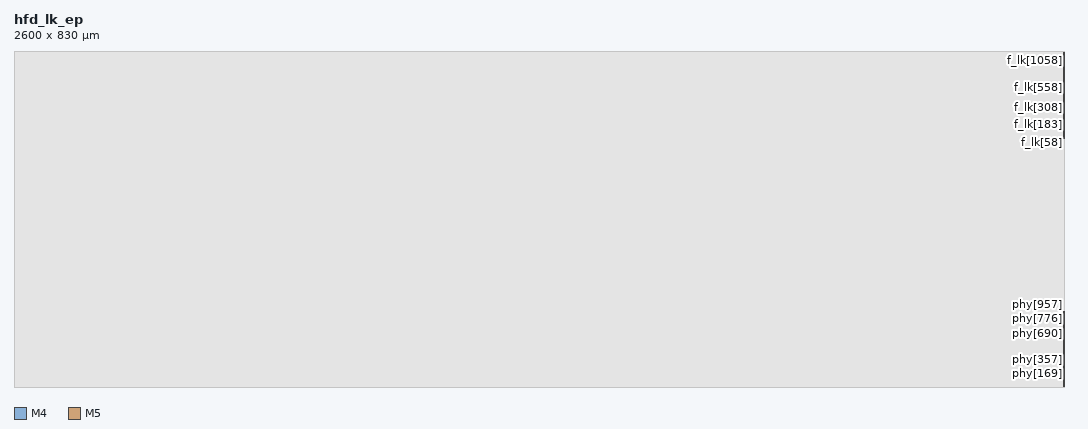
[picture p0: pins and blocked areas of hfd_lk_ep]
MACRO hfd_lk_ep
  CLASS BLOCK ;
  FOREIGN hfd_lk_ep 0 0 ;
  SIZE 2600.000 BY 830.000 ;
  SYMMETRY X Y ;
  PIN phy[0]
    DIRECTION INOUT ;
    USE SIGNAL ;
    PORT
      LAYER M4 ;
        RECT 2599.808 0.624 2600.000 0.648 ;
    END
  END phy[0]
  PIN phy[1]
    DIRECTION INOUT ;
    USE SIGNAL ;
    PORT
      LAYER M4 ;
        RECT 2599.808 0.816 2600.000 0.840 ;
    END
  END phy[1]
  PIN phy[2]
    DIRECTION INOUT ;
    USE SIGNAL ;
    PORT
      LAYER M4 ;
        RECT 2599.808 1.008 2600.000 1.032 ;
    END
  END phy[2]
  PIN phy[3]
    DIRECTION INOUT ;
    USE SIGNAL ;
    PORT
      LAYER M4 ;
        RECT 2599.808 1.200 2600.000 1.224 ;
    END
  END phy[3]
  PIN phy[4]
    DIRECTION INOUT ;
    USE SIGNAL ;
    PORT
      LAYER M4 ;
        RECT 2599.808 1.392 2600.000 1.416 ;
    END
  END phy[4]
  PIN phy[5]
    DIRECTION INOUT ;
    USE SIGNAL ;
    PORT
      LAYER M4 ;
        RECT 2599.808 1.584 2600.000 1.608 ;
    END
  END phy[5]
  PIN phy[6]
    DIRECTION INOUT ;
    USE SIGNAL ;
    PORT
      LAYER M4 ;
        RECT 2599.808 1.776 2600.000 1.800 ;
    END
  END phy[6]
  PIN phy[7]
    DIRECTION INOUT ;
    USE SIGNAL ;
    PORT
      LAYER M4 ;
        RECT 2599.808 1.968 2600.000 1.992 ;
    END
  END phy[7]
  PIN phy[8]
    DIRECTION INOUT ;
    USE SIGNAL ;
    PORT
      LAYER M4 ;
        RECT 2599.808 2.160 2600.000 2.184 ;
    END
  END phy[8]
  PIN phy[9]
    DIRECTION INOUT ;
    USE SIGNAL ;
    PORT
      LAYER M4 ;
        RECT 2599.808 2.352 2600.000 2.376 ;
    END
  END phy[9]
  PIN phy[10]
    DIRECTION INOUT ;
    USE SIGNAL ;
    PORT
      LAYER M4 ;
        RECT 2599.808 2.544 2600.000 2.568 ;
    END
  END phy[10]
  PIN phy[11]
    DIRECTION INOUT ;
    USE SIGNAL ;
    PORT
      LAYER M4 ;
        RECT 2599.808 2.736 2600.000 2.760 ;
    END
  END phy[11]
  PIN phy[12]
    DIRECTION INOUT ;
    USE SIGNAL ;
    PORT
      LAYER M4 ;
        RECT 2599.808 2.928 2600.000 2.952 ;
    END
  END phy[12]
  PIN phy[13]
    DIRECTION INOUT ;
    USE SIGNAL ;
    PORT
      LAYER M4 ;
        RECT 2599.808 3.120 2600.000 3.144 ;
    END
  END phy[13]
  PIN phy[14]
    DIRECTION INOUT ;
    USE SIGNAL ;
    PORT
      LAYER M4 ;
        RECT 2599.808 3.312 2600.000 3.336 ;
    END
  END phy[14]
  PIN phy[15]
    DIRECTION INOUT ;
    USE SIGNAL ;
    PORT
      LAYER M4 ;
        RECT 2599.808 3.504 2600.000 3.528 ;
    END
  END phy[15]
  PIN phy[16]
    DIRECTION INOUT ;
    USE SIGNAL ;
    PORT
      LAYER M4 ;
        RECT 2599.808 3.696 2600.000 3.720 ;
    END
  END phy[16]
  PIN phy[17]
    DIRECTION INOUT ;
    USE SIGNAL ;
    PORT
      LAYER M4 ;
        RECT 2599.808 3.888 2600.000 3.912 ;
    END
  END phy[17]
  PIN phy[18]
    DIRECTION INOUT ;
    USE SIGNAL ;
    PORT
      LAYER M4 ;
        RECT 2599.808 4.080 2600.000 4.104 ;
    END
  END phy[18]
  PIN phy[19]
    DIRECTION INOUT ;
    USE SIGNAL ;
    PORT
      LAYER M4 ;
        RECT 2599.808 4.272 2600.000 4.296 ;
    END
  END phy[19]
  PIN phy[20]
    DIRECTION INOUT ;
    USE SIGNAL ;
    PORT
      LAYER M4 ;
        RECT 2599.808 4.464 2600.000 4.488 ;
    END
  END phy[20]
  PIN phy[21]
    DIRECTION INOUT ;
    USE SIGNAL ;
    PORT
      LAYER M4 ;
        RECT 2599.808 4.656 2600.000 4.680 ;
    END
  END phy[21]
  PIN phy[22]
    DIRECTION INOUT ;
    USE SIGNAL ;
    PORT
      LAYER M4 ;
        RECT 2599.808 4.848 2600.000 4.872 ;
    END
  END phy[22]
  PIN phy[23]
    DIRECTION INOUT ;
    USE SIGNAL ;
    PORT
      LAYER M4 ;
        RECT 2599.808 5.040 2600.000 5.064 ;
    END
  END phy[23]
  PIN phy[24]
    DIRECTION INOUT ;
    USE SIGNAL ;
    PORT
      LAYER M4 ;
        RECT 2599.808 5.232 2600.000 5.256 ;
    END
  END phy[24]
  PIN phy[25]
    DIRECTION INOUT ;
    USE SIGNAL ;
    PORT
      LAYER M4 ;
        RECT 2599.808 5.424 2600.000 5.448 ;
    END
  END phy[25]
  PIN phy[26]
    DIRECTION INOUT ;
    USE SIGNAL ;
    PORT
      LAYER M4 ;
        RECT 2599.808 5.616 2600.000 5.640 ;
    END
  END phy[26]
  PIN phy[27]
    DIRECTION INOUT ;
    USE SIGNAL ;
    PORT
      LAYER M4 ;
        RECT 2599.808 5.808 2600.000 5.832 ;
    END
  END phy[27]
  PIN phy[28]
    DIRECTION INOUT ;
    USE SIGNAL ;
    PORT
      LAYER M4 ;
        RECT 2599.808 6.000 2600.000 6.024 ;
    END
  END phy[28]
  PIN phy[29]
    DIRECTION INOUT ;
    USE SIGNAL ;
    PORT
      LAYER M4 ;
        RECT 2599.808 6.192 2600.000 6.216 ;
    END
  END phy[29]
  PIN phy[30]
    DIRECTION INOUT ;
    USE SIGNAL ;
    PORT
      LAYER M4 ;
        RECT 2599.808 6.384 2600.000 6.408 ;
    END
  END phy[30]
  PIN phy[31]
    DIRECTION INOUT ;
    USE SIGNAL ;
    PORT
      LAYER M4 ;
        RECT 2599.808 6.576 2600.000 6.600 ;
    END
  END phy[31]
  PIN phy[32]
    DIRECTION INOUT ;
    USE SIGNAL ;
    PORT
      LAYER M4 ;
        RECT 2599.808 6.768 2600.000 6.792 ;
    END
  END phy[32]
  PIN phy[33]
    DIRECTION INOUT ;
    USE SIGNAL ;
    PORT
      LAYER M4 ;
        RECT 2599.808 6.960 2600.000 6.984 ;
    END
  END phy[33]
  PIN phy[34]
    DIRECTION INOUT ;
    USE SIGNAL ;
    PORT
      LAYER M4 ;
        RECT 2599.808 7.152 2600.000 7.176 ;
    END
  END phy[34]
  PIN phy[35]
    DIRECTION INOUT ;
    USE SIGNAL ;
    PORT
      LAYER M4 ;
        RECT 2599.808 7.344 2600.000 7.368 ;
    END
  END phy[35]
  PIN phy[36]
    DIRECTION INOUT ;
    USE SIGNAL ;
    PORT
      LAYER M4 ;
        RECT 2599.808 7.536 2600.000 7.560 ;
    END
  END phy[36]
  PIN phy[37]
    DIRECTION INOUT ;
    USE SIGNAL ;
    PORT
      LAYER M4 ;
        RECT 2599.808 7.728 2600.000 7.752 ;
    END
  END phy[37]
  PIN phy[38]
    DIRECTION INOUT ;
    USE SIGNAL ;
    PORT
      LAYER M4 ;
        RECT 2599.808 7.920 2600.000 7.944 ;
    END
  END phy[38]
  PIN phy[39]
    DIRECTION INOUT ;
    USE SIGNAL ;
    PORT
      LAYER M4 ;
        RECT 2599.808 8.112 2600.000 8.136 ;
    END
  END phy[39]
  PIN phy[40]
    DIRECTION INOUT ;
    USE SIGNAL ;
    PORT
      LAYER M4 ;
        RECT 2599.808 8.304 2600.000 8.328 ;
    END
  END phy[40]
  PIN phy[41]
    DIRECTION INOUT ;
    USE SIGNAL ;
    PORT
      LAYER M4 ;
        RECT 2599.808 8.496 2600.000 8.520 ;
    END
  END phy[41]
  PIN phy[42]
    DIRECTION INOUT ;
    USE SIGNAL ;
    PORT
      LAYER M4 ;
        RECT 2599.808 8.688 2600.000 8.712 ;
    END
  END phy[42]
  PIN phy[43]
    DIRECTION INOUT ;
    USE SIGNAL ;
    PORT
      LAYER M4 ;
        RECT 2599.808 8.880 2600.000 8.904 ;
    END
  END phy[43]
  PIN phy[44]
    DIRECTION INOUT ;
    USE SIGNAL ;
    PORT
      LAYER M4 ;
        RECT 2599.808 9.072 2600.000 9.096 ;
    END
  END phy[44]
  PIN phy[45]
    DIRECTION INOUT ;
    USE SIGNAL ;
    PORT
      LAYER M4 ;
        RECT 2599.808 9.264 2600.000 9.288 ;
    END
  END phy[45]
  PIN phy[46]
    DIRECTION INOUT ;
    USE SIGNAL ;
    PORT
      LAYER M4 ;
        RECT 2599.808 9.456 2600.000 9.480 ;
    END
  END phy[46]
  PIN phy[47]
    DIRECTION INOUT ;
    USE SIGNAL ;
    PORT
      LAYER M4 ;
        RECT 2599.808 9.648 2600.000 9.672 ;
    END
  END phy[47]
  PIN phy[48]
    DIRECTION INOUT ;
    USE SIGNAL ;
    PORT
      LAYER M4 ;
        RECT 2599.808 9.840 2600.000 9.864 ;
    END
  END phy[48]
  PIN phy[49]
    DIRECTION INOUT ;
    USE SIGNAL ;
    PORT
      LAYER M4 ;
        RECT 2599.808 10.032 2600.000 10.056 ;
    END
  END phy[49]
  PIN phy[50]
    DIRECTION INOUT ;
    USE SIGNAL ;
    PORT
      LAYER M4 ;
        RECT 2599.808 10.224 2600.000 10.248 ;
    END
  END phy[50]
  PIN phy[51]
    DIRECTION INOUT ;
    USE SIGNAL ;
    PORT
      LAYER M4 ;
        RECT 2599.808 10.416 2600.000 10.440 ;
    END
  END phy[51]
  PIN phy[52]
    DIRECTION INOUT ;
    USE SIGNAL ;
    PORT
      LAYER M4 ;
        RECT 2599.808 10.608 2600.000 10.632 ;
    END
  END phy[52]
  PIN phy[53]
    DIRECTION INOUT ;
    USE SIGNAL ;
    PORT
      LAYER M4 ;
        RECT 2599.808 10.800 2600.000 10.824 ;
    END
  END phy[53]
  PIN phy[54]
    DIRECTION INOUT ;
    USE SIGNAL ;
    PORT
      LAYER M4 ;
        RECT 2599.808 10.992 2600.000 11.016 ;
    END
  END phy[54]
  PIN phy[55]
    DIRECTION INOUT ;
    USE SIGNAL ;
    PORT
      LAYER M4 ;
        RECT 2599.808 11.184 2600.000 11.208 ;
    END
  END phy[55]
  PIN phy[56]
    DIRECTION INOUT ;
    USE SIGNAL ;
    PORT
      LAYER M4 ;
        RECT 2599.808 11.376 2600.000 11.400 ;
    END
  END phy[56]
  PIN phy[57]
    DIRECTION INOUT ;
    USE SIGNAL ;
    PORT
      LAYER M4 ;
        RECT 2599.808 11.568 2600.000 11.592 ;
    END
  END phy[57]
  PIN phy[58]
    DIRECTION INOUT ;
    USE SIGNAL ;
    PORT
      LAYER M4 ;
        RECT 2599.808 11.760 2600.000 11.784 ;
    END
  END phy[58]
  PIN phy[59]
    DIRECTION INOUT ;
    USE SIGNAL ;
    PORT
      LAYER M4 ;
        RECT 2599.808 11.952 2600.000 11.976 ;
    END
  END phy[59]
  PIN phy[60]
    DIRECTION INOUT ;
    USE SIGNAL ;
    PORT
      LAYER M4 ;
        RECT 2599.808 12.144 2600.000 12.168 ;
    END
  END phy[60]
  PIN phy[61]
    DIRECTION INOUT ;
    USE SIGNAL ;
    PORT
      LAYER M4 ;
        RECT 2599.808 12.336 2600.000 12.360 ;
    END
  END phy[61]
  PIN phy[62]
    DIRECTION INOUT ;
    USE SIGNAL ;
    PORT
      LAYER M4 ;
        RECT 2599.808 12.528 2600.000 12.552 ;
    END
  END phy[62]
  PIN phy[63]
    DIRECTION INOUT ;
    USE SIGNAL ;
    PORT
      LAYER M4 ;
        RECT 2599.808 12.720 2600.000 12.744 ;
    END
  END phy[63]
  PIN phy[64]
    DIRECTION INOUT ;
    USE SIGNAL ;
    PORT
      LAYER M4 ;
        RECT 2599.808 12.912 2600.000 12.936 ;
    END
  END phy[64]
  PIN phy[65]
    DIRECTION INOUT ;
    USE SIGNAL ;
    PORT
      LAYER M4 ;
        RECT 2599.808 13.104 2600.000 13.128 ;
    END
  END phy[65]
  PIN phy[66]
    DIRECTION INOUT ;
    USE SIGNAL ;
    PORT
      LAYER M4 ;
        RECT 2599.808 13.296 2600.000 13.320 ;
    END
  END phy[66]
  PIN phy[67]
    DIRECTION INOUT ;
    USE SIGNAL ;
    PORT
      LAYER M4 ;
        RECT 2599.808 13.488 2600.000 13.512 ;
    END
  END phy[67]
  PIN phy[68]
    DIRECTION INOUT ;
    USE SIGNAL ;
    PORT
      LAYER M4 ;
        RECT 2599.808 13.680 2600.000 13.704 ;
    END
  END phy[68]
  PIN phy[69]
    DIRECTION INOUT ;
    USE SIGNAL ;
    PORT
      LAYER M4 ;
        RECT 2599.808 13.872 2600.000 13.896 ;
    END
  END phy[69]
  PIN phy[70]
    DIRECTION INOUT ;
    USE SIGNAL ;
    PORT
      LAYER M4 ;
        RECT 2599.808 14.064 2600.000 14.088 ;
    END
  END phy[70]
  PIN phy[71]
    DIRECTION INOUT ;
    USE SIGNAL ;
    PORT
      LAYER M4 ;
        RECT 2599.808 14.256 2600.000 14.280 ;
    END
  END phy[71]
  PIN phy[72]
    DIRECTION INOUT ;
    USE SIGNAL ;
    PORT
      LAYER M4 ;
        RECT 2599.808 14.448 2600.000 14.472 ;
    END
  END phy[72]
  PIN phy[73]
    DIRECTION INOUT ;
    USE SIGNAL ;
    PORT
      LAYER M4 ;
        RECT 2599.808 14.640 2600.000 14.664 ;
    END
  END phy[73]
  PIN phy[74]
    DIRECTION INOUT ;
    USE SIGNAL ;
    PORT
      LAYER M4 ;
        RECT 2599.808 14.832 2600.000 14.856 ;
    END
  END phy[74]
  PIN phy[75]
    DIRECTION INOUT ;
    USE SIGNAL ;
    PORT
      LAYER M4 ;
        RECT 2599.808 15.024 2600.000 15.048 ;
    END
  END phy[75]
  PIN phy[76]
    DIRECTION INOUT ;
    USE SIGNAL ;
    PORT
      LAYER M4 ;
        RECT 2599.808 15.216 2600.000 15.240 ;
    END
  END phy[76]
  PIN phy[77]
    DIRECTION INOUT ;
    USE SIGNAL ;
    PORT
      LAYER M4 ;
        RECT 2599.808 15.408 2600.000 15.432 ;
    END
  END phy[77]
  PIN phy[78]
    DIRECTION INOUT ;
    USE SIGNAL ;
    PORT
      LAYER M4 ;
        RECT 2599.808 15.600 2600.000 15.624 ;
    END
  END phy[78]
  PIN phy[79]
    DIRECTION INOUT ;
    USE SIGNAL ;
    PORT
      LAYER M4 ;
        RECT 2599.808 15.792 2600.000 15.816 ;
    END
  END phy[79]
  PIN phy[80]
    DIRECTION INOUT ;
    USE SIGNAL ;
    PORT
      LAYER M4 ;
        RECT 2599.808 15.984 2600.000 16.008 ;
    END
  END phy[80]
  PIN phy[81]
    DIRECTION INOUT ;
    USE SIGNAL ;
    PORT
      LAYER M4 ;
        RECT 2599.808 16.176 2600.000 16.200 ;
    END
  END phy[81]
  PIN phy[82]
    DIRECTION INOUT ;
    USE SIGNAL ;
    PORT
      LAYER M4 ;
        RECT 2599.808 16.368 2600.000 16.392 ;
    END
  END phy[82]
  PIN phy[83]
    DIRECTION INOUT ;
    USE SIGNAL ;
    PORT
      LAYER M4 ;
        RECT 2599.808 16.560 2600.000 16.584 ;
    END
  END phy[83]
  PIN phy[84]
    DIRECTION INOUT ;
    USE SIGNAL ;
    PORT
      LAYER M4 ;
        RECT 2599.808 16.752 2600.000 16.776 ;
    END
  END phy[84]
  PIN phy[85]
    DIRECTION INOUT ;
    USE SIGNAL ;
    PORT
      LAYER M4 ;
        RECT 2599.808 16.944 2600.000 16.968 ;
    END
  END phy[85]
  PIN phy[86]
    DIRECTION INOUT ;
    USE SIGNAL ;
    PORT
      LAYER M4 ;
        RECT 2599.808 17.136 2600.000 17.160 ;
    END
  END phy[86]
  PIN phy[87]
    DIRECTION INOUT ;
    USE SIGNAL ;
    PORT
      LAYER M4 ;
        RECT 2599.808 17.328 2600.000 17.352 ;
    END
  END phy[87]
  PIN phy[88]
    DIRECTION INOUT ;
    USE SIGNAL ;
    PORT
      LAYER M4 ;
        RECT 2599.808 17.520 2600.000 17.544 ;
    END
  END phy[88]
  PIN phy[89]
    DIRECTION INOUT ;
    USE SIGNAL ;
    PORT
      LAYER M4 ;
        RECT 2599.808 17.712 2600.000 17.736 ;
    END
  END phy[89]
  PIN phy[90]
    DIRECTION INOUT ;
    USE SIGNAL ;
    PORT
      LAYER M4 ;
        RECT 2599.808 17.904 2600.000 17.928 ;
    END
  END phy[90]
  PIN phy[91]
    DIRECTION INOUT ;
    USE SIGNAL ;
    PORT
      LAYER M4 ;
        RECT 2599.808 18.096 2600.000 18.120 ;
    END
  END phy[91]
  PIN phy[92]
    DIRECTION INOUT ;
    USE SIGNAL ;
    PORT
      LAYER M4 ;
        RECT 2599.808 18.288 2600.000 18.312 ;
    END
  END phy[92]
  PIN phy[93]
    DIRECTION INOUT ;
    USE SIGNAL ;
    PORT
      LAYER M4 ;
        RECT 2599.808 18.480 2600.000 18.504 ;
    END
  END phy[93]
  PIN phy[94]
    DIRECTION INOUT ;
    USE SIGNAL ;
    PORT
      LAYER M4 ;
        RECT 2599.808 18.672 2600.000 18.696 ;
    END
  END phy[94]
  PIN phy[95]
    DIRECTION INOUT ;
    USE SIGNAL ;
    PORT
      LAYER M4 ;
        RECT 2599.808 18.864 2600.000 18.888 ;
    END
  END phy[95]
  PIN phy[96]
    DIRECTION INOUT ;
    USE SIGNAL ;
    PORT
      LAYER M4 ;
        RECT 2599.808 19.056 2600.000 19.080 ;
    END
  END phy[96]
  PIN phy[97]
    DIRECTION INOUT ;
    USE SIGNAL ;
    PORT
      LAYER M4 ;
        RECT 2599.808 19.248 2600.000 19.272 ;
    END
  END phy[97]
  PIN phy[98]
    DIRECTION INOUT ;
    USE SIGNAL ;
    PORT
      LAYER M4 ;
        RECT 2599.808 19.440 2600.000 19.464 ;
    END
  END phy[98]
  PIN phy[99]
    DIRECTION INOUT ;
    USE SIGNAL ;
    PORT
      LAYER M4 ;
        RECT 2599.808 19.632 2600.000 19.656 ;
    END
  END phy[99]
  PIN phy[100]
    DIRECTION INOUT ;
    USE SIGNAL ;
    PORT
      LAYER M4 ;
        RECT 2599.808 19.824 2600.000 19.848 ;
    END
  END phy[100]
  PIN phy[101]
    DIRECTION INOUT ;
    USE SIGNAL ;
    PORT
      LAYER M4 ;
        RECT 2599.808 20.016 2600.000 20.040 ;
    END
  END phy[101]
  PIN phy[102]
    DIRECTION INOUT ;
    USE SIGNAL ;
    PORT
      LAYER M4 ;
        RECT 2599.808 20.208 2600.000 20.232 ;
    END
  END phy[102]
  PIN phy[103]
    DIRECTION INOUT ;
    USE SIGNAL ;
    PORT
      LAYER M4 ;
        RECT 2599.808 20.400 2600.000 20.424 ;
    END
  END phy[103]
  PIN phy[104]
    DIRECTION INOUT ;
    USE SIGNAL ;
    PORT
      LAYER M4 ;
        RECT 2599.808 20.592 2600.000 20.616 ;
    END
  END phy[104]
  PIN phy[105]
    DIRECTION INOUT ;
    USE SIGNAL ;
    PORT
      LAYER M4 ;
        RECT 2599.808 20.784 2600.000 20.808 ;
    END
  END phy[105]
  PIN phy[106]
    DIRECTION INOUT ;
    USE SIGNAL ;
    PORT
      LAYER M4 ;
        RECT 2599.808 20.976 2600.000 21.000 ;
    END
  END phy[106]
  PIN phy[107]
    DIRECTION INOUT ;
    USE SIGNAL ;
    PORT
      LAYER M4 ;
        RECT 2599.808 21.168 2600.000 21.192 ;
    END
  END phy[107]
  PIN phy[108]
    DIRECTION INOUT ;
    USE SIGNAL ;
    PORT
      LAYER M4 ;
        RECT 2599.808 21.360 2600.000 21.384 ;
    END
  END phy[108]
  PIN phy[109]
    DIRECTION INOUT ;
    USE SIGNAL ;
    PORT
      LAYER M4 ;
        RECT 2599.808 21.552 2600.000 21.576 ;
    END
  END phy[109]
  PIN phy[110]
    DIRECTION INOUT ;
    USE SIGNAL ;
    PORT
      LAYER M4 ;
        RECT 2599.808 21.744 2600.000 21.768 ;
    END
  END phy[110]
  PIN phy[111]
    DIRECTION INOUT ;
    USE SIGNAL ;
    PORT
      LAYER M4 ;
        RECT 2599.808 21.936 2600.000 21.960 ;
    END
  END phy[111]
  PIN phy[112]
    DIRECTION INOUT ;
    USE SIGNAL ;
    PORT
      LAYER M4 ;
        RECT 2599.808 22.128 2600.000 22.152 ;
    END
  END phy[112]
  PIN phy[113]
    DIRECTION INOUT ;
    USE SIGNAL ;
    PORT
      LAYER M4 ;
        RECT 2599.808 22.320 2600.000 22.344 ;
    END
  END phy[113]
  PIN phy[114]
    DIRECTION INOUT ;
    USE SIGNAL ;
    PORT
      LAYER M4 ;
        RECT 2599.808 22.512 2600.000 22.536 ;
    END
  END phy[114]
  PIN phy[115]
    DIRECTION INOUT ;
    USE SIGNAL ;
    PORT
      LAYER M4 ;
        RECT 2599.808 22.704 2600.000 22.728 ;
    END
  END phy[115]
  PIN phy[116]
    DIRECTION INOUT ;
    USE SIGNAL ;
    PORT
      LAYER M4 ;
        RECT 2599.808 22.896 2600.000 22.920 ;
    END
  END phy[116]
  PIN phy[117]
    DIRECTION INOUT ;
    USE SIGNAL ;
    PORT
      LAYER M4 ;
        RECT 2599.808 23.088 2600.000 23.112 ;
    END
  END phy[117]
  PIN phy[118]
    DIRECTION INOUT ;
    USE SIGNAL ;
    PORT
      LAYER M4 ;
        RECT 2599.808 23.280 2600.000 23.304 ;
    END
  END phy[118]
  PIN phy[119]
    DIRECTION INOUT ;
    USE SIGNAL ;
    PORT
      LAYER M4 ;
        RECT 2599.808 23.472 2600.000 23.496 ;
    END
  END phy[119]
  PIN phy[120]
    DIRECTION INOUT ;
    USE SIGNAL ;
    PORT
      LAYER M4 ;
        RECT 2599.808 23.664 2600.000 23.688 ;
    END
  END phy[120]
  PIN phy[121]
    DIRECTION INOUT ;
    USE SIGNAL ;
    PORT
      LAYER M4 ;
        RECT 2599.808 23.856 2600.000 23.880 ;
    END
  END phy[121]
  PIN phy[122]
    DIRECTION INOUT ;
    USE SIGNAL ;
    PORT
      LAYER M4 ;
        RECT 2599.808 24.048 2600.000 24.072 ;
    END
  END phy[122]
  PIN phy[123]
    DIRECTION INOUT ;
    USE SIGNAL ;
    PORT
      LAYER M4 ;
        RECT 2599.808 24.240 2600.000 24.264 ;
    END
  END phy[123]
  PIN phy[124]
    DIRECTION INOUT ;
    USE SIGNAL ;
    PORT
      LAYER M4 ;
        RECT 2599.808 24.432 2600.000 24.456 ;
    END
  END phy[124]
  PIN phy[125]
    DIRECTION INOUT ;
    USE SIGNAL ;
    PORT
      LAYER M4 ;
        RECT 2599.808 24.624 2600.000 24.648 ;
    END
  END phy[125]
  PIN phy[126]
    DIRECTION INOUT ;
    USE SIGNAL ;
    PORT
      LAYER M4 ;
        RECT 2599.808 24.816 2600.000 24.840 ;
    END
  END phy[126]
  PIN phy[127]
    DIRECTION INOUT ;
    USE SIGNAL ;
    PORT
      LAYER M4 ;
        RECT 2599.808 25.008 2600.000 25.032 ;
    END
  END phy[127]
  PIN phy[128]
    DIRECTION INOUT ;
    USE SIGNAL ;
    PORT
      LAYER M4 ;
        RECT 2599.808 25.200 2600.000 25.224 ;
    END
  END phy[128]
  PIN phy[129]
    DIRECTION INOUT ;
    USE SIGNAL ;
    PORT
      LAYER M4 ;
        RECT 2599.808 25.392 2600.000 25.416 ;
    END
  END phy[129]
  PIN phy[130]
    DIRECTION INOUT ;
    USE SIGNAL ;
    PORT
      LAYER M4 ;
        RECT 2599.808 25.584 2600.000 25.608 ;
    END
  END phy[130]
  PIN phy[131]
    DIRECTION INOUT ;
    USE SIGNAL ;
    PORT
      LAYER M4 ;
        RECT 2599.808 25.776 2600.000 25.800 ;
    END
  END phy[131]
  PIN phy[132]
    DIRECTION INOUT ;
    USE SIGNAL ;
    PORT
      LAYER M4 ;
        RECT 2599.808 25.968 2600.000 25.992 ;
    END
  END phy[132]
  PIN phy[133]
    DIRECTION INOUT ;
    USE SIGNAL ;
    PORT
      LAYER M4 ;
        RECT 2599.808 26.160 2600.000 26.184 ;
    END
  END phy[133]
  PIN phy[134]
    DIRECTION INOUT ;
    USE SIGNAL ;
    PORT
      LAYER M4 ;
        RECT 2599.808 26.352 2600.000 26.376 ;
    END
  END phy[134]
  PIN phy[135]
    DIRECTION INOUT ;
    USE SIGNAL ;
    PORT
      LAYER M4 ;
        RECT 2599.808 26.544 2600.000 26.568 ;
    END
  END phy[135]
  PIN phy[136]
    DIRECTION INOUT ;
    USE SIGNAL ;
    PORT
      LAYER M4 ;
        RECT 2599.808 26.736 2600.000 26.760 ;
    END
  END phy[136]
  PIN phy[137]
    DIRECTION INOUT ;
    USE SIGNAL ;
    PORT
      LAYER M4 ;
        RECT 2599.808 26.928 2600.000 26.952 ;
    END
  END phy[137]
  PIN phy[138]
    DIRECTION INOUT ;
    USE SIGNAL ;
    PORT
      LAYER M4 ;
        RECT 2599.808 27.120 2600.000 27.144 ;
    END
  END phy[138]
  PIN phy[139]
    DIRECTION INOUT ;
    USE SIGNAL ;
    PORT
      LAYER M4 ;
        RECT 2599.808 27.312 2600.000 27.336 ;
    END
  END phy[139]
  PIN phy[140]
    DIRECTION INOUT ;
    USE SIGNAL ;
    PORT
      LAYER M4 ;
        RECT 2599.808 27.504 2600.000 27.528 ;
    END
  END phy[140]
  PIN phy[141]
    DIRECTION INOUT ;
    USE SIGNAL ;
    PORT
      LAYER M4 ;
        RECT 2599.808 27.696 2600.000 27.720 ;
    END
  END phy[141]
  PIN phy[142]
    DIRECTION INOUT ;
    USE SIGNAL ;
    PORT
      LAYER M4 ;
        RECT 2599.808 27.888 2600.000 27.912 ;
    END
  END phy[142]
  PIN phy[143]
    DIRECTION INOUT ;
    USE SIGNAL ;
    PORT
      LAYER M4 ;
        RECT 2599.808 28.080 2600.000 28.104 ;
    END
  END phy[143]
  PIN phy[144]
    DIRECTION INOUT ;
    USE SIGNAL ;
    PORT
      LAYER M4 ;
        RECT 2599.808 28.272 2600.000 28.296 ;
    END
  END phy[144]
  PIN phy[145]
    DIRECTION INOUT ;
    USE SIGNAL ;
    PORT
      LAYER M4 ;
        RECT 2599.808 28.464 2600.000 28.488 ;
    END
  END phy[145]
  PIN phy[146]
    DIRECTION INOUT ;
    USE SIGNAL ;
    PORT
      LAYER M4 ;
        RECT 2599.808 28.656 2600.000 28.680 ;
    END
  END phy[146]
  PIN phy[147]
    DIRECTION INOUT ;
    USE SIGNAL ;
    PORT
      LAYER M4 ;
        RECT 2599.808 28.848 2600.000 28.872 ;
    END
  END phy[147]
  PIN phy[148]
    DIRECTION INOUT ;
    USE SIGNAL ;
    PORT
      LAYER M4 ;
        RECT 2599.808 29.040 2600.000 29.064 ;
    END
  END phy[148]
  PIN phy[149]
    DIRECTION INOUT ;
    USE SIGNAL ;
    PORT
      LAYER M4 ;
        RECT 2599.808 29.232 2600.000 29.256 ;
    END
  END phy[149]
  PIN phy[150]
    DIRECTION INOUT ;
    USE SIGNAL ;
    PORT
      LAYER M4 ;
        RECT 2599.808 29.424 2600.000 29.448 ;
    END
  END phy[150]
  PIN phy[151]
    DIRECTION INOUT ;
    USE SIGNAL ;
    PORT
      LAYER M4 ;
        RECT 2599.808 29.616 2600.000 29.640 ;
    END
  END phy[151]
  PIN phy[152]
    DIRECTION INOUT ;
    USE SIGNAL ;
    PORT
      LAYER M4 ;
        RECT 2599.808 29.808 2600.000 29.832 ;
    END
  END phy[152]
  PIN phy[153]
    DIRECTION INOUT ;
    USE SIGNAL ;
    PORT
      LAYER M4 ;
        RECT 2599.808 30.000 2600.000 30.024 ;
    END
  END phy[153]
  PIN phy[154]
    DIRECTION INOUT ;
    USE SIGNAL ;
    PORT
      LAYER M4 ;
        RECT 2599.808 30.192 2600.000 30.216 ;
    END
  END phy[154]
  PIN phy[155]
    DIRECTION INOUT ;
    USE SIGNAL ;
    PORT
      LAYER M4 ;
        RECT 2599.808 30.384 2600.000 30.408 ;
    END
  END phy[155]
  PIN phy[156]
    DIRECTION INOUT ;
    USE SIGNAL ;
    PORT
      LAYER M4 ;
        RECT 2599.808 30.576 2600.000 30.600 ;
    END
  END phy[156]
  PIN phy[157]
    DIRECTION INOUT ;
    USE SIGNAL ;
    PORT
      LAYER M4 ;
        RECT 2599.808 30.768 2600.000 30.792 ;
    END
  END phy[157]
  PIN phy[158]
    DIRECTION INOUT ;
    USE SIGNAL ;
    PORT
      LAYER M4 ;
        RECT 2599.808 30.960 2600.000 30.984 ;
    END
  END phy[158]
  PIN phy[159]
    DIRECTION INOUT ;
    USE SIGNAL ;
    PORT
      LAYER M4 ;
        RECT 2599.808 31.152 2600.000 31.176 ;
    END
  END phy[159]
  PIN phy[160]
    DIRECTION INOUT ;
    USE SIGNAL ;
    PORT
      LAYER M4 ;
        RECT 2599.808 31.344 2600.000 31.368 ;
    END
  END phy[160]
  PIN phy[161]
    DIRECTION INOUT ;
    USE SIGNAL ;
    PORT
      LAYER M4 ;
        RECT 2599.808 31.536 2600.000 31.560 ;
    END
  END phy[161]
  PIN phy[162]
    DIRECTION INOUT ;
    USE SIGNAL ;
    PORT
      LAYER M4 ;
        RECT 2599.808 31.728 2600.000 31.752 ;
    END
  END phy[162]
  PIN phy[163]
    DIRECTION INOUT ;
    USE SIGNAL ;
    PORT
      LAYER M4 ;
        RECT 2599.808 31.920 2600.000 31.944 ;
    END
  END phy[163]
  PIN phy[164]
    DIRECTION INOUT ;
    USE SIGNAL ;
    PORT
      LAYER M4 ;
        RECT 2599.808 32.112 2600.000 32.136 ;
    END
  END phy[164]
  PIN phy[165]
    DIRECTION INOUT ;
    USE SIGNAL ;
    PORT
      LAYER M4 ;
        RECT 2599.808 32.304 2600.000 32.328 ;
    END
  END phy[165]
  PIN phy[166]
    DIRECTION INOUT ;
    USE SIGNAL ;
    PORT
      LAYER M4 ;
        RECT 2599.808 32.496 2600.000 32.520 ;
    END
  END phy[166]
  PIN phy[167]
    DIRECTION INOUT ;
    USE SIGNAL ;
    PORT
      LAYER M4 ;
        RECT 2599.808 32.688 2600.000 32.712 ;
    END
  END phy[167]
  PIN phy[168]
    DIRECTION INOUT ;
    USE SIGNAL ;
    PORT
      LAYER M4 ;
        RECT 2599.808 32.880 2600.000 32.904 ;
    END
  END phy[168]
  PIN phy[169]
    DIRECTION INOUT ;
    USE SIGNAL ;
    PORT
      LAYER M4 ;
        RECT 2599.808 33.072 2600.000 33.096 ;
    END
  END phy[169]
  PIN phy[170]
    DIRECTION INOUT ;
    USE SIGNAL ;
    PORT
      LAYER M4 ;
        RECT 2599.808 33.264 2600.000 33.288 ;
    END
  END phy[170]
  PIN phy[171]
    DIRECTION INOUT ;
    USE SIGNAL ;
    PORT
      LAYER M4 ;
        RECT 2599.808 33.456 2600.000 33.480 ;
    END
  END phy[171]
  PIN phy[172]
    DIRECTION INOUT ;
    USE SIGNAL ;
    PORT
      LAYER M4 ;
        RECT 2599.808 33.648 2600.000 33.672 ;
    END
  END phy[172]
  PIN phy[173]
    DIRECTION INOUT ;
    USE SIGNAL ;
    PORT
      LAYER M4 ;
        RECT 2599.808 33.840 2600.000 33.864 ;
    END
  END phy[173]
  PIN phy[174]
    DIRECTION INOUT ;
    USE SIGNAL ;
    PORT
      LAYER M4 ;
        RECT 2599.808 34.032 2600.000 34.056 ;
    END
  END phy[174]
  PIN phy[175]
    DIRECTION INOUT ;
    USE SIGNAL ;
    PORT
      LAYER M4 ;
        RECT 2599.808 34.224 2600.000 34.248 ;
    END
  END phy[175]
  PIN phy[176]
    DIRECTION INOUT ;
    USE SIGNAL ;
    PORT
      LAYER M4 ;
        RECT 2599.808 34.416 2600.000 34.440 ;
    END
  END phy[176]
  PIN phy[177]
    DIRECTION INOUT ;
    USE SIGNAL ;
    PORT
      LAYER M4 ;
        RECT 2599.808 34.608 2600.000 34.632 ;
    END
  END phy[177]
  PIN phy[178]
    DIRECTION INOUT ;
    USE SIGNAL ;
    PORT
      LAYER M4 ;
        RECT 2599.808 34.800 2600.000 34.824 ;
    END
  END phy[178]
  PIN phy[179]
    DIRECTION INOUT ;
    USE SIGNAL ;
    PORT
      LAYER M4 ;
        RECT 2599.808 34.992 2600.000 35.016 ;
    END
  END phy[179]
  PIN phy[180]
    DIRECTION INOUT ;
    USE SIGNAL ;
    PORT
      LAYER M4 ;
        RECT 2599.808 35.184 2600.000 35.208 ;
    END
  END phy[180]
  PIN phy[181]
    DIRECTION INOUT ;
    USE SIGNAL ;
    PORT
      LAYER M4 ;
        RECT 2599.808 35.376 2600.000 35.400 ;
    END
  END phy[181]
  PIN phy[182]
    DIRECTION INOUT ;
    USE SIGNAL ;
    PORT
      LAYER M4 ;
        RECT 2599.808 35.568 2600.000 35.592 ;
    END
  END phy[182]
  PIN phy[183]
    DIRECTION INOUT ;
    USE SIGNAL ;
    PORT
      LAYER M4 ;
        RECT 2599.808 35.760 2600.000 35.784 ;
    END
  END phy[183]
  PIN phy[184]
    DIRECTION INOUT ;
    USE SIGNAL ;
    PORT
      LAYER M4 ;
        RECT 2599.808 35.952 2600.000 35.976 ;
    END
  END phy[184]
  PIN phy[185]
    DIRECTION INOUT ;
    USE SIGNAL ;
    PORT
      LAYER M4 ;
        RECT 2599.808 36.144 2600.000 36.168 ;
    END
  END phy[185]
  PIN phy[186]
    DIRECTION INOUT ;
    USE SIGNAL ;
    PORT
      LAYER M4 ;
        RECT 2599.808 36.336 2600.000 36.360 ;
    END
  END phy[186]
  PIN phy[187]
    DIRECTION INOUT ;
    USE SIGNAL ;
    PORT
      LAYER M4 ;
        RECT 2599.808 36.528 2600.000 36.552 ;
    END
  END phy[187]
  PIN phy[188]
    DIRECTION INOUT ;
    USE SIGNAL ;
    PORT
      LAYER M4 ;
        RECT 2599.808 36.720 2600.000 36.744 ;
    END
  END phy[188]
  PIN phy[189]
    DIRECTION INOUT ;
    USE SIGNAL ;
    PORT
      LAYER M4 ;
        RECT 2599.808 36.912 2600.000 36.936 ;
    END
  END phy[189]
  PIN phy[190]
    DIRECTION INOUT ;
    USE SIGNAL ;
    PORT
      LAYER M4 ;
        RECT 2599.808 37.104 2600.000 37.128 ;
    END
  END phy[190]
  PIN phy[191]
    DIRECTION INOUT ;
    USE SIGNAL ;
    PORT
      LAYER M4 ;
        RECT 2599.808 37.296 2600.000 37.320 ;
    END
  END phy[191]
  PIN phy[192]
    DIRECTION INOUT ;
    USE SIGNAL ;
    PORT
      LAYER M4 ;
        RECT 2599.808 37.488 2600.000 37.512 ;
    END
  END phy[192]
  PIN phy[193]
    DIRECTION INOUT ;
    USE SIGNAL ;
    PORT
      LAYER M4 ;
        RECT 2599.808 37.680 2600.000 37.704 ;
    END
  END phy[193]
  PIN phy[194]
    DIRECTION INOUT ;
    USE SIGNAL ;
    PORT
      LAYER M4 ;
        RECT 2599.808 37.872 2600.000 37.896 ;
    END
  END phy[194]
  PIN phy[195]
    DIRECTION INOUT ;
    USE SIGNAL ;
    PORT
      LAYER M4 ;
        RECT 2599.808 38.064 2600.000 38.088 ;
    END
  END phy[195]
  PIN phy[196]
    DIRECTION INOUT ;
    USE SIGNAL ;
    PORT
      LAYER M4 ;
        RECT 2599.808 38.256 2600.000 38.280 ;
    END
  END phy[196]
  PIN phy[197]
    DIRECTION INOUT ;
    USE SIGNAL ;
    PORT
      LAYER M4 ;
        RECT 2599.808 38.448 2600.000 38.472 ;
    END
  END phy[197]
  PIN phy[198]
    DIRECTION INOUT ;
    USE SIGNAL ;
    PORT
      LAYER M4 ;
        RECT 2599.808 38.640 2600.000 38.664 ;
    END
  END phy[198]
  PIN phy[199]
    DIRECTION INOUT ;
    USE SIGNAL ;
    PORT
      LAYER M4 ;
        RECT 2599.808 38.832 2600.000 38.856 ;
    END
  END phy[199]
  PIN phy[200]
    DIRECTION INOUT ;
    USE SIGNAL ;
    PORT
      LAYER M4 ;
        RECT 2599.808 39.024 2600.000 39.048 ;
    END
  END phy[200]
  PIN phy[201]
    DIRECTION INOUT ;
    USE SIGNAL ;
    PORT
      LAYER M4 ;
        RECT 2599.808 39.216 2600.000 39.240 ;
    END
  END phy[201]
  PIN phy[202]
    DIRECTION INOUT ;
    USE SIGNAL ;
    PORT
      LAYER M4 ;
        RECT 2599.808 39.408 2600.000 39.432 ;
    END
  END phy[202]
  PIN phy[203]
    DIRECTION INOUT ;
    USE SIGNAL ;
    PORT
      LAYER M4 ;
        RECT 2599.808 39.600 2600.000 39.624 ;
    END
  END phy[203]
  PIN phy[204]
    DIRECTION INOUT ;
    USE SIGNAL ;
    PORT
      LAYER M4 ;
        RECT 2599.808 39.792 2600.000 39.816 ;
    END
  END phy[204]
  PIN phy[205]
    DIRECTION INOUT ;
    USE SIGNAL ;
    PORT
      LAYER M4 ;
        RECT 2599.808 39.984 2600.000 40.008 ;
    END
  END phy[205]
  PIN phy[206]
    DIRECTION INOUT ;
    USE SIGNAL ;
    PORT
      LAYER M4 ;
        RECT 2599.808 40.176 2600.000 40.200 ;
    END
  END phy[206]
  PIN phy[207]
    DIRECTION INOUT ;
    USE SIGNAL ;
    PORT
      LAYER M4 ;
        RECT 2599.808 40.368 2600.000 40.392 ;
    END
  END phy[207]
  PIN phy[208]
    DIRECTION INOUT ;
    USE SIGNAL ;
    PORT
      LAYER M4 ;
        RECT 2599.808 40.560 2600.000 40.584 ;
    END
  END phy[208]
  PIN phy[209]
    DIRECTION INOUT ;
    USE SIGNAL ;
    PORT
      LAYER M4 ;
        RECT 2599.808 40.752 2600.000 40.776 ;
    END
  END phy[209]
  PIN phy[210]
    DIRECTION INOUT ;
    USE SIGNAL ;
    PORT
      LAYER M4 ;
        RECT 2599.808 40.944 2600.000 40.968 ;
    END
  END phy[210]
  PIN phy[211]
    DIRECTION INOUT ;
    USE SIGNAL ;
    PORT
      LAYER M4 ;
        RECT 2599.808 41.136 2600.000 41.160 ;
    END
  END phy[211]
  PIN phy[212]
    DIRECTION INOUT ;
    USE SIGNAL ;
    PORT
      LAYER M4 ;
        RECT 2599.808 41.328 2600.000 41.352 ;
    END
  END phy[212]
  PIN phy[213]
    DIRECTION INOUT ;
    USE SIGNAL ;
    PORT
      LAYER M4 ;
        RECT 2599.808 41.520 2600.000 41.544 ;
    END
  END phy[213]
  PIN phy[214]
    DIRECTION INOUT ;
    USE SIGNAL ;
    PORT
      LAYER M4 ;
        RECT 2599.808 41.712 2600.000 41.736 ;
    END
  END phy[214]
  PIN phy[215]
    DIRECTION INOUT ;
    USE SIGNAL ;
    PORT
      LAYER M4 ;
        RECT 2599.808 41.904 2600.000 41.928 ;
    END
  END phy[215]
  PIN phy[216]
    DIRECTION INOUT ;
    USE SIGNAL ;
    PORT
      LAYER M4 ;
        RECT 2599.808 42.096 2600.000 42.120 ;
    END
  END phy[216]
  PIN phy[217]
    DIRECTION INOUT ;
    USE SIGNAL ;
    PORT
      LAYER M4 ;
        RECT 2599.808 42.288 2600.000 42.312 ;
    END
  END phy[217]
  PIN phy[218]
    DIRECTION INOUT ;
    USE SIGNAL ;
    PORT
      LAYER M4 ;
        RECT 2599.808 42.480 2600.000 42.504 ;
    END
  END phy[218]
  PIN phy[219]
    DIRECTION INOUT ;
    USE SIGNAL ;
    PORT
      LAYER M4 ;
        RECT 2599.808 42.672 2600.000 42.696 ;
    END
  END phy[219]
  PIN phy[220]
    DIRECTION INOUT ;
    USE SIGNAL ;
    PORT
      LAYER M4 ;
        RECT 2599.808 42.864 2600.000 42.888 ;
    END
  END phy[220]
  PIN phy[221]
    DIRECTION INOUT ;
    USE SIGNAL ;
    PORT
      LAYER M4 ;
        RECT 2599.808 43.056 2600.000 43.080 ;
    END
  END phy[221]
  PIN phy[222]
    DIRECTION INOUT ;
    USE SIGNAL ;
    PORT
      LAYER M4 ;
        RECT 2599.808 43.248 2600.000 43.272 ;
    END
  END phy[222]
  PIN phy[223]
    DIRECTION INOUT ;
    USE SIGNAL ;
    PORT
      LAYER M4 ;
        RECT 2599.808 43.440 2600.000 43.464 ;
    END
  END phy[223]
  PIN phy[224]
    DIRECTION INOUT ;
    USE SIGNAL ;
    PORT
      LAYER M4 ;
        RECT 2599.808 43.632 2600.000 43.656 ;
    END
  END phy[224]
  PIN phy[225]
    DIRECTION INOUT ;
    USE SIGNAL ;
    PORT
      LAYER M4 ;
        RECT 2599.808 43.824 2600.000 43.848 ;
    END
  END phy[225]
  PIN phy[226]
    DIRECTION INOUT ;
    USE SIGNAL ;
    PORT
      LAYER M4 ;
        RECT 2599.808 44.016 2600.000 44.040 ;
    END
  END phy[226]
  PIN phy[227]
    DIRECTION INOUT ;
    USE SIGNAL ;
    PORT
      LAYER M4 ;
        RECT 2599.808 44.208 2600.000 44.232 ;
    END
  END phy[227]
  PIN phy[228]
    DIRECTION INOUT ;
    USE SIGNAL ;
    PORT
      LAYER M4 ;
        RECT 2599.808 44.400 2600.000 44.424 ;
    END
  END phy[228]
  PIN phy[229]
    DIRECTION INOUT ;
    USE SIGNAL ;
    PORT
      LAYER M4 ;
        RECT 2599.808 44.592 2600.000 44.616 ;
    END
  END phy[229]
  PIN phy[230]
    DIRECTION INOUT ;
    USE SIGNAL ;
    PORT
      LAYER M4 ;
        RECT 2599.808 44.784 2600.000 44.808 ;
    END
  END phy[230]
  PIN phy[231]
    DIRECTION INOUT ;
    USE SIGNAL ;
    PORT
      LAYER M4 ;
        RECT 2599.808 44.976 2600.000 45.000 ;
    END
  END phy[231]
  PIN phy[232]
    DIRECTION INOUT ;
    USE SIGNAL ;
    PORT
      LAYER M4 ;
        RECT 2599.808 45.168 2600.000 45.192 ;
    END
  END phy[232]
  PIN phy[233]
    DIRECTION INOUT ;
    USE SIGNAL ;
    PORT
      LAYER M4 ;
        RECT 2599.808 45.360 2600.000 45.384 ;
    END
  END phy[233]
  PIN phy[234]
    DIRECTION INOUT ;
    USE SIGNAL ;
    PORT
      LAYER M4 ;
        RECT 2599.808 45.552 2600.000 45.576 ;
    END
  END phy[234]
  PIN phy[235]
    DIRECTION INOUT ;
    USE SIGNAL ;
    PORT
      LAYER M4 ;
        RECT 2599.808 45.744 2600.000 45.768 ;
    END
  END phy[235]
  PIN phy[236]
    DIRECTION INOUT ;
    USE SIGNAL ;
    PORT
      LAYER M4 ;
        RECT 2599.808 45.936 2600.000 45.960 ;
    END
  END phy[236]
  PIN phy[237]
    DIRECTION INOUT ;
    USE SIGNAL ;
    PORT
      LAYER M4 ;
        RECT 2599.808 46.128 2600.000 46.152 ;
    END
  END phy[237]
  PIN phy[238]
    DIRECTION INOUT ;
    USE SIGNAL ;
    PORT
      LAYER M4 ;
        RECT 2599.808 46.320 2600.000 46.344 ;
    END
  END phy[238]
  PIN phy[239]
    DIRECTION INOUT ;
    USE SIGNAL ;
    PORT
      LAYER M4 ;
        RECT 2599.808 46.512 2600.000 46.536 ;
    END
  END phy[239]
  PIN phy[240]
    DIRECTION INOUT ;
    USE SIGNAL ;
    PORT
      LAYER M4 ;
        RECT 2599.808 46.704 2600.000 46.728 ;
    END
  END phy[240]
  PIN phy[241]
    DIRECTION INOUT ;
    USE SIGNAL ;
    PORT
      LAYER M4 ;
        RECT 2599.808 46.896 2600.000 46.920 ;
    END
  END phy[241]
  PIN phy[242]
    DIRECTION INOUT ;
    USE SIGNAL ;
    PORT
      LAYER M4 ;
        RECT 2599.808 47.088 2600.000 47.112 ;
    END
  END phy[242]
  PIN phy[243]
    DIRECTION INOUT ;
    USE SIGNAL ;
    PORT
      LAYER M4 ;
        RECT 2599.808 47.280 2600.000 47.304 ;
    END
  END phy[243]
  PIN phy[244]
    DIRECTION INOUT ;
    USE SIGNAL ;
    PORT
      LAYER M4 ;
        RECT 2599.808 47.472 2600.000 47.496 ;
    END
  END phy[244]
  PIN phy[245]
    DIRECTION INOUT ;
    USE SIGNAL ;
    PORT
      LAYER M4 ;
        RECT 2599.808 47.664 2600.000 47.688 ;
    END
  END phy[245]
  PIN phy[246]
    DIRECTION INOUT ;
    USE SIGNAL ;
    PORT
      LAYER M4 ;
        RECT 2599.808 47.856 2600.000 47.880 ;
    END
  END phy[246]
  PIN phy[247]
    DIRECTION INOUT ;
    USE SIGNAL ;
    PORT
      LAYER M4 ;
        RECT 2599.808 48.048 2600.000 48.072 ;
    END
  END phy[247]
  PIN phy[248]
    DIRECTION INOUT ;
    USE SIGNAL ;
    PORT
      LAYER M4 ;
        RECT 2599.808 48.240 2600.000 48.264 ;
    END
  END phy[248]
  PIN phy[249]
    DIRECTION INOUT ;
    USE SIGNAL ;
    PORT
      LAYER M4 ;
        RECT 2599.808 48.432 2600.000 48.456 ;
    END
  END phy[249]
  PIN phy[250]
    DIRECTION INOUT ;
    USE SIGNAL ;
    PORT
      LAYER M4 ;
        RECT 2599.808 48.624 2600.000 48.648 ;
    END
  END phy[250]
  PIN phy[251]
    DIRECTION INOUT ;
    USE SIGNAL ;
    PORT
      LAYER M4 ;
        RECT 2599.808 48.816 2600.000 48.840 ;
    END
  END phy[251]
  PIN phy[252]
    DIRECTION INOUT ;
    USE SIGNAL ;
    PORT
      LAYER M4 ;
        RECT 2599.808 49.008 2600.000 49.032 ;
    END
  END phy[252]
  PIN phy[253]
    DIRECTION INOUT ;
    USE SIGNAL ;
    PORT
      LAYER M4 ;
        RECT 2599.808 49.200 2600.000 49.224 ;
    END
  END phy[253]
  PIN phy[254]
    DIRECTION INOUT ;
    USE SIGNAL ;
    PORT
      LAYER M4 ;
        RECT 2599.808 49.392 2600.000 49.416 ;
    END
  END phy[254]
  PIN phy[255]
    DIRECTION INOUT ;
    USE SIGNAL ;
    PORT
      LAYER M4 ;
        RECT 2599.808 49.584 2600.000 49.608 ;
    END
  END phy[255]
  PIN phy[256]
    DIRECTION INOUT ;
    USE SIGNAL ;
    PORT
      LAYER M4 ;
        RECT 2599.808 49.776 2600.000 49.800 ;
    END
  END phy[256]
  PIN phy[257]
    DIRECTION INOUT ;
    USE SIGNAL ;
    PORT
      LAYER M4 ;
        RECT 2599.808 49.968 2600.000 49.992 ;
    END
  END phy[257]
  PIN phy[258]
    DIRECTION INOUT ;
    USE SIGNAL ;
    PORT
      LAYER M4 ;
        RECT 2599.808 50.160 2600.000 50.184 ;
    END
  END phy[258]
  PIN phy[259]
    DIRECTION INOUT ;
    USE SIGNAL ;
    PORT
      LAYER M4 ;
        RECT 2599.808 50.352 2600.000 50.376 ;
    END
  END phy[259]
  PIN phy[260]
    DIRECTION INOUT ;
    USE SIGNAL ;
    PORT
      LAYER M4 ;
        RECT 2599.808 50.544 2600.000 50.568 ;
    END
  END phy[260]
  PIN phy[261]
    DIRECTION INOUT ;
    USE SIGNAL ;
    PORT
      LAYER M4 ;
        RECT 2599.808 50.736 2600.000 50.760 ;
    END
  END phy[261]
  PIN phy[262]
    DIRECTION INOUT ;
    USE SIGNAL ;
    PORT
      LAYER M4 ;
        RECT 2599.808 50.928 2600.000 50.952 ;
    END
  END phy[262]
  PIN phy[263]
    DIRECTION INOUT ;
    USE SIGNAL ;
    PORT
      LAYER M4 ;
        RECT 2599.808 51.120 2600.000 51.144 ;
    END
  END phy[263]
  PIN phy[264]
    DIRECTION INOUT ;
    USE SIGNAL ;
    PORT
      LAYER M4 ;
        RECT 2599.808 51.312 2600.000 51.336 ;
    END
  END phy[264]
  PIN phy[265]
    DIRECTION INOUT ;
    USE SIGNAL ;
    PORT
      LAYER M4 ;
        RECT 2599.808 51.504 2600.000 51.528 ;
    END
  END phy[265]
  PIN phy[266]
    DIRECTION INOUT ;
    USE SIGNAL ;
    PORT
      LAYER M4 ;
        RECT 2599.808 51.696 2600.000 51.720 ;
    END
  END phy[266]
  PIN phy[267]
    DIRECTION INOUT ;
    USE SIGNAL ;
    PORT
      LAYER M4 ;
        RECT 2599.808 51.888 2600.000 51.912 ;
    END
  END phy[267]
  PIN phy[268]
    DIRECTION INOUT ;
    USE SIGNAL ;
    PORT
      LAYER M4 ;
        RECT 2599.808 52.080 2600.000 52.104 ;
    END
  END phy[268]
  PIN phy[269]
    DIRECTION INOUT ;
    USE SIGNAL ;
    PORT
      LAYER M4 ;
        RECT 2599.808 52.272 2600.000 52.296 ;
    END
  END phy[269]
  PIN phy[270]
    DIRECTION INOUT ;
    USE SIGNAL ;
    PORT
      LAYER M4 ;
        RECT 2599.808 52.464 2600.000 52.488 ;
    END
  END phy[270]
  PIN phy[271]
    DIRECTION INOUT ;
    USE SIGNAL ;
    PORT
      LAYER M4 ;
        RECT 2599.808 52.656 2600.000 52.680 ;
    END
  END phy[271]
  PIN phy[272]
    DIRECTION INOUT ;
    USE SIGNAL ;
    PORT
      LAYER M4 ;
        RECT 2599.808 52.848 2600.000 52.872 ;
    END
  END phy[272]
  PIN phy[273]
    DIRECTION INOUT ;
    USE SIGNAL ;
    PORT
      LAYER M4 ;
        RECT 2599.808 53.040 2600.000 53.064 ;
    END
  END phy[273]
  PIN phy[274]
    DIRECTION INOUT ;
    USE SIGNAL ;
    PORT
      LAYER M4 ;
        RECT 2599.808 53.232 2600.000 53.256 ;
    END
  END phy[274]
  PIN phy[275]
    DIRECTION INOUT ;
    USE SIGNAL ;
    PORT
      LAYER M4 ;
        RECT 2599.808 53.424 2600.000 53.448 ;
    END
  END phy[275]
  PIN phy[276]
    DIRECTION INOUT ;
    USE SIGNAL ;
    PORT
      LAYER M4 ;
        RECT 2599.808 53.616 2600.000 53.640 ;
    END
  END phy[276]
  PIN phy[277]
    DIRECTION INOUT ;
    USE SIGNAL ;
    PORT
      LAYER M4 ;
        RECT 2599.808 53.808 2600.000 53.832 ;
    END
  END phy[277]
  PIN phy[278]
    DIRECTION INOUT ;
    USE SIGNAL ;
    PORT
      LAYER M4 ;
        RECT 2599.808 54.000 2600.000 54.024 ;
    END
  END phy[278]
  PIN phy[279]
    DIRECTION INOUT ;
    USE SIGNAL ;
    PORT
      LAYER M4 ;
        RECT 2599.808 54.192 2600.000 54.216 ;
    END
  END phy[279]
  PIN phy[280]
    DIRECTION INOUT ;
    USE SIGNAL ;
    PORT
      LAYER M4 ;
        RECT 2599.808 54.384 2600.000 54.408 ;
    END
  END phy[280]
  PIN phy[281]
    DIRECTION INOUT ;
    USE SIGNAL ;
    PORT
      LAYER M4 ;
        RECT 2599.808 54.576 2600.000 54.600 ;
    END
  END phy[281]
  PIN phy[282]
    DIRECTION INOUT ;
    USE SIGNAL ;
    PORT
      LAYER M4 ;
        RECT 2599.808 54.768 2600.000 54.792 ;
    END
  END phy[282]
  PIN phy[283]
    DIRECTION INOUT ;
    USE SIGNAL ;
    PORT
      LAYER M4 ;
        RECT 2599.808 54.960 2600.000 54.984 ;
    END
  END phy[283]
  PIN phy[284]
    DIRECTION INOUT ;
    USE SIGNAL ;
    PORT
      LAYER M4 ;
        RECT 2599.808 55.152 2600.000 55.176 ;
    END
  END phy[284]
  PIN phy[285]
    DIRECTION INOUT ;
    USE SIGNAL ;
    PORT
      LAYER M4 ;
        RECT 2599.808 55.344 2600.000 55.368 ;
    END
  END phy[285]
  PIN phy[286]
    DIRECTION INOUT ;
    USE SIGNAL ;
    PORT
      LAYER M4 ;
        RECT 2599.808 55.536 2600.000 55.560 ;
    END
  END phy[286]
  PIN phy[287]
    DIRECTION INOUT ;
    USE SIGNAL ;
    PORT
      LAYER M4 ;
        RECT 2599.808 55.728 2600.000 55.752 ;
    END
  END phy[287]
  PIN phy[288]
    DIRECTION INOUT ;
    USE SIGNAL ;
    PORT
      LAYER M4 ;
        RECT 2599.808 55.920 2600.000 55.944 ;
    END
  END phy[288]
  PIN phy[289]
    DIRECTION INOUT ;
    USE SIGNAL ;
    PORT
      LAYER M4 ;
        RECT 2599.808 56.112 2600.000 56.136 ;
    END
  END phy[289]
  PIN phy[290]
    DIRECTION INOUT ;
    USE SIGNAL ;
    PORT
      LAYER M4 ;
        RECT 2599.808 56.304 2600.000 56.328 ;
    END
  END phy[290]
  PIN phy[291]
    DIRECTION INOUT ;
    USE SIGNAL ;
    PORT
      LAYER M4 ;
        RECT 2599.808 56.496 2600.000 56.520 ;
    END
  END phy[291]
  PIN phy[292]
    DIRECTION INOUT ;
    USE SIGNAL ;
    PORT
      LAYER M4 ;
        RECT 2599.808 56.688 2600.000 56.712 ;
    END
  END phy[292]
  PIN phy[293]
    DIRECTION INOUT ;
    USE SIGNAL ;
    PORT
      LAYER M4 ;
        RECT 2599.808 56.880 2600.000 56.904 ;
    END
  END phy[293]
  PIN phy[294]
    DIRECTION INOUT ;
    USE SIGNAL ;
    PORT
      LAYER M4 ;
        RECT 2599.808 57.072 2600.000 57.096 ;
    END
  END phy[294]
  PIN phy[295]
    DIRECTION INOUT ;
    USE SIGNAL ;
    PORT
      LAYER M4 ;
        RECT 2599.808 57.264 2600.000 57.288 ;
    END
  END phy[295]
  PIN phy[296]
    DIRECTION INOUT ;
    USE SIGNAL ;
    PORT
      LAYER M4 ;
        RECT 2599.808 57.456 2600.000 57.480 ;
    END
  END phy[296]
  PIN phy[297]
    DIRECTION INOUT ;
    USE SIGNAL ;
    PORT
      LAYER M4 ;
        RECT 2599.808 57.648 2600.000 57.672 ;
    END
  END phy[297]
  PIN phy[298]
    DIRECTION INOUT ;
    USE SIGNAL ;
    PORT
      LAYER M4 ;
        RECT 2599.808 57.840 2600.000 57.864 ;
    END
  END phy[298]
  PIN phy[299]
    DIRECTION INOUT ;
    USE SIGNAL ;
    PORT
      LAYER M4 ;
        RECT 2599.808 58.032 2600.000 58.056 ;
    END
  END phy[299]
  PIN phy[300]
    DIRECTION INOUT ;
    USE SIGNAL ;
    PORT
      LAYER M4 ;
        RECT 2599.808 58.224 2600.000 58.248 ;
    END
  END phy[300]
  PIN phy[301]
    DIRECTION INOUT ;
    USE SIGNAL ;
    PORT
      LAYER M4 ;
        RECT 2599.808 58.416 2600.000 58.440 ;
    END
  END phy[301]
  PIN phy[302]
    DIRECTION INOUT ;
    USE SIGNAL ;
    PORT
      LAYER M4 ;
        RECT 2599.808 58.608 2600.000 58.632 ;
    END
  END phy[302]
  PIN phy[303]
    DIRECTION INOUT ;
    USE SIGNAL ;
    PORT
      LAYER M4 ;
        RECT 2599.808 58.800 2600.000 58.824 ;
    END
  END phy[303]
  PIN phy[304]
    DIRECTION INOUT ;
    USE SIGNAL ;
    PORT
      LAYER M4 ;
        RECT 2599.808 58.992 2600.000 59.016 ;
    END
  END phy[304]
  PIN phy[305]
    DIRECTION INOUT ;
    USE SIGNAL ;
    PORT
      LAYER M4 ;
        RECT 2599.808 59.184 2600.000 59.208 ;
    END
  END phy[305]
  PIN phy[306]
    DIRECTION INOUT ;
    USE SIGNAL ;
    PORT
      LAYER M4 ;
        RECT 2599.808 59.376 2600.000 59.400 ;
    END
  END phy[306]
  PIN phy[307]
    DIRECTION INOUT ;
    USE SIGNAL ;
    PORT
      LAYER M4 ;
        RECT 2599.808 59.568 2600.000 59.592 ;
    END
  END phy[307]
  PIN phy[308]
    DIRECTION INOUT ;
    USE SIGNAL ;
    PORT
      LAYER M4 ;
        RECT 2599.808 59.760 2600.000 59.784 ;
    END
  END phy[308]
  PIN phy[309]
    DIRECTION INOUT ;
    USE SIGNAL ;
    PORT
      LAYER M4 ;
        RECT 2599.808 59.952 2600.000 59.976 ;
    END
  END phy[309]
  PIN phy[310]
    DIRECTION INOUT ;
    USE SIGNAL ;
    PORT
      LAYER M4 ;
        RECT 2599.808 60.144 2600.000 60.168 ;
    END
  END phy[310]
  PIN phy[311]
    DIRECTION INOUT ;
    USE SIGNAL ;
    PORT
      LAYER M4 ;
        RECT 2599.808 60.336 2600.000 60.360 ;
    END
  END phy[311]
  PIN phy[312]
    DIRECTION INOUT ;
    USE SIGNAL ;
    PORT
      LAYER M4 ;
        RECT 2599.808 60.528 2600.000 60.552 ;
    END
  END phy[312]
  PIN phy[313]
    DIRECTION INOUT ;
    USE SIGNAL ;
    PORT
      LAYER M4 ;
        RECT 2599.808 60.720 2600.000 60.744 ;
    END
  END phy[313]
  PIN phy[314]
    DIRECTION INOUT ;
    USE SIGNAL ;
    PORT
      LAYER M4 ;
        RECT 2599.808 60.912 2600.000 60.936 ;
    END
  END phy[314]
  PIN phy[315]
    DIRECTION INOUT ;
    USE SIGNAL ;
    PORT
      LAYER M4 ;
        RECT 2599.808 61.104 2600.000 61.128 ;
    END
  END phy[315]
  PIN phy[316]
    DIRECTION INOUT ;
    USE SIGNAL ;
    PORT
      LAYER M4 ;
        RECT 2599.808 61.296 2600.000 61.320 ;
    END
  END phy[316]
  PIN phy[317]
    DIRECTION INOUT ;
    USE SIGNAL ;
    PORT
      LAYER M4 ;
        RECT 2599.808 61.488 2600.000 61.512 ;
    END
  END phy[317]
  PIN phy[318]
    DIRECTION INOUT ;
    USE SIGNAL ;
    PORT
      LAYER M4 ;
        RECT 2599.808 61.680 2600.000 61.704 ;
    END
  END phy[318]
  PIN phy[319]
    DIRECTION INOUT ;
    USE SIGNAL ;
    PORT
      LAYER M4 ;
        RECT 2599.808 61.872 2600.000 61.896 ;
    END
  END phy[319]
  PIN phy[320]
    DIRECTION INOUT ;
    USE SIGNAL ;
    PORT
      LAYER M4 ;
        RECT 2599.808 62.064 2600.000 62.088 ;
    END
  END phy[320]
  PIN phy[321]
    DIRECTION INOUT ;
    USE SIGNAL ;
    PORT
      LAYER M4 ;
        RECT 2599.808 62.256 2600.000 62.280 ;
    END
  END phy[321]
  PIN phy[322]
    DIRECTION INOUT ;
    USE SIGNAL ;
    PORT
      LAYER M4 ;
        RECT 2599.808 62.448 2600.000 62.472 ;
    END
  END phy[322]
  PIN phy[323]
    DIRECTION INOUT ;
    USE SIGNAL ;
    PORT
      LAYER M4 ;
        RECT 2599.808 62.640 2600.000 62.664 ;
    END
  END phy[323]
  PIN phy[324]
    DIRECTION INOUT ;
    USE SIGNAL ;
    PORT
      LAYER M4 ;
        RECT 2599.808 62.832 2600.000 62.856 ;
    END
  END phy[324]
  PIN phy[325]
    DIRECTION INOUT ;
    USE SIGNAL ;
    PORT
      LAYER M4 ;
        RECT 2599.808 63.024 2600.000 63.048 ;
    END
  END phy[325]
  PIN phy[326]
    DIRECTION INOUT ;
    USE SIGNAL ;
    PORT
      LAYER M4 ;
        RECT 2599.808 63.216 2600.000 63.240 ;
    END
  END phy[326]
  PIN phy[327]
    DIRECTION INOUT ;
    USE SIGNAL ;
    PORT
      LAYER M4 ;
        RECT 2599.808 63.408 2600.000 63.432 ;
    END
  END phy[327]
  PIN phy[328]
    DIRECTION INOUT ;
    USE SIGNAL ;
    PORT
      LAYER M4 ;
        RECT 2599.808 63.600 2600.000 63.624 ;
    END
  END phy[328]
  PIN phy[329]
    DIRECTION INOUT ;
    USE SIGNAL ;
    PORT
      LAYER M4 ;
        RECT 2599.808 63.792 2600.000 63.816 ;
    END
  END phy[329]
  PIN phy[330]
    DIRECTION INOUT ;
    USE SIGNAL ;
    PORT
      LAYER M4 ;
        RECT 2599.808 63.984 2600.000 64.008 ;
    END
  END phy[330]
  PIN phy[331]
    DIRECTION INOUT ;
    USE SIGNAL ;
    PORT
      LAYER M4 ;
        RECT 2599.808 64.176 2600.000 64.200 ;
    END
  END phy[331]
  PIN phy[332]
    DIRECTION INOUT ;
    USE SIGNAL ;
    PORT
      LAYER M4 ;
        RECT 2599.808 64.368 2600.000 64.392 ;
    END
  END phy[332]
  PIN phy[333]
    DIRECTION INOUT ;
    USE SIGNAL ;
    PORT
      LAYER M4 ;
        RECT 2599.808 64.560 2600.000 64.584 ;
    END
  END phy[333]
  PIN phy[334]
    DIRECTION INOUT ;
    USE SIGNAL ;
    PORT
      LAYER M4 ;
        RECT 2599.808 64.752 2600.000 64.776 ;
    END
  END phy[334]
  PIN phy[335]
    DIRECTION INOUT ;
    USE SIGNAL ;
    PORT
      LAYER M4 ;
        RECT 2599.808 64.944 2600.000 64.968 ;
    END
  END phy[335]
  PIN phy[336]
    DIRECTION INOUT ;
    USE SIGNAL ;
    PORT
      LAYER M4 ;
        RECT 2599.808 65.136 2600.000 65.160 ;
    END
  END phy[336]
  PIN phy[337]
    DIRECTION INOUT ;
    USE SIGNAL ;
    PORT
      LAYER M4 ;
        RECT 2599.808 65.328 2600.000 65.352 ;
    END
  END phy[337]
  PIN phy[338]
    DIRECTION INOUT ;
    USE SIGNAL ;
    PORT
      LAYER M4 ;
        RECT 2599.808 65.520 2600.000 65.544 ;
    END
  END phy[338]
  PIN phy[339]
    DIRECTION INOUT ;
    USE SIGNAL ;
    PORT
      LAYER M4 ;
        RECT 2599.808 65.712 2600.000 65.736 ;
    END
  END phy[339]
  PIN phy[340]
    DIRECTION INOUT ;
    USE SIGNAL ;
    PORT
      LAYER M4 ;
        RECT 2599.808 65.904 2600.000 65.928 ;
    END
  END phy[340]
  PIN phy[341]
    DIRECTION INOUT ;
    USE SIGNAL ;
    PORT
      LAYER M4 ;
        RECT 2599.808 66.096 2600.000 66.120 ;
    END
  END phy[341]
  PIN phy[342]
    DIRECTION INOUT ;
    USE SIGNAL ;
    PORT
      LAYER M4 ;
        RECT 2599.808 66.288 2600.000 66.312 ;
    END
  END phy[342]
  PIN phy[343]
    DIRECTION INOUT ;
    USE SIGNAL ;
    PORT
      LAYER M4 ;
        RECT 2599.808 66.480 2600.000 66.504 ;
    END
  END phy[343]
  PIN phy[344]
    DIRECTION INOUT ;
    USE SIGNAL ;
    PORT
      LAYER M4 ;
        RECT 2599.808 66.672 2600.000 66.696 ;
    END
  END phy[344]
  PIN phy[345]
    DIRECTION INOUT ;
    USE SIGNAL ;
    PORT
      LAYER M4 ;
        RECT 2599.808 66.864 2600.000 66.888 ;
    END
  END phy[345]
  PIN phy[346]
    DIRECTION INOUT ;
    USE SIGNAL ;
    PORT
      LAYER M4 ;
        RECT 2599.808 67.056 2600.000 67.080 ;
    END
  END phy[346]
  PIN phy[347]
    DIRECTION INOUT ;
    USE SIGNAL ;
    PORT
      LAYER M4 ;
        RECT 2599.808 67.248 2600.000 67.272 ;
    END
  END phy[347]
  PIN phy[348]
    DIRECTION INOUT ;
    USE SIGNAL ;
    PORT
      LAYER M4 ;
        RECT 2599.808 67.440 2600.000 67.464 ;
    END
  END phy[348]
  PIN phy[349]
    DIRECTION INOUT ;
    USE SIGNAL ;
    PORT
      LAYER M4 ;
        RECT 2599.808 67.632 2600.000 67.656 ;
    END
  END phy[349]
  PIN phy[350]
    DIRECTION INOUT ;
    USE SIGNAL ;
    PORT
      LAYER M4 ;
        RECT 2599.808 67.824 2600.000 67.848 ;
    END
  END phy[350]
  PIN phy[351]
    DIRECTION INOUT ;
    USE SIGNAL ;
    PORT
      LAYER M4 ;
        RECT 2599.808 68.016 2600.000 68.040 ;
    END
  END phy[351]
  PIN phy[352]
    DIRECTION INOUT ;
    USE SIGNAL ;
    PORT
      LAYER M4 ;
        RECT 2599.808 68.208 2600.000 68.232 ;
    END
  END phy[352]
  PIN phy[353]
    DIRECTION INOUT ;
    USE SIGNAL ;
    PORT
      LAYER M4 ;
        RECT 2599.808 68.400 2600.000 68.424 ;
    END
  END phy[353]
  PIN phy[354]
    DIRECTION INOUT ;
    USE SIGNAL ;
    PORT
      LAYER M4 ;
        RECT 2599.808 68.592 2600.000 68.616 ;
    END
  END phy[354]
  PIN phy[355]
    DIRECTION INOUT ;
    USE SIGNAL ;
    PORT
      LAYER M4 ;
        RECT 2599.808 68.784 2600.000 68.808 ;
    END
  END phy[355]
  PIN phy[356]
    DIRECTION INOUT ;
    USE SIGNAL ;
    PORT
      LAYER M4 ;
        RECT 2599.808 68.976 2600.000 69.000 ;
    END
  END phy[356]
  PIN phy[357]
    DIRECTION INOUT ;
    USE SIGNAL ;
    PORT
      LAYER M4 ;
        RECT 2599.808 69.168 2600.000 69.192 ;
    END
  END phy[357]
  PIN phy[358]
    DIRECTION INOUT ;
    USE SIGNAL ;
    PORT
      LAYER M4 ;
        RECT 2599.808 69.360 2600.000 69.384 ;
    END
  END phy[358]
  PIN phy[359]
    DIRECTION INOUT ;
    USE SIGNAL ;
    PORT
      LAYER M4 ;
        RECT 2599.808 69.552 2600.000 69.576 ;
    END
  END phy[359]
  PIN phy[360]
    DIRECTION INOUT ;
    USE SIGNAL ;
    PORT
      LAYER M4 ;
        RECT 2599.808 69.744 2600.000 69.768 ;
    END
  END phy[360]
  PIN phy[361]
    DIRECTION INOUT ;
    USE SIGNAL ;
    PORT
      LAYER M4 ;
        RECT 2599.808 69.936 2600.000 69.960 ;
    END
  END phy[361]
  PIN phy[362]
    DIRECTION INOUT ;
    USE SIGNAL ;
    PORT
      LAYER M4 ;
        RECT 2599.808 70.128 2600.000 70.152 ;
    END
  END phy[362]
  PIN phy[363]
    DIRECTION INOUT ;
    USE SIGNAL ;
    PORT
      LAYER M4 ;
        RECT 2599.808 70.320 2600.000 70.344 ;
    END
  END phy[363]
  PIN phy[364]
    DIRECTION INOUT ;
    USE SIGNAL ;
    PORT
      LAYER M4 ;
        RECT 2599.808 70.512 2600.000 70.536 ;
    END
  END phy[364]
  PIN phy[365]
    DIRECTION INOUT ;
    USE SIGNAL ;
    PORT
      LAYER M4 ;
        RECT 2599.808 70.704 2600.000 70.728 ;
    END
  END phy[365]
  PIN phy[366]
    DIRECTION INOUT ;
    USE SIGNAL ;
    PORT
      LAYER M4 ;
        RECT 2599.808 70.896 2600.000 70.920 ;
    END
  END phy[366]
  PIN phy[367]
    DIRECTION INOUT ;
    USE SIGNAL ;
    PORT
      LAYER M4 ;
        RECT 2599.808 71.088 2600.000 71.112 ;
    END
  END phy[367]
  PIN phy[368]
    DIRECTION INOUT ;
    USE SIGNAL ;
    PORT
      LAYER M4 ;
        RECT 2599.808 71.280 2600.000 71.304 ;
    END
  END phy[368]
  PIN phy[369]
    DIRECTION INOUT ;
    USE SIGNAL ;
    PORT
      LAYER M4 ;
        RECT 2599.808 71.472 2600.000 71.496 ;
    END
  END phy[369]
  PIN phy[370]
    DIRECTION INOUT ;
    USE SIGNAL ;
    PORT
      LAYER M4 ;
        RECT 2599.808 71.664 2600.000 71.688 ;
    END
  END phy[370]
  PIN phy[371]
    DIRECTION INOUT ;
    USE SIGNAL ;
    PORT
      LAYER M4 ;
        RECT 2599.808 71.856 2600.000 71.880 ;
    END
  END phy[371]
  PIN phy[372]
    DIRECTION INOUT ;
    USE SIGNAL ;
    PORT
      LAYER M4 ;
        RECT 2599.808 72.048 2600.000 72.072 ;
    END
  END phy[372]
  PIN phy[373]
    DIRECTION INOUT ;
    USE SIGNAL ;
    PORT
      LAYER M4 ;
        RECT 2599.808 72.240 2600.000 72.264 ;
    END
  END phy[373]
  PIN phy[374]
    DIRECTION INOUT ;
    USE SIGNAL ;
    PORT
      LAYER M4 ;
        RECT 2599.808 72.432 2600.000 72.456 ;
    END
  END phy[374]
  PIN phy[375]
    DIRECTION INOUT ;
    USE SIGNAL ;
    PORT
      LAYER M4 ;
        RECT 2599.808 72.624 2600.000 72.648 ;
    END
  END phy[375]
  PIN phy[376]
    DIRECTION INOUT ;
    USE SIGNAL ;
    PORT
      LAYER M4 ;
        RECT 2599.808 72.816 2600.000 72.840 ;
    END
  END phy[376]
  PIN phy[377]
    DIRECTION INOUT ;
    USE SIGNAL ;
    PORT
      LAYER M4 ;
        RECT 2599.808 73.008 2600.000 73.032 ;
    END
  END phy[377]
  PIN phy[378]
    DIRECTION INOUT ;
    USE SIGNAL ;
    PORT
      LAYER M4 ;
        RECT 2599.808 73.200 2600.000 73.224 ;
    END
  END phy[378]
  PIN phy[379]
    DIRECTION INOUT ;
    USE SIGNAL ;
    PORT
      LAYER M4 ;
        RECT 2599.808 73.392 2600.000 73.416 ;
    END
  END phy[379]
  PIN phy[380]
    DIRECTION INOUT ;
    USE SIGNAL ;
    PORT
      LAYER M4 ;
        RECT 2599.808 73.584 2600.000 73.608 ;
    END
  END phy[380]
  PIN phy[381]
    DIRECTION INOUT ;
    USE SIGNAL ;
    PORT
      LAYER M4 ;
        RECT 2599.808 73.776 2600.000 73.800 ;
    END
  END phy[381]
  PIN phy[382]
    DIRECTION INOUT ;
    USE SIGNAL ;
    PORT
      LAYER M4 ;
        RECT 2599.808 73.968 2600.000 73.992 ;
    END
  END phy[382]
  PIN phy[383]
    DIRECTION INOUT ;
    USE SIGNAL ;
    PORT
      LAYER M4 ;
        RECT 2599.808 74.160 2600.000 74.184 ;
    END
  END phy[383]
  PIN phy[384]
    DIRECTION INOUT ;
    USE SIGNAL ;
    PORT
      LAYER M4 ;
        RECT 2599.808 74.352 2600.000 74.376 ;
    END
  END phy[384]
  PIN phy[385]
    DIRECTION INOUT ;
    USE SIGNAL ;
    PORT
      LAYER M4 ;
        RECT 2599.808 74.544 2600.000 74.568 ;
    END
  END phy[385]
  PIN phy[386]
    DIRECTION INOUT ;
    USE SIGNAL ;
    PORT
      LAYER M4 ;
        RECT 2599.808 74.736 2600.000 74.760 ;
    END
  END phy[386]
  PIN phy[387]
    DIRECTION INOUT ;
    USE SIGNAL ;
    PORT
      LAYER M4 ;
        RECT 2599.808 74.928 2600.000 74.952 ;
    END
  END phy[387]
  PIN phy[388]
    DIRECTION INOUT ;
    USE SIGNAL ;
    PORT
      LAYER M4 ;
        RECT 2599.808 75.120 2600.000 75.144 ;
    END
  END phy[388]
  PIN phy[389]
    DIRECTION INOUT ;
    USE SIGNAL ;
    PORT
      LAYER M4 ;
        RECT 2599.808 75.312 2600.000 75.336 ;
    END
  END phy[389]
  PIN phy[390]
    DIRECTION INOUT ;
    USE SIGNAL ;
    PORT
      LAYER M4 ;
        RECT 2599.808 75.504 2600.000 75.528 ;
    END
  END phy[390]
  PIN phy[391]
    DIRECTION INOUT ;
    USE SIGNAL ;
    PORT
      LAYER M4 ;
        RECT 2599.808 75.696 2600.000 75.720 ;
    END
  END phy[391]
  PIN phy[392]
    DIRECTION INOUT ;
    USE SIGNAL ;
    PORT
      LAYER M4 ;
        RECT 2599.808 75.888 2600.000 75.912 ;
    END
  END phy[392]
  PIN phy[393]
    DIRECTION INOUT ;
    USE SIGNAL ;
    PORT
      LAYER M4 ;
        RECT 2599.808 76.080 2600.000 76.104 ;
    END
  END phy[393]
  PIN phy[394]
    DIRECTION INOUT ;
    USE SIGNAL ;
    PORT
      LAYER M4 ;
        RECT 2599.808 76.272 2600.000 76.296 ;
    END
  END phy[394]
  PIN phy[395]
    DIRECTION INOUT ;
    USE SIGNAL ;
    PORT
      LAYER M4 ;
        RECT 2599.808 76.464 2600.000 76.488 ;
    END
  END phy[395]
  PIN phy[396]
    DIRECTION INOUT ;
    USE SIGNAL ;
    PORT
      LAYER M4 ;
        RECT 2599.808 76.656 2600.000 76.680 ;
    END
  END phy[396]
  PIN phy[397]
    DIRECTION INOUT ;
    USE SIGNAL ;
    PORT
      LAYER M4 ;
        RECT 2599.808 76.848 2600.000 76.872 ;
    END
  END phy[397]
  PIN phy[398]
    DIRECTION INOUT ;
    USE SIGNAL ;
    PORT
      LAYER M4 ;
        RECT 2599.808 77.040 2600.000 77.064 ;
    END
  END phy[398]
  PIN phy[399]
    DIRECTION INOUT ;
    USE SIGNAL ;
    PORT
      LAYER M4 ;
        RECT 2599.808 77.232 2600.000 77.256 ;
    END
  END phy[399]
  PIN phy[400]
    DIRECTION INOUT ;
    USE SIGNAL ;
    PORT
      LAYER M4 ;
        RECT 2599.808 77.424 2600.000 77.448 ;
    END
  END phy[400]
  PIN phy[401]
    DIRECTION INOUT ;
    USE SIGNAL ;
    PORT
      LAYER M4 ;
        RECT 2599.808 77.616 2600.000 77.640 ;
    END
  END phy[401]
  PIN phy[402]
    DIRECTION INOUT ;
    USE SIGNAL ;
    PORT
      LAYER M4 ;
        RECT 2599.808 77.808 2600.000 77.832 ;
    END
  END phy[402]
  PIN phy[403]
    DIRECTION INOUT ;
    USE SIGNAL ;
    PORT
      LAYER M4 ;
        RECT 2599.808 78.000 2600.000 78.024 ;
    END
  END phy[403]
  PIN phy[404]
    DIRECTION INOUT ;
    USE SIGNAL ;
    PORT
      LAYER M4 ;
        RECT 2599.808 78.192 2600.000 78.216 ;
    END
  END phy[404]
  PIN phy[405]
    DIRECTION INOUT ;
    USE SIGNAL ;
    PORT
      LAYER M4 ;
        RECT 2599.808 78.384 2600.000 78.408 ;
    END
  END phy[405]
  PIN phy[406]
    DIRECTION INOUT ;
    USE SIGNAL ;
    PORT
      LAYER M4 ;
        RECT 2599.808 78.576 2600.000 78.600 ;
    END
  END phy[406]
  PIN phy[407]
    DIRECTION INOUT ;
    USE SIGNAL ;
    PORT
      LAYER M4 ;
        RECT 2599.808 78.768 2600.000 78.792 ;
    END
  END phy[407]
  PIN phy[408]
    DIRECTION INOUT ;
    USE SIGNAL ;
    PORT
      LAYER M4 ;
        RECT 2599.808 78.960 2600.000 78.984 ;
    END
  END phy[408]
  PIN phy[409]
    DIRECTION INOUT ;
    USE SIGNAL ;
    PORT
      LAYER M4 ;
        RECT 2599.808 79.152 2600.000 79.176 ;
    END
  END phy[409]
  PIN phy[410]
    DIRECTION INOUT ;
    USE SIGNAL ;
    PORT
      LAYER M4 ;
        RECT 2599.808 79.344 2600.000 79.368 ;
    END
  END phy[410]
  PIN phy[411]
    DIRECTION INOUT ;
    USE SIGNAL ;
    PORT
      LAYER M4 ;
        RECT 2599.808 79.536 2600.000 79.560 ;
    END
  END phy[411]
  PIN phy[412]
    DIRECTION INOUT ;
    USE SIGNAL ;
    PORT
      LAYER M4 ;
        RECT 2599.808 79.728 2600.000 79.752 ;
    END
  END phy[412]
  PIN phy[413]
    DIRECTION INOUT ;
    USE SIGNAL ;
    PORT
      LAYER M4 ;
        RECT 2599.808 79.920 2600.000 79.944 ;
    END
  END phy[413]
  PIN phy[414]
    DIRECTION INOUT ;
    USE SIGNAL ;
    PORT
      LAYER M4 ;
        RECT 2599.808 80.112 2600.000 80.136 ;
    END
  END phy[414]
  PIN phy[415]
    DIRECTION INOUT ;
    USE SIGNAL ;
    PORT
      LAYER M4 ;
        RECT 2599.808 80.304 2600.000 80.328 ;
    END
  END phy[415]
  PIN phy[416]
    DIRECTION INOUT ;
    USE SIGNAL ;
    PORT
      LAYER M4 ;
        RECT 2599.808 80.496 2600.000 80.520 ;
    END
  END phy[416]
  PIN phy[417]
    DIRECTION INOUT ;
    USE SIGNAL ;
    PORT
      LAYER M4 ;
        RECT 2599.808 80.688 2600.000 80.712 ;
    END
  END phy[417]
  PIN phy[418]
    DIRECTION INOUT ;
    USE SIGNAL ;
    PORT
      LAYER M4 ;
        RECT 2599.808 80.880 2600.000 80.904 ;
    END
  END phy[418]
  PIN phy[419]
    DIRECTION INOUT ;
    USE SIGNAL ;
    PORT
      LAYER M4 ;
        RECT 2599.808 81.072 2600.000 81.096 ;
    END
  END phy[419]
  PIN phy[420]
    DIRECTION INOUT ;
    USE SIGNAL ;
    PORT
      LAYER M4 ;
        RECT 2599.808 81.264 2600.000 81.288 ;
    END
  END phy[420]
  PIN phy[421]
    DIRECTION INOUT ;
    USE SIGNAL ;
    PORT
      LAYER M4 ;
        RECT 2599.808 81.456 2600.000 81.480 ;
    END
  END phy[421]
  PIN phy[422]
    DIRECTION INOUT ;
    USE SIGNAL ;
    PORT
      LAYER M4 ;
        RECT 2599.808 81.648 2600.000 81.672 ;
    END
  END phy[422]
  PIN phy[423]
    DIRECTION INOUT ;
    USE SIGNAL ;
    PORT
      LAYER M4 ;
        RECT 2599.808 81.840 2600.000 81.864 ;
    END
  END phy[423]
  PIN phy[424]
    DIRECTION INOUT ;
    USE SIGNAL ;
    PORT
      LAYER M4 ;
        RECT 2599.808 82.032 2600.000 82.056 ;
    END
  END phy[424]
  PIN phy[425]
    DIRECTION INOUT ;
    USE SIGNAL ;
    PORT
      LAYER M4 ;
        RECT 2599.808 82.224 2600.000 82.248 ;
    END
  END phy[425]
  PIN phy[426]
    DIRECTION INOUT ;
    USE SIGNAL ;
    PORT
      LAYER M4 ;
        RECT 2599.808 82.416 2600.000 82.440 ;
    END
  END phy[426]
  PIN phy[427]
    DIRECTION INOUT ;
    USE SIGNAL ;
    PORT
      LAYER M4 ;
        RECT 2599.808 82.608 2600.000 82.632 ;
    END
  END phy[427]
  PIN phy[428]
    DIRECTION INOUT ;
    USE SIGNAL ;
    PORT
      LAYER M4 ;
        RECT 2599.808 82.800 2600.000 82.824 ;
    END
  END phy[428]
  PIN phy[429]
    DIRECTION INOUT ;
    USE SIGNAL ;
    PORT
      LAYER M4 ;
        RECT 2599.808 82.992 2600.000 83.016 ;
    END
  END phy[429]
  PIN phy[430]
    DIRECTION INOUT ;
    USE SIGNAL ;
    PORT
      LAYER M4 ;
        RECT 2599.808 83.184 2600.000 83.208 ;
    END
  END phy[430]
  PIN phy[431]
    DIRECTION INOUT ;
    USE SIGNAL ;
    PORT
      LAYER M4 ;
        RECT 2599.808 83.376 2600.000 83.400 ;
    END
  END phy[431]
  PIN phy[432]
    DIRECTION INOUT ;
    USE SIGNAL ;
    PORT
      LAYER M4 ;
        RECT 2599.808 83.568 2600.000 83.592 ;
    END
  END phy[432]
  PIN phy[433]
    DIRECTION INOUT ;
    USE SIGNAL ;
    PORT
      LAYER M4 ;
        RECT 2599.808 83.760 2600.000 83.784 ;
    END
  END phy[433]
  PIN phy[434]
    DIRECTION INOUT ;
    USE SIGNAL ;
    PORT
      LAYER M4 ;
        RECT 2599.808 83.952 2600.000 83.976 ;
    END
  END phy[434]
  PIN phy[435]
    DIRECTION INOUT ;
    USE SIGNAL ;
    PORT
      LAYER M4 ;
        RECT 2599.808 84.144 2600.000 84.168 ;
    END
  END phy[435]
  PIN phy[436]
    DIRECTION INOUT ;
    USE SIGNAL ;
    PORT
      LAYER M4 ;
        RECT 2599.808 84.336 2600.000 84.360 ;
    END
  END phy[436]
  PIN phy[437]
    DIRECTION INOUT ;
    USE SIGNAL ;
    PORT
      LAYER M4 ;
        RECT 2599.808 84.528 2600.000 84.552 ;
    END
  END phy[437]
  PIN phy[438]
    DIRECTION INOUT ;
    USE SIGNAL ;
    PORT
      LAYER M4 ;
        RECT 2599.808 84.720 2600.000 84.744 ;
    END
  END phy[438]
  PIN phy[439]
    DIRECTION INOUT ;
    USE SIGNAL ;
    PORT
      LAYER M4 ;
        RECT 2599.808 84.912 2600.000 84.936 ;
    END
  END phy[439]
  PIN phy[440]
    DIRECTION INOUT ;
    USE SIGNAL ;
    PORT
      LAYER M4 ;
        RECT 2599.808 85.104 2600.000 85.128 ;
    END
  END phy[440]
  PIN phy[441]
    DIRECTION INOUT ;
    USE SIGNAL ;
    PORT
      LAYER M4 ;
        RECT 2599.808 85.296 2600.000 85.320 ;
    END
  END phy[441]
  PIN phy[442]
    DIRECTION INOUT ;
    USE SIGNAL ;
    PORT
      LAYER M4 ;
        RECT 2599.808 85.488 2600.000 85.512 ;
    END
  END phy[442]
  PIN phy[443]
    DIRECTION INOUT ;
    USE SIGNAL ;
    PORT
      LAYER M4 ;
        RECT 2599.808 85.680 2600.000 85.704 ;
    END
  END phy[443]
  PIN phy[444]
    DIRECTION INOUT ;
    USE SIGNAL ;
    PORT
      LAYER M4 ;
        RECT 2599.808 85.872 2600.000 85.896 ;
    END
  END phy[444]
  PIN phy[445]
    DIRECTION INOUT ;
    USE SIGNAL ;
    PORT
      LAYER M4 ;
        RECT 2599.808 86.064 2600.000 86.088 ;
    END
  END phy[445]
  PIN phy[446]
    DIRECTION INOUT ;
    USE SIGNAL ;
    PORT
      LAYER M4 ;
        RECT 2599.808 86.256 2600.000 86.280 ;
    END
  END phy[446]
  PIN phy[447]
    DIRECTION INOUT ;
    USE SIGNAL ;
    PORT
      LAYER M4 ;
        RECT 2599.808 86.448 2600.000 86.472 ;
    END
  END phy[447]
  PIN phy[448]
    DIRECTION INOUT ;
    USE SIGNAL ;
    PORT
      LAYER M4 ;
        RECT 2599.808 86.640 2600.000 86.664 ;
    END
  END phy[448]
  PIN phy[449]
    DIRECTION INOUT ;
    USE SIGNAL ;
    PORT
      LAYER M4 ;
        RECT 2599.808 86.832 2600.000 86.856 ;
    END
  END phy[449]
  PIN phy[450]
    DIRECTION INOUT ;
    USE SIGNAL ;
    PORT
      LAYER M4 ;
        RECT 2599.808 87.024 2600.000 87.048 ;
    END
  END phy[450]
  PIN phy[451]
    DIRECTION INOUT ;
    USE SIGNAL ;
    PORT
      LAYER M4 ;
        RECT 2599.808 87.216 2600.000 87.240 ;
    END
  END phy[451]
  PIN phy[452]
    DIRECTION INOUT ;
    USE SIGNAL ;
    PORT
      LAYER M4 ;
        RECT 2599.808 87.408 2600.000 87.432 ;
    END
  END phy[452]
  PIN phy[453]
    DIRECTION INOUT ;
    USE SIGNAL ;
    PORT
      LAYER M4 ;
        RECT 2599.808 87.600 2600.000 87.624 ;
    END
  END phy[453]
  PIN phy[454]
    DIRECTION INOUT ;
    USE SIGNAL ;
    PORT
      LAYER M4 ;
        RECT 2599.808 87.792 2600.000 87.816 ;
    END
  END phy[454]
  PIN phy[455]
    DIRECTION INOUT ;
    USE SIGNAL ;
    PORT
      LAYER M4 ;
        RECT 2599.808 87.984 2600.000 88.008 ;
    END
  END phy[455]
  PIN phy[456]
    DIRECTION INOUT ;
    USE SIGNAL ;
    PORT
      LAYER M4 ;
        RECT 2599.808 88.176 2600.000 88.200 ;
    END
  END phy[456]
  PIN phy[457]
    DIRECTION INOUT ;
    USE SIGNAL ;
    PORT
      LAYER M4 ;
        RECT 2599.808 88.368 2600.000 88.392 ;
    END
  END phy[457]
  PIN phy[458]
    DIRECTION INOUT ;
    USE SIGNAL ;
    PORT
      LAYER M4 ;
        RECT 2599.808 88.560 2600.000 88.584 ;
    END
  END phy[458]
  PIN phy[459]
    DIRECTION INOUT ;
    USE SIGNAL ;
    PORT
      LAYER M4 ;
        RECT 2599.808 88.752 2600.000 88.776 ;
    END
  END phy[459]
  PIN phy[460]
    DIRECTION INOUT ;
    USE SIGNAL ;
    PORT
      LAYER M4 ;
        RECT 2599.808 88.944 2600.000 88.968 ;
    END
  END phy[460]
  PIN phy[461]
    DIRECTION INOUT ;
    USE SIGNAL ;
    PORT
      LAYER M4 ;
        RECT 2599.808 89.136 2600.000 89.160 ;
    END
  END phy[461]
  PIN phy[462]
    DIRECTION INOUT ;
    USE SIGNAL ;
    PORT
      LAYER M4 ;
        RECT 2599.808 89.328 2600.000 89.352 ;
    END
  END phy[462]
  PIN phy[463]
    DIRECTION INOUT ;
    USE SIGNAL ;
    PORT
      LAYER M4 ;
        RECT 2599.808 89.520 2600.000 89.544 ;
    END
  END phy[463]
  PIN phy[464]
    DIRECTION INOUT ;
    USE SIGNAL ;
    PORT
      LAYER M4 ;
        RECT 2599.808 89.712 2600.000 89.736 ;
    END
  END phy[464]
  PIN phy[465]
    DIRECTION INOUT ;
    USE SIGNAL ;
    PORT
      LAYER M4 ;
        RECT 2599.808 89.904 2600.000 89.928 ;
    END
  END phy[465]
  PIN phy[466]
    DIRECTION INOUT ;
    USE SIGNAL ;
    PORT
      LAYER M4 ;
        RECT 2599.808 90.096 2600.000 90.120 ;
    END
  END phy[466]
  PIN phy[467]
    DIRECTION INOUT ;
    USE SIGNAL ;
    PORT
      LAYER M4 ;
        RECT 2599.808 90.288 2600.000 90.312 ;
    END
  END phy[467]
  PIN phy[468]
    DIRECTION INOUT ;
    USE SIGNAL ;
    PORT
      LAYER M4 ;
        RECT 2599.808 90.480 2600.000 90.504 ;
    END
  END phy[468]
  PIN phy[469]
    DIRECTION INOUT ;
    USE SIGNAL ;
    PORT
      LAYER M4 ;
        RECT 2599.808 90.672 2600.000 90.696 ;
    END
  END phy[469]
  PIN phy[470]
    DIRECTION INOUT ;
    USE SIGNAL ;
    PORT
      LAYER M4 ;
        RECT 2599.808 90.864 2600.000 90.888 ;
    END
  END phy[470]
  PIN phy[471]
    DIRECTION INOUT ;
    USE SIGNAL ;
    PORT
      LAYER M4 ;
        RECT 2599.808 91.056 2600.000 91.080 ;
    END
  END phy[471]
  PIN phy[472]
    DIRECTION INOUT ;
    USE SIGNAL ;
    PORT
      LAYER M4 ;
        RECT 2599.808 91.248 2600.000 91.272 ;
    END
  END phy[472]
  PIN phy[473]
    DIRECTION INOUT ;
    USE SIGNAL ;
    PORT
      LAYER M4 ;
        RECT 2599.808 91.440 2600.000 91.464 ;
    END
  END phy[473]
  PIN phy[474]
    DIRECTION INOUT ;
    USE SIGNAL ;
    PORT
      LAYER M4 ;
        RECT 2599.808 91.632 2600.000 91.656 ;
    END
  END phy[474]
  PIN phy[475]
    DIRECTION INOUT ;
    USE SIGNAL ;
    PORT
      LAYER M4 ;
        RECT 2599.808 91.824 2600.000 91.848 ;
    END
  END phy[475]
  PIN phy[476]
    DIRECTION INOUT ;
    USE SIGNAL ;
    PORT
      LAYER M4 ;
        RECT 2599.808 92.016 2600.000 92.040 ;
    END
  END phy[476]
  PIN phy[477]
    DIRECTION INOUT ;
    USE SIGNAL ;
    PORT
      LAYER M4 ;
        RECT 2599.808 92.208 2600.000 92.232 ;
    END
  END phy[477]
  PIN phy[478]
    DIRECTION INOUT ;
    USE SIGNAL ;
    PORT
      LAYER M4 ;
        RECT 2599.808 92.400 2600.000 92.424 ;
    END
  END phy[478]
  PIN phy[479]
    DIRECTION INOUT ;
    USE SIGNAL ;
    PORT
      LAYER M4 ;
        RECT 2599.808 92.592 2600.000 92.616 ;
    END
  END phy[479]
  PIN phy[480]
    DIRECTION INOUT ;
    USE SIGNAL ;
    PORT
      LAYER M4 ;
        RECT 2599.808 92.784 2600.000 92.808 ;
    END
  END phy[480]
  PIN phy[481]
    DIRECTION INOUT ;
    USE SIGNAL ;
    PORT
      LAYER M4 ;
        RECT 2599.808 92.976 2600.000 93.000 ;
    END
  END phy[481]
  PIN phy[482]
    DIRECTION INOUT ;
    USE SIGNAL ;
    PORT
      LAYER M4 ;
        RECT 2599.808 93.168 2600.000 93.192 ;
    END
  END phy[482]
  PIN phy[483]
    DIRECTION INOUT ;
    USE SIGNAL ;
    PORT
      LAYER M4 ;
        RECT 2599.808 93.360 2600.000 93.384 ;
    END
  END phy[483]
  PIN phy[484]
    DIRECTION INOUT ;
    USE SIGNAL ;
    PORT
      LAYER M4 ;
        RECT 2599.808 93.552 2600.000 93.576 ;
    END
  END phy[484]
  PIN phy[485]
    DIRECTION INOUT ;
    USE SIGNAL ;
    PORT
      LAYER M4 ;
        RECT 2599.808 93.744 2600.000 93.768 ;
    END
  END phy[485]
  PIN phy[486]
    DIRECTION INOUT ;
    USE SIGNAL ;
    PORT
      LAYER M4 ;
        RECT 2599.808 93.936 2600.000 93.960 ;
    END
  END phy[486]
  PIN phy[487]
    DIRECTION INOUT ;
    USE SIGNAL ;
    PORT
      LAYER M4 ;
        RECT 2599.808 94.128 2600.000 94.152 ;
    END
  END phy[487]
  PIN phy[488]
    DIRECTION INOUT ;
    USE SIGNAL ;
    PORT
      LAYER M4 ;
        RECT 2599.808 94.320 2600.000 94.344 ;
    END
  END phy[488]
  PIN phy[489]
    DIRECTION INOUT ;
    USE SIGNAL ;
    PORT
      LAYER M4 ;
        RECT 2599.808 94.512 2600.000 94.536 ;
    END
  END phy[489]
  PIN phy[490]
    DIRECTION INOUT ;
    USE SIGNAL ;
    PORT
      LAYER M4 ;
        RECT 2599.808 94.704 2600.000 94.728 ;
    END
  END phy[490]
  PIN phy[491]
    DIRECTION INOUT ;
    USE SIGNAL ;
    PORT
      LAYER M4 ;
        RECT 2599.808 94.896 2600.000 94.920 ;
    END
  END phy[491]
  PIN phy[492]
    DIRECTION INOUT ;
    USE SIGNAL ;
    PORT
      LAYER M4 ;
        RECT 2599.808 95.088 2600.000 95.112 ;
    END
  END phy[492]
  PIN phy[493]
    DIRECTION INOUT ;
    USE SIGNAL ;
    PORT
      LAYER M4 ;
        RECT 2599.808 95.280 2600.000 95.304 ;
    END
  END phy[493]
  PIN phy[494]
    DIRECTION INOUT ;
    USE SIGNAL ;
    PORT
      LAYER M4 ;
        RECT 2599.808 95.472 2600.000 95.496 ;
    END
  END phy[494]
  PIN phy[495]
    DIRECTION INOUT ;
    USE SIGNAL ;
    PORT
      LAYER M4 ;
        RECT 2599.808 95.664 2600.000 95.688 ;
    END
  END phy[495]
  PIN phy[496]
    DIRECTION INOUT ;
    USE SIGNAL ;
    PORT
      LAYER M4 ;
        RECT 2599.808 95.856 2600.000 95.880 ;
    END
  END phy[496]
  PIN phy[497]
    DIRECTION INOUT ;
    USE SIGNAL ;
    PORT
      LAYER M4 ;
        RECT 2599.808 96.048 2600.000 96.072 ;
    END
  END phy[497]
  PIN phy[498]
    DIRECTION INOUT ;
    USE SIGNAL ;
    PORT
      LAYER M4 ;
        RECT 2599.808 96.240 2600.000 96.264 ;
    END
  END phy[498]
  PIN phy[499]
    DIRECTION INOUT ;
    USE SIGNAL ;
    PORT
      LAYER M4 ;
        RECT 2599.808 96.432 2600.000 96.456 ;
    END
  END phy[499]
  PIN phy[500]
    DIRECTION INOUT ;
    USE SIGNAL ;
    PORT
      LAYER M4 ;
        RECT 2599.808 96.624 2600.000 96.648 ;
    END
  END phy[500]
  PIN phy[501]
    DIRECTION INOUT ;
    USE SIGNAL ;
    PORT
      LAYER M4 ;
        RECT 2599.808 96.816 2600.000 96.840 ;
    END
  END phy[501]
  PIN phy[502]
    DIRECTION INOUT ;
    USE SIGNAL ;
    PORT
      LAYER M4 ;
        RECT 2599.808 97.008 2600.000 97.032 ;
    END
  END phy[502]
  PIN phy[503]
    DIRECTION INOUT ;
    USE SIGNAL ;
    PORT
      LAYER M4 ;
        RECT 2599.808 97.200 2600.000 97.224 ;
    END
  END phy[503]
  PIN phy[504]
    DIRECTION INOUT ;
    USE SIGNAL ;
    PORT
      LAYER M4 ;
        RECT 2599.808 97.392 2600.000 97.416 ;
    END
  END phy[504]
  PIN phy[505]
    DIRECTION INOUT ;
    USE SIGNAL ;
    PORT
      LAYER M4 ;
        RECT 2599.808 97.584 2600.000 97.608 ;
    END
  END phy[505]
  PIN phy[506]
    DIRECTION INOUT ;
    USE SIGNAL ;
    PORT
      LAYER M4 ;
        RECT 2599.808 97.776 2600.000 97.800 ;
    END
  END phy[506]
  PIN phy[507]
    DIRECTION INOUT ;
    USE SIGNAL ;
    PORT
      LAYER M4 ;
        RECT 2599.808 97.968 2600.000 97.992 ;
    END
  END phy[507]
  PIN phy[508]
    DIRECTION INOUT ;
    USE SIGNAL ;
    PORT
      LAYER M4 ;
        RECT 2599.808 98.160 2600.000 98.184 ;
    END
  END phy[508]
  PIN phy[509]
    DIRECTION INOUT ;
    USE SIGNAL ;
    PORT
      LAYER M4 ;
        RECT 2599.808 98.352 2600.000 98.376 ;
    END
  END phy[509]
  PIN phy[510]
    DIRECTION INOUT ;
    USE SIGNAL ;
    PORT
      LAYER M4 ;
        RECT 2599.808 98.544 2600.000 98.568 ;
    END
  END phy[510]
  PIN phy[511]
    DIRECTION INOUT ;
    USE SIGNAL ;
    PORT
      LAYER M4 ;
        RECT 2599.808 98.736 2600.000 98.760 ;
    END
  END phy[511]
  PIN phy[512]
    DIRECTION INOUT ;
    USE SIGNAL ;
    PORT
      LAYER M4 ;
        RECT 2599.808 98.928 2600.000 98.952 ;
    END
  END phy[512]
  PIN phy[513]
    DIRECTION INOUT ;
    USE SIGNAL ;
    PORT
      LAYER M4 ;
        RECT 2599.808 99.120 2600.000 99.144 ;
    END
  END phy[513]
  PIN phy[514]
    DIRECTION INOUT ;
    USE SIGNAL ;
    PORT
      LAYER M4 ;
        RECT 2599.808 99.312 2600.000 99.336 ;
    END
  END phy[514]
  PIN phy[515]
    DIRECTION INOUT ;
    USE SIGNAL ;
    PORT
      LAYER M4 ;
        RECT 2599.808 99.504 2600.000 99.528 ;
    END
  END phy[515]
  PIN phy[516]
    DIRECTION INOUT ;
    USE SIGNAL ;
    PORT
      LAYER M4 ;
        RECT 2599.808 99.696 2600.000 99.720 ;
    END
  END phy[516]
  PIN phy[517]
    DIRECTION INOUT ;
    USE SIGNAL ;
    PORT
      LAYER M4 ;
        RECT 2599.808 99.888 2600.000 99.912 ;
    END
  END phy[517]
  PIN phy[518]
    DIRECTION INOUT ;
    USE SIGNAL ;
    PORT
      LAYER M4 ;
        RECT 2599.808 100.080 2600.000 100.104 ;
    END
  END phy[518]
  PIN phy[519]
    DIRECTION INOUT ;
    USE SIGNAL ;
    PORT
      LAYER M4 ;
        RECT 2599.808 100.272 2600.000 100.296 ;
    END
  END phy[519]
  PIN phy[520]
    DIRECTION INOUT ;
    USE SIGNAL ;
    PORT
      LAYER M4 ;
        RECT 2599.808 100.464 2600.000 100.488 ;
    END
  END phy[520]
  PIN phy[521]
    DIRECTION INOUT ;
    USE SIGNAL ;
    PORT
      LAYER M4 ;
        RECT 2599.808 100.656 2600.000 100.680 ;
    END
  END phy[521]
  PIN phy[522]
    DIRECTION INOUT ;
    USE SIGNAL ;
    PORT
      LAYER M4 ;
        RECT 2599.808 100.848 2600.000 100.872 ;
    END
  END phy[522]
  PIN phy[523]
    DIRECTION INOUT ;
    USE SIGNAL ;
    PORT
      LAYER M4 ;
        RECT 2599.808 101.040 2600.000 101.064 ;
    END
  END phy[523]
  PIN phy[524]
    DIRECTION INOUT ;
    USE SIGNAL ;
    PORT
      LAYER M4 ;
        RECT 2599.808 101.232 2600.000 101.256 ;
    END
  END phy[524]
  PIN phy[525]
    DIRECTION INOUT ;
    USE SIGNAL ;
    PORT
      LAYER M4 ;
        RECT 2599.808 101.424 2600.000 101.448 ;
    END
  END phy[525]
  PIN phy[526]
    DIRECTION INOUT ;
    USE SIGNAL ;
    PORT
      LAYER M4 ;
        RECT 2599.808 101.616 2600.000 101.640 ;
    END
  END phy[526]
  PIN phy[527]
    DIRECTION INOUT ;
    USE SIGNAL ;
    PORT
      LAYER M4 ;
        RECT 2599.808 101.808 2600.000 101.832 ;
    END
  END phy[527]
  PIN phy[528]
    DIRECTION INOUT ;
    USE SIGNAL ;
    PORT
      LAYER M4 ;
        RECT 2599.808 102.000 2600.000 102.024 ;
    END
  END phy[528]
  PIN phy[529]
    DIRECTION INOUT ;
    USE SIGNAL ;
    PORT
      LAYER M4 ;
        RECT 2599.808 102.192 2600.000 102.216 ;
    END
  END phy[529]
  PIN phy[530]
    DIRECTION INOUT ;
    USE SIGNAL ;
    PORT
      LAYER M4 ;
        RECT 2599.808 102.384 2600.000 102.408 ;
    END
  END phy[530]
  PIN phy[531]
    DIRECTION INOUT ;
    USE SIGNAL ;
    PORT
      LAYER M4 ;
        RECT 2599.808 102.576 2600.000 102.600 ;
    END
  END phy[531]
  PIN phy[532]
    DIRECTION INOUT ;
    USE SIGNAL ;
    PORT
      LAYER M4 ;
        RECT 2599.808 102.768 2600.000 102.792 ;
    END
  END phy[532]
  PIN phy[533]
    DIRECTION INOUT ;
    USE SIGNAL ;
    PORT
      LAYER M4 ;
        RECT 2599.808 102.960 2600.000 102.984 ;
    END
  END phy[533]
  PIN phy[534]
    DIRECTION INOUT ;
    USE SIGNAL ;
    PORT
      LAYER M4 ;
        RECT 2599.808 103.152 2600.000 103.176 ;
    END
  END phy[534]
  PIN phy[535]
    DIRECTION INOUT ;
    USE SIGNAL ;
    PORT
      LAYER M4 ;
        RECT 2599.808 103.344 2600.000 103.368 ;
    END
  END phy[535]
  PIN phy[536]
    DIRECTION INOUT ;
    USE SIGNAL ;
    PORT
      LAYER M4 ;
        RECT 2599.808 103.536 2600.000 103.560 ;
    END
  END phy[536]
  PIN phy[537]
    DIRECTION INOUT ;
    USE SIGNAL ;
    PORT
      LAYER M4 ;
        RECT 2599.808 103.728 2600.000 103.752 ;
    END
  END phy[537]
  PIN phy[538]
    DIRECTION INOUT ;
    USE SIGNAL ;
    PORT
      LAYER M4 ;
        RECT 2599.808 103.920 2600.000 103.944 ;
    END
  END phy[538]
  PIN phy[539]
    DIRECTION INOUT ;
    USE SIGNAL ;
    PORT
      LAYER M4 ;
        RECT 2599.808 104.112 2600.000 104.136 ;
    END
  END phy[539]
  PIN phy[540]
    DIRECTION INOUT ;
    USE SIGNAL ;
    PORT
      LAYER M4 ;
        RECT 2599.808 104.304 2600.000 104.328 ;
    END
  END phy[540]
  PIN phy[541]
    DIRECTION INOUT ;
    USE SIGNAL ;
    PORT
      LAYER M4 ;
        RECT 2599.808 104.496 2600.000 104.520 ;
    END
  END phy[541]
  PIN phy[542]
    DIRECTION INOUT ;
    USE SIGNAL ;
    PORT
      LAYER M4 ;
        RECT 2599.808 104.688 2600.000 104.712 ;
    END
  END phy[542]
  PIN phy[543]
    DIRECTION INOUT ;
    USE SIGNAL ;
    PORT
      LAYER M4 ;
        RECT 2599.808 104.880 2600.000 104.904 ;
    END
  END phy[543]
  PIN phy[544]
    DIRECTION INOUT ;
    USE SIGNAL ;
    PORT
      LAYER M4 ;
        RECT 2599.808 105.072 2600.000 105.096 ;
    END
  END phy[544]
  PIN phy[545]
    DIRECTION INOUT ;
    USE SIGNAL ;
    PORT
      LAYER M4 ;
        RECT 2599.808 105.264 2600.000 105.288 ;
    END
  END phy[545]
  PIN phy[546]
    DIRECTION INOUT ;
    USE SIGNAL ;
    PORT
      LAYER M4 ;
        RECT 2599.808 105.456 2600.000 105.480 ;
    END
  END phy[546]
  PIN phy[547]
    DIRECTION INOUT ;
    USE SIGNAL ;
    PORT
      LAYER M4 ;
        RECT 2599.808 105.648 2600.000 105.672 ;
    END
  END phy[547]
  PIN phy[548]
    DIRECTION INOUT ;
    USE SIGNAL ;
    PORT
      LAYER M4 ;
        RECT 2599.808 105.840 2600.000 105.864 ;
    END
  END phy[548]
  PIN phy[549]
    DIRECTION INOUT ;
    USE SIGNAL ;
    PORT
      LAYER M4 ;
        RECT 2599.808 106.032 2600.000 106.056 ;
    END
  END phy[549]
  PIN phy[550]
    DIRECTION INOUT ;
    USE SIGNAL ;
    PORT
      LAYER M4 ;
        RECT 2599.808 106.224 2600.000 106.248 ;
    END
  END phy[550]
  PIN phy[551]
    DIRECTION INOUT ;
    USE SIGNAL ;
    PORT
      LAYER M4 ;
        RECT 2599.808 106.416 2600.000 106.440 ;
    END
  END phy[551]
  PIN phy[552]
    DIRECTION INOUT ;
    USE SIGNAL ;
    PORT
      LAYER M4 ;
        RECT 2599.808 106.608 2600.000 106.632 ;
    END
  END phy[552]
  PIN phy[553]
    DIRECTION INOUT ;
    USE SIGNAL ;
    PORT
      LAYER M4 ;
        RECT 2599.808 106.800 2600.000 106.824 ;
    END
  END phy[553]
  PIN phy[554]
    DIRECTION INOUT ;
    USE SIGNAL ;
    PORT
      LAYER M4 ;
        RECT 2599.808 106.992 2600.000 107.016 ;
    END
  END phy[554]
  PIN phy[555]
    DIRECTION INOUT ;
    USE SIGNAL ;
    PORT
      LAYER M4 ;
        RECT 2599.808 107.184 2600.000 107.208 ;
    END
  END phy[555]
  PIN phy[556]
    DIRECTION INOUT ;
    USE SIGNAL ;
    PORT
      LAYER M4 ;
        RECT 2599.808 107.376 2600.000 107.400 ;
    END
  END phy[556]
  PIN phy[557]
    DIRECTION INOUT ;
    USE SIGNAL ;
    PORT
      LAYER M4 ;
        RECT 2599.808 107.568 2600.000 107.592 ;
    END
  END phy[557]
  PIN phy[558]
    DIRECTION INOUT ;
    USE SIGNAL ;
    PORT
      LAYER M4 ;
        RECT 2599.808 107.760 2600.000 107.784 ;
    END
  END phy[558]
  PIN phy[559]
    DIRECTION INOUT ;
    USE SIGNAL ;
    PORT
      LAYER M4 ;
        RECT 2599.808 107.952 2600.000 107.976 ;
    END
  END phy[559]
  PIN phy[560]
    DIRECTION INOUT ;
    USE SIGNAL ;
    PORT
      LAYER M4 ;
        RECT 2599.808 108.144 2600.000 108.168 ;
    END
  END phy[560]
  PIN phy[561]
    DIRECTION INOUT ;
    USE SIGNAL ;
    PORT
      LAYER M4 ;
        RECT 2599.808 108.336 2600.000 108.360 ;
    END
  END phy[561]
  PIN phy[562]
    DIRECTION INOUT ;
    USE SIGNAL ;
    PORT
      LAYER M4 ;
        RECT 2599.808 108.528 2600.000 108.552 ;
    END
  END phy[562]
  PIN phy[563]
    DIRECTION INOUT ;
    USE SIGNAL ;
    PORT
      LAYER M4 ;
        RECT 2599.808 108.720 2600.000 108.744 ;
    END
  END phy[563]
  PIN phy[564]
    DIRECTION INOUT ;
    USE SIGNAL ;
    PORT
      LAYER M4 ;
        RECT 2599.808 108.912 2600.000 108.936 ;
    END
  END phy[564]
  PIN phy[565]
    DIRECTION INOUT ;
    USE SIGNAL ;
    PORT
      LAYER M4 ;
        RECT 2599.808 109.104 2600.000 109.128 ;
    END
  END phy[565]
  PIN phy[566]
    DIRECTION INOUT ;
    USE SIGNAL ;
    PORT
      LAYER M4 ;
        RECT 2599.808 109.296 2600.000 109.320 ;
    END
  END phy[566]
  PIN phy[567]
    DIRECTION INOUT ;
    USE SIGNAL ;
    PORT
      LAYER M4 ;
        RECT 2599.808 109.488 2600.000 109.512 ;
    END
  END phy[567]
  PIN phy[568]
    DIRECTION INOUT ;
    USE SIGNAL ;
    PORT
      LAYER M4 ;
        RECT 2599.808 109.680 2600.000 109.704 ;
    END
  END phy[568]
  PIN phy[569]
    DIRECTION INOUT ;
    USE SIGNAL ;
    PORT
      LAYER M4 ;
        RECT 2599.808 109.872 2600.000 109.896 ;
    END
  END phy[569]
  PIN phy[570]
    DIRECTION INOUT ;
    USE SIGNAL ;
    PORT
      LAYER M4 ;
        RECT 2599.808 110.064 2600.000 110.088 ;
    END
  END phy[570]
  PIN phy[571]
    DIRECTION INOUT ;
    USE SIGNAL ;
    PORT
      LAYER M4 ;
        RECT 2599.808 110.256 2600.000 110.280 ;
    END
  END phy[571]
  PIN phy[572]
    DIRECTION INOUT ;
    USE SIGNAL ;
    PORT
      LAYER M4 ;
        RECT 2599.808 110.448 2600.000 110.472 ;
    END
  END phy[572]
  PIN phy[573]
    DIRECTION INOUT ;
    USE SIGNAL ;
    PORT
      LAYER M4 ;
        RECT 2599.808 110.640 2600.000 110.664 ;
    END
  END phy[573]
  PIN phy[574]
    DIRECTION INOUT ;
    USE SIGNAL ;
    PORT
      LAYER M4 ;
        RECT 2599.808 110.832 2600.000 110.856 ;
    END
  END phy[574]
  PIN phy[575]
    DIRECTION INOUT ;
    USE SIGNAL ;
    PORT
      LAYER M4 ;
        RECT 2599.808 111.024 2600.000 111.048 ;
    END
  END phy[575]
  PIN phy[576]
    DIRECTION INOUT ;
    USE SIGNAL ;
    PORT
      LAYER M4 ;
        RECT 2599.808 111.216 2600.000 111.240 ;
    END
  END phy[576]
  PIN phy[577]
    DIRECTION INOUT ;
    USE SIGNAL ;
    PORT
      LAYER M4 ;
        RECT 2599.808 111.408 2600.000 111.432 ;
    END
  END phy[577]
  PIN phy[578]
    DIRECTION INOUT ;
    USE SIGNAL ;
    PORT
      LAYER M4 ;
        RECT 2599.808 111.600 2600.000 111.624 ;
    END
  END phy[578]
  PIN phy[579]
    DIRECTION INOUT ;
    USE SIGNAL ;
    PORT
      LAYER M4 ;
        RECT 2599.808 111.792 2600.000 111.816 ;
    END
  END phy[579]
  PIN phy[580]
    DIRECTION INOUT ;
    USE SIGNAL ;
    PORT
      LAYER M4 ;
        RECT 2599.808 111.984 2600.000 112.008 ;
    END
  END phy[580]
  PIN phy[581]
    DIRECTION INOUT ;
    USE SIGNAL ;
    PORT
      LAYER M4 ;
        RECT 2599.808 112.176 2600.000 112.200 ;
    END
  END phy[581]
  PIN phy[582]
    DIRECTION INOUT ;
    USE SIGNAL ;
    PORT
      LAYER M4 ;
        RECT 2599.808 112.368 2600.000 112.392 ;
    END
  END phy[582]
  PIN phy[583]
    DIRECTION INOUT ;
    USE SIGNAL ;
    PORT
      LAYER M4 ;
        RECT 2599.808 112.560 2600.000 112.584 ;
    END
  END phy[583]
  PIN phy[584]
    DIRECTION INOUT ;
    USE SIGNAL ;
    PORT
      LAYER M4 ;
        RECT 2599.808 112.752 2600.000 112.776 ;
    END
  END phy[584]
  PIN phy[585]
    DIRECTION INOUT ;
    USE SIGNAL ;
    PORT
      LAYER M4 ;
        RECT 2599.808 112.944 2600.000 112.968 ;
    END
  END phy[585]
  PIN phy[586]
    DIRECTION INOUT ;
    USE SIGNAL ;
    PORT
      LAYER M4 ;
        RECT 2599.808 113.136 2600.000 113.160 ;
    END
  END phy[586]
  PIN phy[587]
    DIRECTION INOUT ;
    USE SIGNAL ;
    PORT
      LAYER M4 ;
        RECT 2599.808 113.328 2600.000 113.352 ;
    END
  END phy[587]
  PIN phy[588]
    DIRECTION INOUT ;
    USE SIGNAL ;
    PORT
      LAYER M4 ;
        RECT 2599.808 113.520 2600.000 113.544 ;
    END
  END phy[588]
  PIN phy[589]
    DIRECTION INOUT ;
    USE SIGNAL ;
    PORT
      LAYER M4 ;
        RECT 2599.808 113.712 2600.000 113.736 ;
    END
  END phy[589]
  PIN phy[590]
    DIRECTION INOUT ;
    USE SIGNAL ;
    PORT
      LAYER M4 ;
        RECT 2599.808 113.904 2600.000 113.928 ;
    END
  END phy[590]
  PIN phy[591]
    DIRECTION INOUT ;
    USE SIGNAL ;
    PORT
      LAYER M4 ;
        RECT 2599.808 114.096 2600.000 114.120 ;
    END
  END phy[591]
  PIN phy[592]
    DIRECTION INOUT ;
    USE SIGNAL ;
    PORT
      LAYER M4 ;
        RECT 2599.808 114.288 2600.000 114.312 ;
    END
  END phy[592]
  PIN phy[593]
    DIRECTION INOUT ;
    USE SIGNAL ;
    PORT
      LAYER M4 ;
        RECT 2599.808 114.480 2600.000 114.504 ;
    END
  END phy[593]
  PIN phy[594]
    DIRECTION INOUT ;
    USE SIGNAL ;
    PORT
      LAYER M4 ;
        RECT 2599.808 114.672 2600.000 114.696 ;
    END
  END phy[594]
  PIN phy[595]
    DIRECTION INOUT ;
    USE SIGNAL ;
    PORT
      LAYER M4 ;
        RECT 2599.808 114.864 2600.000 114.888 ;
    END
  END phy[595]
  PIN phy[596]
    DIRECTION INOUT ;
    USE SIGNAL ;
    PORT
      LAYER M4 ;
        RECT 2599.808 115.056 2600.000 115.080 ;
    END
  END phy[596]
  PIN phy[597]
    DIRECTION INOUT ;
    USE SIGNAL ;
    PORT
      LAYER M4 ;
        RECT 2599.808 115.248 2600.000 115.272 ;
    END
  END phy[597]
  PIN phy[598]
    DIRECTION INOUT ;
    USE SIGNAL ;
    PORT
      LAYER M4 ;
        RECT 2599.808 115.440 2600.000 115.464 ;
    END
  END phy[598]
  PIN phy[599]
    DIRECTION INOUT ;
    USE SIGNAL ;
    PORT
      LAYER M4 ;
        RECT 2599.808 115.632 2600.000 115.656 ;
    END
  END phy[599]
  PIN phy[600]
    DIRECTION INOUT ;
    USE SIGNAL ;
    PORT
      LAYER M4 ;
        RECT 2599.808 115.824 2600.000 115.848 ;
    END
  END phy[600]
  PIN phy[601]
    DIRECTION INOUT ;
    USE SIGNAL ;
    PORT
      LAYER M4 ;
        RECT 2599.808 116.016 2600.000 116.040 ;
    END
  END phy[601]
  PIN phy[602]
    DIRECTION INOUT ;
    USE SIGNAL ;
    PORT
      LAYER M4 ;
        RECT 2599.808 116.208 2600.000 116.232 ;
    END
  END phy[602]
  PIN phy[603]
    DIRECTION INOUT ;
    USE SIGNAL ;
    PORT
      LAYER M4 ;
        RECT 2599.808 116.400 2600.000 116.424 ;
    END
  END phy[603]
  PIN phy[604]
    DIRECTION INOUT ;
    USE SIGNAL ;
    PORT
      LAYER M4 ;
        RECT 2599.808 116.592 2600.000 116.616 ;
    END
  END phy[604]
  PIN phy[605]
    DIRECTION INOUT ;
    USE SIGNAL ;
    PORT
      LAYER M4 ;
        RECT 2599.808 116.784 2600.000 116.808 ;
    END
  END phy[605]
  PIN phy[606]
    DIRECTION INOUT ;
    USE SIGNAL ;
    PORT
      LAYER M4 ;
        RECT 2599.808 116.976 2600.000 117.000 ;
    END
  END phy[606]
  PIN phy[607]
    DIRECTION INOUT ;
    USE SIGNAL ;
    PORT
      LAYER M4 ;
        RECT 2599.808 117.168 2600.000 117.192 ;
    END
  END phy[607]
  PIN phy[608]
    DIRECTION INOUT ;
    USE SIGNAL ;
    PORT
      LAYER M4 ;
        RECT 2599.808 117.360 2600.000 117.384 ;
    END
  END phy[608]
  PIN phy[609]
    DIRECTION INOUT ;
    USE SIGNAL ;
    PORT
      LAYER M4 ;
        RECT 2599.808 117.552 2600.000 117.576 ;
    END
  END phy[609]
  PIN phy[610]
    DIRECTION INOUT ;
    USE SIGNAL ;
    PORT
      LAYER M4 ;
        RECT 2599.808 117.744 2600.000 117.768 ;
    END
  END phy[610]
  PIN phy[611]
    DIRECTION INOUT ;
    USE SIGNAL ;
    PORT
      LAYER M4 ;
        RECT 2599.808 117.936 2600.000 117.960 ;
    END
  END phy[611]
  PIN phy[612]
    DIRECTION INOUT ;
    USE SIGNAL ;
    PORT
      LAYER M4 ;
        RECT 2599.808 118.128 2600.000 118.152 ;
    END
  END phy[612]
  PIN phy[613]
    DIRECTION INOUT ;
    USE SIGNAL ;
    PORT
      LAYER M4 ;
        RECT 2599.808 118.320 2600.000 118.344 ;
    END
  END phy[613]
  PIN phy[614]
    DIRECTION INOUT ;
    USE SIGNAL ;
    PORT
      LAYER M4 ;
        RECT 2599.808 118.512 2600.000 118.536 ;
    END
  END phy[614]
  PIN phy[615]
    DIRECTION INOUT ;
    USE SIGNAL ;
    PORT
      LAYER M4 ;
        RECT 2599.808 118.704 2600.000 118.728 ;
    END
  END phy[615]
  PIN phy[616]
    DIRECTION INOUT ;
    USE SIGNAL ;
    PORT
      LAYER M4 ;
        RECT 2599.808 118.896 2600.000 118.920 ;
    END
  END phy[616]
  PIN phy[617]
    DIRECTION INOUT ;
    USE SIGNAL ;
    PORT
      LAYER M4 ;
        RECT 2599.808 119.088 2600.000 119.112 ;
    END
  END phy[617]
  PIN phy[618]
    DIRECTION INOUT ;
    USE SIGNAL ;
    PORT
      LAYER M4 ;
        RECT 2599.808 119.280 2600.000 119.304 ;
    END
  END phy[618]
  PIN phy[619]
    DIRECTION INOUT ;
    USE SIGNAL ;
    PORT
      LAYER M4 ;
        RECT 2599.808 119.472 2600.000 119.496 ;
    END
  END phy[619]
  PIN phy[620]
    DIRECTION INOUT ;
    USE SIGNAL ;
    PORT
      LAYER M4 ;
        RECT 2599.808 119.664 2600.000 119.688 ;
    END
  END phy[620]
  PIN phy[621]
    DIRECTION INOUT ;
    USE SIGNAL ;
    PORT
      LAYER M4 ;
        RECT 2599.808 119.856 2600.000 119.880 ;
    END
  END phy[621]
  PIN phy[622]
    DIRECTION INOUT ;
    USE SIGNAL ;
    PORT
      LAYER M4 ;
        RECT 2599.808 120.048 2600.000 120.072 ;
    END
  END phy[622]
  PIN phy[623]
    DIRECTION INOUT ;
    USE SIGNAL ;
    PORT
      LAYER M4 ;
        RECT 2599.808 120.240 2600.000 120.264 ;
    END
  END phy[623]
  PIN phy[624]
    DIRECTION INOUT ;
    USE SIGNAL ;
    PORT
      LAYER M4 ;
        RECT 2599.808 120.432 2600.000 120.456 ;
    END
  END phy[624]
  PIN phy[625]
    DIRECTION INOUT ;
    USE SIGNAL ;
    PORT
      LAYER M4 ;
        RECT 2599.808 120.624 2600.000 120.648 ;
    END
  END phy[625]
  PIN phy[626]
    DIRECTION INOUT ;
    USE SIGNAL ;
    PORT
      LAYER M4 ;
        RECT 2599.808 120.816 2600.000 120.840 ;
    END
  END phy[626]
  PIN phy[627]
    DIRECTION INOUT ;
    USE SIGNAL ;
    PORT
      LAYER M4 ;
        RECT 2599.808 121.008 2600.000 121.032 ;
    END
  END phy[627]
  PIN phy[628]
    DIRECTION INOUT ;
    USE SIGNAL ;
    PORT
      LAYER M4 ;
        RECT 2599.808 121.200 2600.000 121.224 ;
    END
  END phy[628]
  PIN phy[629]
    DIRECTION INOUT ;
    USE SIGNAL ;
    PORT
      LAYER M4 ;
        RECT 2599.808 121.392 2600.000 121.416 ;
    END
  END phy[629]
  PIN phy[630]
    DIRECTION INOUT ;
    USE SIGNAL ;
    PORT
      LAYER M4 ;
        RECT 2599.808 121.584 2600.000 121.608 ;
    END
  END phy[630]
  PIN phy[631]
    DIRECTION INOUT ;
    USE SIGNAL ;
    PORT
      LAYER M4 ;
        RECT 2599.808 121.776 2600.000 121.800 ;
    END
  END phy[631]
  PIN phy[632]
    DIRECTION INOUT ;
    USE SIGNAL ;
    PORT
      LAYER M4 ;
        RECT 2599.808 121.968 2600.000 121.992 ;
    END
  END phy[632]
  PIN phy[633]
    DIRECTION INOUT ;
    USE SIGNAL ;
    PORT
      LAYER M4 ;
        RECT 2599.808 122.160 2600.000 122.184 ;
    END
  END phy[633]
  PIN phy[634]
    DIRECTION INOUT ;
    USE SIGNAL ;
    PORT
      LAYER M4 ;
        RECT 2599.808 122.352 2600.000 122.376 ;
    END
  END phy[634]
  PIN phy[635]
    DIRECTION INOUT ;
    USE SIGNAL ;
    PORT
      LAYER M4 ;
        RECT 2599.808 122.544 2600.000 122.568 ;
    END
  END phy[635]
  PIN phy[636]
    DIRECTION INOUT ;
    USE SIGNAL ;
    PORT
      LAYER M4 ;
        RECT 2599.808 122.736 2600.000 122.760 ;
    END
  END phy[636]
  PIN phy[637]
    DIRECTION INOUT ;
    USE SIGNAL ;
    PORT
      LAYER M4 ;
        RECT 2599.808 122.928 2600.000 122.952 ;
    END
  END phy[637]
  PIN phy[638]
    DIRECTION INOUT ;
    USE SIGNAL ;
    PORT
      LAYER M4 ;
        RECT 2599.808 123.120 2600.000 123.144 ;
    END
  END phy[638]
  PIN phy[639]
    DIRECTION INOUT ;
    USE SIGNAL ;
    PORT
      LAYER M4 ;
        RECT 2599.808 123.312 2600.000 123.336 ;
    END
  END phy[639]
  PIN phy[640]
    DIRECTION INOUT ;
    USE SIGNAL ;
    PORT
      LAYER M4 ;
        RECT 2599.808 123.504 2600.000 123.528 ;
    END
  END phy[640]
  PIN phy[641]
    DIRECTION INOUT ;
    USE SIGNAL ;
    PORT
      LAYER M4 ;
        RECT 2599.808 123.696 2600.000 123.720 ;
    END
  END phy[641]
  PIN phy[642]
    DIRECTION INOUT ;
    USE SIGNAL ;
    PORT
      LAYER M4 ;
        RECT 2599.808 123.888 2600.000 123.912 ;
    END
  END phy[642]
  PIN phy[643]
    DIRECTION INOUT ;
    USE SIGNAL ;
    PORT
      LAYER M4 ;
        RECT 2599.808 124.080 2600.000 124.104 ;
    END
  END phy[643]
  PIN phy[644]
    DIRECTION INOUT ;
    USE SIGNAL ;
    PORT
      LAYER M4 ;
        RECT 2599.808 124.272 2600.000 124.296 ;
    END
  END phy[644]
  PIN phy[645]
    DIRECTION INOUT ;
    USE SIGNAL ;
    PORT
      LAYER M4 ;
        RECT 2599.808 124.464 2600.000 124.488 ;
    END
  END phy[645]
  PIN phy[646]
    DIRECTION INOUT ;
    USE SIGNAL ;
    PORT
      LAYER M4 ;
        RECT 2599.808 124.656 2600.000 124.680 ;
    END
  END phy[646]
  PIN phy[647]
    DIRECTION INOUT ;
    USE SIGNAL ;
    PORT
      LAYER M4 ;
        RECT 2599.808 124.848 2600.000 124.872 ;
    END
  END phy[647]
  PIN phy[648]
    DIRECTION INOUT ;
    USE SIGNAL ;
    PORT
      LAYER M4 ;
        RECT 2599.808 125.040 2600.000 125.064 ;
    END
  END phy[648]
  PIN phy[649]
    DIRECTION INOUT ;
    USE SIGNAL ;
    PORT
      LAYER M4 ;
        RECT 2599.808 125.232 2600.000 125.256 ;
    END
  END phy[649]
  PIN phy[650]
    DIRECTION INOUT ;
    USE SIGNAL ;
    PORT
      LAYER M4 ;
        RECT 2599.808 125.424 2600.000 125.448 ;
    END
  END phy[650]
  PIN phy[651]
    DIRECTION INOUT ;
    USE SIGNAL ;
    PORT
      LAYER M4 ;
        RECT 2599.808 125.616 2600.000 125.640 ;
    END
  END phy[651]
  PIN phy[652]
    DIRECTION INOUT ;
    USE SIGNAL ;
    PORT
      LAYER M4 ;
        RECT 2599.808 125.808 2600.000 125.832 ;
    END
  END phy[652]
  PIN phy[653]
    DIRECTION INOUT ;
    USE SIGNAL ;
    PORT
      LAYER M4 ;
        RECT 2599.808 126.000 2600.000 126.024 ;
    END
  END phy[653]
  PIN phy[654]
    DIRECTION INOUT ;
    USE SIGNAL ;
    PORT
      LAYER M4 ;
        RECT 2599.808 126.192 2600.000 126.216 ;
    END
  END phy[654]
  PIN phy[655]
    DIRECTION INOUT ;
    USE SIGNAL ;
    PORT
      LAYER M4 ;
        RECT 2599.808 126.384 2600.000 126.408 ;
    END
  END phy[655]
  PIN phy[656]
    DIRECTION INOUT ;
    USE SIGNAL ;
    PORT
      LAYER M4 ;
        RECT 2599.808 126.576 2600.000 126.600 ;
    END
  END phy[656]
  PIN phy[657]
    DIRECTION INOUT ;
    USE SIGNAL ;
    PORT
      LAYER M4 ;
        RECT 2599.808 126.768 2600.000 126.792 ;
    END
  END phy[657]
  PIN phy[658]
    DIRECTION INOUT ;
    USE SIGNAL ;
    PORT
      LAYER M4 ;
        RECT 2599.808 126.960 2600.000 126.984 ;
    END
  END phy[658]
  PIN phy[659]
    DIRECTION INOUT ;
    USE SIGNAL ;
    PORT
      LAYER M4 ;
        RECT 2599.808 127.152 2600.000 127.176 ;
    END
  END phy[659]
  PIN phy[660]
    DIRECTION INOUT ;
    USE SIGNAL ;
    PORT
      LAYER M4 ;
        RECT 2599.808 127.344 2600.000 127.368 ;
    END
  END phy[660]
  PIN phy[661]
    DIRECTION INOUT ;
    USE SIGNAL ;
    PORT
      LAYER M4 ;
        RECT 2599.808 127.536 2600.000 127.560 ;
    END
  END phy[661]
  PIN phy[662]
    DIRECTION INOUT ;
    USE SIGNAL ;
    PORT
      LAYER M4 ;
        RECT 2599.808 127.728 2600.000 127.752 ;
    END
  END phy[662]
  PIN phy[663]
    DIRECTION INOUT ;
    USE SIGNAL ;
    PORT
      LAYER M4 ;
        RECT 2599.808 127.920 2600.000 127.944 ;
    END
  END phy[663]
  PIN phy[664]
    DIRECTION INOUT ;
    USE SIGNAL ;
    PORT
      LAYER M4 ;
        RECT 2599.808 128.112 2600.000 128.136 ;
    END
  END phy[664]
  PIN phy[665]
    DIRECTION INOUT ;
    USE SIGNAL ;
    PORT
      LAYER M4 ;
        RECT 2599.808 128.304 2600.000 128.328 ;
    END
  END phy[665]
  PIN phy[666]
    DIRECTION INOUT ;
    USE SIGNAL ;
    PORT
      LAYER M4 ;
        RECT 2599.808 128.496 2600.000 128.520 ;
    END
  END phy[666]
  PIN phy[667]
    DIRECTION INOUT ;
    USE SIGNAL ;
    PORT
      LAYER M4 ;
        RECT 2599.808 128.688 2600.000 128.712 ;
    END
  END phy[667]
  PIN phy[668]
    DIRECTION INOUT ;
    USE SIGNAL ;
    PORT
      LAYER M4 ;
        RECT 2599.808 128.880 2600.000 128.904 ;
    END
  END phy[668]
  PIN phy[669]
    DIRECTION INOUT ;
    USE SIGNAL ;
    PORT
      LAYER M4 ;
        RECT 2599.808 129.072 2600.000 129.096 ;
    END
  END phy[669]
  PIN phy[670]
    DIRECTION INOUT ;
    USE SIGNAL ;
    PORT
      LAYER M4 ;
        RECT 2599.808 129.264 2600.000 129.288 ;
    END
  END phy[670]
  PIN phy[671]
    DIRECTION INOUT ;
    USE SIGNAL ;
    PORT
      LAYER M4 ;
        RECT 2599.808 129.456 2600.000 129.480 ;
    END
  END phy[671]
  PIN phy[672]
    DIRECTION INOUT ;
    USE SIGNAL ;
    PORT
      LAYER M4 ;
        RECT 2599.808 129.648 2600.000 129.672 ;
    END
  END phy[672]
  PIN phy[673]
    DIRECTION INOUT ;
    USE SIGNAL ;
    PORT
      LAYER M4 ;
        RECT 2599.808 129.840 2600.000 129.864 ;
    END
  END phy[673]
  PIN phy[674]
    DIRECTION INOUT ;
    USE SIGNAL ;
    PORT
      LAYER M4 ;
        RECT 2599.808 130.032 2600.000 130.056 ;
    END
  END phy[674]
  PIN phy[675]
    DIRECTION INOUT ;
    USE SIGNAL ;
    PORT
      LAYER M4 ;
        RECT 2599.808 130.224 2600.000 130.248 ;
    END
  END phy[675]
  PIN phy[676]
    DIRECTION INOUT ;
    USE SIGNAL ;
    PORT
      LAYER M4 ;
        RECT 2599.808 130.416 2600.000 130.440 ;
    END
  END phy[676]
  PIN phy[677]
    DIRECTION INOUT ;
    USE SIGNAL ;
    PORT
      LAYER M4 ;
        RECT 2599.808 130.608 2600.000 130.632 ;
    END
  END phy[677]
  PIN phy[678]
    DIRECTION INOUT ;
    USE SIGNAL ;
    PORT
      LAYER M4 ;
        RECT 2599.808 130.800 2600.000 130.824 ;
    END
  END phy[678]
  PIN phy[679]
    DIRECTION INOUT ;
    USE SIGNAL ;
    PORT
      LAYER M4 ;
        RECT 2599.808 130.992 2600.000 131.016 ;
    END
  END phy[679]
  PIN phy[680]
    DIRECTION INOUT ;
    USE SIGNAL ;
    PORT
      LAYER M4 ;
        RECT 2599.808 131.184 2600.000 131.208 ;
    END
  END phy[680]
  PIN phy[681]
    DIRECTION INOUT ;
    USE SIGNAL ;
    PORT
      LAYER M4 ;
        RECT 2599.808 131.376 2600.000 131.400 ;
    END
  END phy[681]
  PIN phy[682]
    DIRECTION INOUT ;
    USE SIGNAL ;
    PORT
      LAYER M4 ;
        RECT 2599.808 131.568 2600.000 131.592 ;
    END
  END phy[682]
  PIN phy[683]
    DIRECTION INOUT ;
    USE SIGNAL ;
    PORT
      LAYER M4 ;
        RECT 2599.808 131.760 2600.000 131.784 ;
    END
  END phy[683]
  PIN phy[684]
    DIRECTION INOUT ;
    USE SIGNAL ;
    PORT
      LAYER M4 ;
        RECT 2599.808 131.952 2600.000 131.976 ;
    END
  END phy[684]
  PIN phy[685]
    DIRECTION INOUT ;
    USE SIGNAL ;
    PORT
      LAYER M4 ;
        RECT 2599.808 132.144 2600.000 132.168 ;
    END
  END phy[685]
  PIN phy[686]
    DIRECTION INOUT ;
    USE SIGNAL ;
    PORT
      LAYER M4 ;
        RECT 2599.808 132.336 2600.000 132.360 ;
    END
  END phy[686]
  PIN phy[687]
    DIRECTION INOUT ;
    USE SIGNAL ;
    PORT
      LAYER M4 ;
        RECT 2599.808 132.528 2600.000 132.552 ;
    END
  END phy[687]
  PIN phy[688]
    DIRECTION INOUT ;
    USE SIGNAL ;
    PORT
      LAYER M4 ;
        RECT 2599.808 132.720 2600.000 132.744 ;
    END
  END phy[688]
  PIN phy[689]
    DIRECTION INOUT ;
    USE SIGNAL ;
    PORT
      LAYER M4 ;
        RECT 2599.808 132.912 2600.000 132.936 ;
    END
  END phy[689]
  PIN phy[690]
    DIRECTION INOUT ;
    USE SIGNAL ;
    PORT
      LAYER M4 ;
        RECT 2599.808 133.104 2600.000 133.128 ;
    END
  END phy[690]
  PIN phy[691]
    DIRECTION INOUT ;
    USE SIGNAL ;
    PORT
      LAYER M4 ;
        RECT 2599.808 133.296 2600.000 133.320 ;
    END
  END phy[691]
  PIN phy[692]
    DIRECTION INOUT ;
    USE SIGNAL ;
    PORT
      LAYER M4 ;
        RECT 2599.808 133.488 2600.000 133.512 ;
    END
  END phy[692]
  PIN phy[693]
    DIRECTION INOUT ;
    USE SIGNAL ;
    PORT
      LAYER M4 ;
        RECT 2599.808 133.680 2600.000 133.704 ;
    END
  END phy[693]
  PIN phy[694]
    DIRECTION INOUT ;
    USE SIGNAL ;
    PORT
      LAYER M4 ;
        RECT 2599.808 133.872 2600.000 133.896 ;
    END
  END phy[694]
  PIN phy[695]
    DIRECTION INOUT ;
    USE SIGNAL ;
    PORT
      LAYER M4 ;
        RECT 2599.808 134.064 2600.000 134.088 ;
    END
  END phy[695]
  PIN phy[696]
    DIRECTION INOUT ;
    USE SIGNAL ;
    PORT
      LAYER M4 ;
        RECT 2599.808 134.256 2600.000 134.280 ;
    END
  END phy[696]
  PIN phy[697]
    DIRECTION INOUT ;
    USE SIGNAL ;
    PORT
      LAYER M4 ;
        RECT 2599.808 134.448 2600.000 134.472 ;
    END
  END phy[697]
  PIN phy[698]
    DIRECTION INOUT ;
    USE SIGNAL ;
    PORT
      LAYER M4 ;
        RECT 2599.808 134.640 2600.000 134.664 ;
    END
  END phy[698]
  PIN phy[699]
    DIRECTION INOUT ;
    USE SIGNAL ;
    PORT
      LAYER M4 ;
        RECT 2599.808 134.832 2600.000 134.856 ;
    END
  END phy[699]
  PIN phy[700]
    DIRECTION INOUT ;
    USE SIGNAL ;
    PORT
      LAYER M4 ;
        RECT 2599.808 135.024 2600.000 135.048 ;
    END
  END phy[700]
  PIN phy[701]
    DIRECTION INOUT ;
    USE SIGNAL ;
    PORT
      LAYER M4 ;
        RECT 2599.808 135.216 2600.000 135.240 ;
    END
  END phy[701]
  PIN phy[702]
    DIRECTION INOUT ;
    USE SIGNAL ;
    PORT
      LAYER M4 ;
        RECT 2599.808 135.408 2600.000 135.432 ;
    END
  END phy[702]
  PIN phy[703]
    DIRECTION INOUT ;
    USE SIGNAL ;
    PORT
      LAYER M4 ;
        RECT 2599.808 135.600 2600.000 135.624 ;
    END
  END phy[703]
  PIN phy[704]
    DIRECTION INOUT ;
    USE SIGNAL ;
    PORT
      LAYER M4 ;
        RECT 2599.808 135.792 2600.000 135.816 ;
    END
  END phy[704]
  PIN phy[705]
    DIRECTION INOUT ;
    USE SIGNAL ;
    PORT
      LAYER M4 ;
        RECT 2599.808 135.984 2600.000 136.008 ;
    END
  END phy[705]
  PIN phy[706]
    DIRECTION INOUT ;
    USE SIGNAL ;
    PORT
      LAYER M4 ;
        RECT 2599.808 136.176 2600.000 136.200 ;
    END
  END phy[706]
  PIN phy[707]
    DIRECTION INOUT ;
    USE SIGNAL ;
    PORT
      LAYER M4 ;
        RECT 2599.808 136.368 2600.000 136.392 ;
    END
  END phy[707]
  PIN phy[708]
    DIRECTION INOUT ;
    USE SIGNAL ;
    PORT
      LAYER M4 ;
        RECT 2599.808 136.560 2600.000 136.584 ;
    END
  END phy[708]
  PIN phy[709]
    DIRECTION INOUT ;
    USE SIGNAL ;
    PORT
      LAYER M4 ;
        RECT 2599.808 136.752 2600.000 136.776 ;
    END
  END phy[709]
  PIN phy[710]
    DIRECTION INOUT ;
    USE SIGNAL ;
    PORT
      LAYER M4 ;
        RECT 2599.808 136.944 2600.000 136.968 ;
    END
  END phy[710]
  PIN phy[711]
    DIRECTION INOUT ;
    USE SIGNAL ;
    PORT
      LAYER M4 ;
        RECT 2599.808 137.136 2600.000 137.160 ;
    END
  END phy[711]
  PIN phy[712]
    DIRECTION INOUT ;
    USE SIGNAL ;
    PORT
      LAYER M4 ;
        RECT 2599.808 137.328 2600.000 137.352 ;
    END
  END phy[712]
  PIN phy[713]
    DIRECTION INOUT ;
    USE SIGNAL ;
    PORT
      LAYER M4 ;
        RECT 2599.808 137.520 2600.000 137.544 ;
    END
  END phy[713]
  PIN phy[714]
    DIRECTION INOUT ;
    USE SIGNAL ;
    PORT
      LAYER M4 ;
        RECT 2599.808 137.712 2600.000 137.736 ;
    END
  END phy[714]
  PIN phy[715]
    DIRECTION INOUT ;
    USE SIGNAL ;
    PORT
      LAYER M4 ;
        RECT 2599.808 137.904 2600.000 137.928 ;
    END
  END phy[715]
  PIN phy[716]
    DIRECTION INOUT ;
    USE SIGNAL ;
    PORT
      LAYER M4 ;
        RECT 2599.808 138.096 2600.000 138.120 ;
    END
  END phy[716]
  PIN phy[717]
    DIRECTION INOUT ;
    USE SIGNAL ;
    PORT
      LAYER M4 ;
        RECT 2599.808 138.288 2600.000 138.312 ;
    END
  END phy[717]
  PIN phy[718]
    DIRECTION INOUT ;
    USE SIGNAL ;
    PORT
      LAYER M4 ;
        RECT 2599.808 138.480 2600.000 138.504 ;
    END
  END phy[718]
  PIN phy[719]
    DIRECTION INOUT ;
    USE SIGNAL ;
    PORT
      LAYER M4 ;
        RECT 2599.808 138.672 2600.000 138.696 ;
    END
  END phy[719]
  PIN phy[720]
    DIRECTION INOUT ;
    USE SIGNAL ;
    PORT
      LAYER M4 ;
        RECT 2599.808 138.864 2600.000 138.888 ;
    END
  END phy[720]
  PIN phy[721]
    DIRECTION INOUT ;
    USE SIGNAL ;
    PORT
      LAYER M4 ;
        RECT 2599.808 139.056 2600.000 139.080 ;
    END
  END phy[721]
  PIN phy[722]
    DIRECTION INOUT ;
    USE SIGNAL ;
    PORT
      LAYER M4 ;
        RECT 2599.808 139.248 2600.000 139.272 ;
    END
  END phy[722]
  PIN phy[723]
    DIRECTION INOUT ;
    USE SIGNAL ;
    PORT
      LAYER M4 ;
        RECT 2599.808 139.440 2600.000 139.464 ;
    END
  END phy[723]
  PIN phy[724]
    DIRECTION INOUT ;
    USE SIGNAL ;
    PORT
      LAYER M4 ;
        RECT 2599.808 139.632 2600.000 139.656 ;
    END
  END phy[724]
  PIN phy[725]
    DIRECTION INOUT ;
    USE SIGNAL ;
    PORT
      LAYER M4 ;
        RECT 2599.808 139.824 2600.000 139.848 ;
    END
  END phy[725]
  PIN phy[726]
    DIRECTION INOUT ;
    USE SIGNAL ;
    PORT
      LAYER M4 ;
        RECT 2599.808 140.016 2600.000 140.040 ;
    END
  END phy[726]
  PIN phy[727]
    DIRECTION INOUT ;
    USE SIGNAL ;
    PORT
      LAYER M4 ;
        RECT 2599.808 140.208 2600.000 140.232 ;
    END
  END phy[727]
  PIN phy[728]
    DIRECTION INOUT ;
    USE SIGNAL ;
    PORT
      LAYER M4 ;
        RECT 2599.808 140.400 2600.000 140.424 ;
    END
  END phy[728]
  PIN phy[729]
    DIRECTION INOUT ;
    USE SIGNAL ;
    PORT
      LAYER M4 ;
        RECT 2599.808 140.592 2600.000 140.616 ;
    END
  END phy[729]
  PIN phy[730]
    DIRECTION INOUT ;
    USE SIGNAL ;
    PORT
      LAYER M4 ;
        RECT 2599.808 140.784 2600.000 140.808 ;
    END
  END phy[730]
  PIN phy[731]
    DIRECTION INOUT ;
    USE SIGNAL ;
    PORT
      LAYER M4 ;
        RECT 2599.808 140.976 2600.000 141.000 ;
    END
  END phy[731]
  PIN phy[732]
    DIRECTION INOUT ;
    USE SIGNAL ;
    PORT
      LAYER M4 ;
        RECT 2599.808 141.168 2600.000 141.192 ;
    END
  END phy[732]
  PIN phy[733]
    DIRECTION INOUT ;
    USE SIGNAL ;
    PORT
      LAYER M4 ;
        RECT 2599.808 141.360 2600.000 141.384 ;
    END
  END phy[733]
  PIN phy[734]
    DIRECTION INOUT ;
    USE SIGNAL ;
    PORT
      LAYER M4 ;
        RECT 2599.808 141.552 2600.000 141.576 ;
    END
  END phy[734]
  PIN phy[735]
    DIRECTION INOUT ;
    USE SIGNAL ;
    PORT
      LAYER M4 ;
        RECT 2599.808 141.744 2600.000 141.768 ;
    END
  END phy[735]
  PIN phy[736]
    DIRECTION INOUT ;
    USE SIGNAL ;
    PORT
      LAYER M4 ;
        RECT 2599.808 141.936 2600.000 141.960 ;
    END
  END phy[736]
  PIN phy[737]
    DIRECTION INOUT ;
    USE SIGNAL ;
    PORT
      LAYER M4 ;
        RECT 2599.808 142.128 2600.000 142.152 ;
    END
  END phy[737]
  PIN phy[738]
    DIRECTION INOUT ;
    USE SIGNAL ;
    PORT
      LAYER M4 ;
        RECT 2599.808 142.320 2600.000 142.344 ;
    END
  END phy[738]
  PIN phy[739]
    DIRECTION INOUT ;
    USE SIGNAL ;
    PORT
      LAYER M4 ;
        RECT 2599.808 142.512 2600.000 142.536 ;
    END
  END phy[739]
  PIN phy[740]
    DIRECTION INOUT ;
    USE SIGNAL ;
    PORT
      LAYER M4 ;
        RECT 2599.808 142.704 2600.000 142.728 ;
    END
  END phy[740]
  PIN phy[741]
    DIRECTION INOUT ;
    USE SIGNAL ;
    PORT
      LAYER M4 ;
        RECT 2599.808 142.896 2600.000 142.920 ;
    END
  END phy[741]
  PIN phy[742]
    DIRECTION INOUT ;
    USE SIGNAL ;
    PORT
      LAYER M4 ;
        RECT 2599.808 143.088 2600.000 143.112 ;
    END
  END phy[742]
  PIN phy[743]
    DIRECTION INOUT ;
    USE SIGNAL ;
    PORT
      LAYER M4 ;
        RECT 2599.808 143.280 2600.000 143.304 ;
    END
  END phy[743]
  PIN phy[744]
    DIRECTION INOUT ;
    USE SIGNAL ;
    PORT
      LAYER M4 ;
        RECT 2599.808 143.472 2600.000 143.496 ;
    END
  END phy[744]
  PIN phy[745]
    DIRECTION INOUT ;
    USE SIGNAL ;
    PORT
      LAYER M4 ;
        RECT 2599.808 143.664 2600.000 143.688 ;
    END
  END phy[745]
  PIN phy[746]
    DIRECTION INOUT ;
    USE SIGNAL ;
    PORT
      LAYER M4 ;
        RECT 2599.808 143.856 2600.000 143.880 ;
    END
  END phy[746]
  PIN phy[747]
    DIRECTION INOUT ;
    USE SIGNAL ;
    PORT
      LAYER M4 ;
        RECT 2599.808 144.048 2600.000 144.072 ;
    END
  END phy[747]
  PIN phy[748]
    DIRECTION INOUT ;
    USE SIGNAL ;
    PORT
      LAYER M4 ;
        RECT 2599.808 144.240 2600.000 144.264 ;
    END
  END phy[748]
  PIN phy[749]
    DIRECTION INOUT ;
    USE SIGNAL ;
    PORT
      LAYER M4 ;
        RECT 2599.808 144.432 2600.000 144.456 ;
    END
  END phy[749]
  PIN phy[750]
    DIRECTION INOUT ;
    USE SIGNAL ;
    PORT
      LAYER M4 ;
        RECT 2599.808 144.624 2600.000 144.648 ;
    END
  END phy[750]
  PIN phy[751]
    DIRECTION INOUT ;
    USE SIGNAL ;
    PORT
      LAYER M4 ;
        RECT 2599.808 144.816 2600.000 144.840 ;
    END
  END phy[751]
  PIN phy[752]
    DIRECTION INOUT ;
    USE SIGNAL ;
    PORT
      LAYER M4 ;
        RECT 2599.808 145.008 2600.000 145.032 ;
    END
  END phy[752]
  PIN phy[753]
    DIRECTION INOUT ;
    USE SIGNAL ;
    PORT
      LAYER M4 ;
        RECT 2599.808 145.200 2600.000 145.224 ;
    END
  END phy[753]
  PIN phy[754]
    DIRECTION INOUT ;
    USE SIGNAL ;
    PORT
      LAYER M4 ;
        RECT 2599.808 145.392 2600.000 145.416 ;
    END
  END phy[754]
  PIN phy[755]
    DIRECTION INOUT ;
    USE SIGNAL ;
    PORT
      LAYER M4 ;
        RECT 2599.808 145.584 2600.000 145.608 ;
    END
  END phy[755]
  PIN phy[756]
    DIRECTION INOUT ;
    USE SIGNAL ;
    PORT
      LAYER M4 ;
        RECT 2599.808 145.776 2600.000 145.800 ;
    END
  END phy[756]
  PIN phy[757]
    DIRECTION INOUT ;
    USE SIGNAL ;
    PORT
      LAYER M4 ;
        RECT 2599.808 145.968 2600.000 145.992 ;
    END
  END phy[757]
  PIN phy[758]
    DIRECTION INOUT ;
    USE SIGNAL ;
    PORT
      LAYER M4 ;
        RECT 2599.808 146.160 2600.000 146.184 ;
    END
  END phy[758]
  PIN phy[759]
    DIRECTION INOUT ;
    USE SIGNAL ;
    PORT
      LAYER M4 ;
        RECT 2599.808 146.352 2600.000 146.376 ;
    END
  END phy[759]
  PIN phy[760]
    DIRECTION INOUT ;
    USE SIGNAL ;
    PORT
      LAYER M4 ;
        RECT 2599.808 146.544 2600.000 146.568 ;
    END
  END phy[760]
  PIN phy[761]
    DIRECTION INOUT ;
    USE SIGNAL ;
    PORT
      LAYER M4 ;
        RECT 2599.808 146.736 2600.000 146.760 ;
    END
  END phy[761]
  PIN phy[762]
    DIRECTION INOUT ;
    USE SIGNAL ;
    PORT
      LAYER M4 ;
        RECT 2599.808 146.928 2600.000 146.952 ;
    END
  END phy[762]
  PIN phy[763]
    DIRECTION INOUT ;
    USE SIGNAL ;
    PORT
      LAYER M4 ;
        RECT 2599.808 147.120 2600.000 147.144 ;
    END
  END phy[763]
  PIN phy[764]
    DIRECTION INOUT ;
    USE SIGNAL ;
    PORT
      LAYER M4 ;
        RECT 2599.808 147.312 2600.000 147.336 ;
    END
  END phy[764]
  PIN phy[765]
    DIRECTION INOUT ;
    USE SIGNAL ;
    PORT
      LAYER M4 ;
        RECT 2599.808 147.504 2600.000 147.528 ;
    END
  END phy[765]
  PIN phy[766]
    DIRECTION INOUT ;
    USE SIGNAL ;
    PORT
      LAYER M4 ;
        RECT 2599.808 147.696 2600.000 147.720 ;
    END
  END phy[766]
  PIN phy[767]
    DIRECTION INOUT ;
    USE SIGNAL ;
    PORT
      LAYER M4 ;
        RECT 2599.808 147.888 2600.000 147.912 ;
    END
  END phy[767]
  PIN phy[768]
    DIRECTION INOUT ;
    USE SIGNAL ;
    PORT
      LAYER M4 ;
        RECT 2599.808 148.080 2600.000 148.104 ;
    END
  END phy[768]
  PIN phy[769]
    DIRECTION INOUT ;
    USE SIGNAL ;
    PORT
      LAYER M4 ;
        RECT 2599.808 148.272 2600.000 148.296 ;
    END
  END phy[769]
  PIN phy[770]
    DIRECTION INOUT ;
    USE SIGNAL ;
    PORT
      LAYER M4 ;
        RECT 2599.808 148.464 2600.000 148.488 ;
    END
  END phy[770]
  PIN phy[771]
    DIRECTION INOUT ;
    USE SIGNAL ;
    PORT
      LAYER M4 ;
        RECT 2599.808 148.656 2600.000 148.680 ;
    END
  END phy[771]
  PIN phy[772]
    DIRECTION INOUT ;
    USE SIGNAL ;
    PORT
      LAYER M4 ;
        RECT 2599.808 148.848 2600.000 148.872 ;
    END
  END phy[772]
  PIN phy[773]
    DIRECTION INOUT ;
    USE SIGNAL ;
    PORT
      LAYER M4 ;
        RECT 2599.808 149.040 2600.000 149.064 ;
    END
  END phy[773]
  PIN phy[774]
    DIRECTION INOUT ;
    USE SIGNAL ;
    PORT
      LAYER M4 ;
        RECT 2599.808 149.232 2600.000 149.256 ;
    END
  END phy[774]
  PIN phy[775]
    DIRECTION INOUT ;
    USE SIGNAL ;
    PORT
      LAYER M4 ;
        RECT 2599.808 149.424 2600.000 149.448 ;
    END
  END phy[775]
  PIN phy[776]
    DIRECTION INOUT ;
    USE SIGNAL ;
    PORT
      LAYER M4 ;
        RECT 2599.808 149.616 2600.000 149.640 ;
    END
  END phy[776]
  PIN phy[777]
    DIRECTION INOUT ;
    USE SIGNAL ;
    PORT
      LAYER M4 ;
        RECT 2599.808 149.808 2600.000 149.832 ;
    END
  END phy[777]
  PIN phy[778]
    DIRECTION INOUT ;
    USE SIGNAL ;
    PORT
      LAYER M4 ;
        RECT 2599.808 150.000 2600.000 150.024 ;
    END
  END phy[778]
  PIN phy[779]
    DIRECTION INOUT ;
    USE SIGNAL ;
    PORT
      LAYER M4 ;
        RECT 2599.808 150.192 2600.000 150.216 ;
    END
  END phy[779]
  PIN phy[780]
    DIRECTION INOUT ;
    USE SIGNAL ;
    PORT
      LAYER M4 ;
        RECT 2599.808 150.384 2600.000 150.408 ;
    END
  END phy[780]
  PIN phy[781]
    DIRECTION INOUT ;
    USE SIGNAL ;
    PORT
      LAYER M4 ;
        RECT 2599.808 150.576 2600.000 150.600 ;
    END
  END phy[781]
  PIN phy[782]
    DIRECTION INOUT ;
    USE SIGNAL ;
    PORT
      LAYER M4 ;
        RECT 2599.808 150.768 2600.000 150.792 ;
    END
  END phy[782]
  PIN phy[783]
    DIRECTION INOUT ;
    USE SIGNAL ;
    PORT
      LAYER M4 ;
        RECT 2599.808 150.960 2600.000 150.984 ;
    END
  END phy[783]
  PIN phy[784]
    DIRECTION INOUT ;
    USE SIGNAL ;
    PORT
      LAYER M4 ;
        RECT 2599.808 151.152 2600.000 151.176 ;
    END
  END phy[784]
  PIN phy[785]
    DIRECTION INOUT ;
    USE SIGNAL ;
    PORT
      LAYER M4 ;
        RECT 2599.808 151.344 2600.000 151.368 ;
    END
  END phy[785]
  PIN phy[786]
    DIRECTION INOUT ;
    USE SIGNAL ;
    PORT
      LAYER M4 ;
        RECT 2599.808 151.536 2600.000 151.560 ;
    END
  END phy[786]
  PIN phy[787]
    DIRECTION INOUT ;
    USE SIGNAL ;
    PORT
      LAYER M4 ;
        RECT 2599.808 151.728 2600.000 151.752 ;
    END
  END phy[787]
  PIN phy[788]
    DIRECTION INOUT ;
    USE SIGNAL ;
    PORT
      LAYER M4 ;
        RECT 2599.808 151.920 2600.000 151.944 ;
    END
  END phy[788]
  PIN phy[789]
    DIRECTION INOUT ;
    USE SIGNAL ;
    PORT
      LAYER M4 ;
        RECT 2599.808 152.112 2600.000 152.136 ;
    END
  END phy[789]
  PIN phy[790]
    DIRECTION INOUT ;
    USE SIGNAL ;
    PORT
      LAYER M4 ;
        RECT 2599.808 152.304 2600.000 152.328 ;
    END
  END phy[790]
  PIN phy[791]
    DIRECTION INOUT ;
    USE SIGNAL ;
    PORT
      LAYER M4 ;
        RECT 2599.808 152.496 2600.000 152.520 ;
    END
  END phy[791]
  PIN phy[792]
    DIRECTION INOUT ;
    USE SIGNAL ;
    PORT
      LAYER M4 ;
        RECT 2599.808 152.688 2600.000 152.712 ;
    END
  END phy[792]
  PIN phy[793]
    DIRECTION INOUT ;
    USE SIGNAL ;
    PORT
      LAYER M4 ;
        RECT 2599.808 152.880 2600.000 152.904 ;
    END
  END phy[793]
  PIN phy[794]
    DIRECTION INOUT ;
    USE SIGNAL ;
    PORT
      LAYER M4 ;
        RECT 2599.808 153.072 2600.000 153.096 ;
    END
  END phy[794]
  PIN phy[795]
    DIRECTION INOUT ;
    USE SIGNAL ;
    PORT
      LAYER M4 ;
        RECT 2599.808 153.264 2600.000 153.288 ;
    END
  END phy[795]
  PIN phy[796]
    DIRECTION INOUT ;
    USE SIGNAL ;
    PORT
      LAYER M4 ;
        RECT 2599.808 153.456 2600.000 153.480 ;
    END
  END phy[796]
  PIN phy[797]
    DIRECTION INOUT ;
    USE SIGNAL ;
    PORT
      LAYER M4 ;
        RECT 2599.808 153.648 2600.000 153.672 ;
    END
  END phy[797]
  PIN phy[798]
    DIRECTION INOUT ;
    USE SIGNAL ;
    PORT
      LAYER M4 ;
        RECT 2599.808 153.840 2600.000 153.864 ;
    END
  END phy[798]
  PIN phy[799]
    DIRECTION INOUT ;
    USE SIGNAL ;
    PORT
      LAYER M4 ;
        RECT 2599.808 154.032 2600.000 154.056 ;
    END
  END phy[799]
  PIN phy[800]
    DIRECTION INOUT ;
    USE SIGNAL ;
    PORT
      LAYER M4 ;
        RECT 2599.808 154.224 2600.000 154.248 ;
    END
  END phy[800]
  PIN phy[801]
    DIRECTION INOUT ;
    USE SIGNAL ;
    PORT
      LAYER M4 ;
        RECT 2599.808 154.416 2600.000 154.440 ;
    END
  END phy[801]
  PIN phy[802]
    DIRECTION INOUT ;
    USE SIGNAL ;
    PORT
      LAYER M4 ;
        RECT 2599.808 154.608 2600.000 154.632 ;
    END
  END phy[802]
  PIN phy[803]
    DIRECTION INOUT ;
    USE SIGNAL ;
    PORT
      LAYER M4 ;
        RECT 2599.808 154.800 2600.000 154.824 ;
    END
  END phy[803]
  PIN phy[804]
    DIRECTION INOUT ;
    USE SIGNAL ;
    PORT
      LAYER M4 ;
        RECT 2599.808 154.992 2600.000 155.016 ;
    END
  END phy[804]
  PIN phy[805]
    DIRECTION INOUT ;
    USE SIGNAL ;
    PORT
      LAYER M4 ;
        RECT 2599.808 155.184 2600.000 155.208 ;
    END
  END phy[805]
  PIN phy[806]
    DIRECTION INOUT ;
    USE SIGNAL ;
    PORT
      LAYER M4 ;
        RECT 2599.808 155.376 2600.000 155.400 ;
    END
  END phy[806]
  PIN phy[807]
    DIRECTION INOUT ;
    USE SIGNAL ;
    PORT
      LAYER M4 ;
        RECT 2599.808 155.568 2600.000 155.592 ;
    END
  END phy[807]
  PIN phy[808]
    DIRECTION INOUT ;
    USE SIGNAL ;
    PORT
      LAYER M4 ;
        RECT 2599.808 155.760 2600.000 155.784 ;
    END
  END phy[808]
  PIN phy[809]
    DIRECTION INOUT ;
    USE SIGNAL ;
    PORT
      LAYER M4 ;
        RECT 2599.808 155.952 2600.000 155.976 ;
    END
  END phy[809]
  PIN phy[810]
    DIRECTION INOUT ;
    USE SIGNAL ;
    PORT
      LAYER M4 ;
        RECT 2599.808 156.144 2600.000 156.168 ;
    END
  END phy[810]
  PIN phy[811]
    DIRECTION INOUT ;
    USE SIGNAL ;
    PORT
      LAYER M4 ;
        RECT 2599.808 156.336 2600.000 156.360 ;
    END
  END phy[811]
  PIN phy[812]
    DIRECTION INOUT ;
    USE SIGNAL ;
    PORT
      LAYER M4 ;
        RECT 2599.808 156.528 2600.000 156.552 ;
    END
  END phy[812]
  PIN phy[813]
    DIRECTION INOUT ;
    USE SIGNAL ;
    PORT
      LAYER M4 ;
        RECT 2599.808 156.720 2600.000 156.744 ;
    END
  END phy[813]
  PIN phy[814]
    DIRECTION INOUT ;
    USE SIGNAL ;
    PORT
      LAYER M4 ;
        RECT 2599.808 156.912 2600.000 156.936 ;
    END
  END phy[814]
  PIN phy[815]
    DIRECTION INOUT ;
    USE SIGNAL ;
    PORT
      LAYER M4 ;
        RECT 2599.808 157.104 2600.000 157.128 ;
    END
  END phy[815]
  PIN phy[816]
    DIRECTION INOUT ;
    USE SIGNAL ;
    PORT
      LAYER M4 ;
        RECT 2599.808 157.296 2600.000 157.320 ;
    END
  END phy[816]
  PIN phy[817]
    DIRECTION INOUT ;
    USE SIGNAL ;
    PORT
      LAYER M4 ;
        RECT 2599.808 157.488 2600.000 157.512 ;
    END
  END phy[817]
  PIN phy[818]
    DIRECTION INOUT ;
    USE SIGNAL ;
    PORT
      LAYER M4 ;
        RECT 2599.808 157.680 2600.000 157.704 ;
    END
  END phy[818]
  PIN phy[819]
    DIRECTION INOUT ;
    USE SIGNAL ;
    PORT
      LAYER M4 ;
        RECT 2599.808 157.872 2600.000 157.896 ;
    END
  END phy[819]
  PIN phy[820]
    DIRECTION INOUT ;
    USE SIGNAL ;
    PORT
      LAYER M4 ;
        RECT 2599.808 158.064 2600.000 158.088 ;
    END
  END phy[820]
  PIN phy[821]
    DIRECTION INOUT ;
    USE SIGNAL ;
    PORT
      LAYER M4 ;
        RECT 2599.808 158.256 2600.000 158.280 ;
    END
  END phy[821]
  PIN phy[822]
    DIRECTION INOUT ;
    USE SIGNAL ;
    PORT
      LAYER M4 ;
        RECT 2599.808 158.448 2600.000 158.472 ;
    END
  END phy[822]
  PIN phy[823]
    DIRECTION INOUT ;
    USE SIGNAL ;
    PORT
      LAYER M4 ;
        RECT 2599.808 158.640 2600.000 158.664 ;
    END
  END phy[823]
  PIN phy[824]
    DIRECTION INOUT ;
    USE SIGNAL ;
    PORT
      LAYER M4 ;
        RECT 2599.808 158.832 2600.000 158.856 ;
    END
  END phy[824]
  PIN phy[825]
    DIRECTION INOUT ;
    USE SIGNAL ;
    PORT
      LAYER M4 ;
        RECT 2599.808 159.024 2600.000 159.048 ;
    END
  END phy[825]
  PIN phy[826]
    DIRECTION INOUT ;
    USE SIGNAL ;
    PORT
      LAYER M4 ;
        RECT 2599.808 159.216 2600.000 159.240 ;
    END
  END phy[826]
  PIN phy[827]
    DIRECTION INOUT ;
    USE SIGNAL ;
    PORT
      LAYER M4 ;
        RECT 2599.808 159.408 2600.000 159.432 ;
    END
  END phy[827]
  PIN phy[828]
    DIRECTION INOUT ;
    USE SIGNAL ;
    PORT
      LAYER M4 ;
        RECT 2599.808 159.600 2600.000 159.624 ;
    END
  END phy[828]
  PIN phy[829]
    DIRECTION INOUT ;
    USE SIGNAL ;
    PORT
      LAYER M4 ;
        RECT 2599.808 159.792 2600.000 159.816 ;
    END
  END phy[829]
  PIN phy[830]
    DIRECTION INOUT ;
    USE SIGNAL ;
    PORT
      LAYER M4 ;
        RECT 2599.808 159.984 2600.000 160.008 ;
    END
  END phy[830]
  PIN phy[831]
    DIRECTION INOUT ;
    USE SIGNAL ;
    PORT
      LAYER M4 ;
        RECT 2599.808 160.176 2600.000 160.200 ;
    END
  END phy[831]
  PIN phy[832]
    DIRECTION INOUT ;
    USE SIGNAL ;
    PORT
      LAYER M4 ;
        RECT 2599.808 160.368 2600.000 160.392 ;
    END
  END phy[832]
  PIN phy[833]
    DIRECTION INOUT ;
    USE SIGNAL ;
    PORT
      LAYER M4 ;
        RECT 2599.808 160.560 2600.000 160.584 ;
    END
  END phy[833]
  PIN phy[834]
    DIRECTION INOUT ;
    USE SIGNAL ;
    PORT
      LAYER M4 ;
        RECT 2599.808 160.752 2600.000 160.776 ;
    END
  END phy[834]
  PIN phy[835]
    DIRECTION INOUT ;
    USE SIGNAL ;
    PORT
      LAYER M4 ;
        RECT 2599.808 160.944 2600.000 160.968 ;
    END
  END phy[835]
  PIN phy[836]
    DIRECTION INOUT ;
    USE SIGNAL ;
    PORT
      LAYER M4 ;
        RECT 2599.808 161.136 2600.000 161.160 ;
    END
  END phy[836]
  PIN phy[837]
    DIRECTION INOUT ;
    USE SIGNAL ;
    PORT
      LAYER M4 ;
        RECT 2599.808 161.328 2600.000 161.352 ;
    END
  END phy[837]
  PIN phy[838]
    DIRECTION INOUT ;
    USE SIGNAL ;
    PORT
      LAYER M4 ;
        RECT 2599.808 161.520 2600.000 161.544 ;
    END
  END phy[838]
  PIN phy[839]
    DIRECTION INOUT ;
    USE SIGNAL ;
    PORT
      LAYER M4 ;
        RECT 2599.808 161.712 2600.000 161.736 ;
    END
  END phy[839]
  PIN phy[840]
    DIRECTION INOUT ;
    USE SIGNAL ;
    PORT
      LAYER M4 ;
        RECT 2599.808 161.904 2600.000 161.928 ;
    END
  END phy[840]
  PIN phy[841]
    DIRECTION INOUT ;
    USE SIGNAL ;
    PORT
      LAYER M4 ;
        RECT 2599.808 162.096 2600.000 162.120 ;
    END
  END phy[841]
  PIN phy[842]
    DIRECTION INOUT ;
    USE SIGNAL ;
    PORT
      LAYER M4 ;
        RECT 2599.808 162.288 2600.000 162.312 ;
    END
  END phy[842]
  PIN phy[843]
    DIRECTION INOUT ;
    USE SIGNAL ;
    PORT
      LAYER M4 ;
        RECT 2599.808 162.480 2600.000 162.504 ;
    END
  END phy[843]
  PIN phy[844]
    DIRECTION INOUT ;
    USE SIGNAL ;
    PORT
      LAYER M4 ;
        RECT 2599.808 162.672 2600.000 162.696 ;
    END
  END phy[844]
  PIN phy[845]
    DIRECTION INOUT ;
    USE SIGNAL ;
    PORT
      LAYER M4 ;
        RECT 2599.808 162.864 2600.000 162.888 ;
    END
  END phy[845]
  PIN phy[846]
    DIRECTION INOUT ;
    USE SIGNAL ;
    PORT
      LAYER M4 ;
        RECT 2599.808 163.056 2600.000 163.080 ;
    END
  END phy[846]
  PIN phy[847]
    DIRECTION INOUT ;
    USE SIGNAL ;
    PORT
      LAYER M4 ;
        RECT 2599.808 163.248 2600.000 163.272 ;
    END
  END phy[847]
  PIN phy[848]
    DIRECTION INOUT ;
    USE SIGNAL ;
    PORT
      LAYER M4 ;
        RECT 2599.808 163.440 2600.000 163.464 ;
    END
  END phy[848]
  PIN phy[849]
    DIRECTION INOUT ;
    USE SIGNAL ;
    PORT
      LAYER M4 ;
        RECT 2599.808 163.632 2600.000 163.656 ;
    END
  END phy[849]
  PIN phy[850]
    DIRECTION INOUT ;
    USE SIGNAL ;
    PORT
      LAYER M4 ;
        RECT 2599.808 163.824 2600.000 163.848 ;
    END
  END phy[850]
  PIN phy[851]
    DIRECTION INOUT ;
    USE SIGNAL ;
    PORT
      LAYER M4 ;
        RECT 2599.808 164.016 2600.000 164.040 ;
    END
  END phy[851]
  PIN phy[852]
    DIRECTION INOUT ;
    USE SIGNAL ;
    PORT
      LAYER M4 ;
        RECT 2599.808 164.208 2600.000 164.232 ;
    END
  END phy[852]
  PIN phy[853]
    DIRECTION INOUT ;
    USE SIGNAL ;
    PORT
      LAYER M4 ;
        RECT 2599.808 164.400 2600.000 164.424 ;
    END
  END phy[853]
  PIN phy[854]
    DIRECTION INOUT ;
    USE SIGNAL ;
    PORT
      LAYER M4 ;
        RECT 2599.808 164.592 2600.000 164.616 ;
    END
  END phy[854]
  PIN phy[855]
    DIRECTION INOUT ;
    USE SIGNAL ;
    PORT
      LAYER M4 ;
        RECT 2599.808 164.784 2600.000 164.808 ;
    END
  END phy[855]
  PIN phy[856]
    DIRECTION INOUT ;
    USE SIGNAL ;
    PORT
      LAYER M4 ;
        RECT 2599.808 164.976 2600.000 165.000 ;
    END
  END phy[856]
  PIN phy[857]
    DIRECTION INOUT ;
    USE SIGNAL ;
    PORT
      LAYER M4 ;
        RECT 2599.808 165.168 2600.000 165.192 ;
    END
  END phy[857]
  PIN phy[858]
    DIRECTION INOUT ;
    USE SIGNAL ;
    PORT
      LAYER M4 ;
        RECT 2599.808 165.360 2600.000 165.384 ;
    END
  END phy[858]
  PIN phy[859]
    DIRECTION INOUT ;
    USE SIGNAL ;
    PORT
      LAYER M4 ;
        RECT 2599.808 165.552 2600.000 165.576 ;
    END
  END phy[859]
  PIN phy[860]
    DIRECTION INOUT ;
    USE SIGNAL ;
    PORT
      LAYER M4 ;
        RECT 2599.808 165.744 2600.000 165.768 ;
    END
  END phy[860]
  PIN phy[861]
    DIRECTION INOUT ;
    USE SIGNAL ;
    PORT
      LAYER M4 ;
        RECT 2599.808 165.936 2600.000 165.960 ;
    END
  END phy[861]
  PIN phy[862]
    DIRECTION INOUT ;
    USE SIGNAL ;
    PORT
      LAYER M4 ;
        RECT 2599.808 166.128 2600.000 166.152 ;
    END
  END phy[862]
  PIN phy[863]
    DIRECTION INOUT ;
    USE SIGNAL ;
    PORT
      LAYER M4 ;
        RECT 2599.808 166.320 2600.000 166.344 ;
    END
  END phy[863]
  PIN phy[864]
    DIRECTION INOUT ;
    USE SIGNAL ;
    PORT
      LAYER M4 ;
        RECT 2599.808 166.512 2600.000 166.536 ;
    END
  END phy[864]
  PIN phy[865]
    DIRECTION INOUT ;
    USE SIGNAL ;
    PORT
      LAYER M4 ;
        RECT 2599.808 166.704 2600.000 166.728 ;
    END
  END phy[865]
  PIN phy[866]
    DIRECTION INOUT ;
    USE SIGNAL ;
    PORT
      LAYER M4 ;
        RECT 2599.808 166.896 2600.000 166.920 ;
    END
  END phy[866]
  PIN phy[867]
    DIRECTION INOUT ;
    USE SIGNAL ;
    PORT
      LAYER M4 ;
        RECT 2599.808 167.088 2600.000 167.112 ;
    END
  END phy[867]
  PIN phy[868]
    DIRECTION INOUT ;
    USE SIGNAL ;
    PORT
      LAYER M4 ;
        RECT 2599.808 167.280 2600.000 167.304 ;
    END
  END phy[868]
  PIN phy[869]
    DIRECTION INOUT ;
    USE SIGNAL ;
    PORT
      LAYER M4 ;
        RECT 2599.808 167.472 2600.000 167.496 ;
    END
  END phy[869]
  PIN phy[870]
    DIRECTION INOUT ;
    USE SIGNAL ;
    PORT
      LAYER M4 ;
        RECT 2599.808 167.664 2600.000 167.688 ;
    END
  END phy[870]
  PIN phy[871]
    DIRECTION INOUT ;
    USE SIGNAL ;
    PORT
      LAYER M4 ;
        RECT 2599.808 167.856 2600.000 167.880 ;
    END
  END phy[871]
  PIN phy[872]
    DIRECTION INOUT ;
    USE SIGNAL ;
    PORT
      LAYER M4 ;
        RECT 2599.808 168.048 2600.000 168.072 ;
    END
  END phy[872]
  PIN phy[873]
    DIRECTION INOUT ;
    USE SIGNAL ;
    PORT
      LAYER M4 ;
        RECT 2599.808 168.240 2600.000 168.264 ;
    END
  END phy[873]
  PIN phy[874]
    DIRECTION INOUT ;
    USE SIGNAL ;
    PORT
      LAYER M4 ;
        RECT 2599.808 168.432 2600.000 168.456 ;
    END
  END phy[874]
  PIN phy[875]
    DIRECTION INOUT ;
    USE SIGNAL ;
    PORT
      LAYER M4 ;
        RECT 2599.808 168.624 2600.000 168.648 ;
    END
  END phy[875]
  PIN phy[876]
    DIRECTION INOUT ;
    USE SIGNAL ;
    PORT
      LAYER M4 ;
        RECT 2599.808 168.816 2600.000 168.840 ;
    END
  END phy[876]
  PIN phy[877]
    DIRECTION INOUT ;
    USE SIGNAL ;
    PORT
      LAYER M4 ;
        RECT 2599.808 169.008 2600.000 169.032 ;
    END
  END phy[877]
  PIN phy[878]
    DIRECTION INOUT ;
    USE SIGNAL ;
    PORT
      LAYER M4 ;
        RECT 2599.808 169.200 2600.000 169.224 ;
    END
  END phy[878]
  PIN phy[879]
    DIRECTION INOUT ;
    USE SIGNAL ;
    PORT
      LAYER M4 ;
        RECT 2599.808 169.392 2600.000 169.416 ;
    END
  END phy[879]
  PIN phy[880]
    DIRECTION INOUT ;
    USE SIGNAL ;
    PORT
      LAYER M4 ;
        RECT 2599.808 169.584 2600.000 169.608 ;
    END
  END phy[880]
  PIN phy[881]
    DIRECTION INOUT ;
    USE SIGNAL ;
    PORT
      LAYER M4 ;
        RECT 2599.808 169.776 2600.000 169.800 ;
    END
  END phy[881]
  PIN phy[882]
    DIRECTION INOUT ;
    USE SIGNAL ;
    PORT
      LAYER M4 ;
        RECT 2599.808 169.968 2600.000 169.992 ;
    END
  END phy[882]
  PIN phy[883]
    DIRECTION INOUT ;
    USE SIGNAL ;
    PORT
      LAYER M4 ;
        RECT 2599.808 170.160 2600.000 170.184 ;
    END
  END phy[883]
  PIN phy[884]
    DIRECTION INOUT ;
    USE SIGNAL ;
    PORT
      LAYER M4 ;
        RECT 2599.808 170.352 2600.000 170.376 ;
    END
  END phy[884]
  PIN phy[885]
    DIRECTION INOUT ;
    USE SIGNAL ;
    PORT
      LAYER M4 ;
        RECT 2599.808 170.544 2600.000 170.568 ;
    END
  END phy[885]
  PIN phy[886]
    DIRECTION INOUT ;
    USE SIGNAL ;
    PORT
      LAYER M4 ;
        RECT 2599.808 170.736 2600.000 170.760 ;
    END
  END phy[886]
  PIN phy[887]
    DIRECTION INOUT ;
    USE SIGNAL ;
    PORT
      LAYER M4 ;
        RECT 2599.808 170.928 2600.000 170.952 ;
    END
  END phy[887]
  PIN phy[888]
    DIRECTION INOUT ;
    USE SIGNAL ;
    PORT
      LAYER M4 ;
        RECT 2599.808 171.120 2600.000 171.144 ;
    END
  END phy[888]
  PIN phy[889]
    DIRECTION INOUT ;
    USE SIGNAL ;
    PORT
      LAYER M4 ;
        RECT 2599.808 171.312 2600.000 171.336 ;
    END
  END phy[889]
  PIN phy[890]
    DIRECTION INOUT ;
    USE SIGNAL ;
    PORT
      LAYER M4 ;
        RECT 2599.808 171.504 2600.000 171.528 ;
    END
  END phy[890]
  PIN phy[891]
    DIRECTION INOUT ;
    USE SIGNAL ;
    PORT
      LAYER M4 ;
        RECT 2599.808 171.696 2600.000 171.720 ;
    END
  END phy[891]
  PIN phy[892]
    DIRECTION INOUT ;
    USE SIGNAL ;
    PORT
      LAYER M4 ;
        RECT 2599.808 171.888 2600.000 171.912 ;
    END
  END phy[892]
  PIN phy[893]
    DIRECTION INOUT ;
    USE SIGNAL ;
    PORT
      LAYER M4 ;
        RECT 2599.808 172.080 2600.000 172.104 ;
    END
  END phy[893]
  PIN phy[894]
    DIRECTION INOUT ;
    USE SIGNAL ;
    PORT
      LAYER M4 ;
        RECT 2599.808 172.272 2600.000 172.296 ;
    END
  END phy[894]
  PIN phy[895]
    DIRECTION INOUT ;
    USE SIGNAL ;
    PORT
      LAYER M4 ;
        RECT 2599.808 172.464 2600.000 172.488 ;
    END
  END phy[895]
  PIN phy[896]
    DIRECTION INOUT ;
    USE SIGNAL ;
    PORT
      LAYER M4 ;
        RECT 2599.808 172.656 2600.000 172.680 ;
    END
  END phy[896]
  PIN phy[897]
    DIRECTION INOUT ;
    USE SIGNAL ;
    PORT
      LAYER M4 ;
        RECT 2599.808 172.848 2600.000 172.872 ;
    END
  END phy[897]
  PIN phy[898]
    DIRECTION INOUT ;
    USE SIGNAL ;
    PORT
      LAYER M4 ;
        RECT 2599.808 173.040 2600.000 173.064 ;
    END
  END phy[898]
  PIN phy[899]
    DIRECTION INOUT ;
    USE SIGNAL ;
    PORT
      LAYER M4 ;
        RECT 2599.808 173.232 2600.000 173.256 ;
    END
  END phy[899]
  PIN phy[900]
    DIRECTION INOUT ;
    USE SIGNAL ;
    PORT
      LAYER M4 ;
        RECT 2599.808 173.424 2600.000 173.448 ;
    END
  END phy[900]
  PIN phy[901]
    DIRECTION INOUT ;
    USE SIGNAL ;
    PORT
      LAYER M4 ;
        RECT 2599.808 173.616 2600.000 173.640 ;
    END
  END phy[901]
  PIN phy[902]
    DIRECTION INOUT ;
    USE SIGNAL ;
    PORT
      LAYER M4 ;
        RECT 2599.808 173.808 2600.000 173.832 ;
    END
  END phy[902]
  PIN phy[903]
    DIRECTION INOUT ;
    USE SIGNAL ;
    PORT
      LAYER M4 ;
        RECT 2599.808 174.000 2600.000 174.024 ;
    END
  END phy[903]
  PIN phy[904]
    DIRECTION INOUT ;
    USE SIGNAL ;
    PORT
      LAYER M4 ;
        RECT 2599.808 174.192 2600.000 174.216 ;
    END
  END phy[904]
  PIN phy[905]
    DIRECTION INOUT ;
    USE SIGNAL ;
    PORT
      LAYER M4 ;
        RECT 2599.808 174.384 2600.000 174.408 ;
    END
  END phy[905]
  PIN phy[906]
    DIRECTION INOUT ;
    USE SIGNAL ;
    PORT
      LAYER M4 ;
        RECT 2599.808 174.576 2600.000 174.600 ;
    END
  END phy[906]
  PIN phy[907]
    DIRECTION INOUT ;
    USE SIGNAL ;
    PORT
      LAYER M4 ;
        RECT 2599.808 174.768 2600.000 174.792 ;
    END
  END phy[907]
  PIN phy[908]
    DIRECTION INOUT ;
    USE SIGNAL ;
    PORT
      LAYER M4 ;
        RECT 2599.808 174.960 2600.000 174.984 ;
    END
  END phy[908]
  PIN phy[909]
    DIRECTION INOUT ;
    USE SIGNAL ;
    PORT
      LAYER M4 ;
        RECT 2599.808 175.152 2600.000 175.176 ;
    END
  END phy[909]
  PIN phy[910]
    DIRECTION INOUT ;
    USE SIGNAL ;
    PORT
      LAYER M4 ;
        RECT 2599.808 175.344 2600.000 175.368 ;
    END
  END phy[910]
  PIN phy[911]
    DIRECTION INOUT ;
    USE SIGNAL ;
    PORT
      LAYER M4 ;
        RECT 2599.808 175.536 2600.000 175.560 ;
    END
  END phy[911]
  PIN phy[912]
    DIRECTION INOUT ;
    USE SIGNAL ;
    PORT
      LAYER M4 ;
        RECT 2599.808 175.728 2600.000 175.752 ;
    END
  END phy[912]
  PIN phy[913]
    DIRECTION INOUT ;
    USE SIGNAL ;
    PORT
      LAYER M4 ;
        RECT 2599.808 175.920 2600.000 175.944 ;
    END
  END phy[913]
  PIN phy[914]
    DIRECTION INOUT ;
    USE SIGNAL ;
    PORT
      LAYER M4 ;
        RECT 2599.808 176.112 2600.000 176.136 ;
    END
  END phy[914]
  PIN phy[915]
    DIRECTION INOUT ;
    USE SIGNAL ;
    PORT
      LAYER M4 ;
        RECT 2599.808 176.304 2600.000 176.328 ;
    END
  END phy[915]
  PIN phy[916]
    DIRECTION INOUT ;
    USE SIGNAL ;
    PORT
      LAYER M4 ;
        RECT 2599.808 176.496 2600.000 176.520 ;
    END
  END phy[916]
  PIN phy[917]
    DIRECTION INOUT ;
    USE SIGNAL ;
    PORT
      LAYER M4 ;
        RECT 2599.808 176.688 2600.000 176.712 ;
    END
  END phy[917]
  PIN phy[918]
    DIRECTION INOUT ;
    USE SIGNAL ;
    PORT
      LAYER M4 ;
        RECT 2599.808 176.880 2600.000 176.904 ;
    END
  END phy[918]
  PIN phy[919]
    DIRECTION INOUT ;
    USE SIGNAL ;
    PORT
      LAYER M4 ;
        RECT 2599.808 177.072 2600.000 177.096 ;
    END
  END phy[919]
  PIN phy[920]
    DIRECTION INOUT ;
    USE SIGNAL ;
    PORT
      LAYER M4 ;
        RECT 2599.808 177.264 2600.000 177.288 ;
    END
  END phy[920]
  PIN phy[921]
    DIRECTION INOUT ;
    USE SIGNAL ;
    PORT
      LAYER M4 ;
        RECT 2599.808 177.456 2600.000 177.480 ;
    END
  END phy[921]
  PIN phy[922]
    DIRECTION INOUT ;
    USE SIGNAL ;
    PORT
      LAYER M4 ;
        RECT 2599.808 177.648 2600.000 177.672 ;
    END
  END phy[922]
  PIN phy[923]
    DIRECTION INOUT ;
    USE SIGNAL ;
    PORT
      LAYER M4 ;
        RECT 2599.808 177.840 2600.000 177.864 ;
    END
  END phy[923]
  PIN phy[924]
    DIRECTION INOUT ;
    USE SIGNAL ;
    PORT
      LAYER M4 ;
        RECT 2599.808 178.032 2600.000 178.056 ;
    END
  END phy[924]
  PIN phy[925]
    DIRECTION INOUT ;
    USE SIGNAL ;
    PORT
      LAYER M4 ;
        RECT 2599.808 178.224 2600.000 178.248 ;
    END
  END phy[925]
  PIN phy[926]
    DIRECTION INOUT ;
    USE SIGNAL ;
    PORT
      LAYER M4 ;
        RECT 2599.808 178.416 2600.000 178.440 ;
    END
  END phy[926]
  PIN phy[927]
    DIRECTION INOUT ;
    USE SIGNAL ;
    PORT
      LAYER M4 ;
        RECT 2599.808 178.608 2600.000 178.632 ;
    END
  END phy[927]
  PIN phy[928]
    DIRECTION INOUT ;
    USE SIGNAL ;
    PORT
      LAYER M4 ;
        RECT 2599.808 178.800 2600.000 178.824 ;
    END
  END phy[928]
  PIN phy[929]
    DIRECTION INOUT ;
    USE SIGNAL ;
    PORT
      LAYER M4 ;
        RECT 2599.808 178.992 2600.000 179.016 ;
    END
  END phy[929]
  PIN phy[930]
    DIRECTION INOUT ;
    USE SIGNAL ;
    PORT
      LAYER M4 ;
        RECT 2599.808 179.184 2600.000 179.208 ;
    END
  END phy[930]
  PIN phy[931]
    DIRECTION INOUT ;
    USE SIGNAL ;
    PORT
      LAYER M4 ;
        RECT 2599.808 179.376 2600.000 179.400 ;
    END
  END phy[931]
  PIN phy[932]
    DIRECTION INOUT ;
    USE SIGNAL ;
    PORT
      LAYER M4 ;
        RECT 2599.808 179.568 2600.000 179.592 ;
    END
  END phy[932]
  PIN phy[933]
    DIRECTION INOUT ;
    USE SIGNAL ;
    PORT
      LAYER M4 ;
        RECT 2599.808 179.760 2600.000 179.784 ;
    END
  END phy[933]
  PIN phy[934]
    DIRECTION INOUT ;
    USE SIGNAL ;
    PORT
      LAYER M4 ;
        RECT 2599.808 179.952 2600.000 179.976 ;
    END
  END phy[934]
  PIN phy[935]
    DIRECTION INOUT ;
    USE SIGNAL ;
    PORT
      LAYER M4 ;
        RECT 2599.808 180.144 2600.000 180.168 ;
    END
  END phy[935]
  PIN phy[936]
    DIRECTION INOUT ;
    USE SIGNAL ;
    PORT
      LAYER M4 ;
        RECT 2599.808 180.336 2600.000 180.360 ;
    END
  END phy[936]
  PIN phy[937]
    DIRECTION INOUT ;
    USE SIGNAL ;
    PORT
      LAYER M4 ;
        RECT 2599.808 180.528 2600.000 180.552 ;
    END
  END phy[937]
  PIN phy[938]
    DIRECTION INOUT ;
    USE SIGNAL ;
    PORT
      LAYER M4 ;
        RECT 2599.808 180.720 2600.000 180.744 ;
    END
  END phy[938]
  PIN phy[939]
    DIRECTION INOUT ;
    USE SIGNAL ;
    PORT
      LAYER M4 ;
        RECT 2599.808 180.912 2600.000 180.936 ;
    END
  END phy[939]
  PIN phy[940]
    DIRECTION INOUT ;
    USE SIGNAL ;
    PORT
      LAYER M4 ;
        RECT 2599.808 181.104 2600.000 181.128 ;
    END
  END phy[940]
  PIN phy[941]
    DIRECTION INOUT ;
    USE SIGNAL ;
    PORT
      LAYER M4 ;
        RECT 2599.808 181.296 2600.000 181.320 ;
    END
  END phy[941]
  PIN phy[942]
    DIRECTION INOUT ;
    USE SIGNAL ;
    PORT
      LAYER M4 ;
        RECT 2599.808 181.488 2600.000 181.512 ;
    END
  END phy[942]
  PIN phy[943]
    DIRECTION INOUT ;
    USE SIGNAL ;
    PORT
      LAYER M4 ;
        RECT 2599.808 181.680 2600.000 181.704 ;
    END
  END phy[943]
  PIN phy[944]
    DIRECTION INOUT ;
    USE SIGNAL ;
    PORT
      LAYER M4 ;
        RECT 2599.808 181.872 2600.000 181.896 ;
    END
  END phy[944]
  PIN phy[945]
    DIRECTION INOUT ;
    USE SIGNAL ;
    PORT
      LAYER M4 ;
        RECT 2599.808 182.064 2600.000 182.088 ;
    END
  END phy[945]
  PIN phy[946]
    DIRECTION INOUT ;
    USE SIGNAL ;
    PORT
      LAYER M4 ;
        RECT 2599.808 182.256 2600.000 182.280 ;
    END
  END phy[946]
  PIN phy[947]
    DIRECTION INOUT ;
    USE SIGNAL ;
    PORT
      LAYER M4 ;
        RECT 2599.808 182.448 2600.000 182.472 ;
    END
  END phy[947]
  PIN phy[948]
    DIRECTION INOUT ;
    USE SIGNAL ;
    PORT
      LAYER M4 ;
        RECT 2599.808 182.640 2600.000 182.664 ;
    END
  END phy[948]
  PIN phy[949]
    DIRECTION INOUT ;
    USE SIGNAL ;
    PORT
      LAYER M4 ;
        RECT 2599.808 182.832 2600.000 182.856 ;
    END
  END phy[949]
  PIN phy[950]
    DIRECTION INOUT ;
    USE SIGNAL ;
    PORT
      LAYER M4 ;
        RECT 2599.808 183.024 2600.000 183.048 ;
    END
  END phy[950]
  PIN phy[951]
    DIRECTION INOUT ;
    USE SIGNAL ;
    PORT
      LAYER M4 ;
        RECT 2599.808 183.216 2600.000 183.240 ;
    END
  END phy[951]
  PIN phy[952]
    DIRECTION INOUT ;
    USE SIGNAL ;
    PORT
      LAYER M4 ;
        RECT 2599.808 183.408 2600.000 183.432 ;
    END
  END phy[952]
  PIN phy[953]
    DIRECTION INOUT ;
    USE SIGNAL ;
    PORT
      LAYER M4 ;
        RECT 2599.808 183.600 2600.000 183.624 ;
    END
  END phy[953]
  PIN phy[954]
    DIRECTION INOUT ;
    USE SIGNAL ;
    PORT
      LAYER M4 ;
        RECT 2599.808 183.792 2600.000 183.816 ;
    END
  END phy[954]
  PIN phy[955]
    DIRECTION INOUT ;
    USE SIGNAL ;
    PORT
      LAYER M4 ;
        RECT 2599.808 183.984 2600.000 184.008 ;
    END
  END phy[955]
  PIN phy[956]
    DIRECTION INOUT ;
    USE SIGNAL ;
    PORT
      LAYER M4 ;
        RECT 2599.808 184.176 2600.000 184.200 ;
    END
  END phy[956]
  PIN phy[957]
    DIRECTION INOUT ;
    USE SIGNAL ;
    PORT
      LAYER M4 ;
        RECT 2599.808 184.368 2600.000 184.392 ;
    END
  END phy[957]
  PIN phy[958]
    DIRECTION INOUT ;
    USE SIGNAL ;
    PORT
      LAYER M4 ;
        RECT 2599.808 184.560 2600.000 184.584 ;
    END
  END phy[958]
  PIN phy[959]
    DIRECTION INOUT ;
    USE SIGNAL ;
    PORT
      LAYER M4 ;
        RECT 2599.808 184.752 2600.000 184.776 ;
    END
  END phy[959]
  PIN phy[960]
    DIRECTION INOUT ;
    USE SIGNAL ;
    PORT
      LAYER M4 ;
        RECT 2599.808 184.944 2600.000 184.968 ;
    END
  END phy[960]
  PIN phy[961]
    DIRECTION INOUT ;
    USE SIGNAL ;
    PORT
      LAYER M4 ;
        RECT 2599.808 185.136 2600.000 185.160 ;
    END
  END phy[961]
  PIN phy[962]
    DIRECTION INOUT ;
    USE SIGNAL ;
    PORT
      LAYER M4 ;
        RECT 2599.808 185.328 2600.000 185.352 ;
    END
  END phy[962]
  PIN phy[963]
    DIRECTION INOUT ;
    USE SIGNAL ;
    PORT
      LAYER M4 ;
        RECT 2599.808 185.520 2600.000 185.544 ;
    END
  END phy[963]
  PIN phy[964]
    DIRECTION INOUT ;
    USE SIGNAL ;
    PORT
      LAYER M4 ;
        RECT 2599.808 185.712 2600.000 185.736 ;
    END
  END phy[964]
  PIN phy[965]
    DIRECTION INOUT ;
    USE SIGNAL ;
    PORT
      LAYER M4 ;
        RECT 2599.808 185.904 2600.000 185.928 ;
    END
  END phy[965]
  PIN phy[966]
    DIRECTION INOUT ;
    USE SIGNAL ;
    PORT
      LAYER M4 ;
        RECT 2599.808 186.096 2600.000 186.120 ;
    END
  END phy[966]
  PIN phy[967]
    DIRECTION INOUT ;
    USE SIGNAL ;
    PORT
      LAYER M4 ;
        RECT 2599.808 186.288 2600.000 186.312 ;
    END
  END phy[967]
  PIN phy[968]
    DIRECTION INOUT ;
    USE SIGNAL ;
    PORT
      LAYER M4 ;
        RECT 2599.808 186.480 2600.000 186.504 ;
    END
  END phy[968]
  PIN phy[969]
    DIRECTION INOUT ;
    USE SIGNAL ;
    PORT
      LAYER M4 ;
        RECT 2599.808 186.672 2600.000 186.696 ;
    END
  END phy[969]
  PIN phy[970]
    DIRECTION INOUT ;
    USE SIGNAL ;
    PORT
      LAYER M4 ;
        RECT 2599.808 186.864 2600.000 186.888 ;
    END
  END phy[970]
  PIN phy[971]
    DIRECTION INOUT ;
    USE SIGNAL ;
    PORT
      LAYER M4 ;
        RECT 2599.808 187.056 2600.000 187.080 ;
    END
  END phy[971]
  PIN phy[972]
    DIRECTION INOUT ;
    USE SIGNAL ;
    PORT
      LAYER M4 ;
        RECT 2599.808 187.248 2600.000 187.272 ;
    END
  END phy[972]
  PIN phy[973]
    DIRECTION INOUT ;
    USE SIGNAL ;
    PORT
      LAYER M4 ;
        RECT 2599.808 187.440 2600.000 187.464 ;
    END
  END phy[973]
  PIN f_lk[0]
    DIRECTION INOUT ;
    USE SIGNAL ;
    PORT
      LAYER M4 ;
        RECT 2599.808 614.352 2600.000 614.376 ;
    END
  END f_lk[0]
  PIN f_lk[1]
    DIRECTION INOUT ;
    USE SIGNAL ;
    PORT
      LAYER M4 ;
        RECT 2599.808 614.544 2600.000 614.568 ;
    END
  END f_lk[1]
  PIN f_lk[2]
    DIRECTION INOUT ;
    USE SIGNAL ;
    PORT
      LAYER M4 ;
        RECT 2599.808 614.736 2600.000 614.760 ;
    END
  END f_lk[2]
  PIN f_lk[3]
    DIRECTION INOUT ;
    USE SIGNAL ;
    PORT
      LAYER M4 ;
        RECT 2599.808 614.928 2600.000 614.952 ;
    END
  END f_lk[3]
  PIN f_lk[4]
    DIRECTION INOUT ;
    USE SIGNAL ;
    PORT
      LAYER M4 ;
        RECT 2599.808 615.120 2600.000 615.144 ;
    END
  END f_lk[4]
  PIN f_lk[5]
    DIRECTION INOUT ;
    USE SIGNAL ;
    PORT
      LAYER M4 ;
        RECT 2599.808 615.312 2600.000 615.336 ;
    END
  END f_lk[5]
  PIN f_lk[6]
    DIRECTION INOUT ;
    USE SIGNAL ;
    PORT
      LAYER M4 ;
        RECT 2599.808 615.504 2600.000 615.528 ;
    END
  END f_lk[6]
  PIN f_lk[7]
    DIRECTION INOUT ;
    USE SIGNAL ;
    PORT
      LAYER M4 ;
        RECT 2599.808 615.696 2600.000 615.720 ;
    END
  END f_lk[7]
  PIN f_lk[8]
    DIRECTION INOUT ;
    USE SIGNAL ;
    PORT
      LAYER M4 ;
        RECT 2599.808 615.888 2600.000 615.912 ;
    END
  END f_lk[8]
  PIN f_lk[9]
    DIRECTION INOUT ;
    USE SIGNAL ;
    PORT
      LAYER M4 ;
        RECT 2599.808 616.080 2600.000 616.104 ;
    END
  END f_lk[9]
  PIN f_lk[10]
    DIRECTION INOUT ;
    USE SIGNAL ;
    PORT
      LAYER M4 ;
        RECT 2599.808 616.272 2600.000 616.296 ;
    END
  END f_lk[10]
  PIN f_lk[11]
    DIRECTION INOUT ;
    USE SIGNAL ;
    PORT
      LAYER M4 ;
        RECT 2599.808 616.464 2600.000 616.488 ;
    END
  END f_lk[11]
  PIN f_lk[12]
    DIRECTION INOUT ;
    USE SIGNAL ;
    PORT
      LAYER M4 ;
        RECT 2599.808 616.656 2600.000 616.680 ;
    END
  END f_lk[12]
  PIN f_lk[13]
    DIRECTION INOUT ;
    USE SIGNAL ;
    PORT
      LAYER M4 ;
        RECT 2599.808 616.848 2600.000 616.872 ;
    END
  END f_lk[13]
  PIN f_lk[14]
    DIRECTION INOUT ;
    USE SIGNAL ;
    PORT
      LAYER M4 ;
        RECT 2599.808 617.040 2600.000 617.064 ;
    END
  END f_lk[14]
  PIN f_lk[15]
    DIRECTION INOUT ;
    USE SIGNAL ;
    PORT
      LAYER M4 ;
        RECT 2599.808 617.232 2600.000 617.256 ;
    END
  END f_lk[15]
  PIN f_lk[16]
    DIRECTION INOUT ;
    USE SIGNAL ;
    PORT
      LAYER M4 ;
        RECT 2599.808 617.424 2600.000 617.448 ;
    END
  END f_lk[16]
  PIN f_lk[17]
    DIRECTION INOUT ;
    USE SIGNAL ;
    PORT
      LAYER M4 ;
        RECT 2599.808 617.616 2600.000 617.640 ;
    END
  END f_lk[17]
  PIN f_lk[18]
    DIRECTION INOUT ;
    USE SIGNAL ;
    PORT
      LAYER M4 ;
        RECT 2599.808 617.808 2600.000 617.832 ;
    END
  END f_lk[18]
  PIN f_lk[19]
    DIRECTION INOUT ;
    USE SIGNAL ;
    PORT
      LAYER M4 ;
        RECT 2599.808 618.000 2600.000 618.024 ;
    END
  END f_lk[19]
  PIN f_lk[20]
    DIRECTION INOUT ;
    USE SIGNAL ;
    PORT
      LAYER M4 ;
        RECT 2599.808 618.192 2600.000 618.216 ;
    END
  END f_lk[20]
  PIN f_lk[21]
    DIRECTION INOUT ;
    USE SIGNAL ;
    PORT
      LAYER M4 ;
        RECT 2599.808 618.384 2600.000 618.408 ;
    END
  END f_lk[21]
  PIN f_lk[22]
    DIRECTION INOUT ;
    USE SIGNAL ;
    PORT
      LAYER M4 ;
        RECT 2599.808 618.576 2600.000 618.600 ;
    END
  END f_lk[22]
  PIN f_lk[23]
    DIRECTION INOUT ;
    USE SIGNAL ;
    PORT
      LAYER M4 ;
        RECT 2599.808 618.768 2600.000 618.792 ;
    END
  END f_lk[23]
  PIN f_lk[24]
    DIRECTION INOUT ;
    USE SIGNAL ;
    PORT
      LAYER M4 ;
        RECT 2599.808 618.960 2600.000 618.984 ;
    END
  END f_lk[24]
  PIN f_lk[25]
    DIRECTION INOUT ;
    USE SIGNAL ;
    PORT
      LAYER M4 ;
        RECT 2599.808 619.152 2600.000 619.176 ;
    END
  END f_lk[25]
  PIN f_lk[26]
    DIRECTION INOUT ;
    USE SIGNAL ;
    PORT
      LAYER M4 ;
        RECT 2599.808 619.344 2600.000 619.368 ;
    END
  END f_lk[26]
  PIN f_lk[27]
    DIRECTION INOUT ;
    USE SIGNAL ;
    PORT
      LAYER M4 ;
        RECT 2599.808 619.536 2600.000 619.560 ;
    END
  END f_lk[27]
  PIN f_lk[28]
    DIRECTION INOUT ;
    USE SIGNAL ;
    PORT
      LAYER M4 ;
        RECT 2599.808 619.728 2600.000 619.752 ;
    END
  END f_lk[28]
  PIN f_lk[29]
    DIRECTION INOUT ;
    USE SIGNAL ;
    PORT
      LAYER M4 ;
        RECT 2599.808 619.920 2600.000 619.944 ;
    END
  END f_lk[29]
  PIN f_lk[30]
    DIRECTION INOUT ;
    USE SIGNAL ;
    PORT
      LAYER M4 ;
        RECT 2599.808 620.112 2600.000 620.136 ;
    END
  END f_lk[30]
  PIN f_lk[31]
    DIRECTION INOUT ;
    USE SIGNAL ;
    PORT
      LAYER M4 ;
        RECT 2599.808 620.304 2600.000 620.328 ;
    END
  END f_lk[31]
  PIN f_lk[32]
    DIRECTION INOUT ;
    USE SIGNAL ;
    PORT
      LAYER M4 ;
        RECT 2599.808 620.496 2600.000 620.520 ;
    END
  END f_lk[32]
  PIN f_lk[33]
    DIRECTION INOUT ;
    USE SIGNAL ;
    PORT
      LAYER M4 ;
        RECT 2599.808 620.688 2600.000 620.712 ;
    END
  END f_lk[33]
  PIN f_lk[34]
    DIRECTION INOUT ;
    USE SIGNAL ;
    PORT
      LAYER M4 ;
        RECT 2599.808 620.880 2600.000 620.904 ;
    END
  END f_lk[34]
  PIN f_lk[35]
    DIRECTION INOUT ;
    USE SIGNAL ;
    PORT
      LAYER M4 ;
        RECT 2599.808 621.072 2600.000 621.096 ;
    END
  END f_lk[35]
  PIN f_lk[36]
    DIRECTION INOUT ;
    USE SIGNAL ;
    PORT
      LAYER M4 ;
        RECT 2599.808 621.264 2600.000 621.288 ;
    END
  END f_lk[36]
  PIN f_lk[37]
    DIRECTION INOUT ;
    USE SIGNAL ;
    PORT
      LAYER M4 ;
        RECT 2599.808 621.456 2600.000 621.480 ;
    END
  END f_lk[37]
  PIN f_lk[38]
    DIRECTION INOUT ;
    USE SIGNAL ;
    PORT
      LAYER M4 ;
        RECT 2599.808 621.648 2600.000 621.672 ;
    END
  END f_lk[38]
  PIN f_lk[39]
    DIRECTION INOUT ;
    USE SIGNAL ;
    PORT
      LAYER M4 ;
        RECT 2599.808 621.840 2600.000 621.864 ;
    END
  END f_lk[39]
  PIN f_lk[40]
    DIRECTION INOUT ;
    USE SIGNAL ;
    PORT
      LAYER M4 ;
        RECT 2599.808 622.032 2600.000 622.056 ;
    END
  END f_lk[40]
  PIN f_lk[41]
    DIRECTION INOUT ;
    USE SIGNAL ;
    PORT
      LAYER M4 ;
        RECT 2599.808 622.224 2600.000 622.248 ;
    END
  END f_lk[41]
  PIN f_lk[42]
    DIRECTION INOUT ;
    USE SIGNAL ;
    PORT
      LAYER M4 ;
        RECT 2599.808 622.416 2600.000 622.440 ;
    END
  END f_lk[42]
  PIN f_lk[43]
    DIRECTION INOUT ;
    USE SIGNAL ;
    PORT
      LAYER M4 ;
        RECT 2599.808 622.608 2600.000 622.632 ;
    END
  END f_lk[43]
  PIN f_lk[44]
    DIRECTION INOUT ;
    USE SIGNAL ;
    PORT
      LAYER M4 ;
        RECT 2599.808 622.800 2600.000 622.824 ;
    END
  END f_lk[44]
  PIN f_lk[45]
    DIRECTION INOUT ;
    USE SIGNAL ;
    PORT
      LAYER M4 ;
        RECT 2599.808 622.992 2600.000 623.016 ;
    END
  END f_lk[45]
  PIN f_lk[46]
    DIRECTION INOUT ;
    USE SIGNAL ;
    PORT
      LAYER M4 ;
        RECT 2599.808 623.184 2600.000 623.208 ;
    END
  END f_lk[46]
  PIN f_lk[47]
    DIRECTION INOUT ;
    USE SIGNAL ;
    PORT
      LAYER M4 ;
        RECT 2599.808 623.376 2600.000 623.400 ;
    END
  END f_lk[47]
  PIN f_lk[48]
    DIRECTION INOUT ;
    USE SIGNAL ;
    PORT
      LAYER M4 ;
        RECT 2599.808 623.568 2600.000 623.592 ;
    END
  END f_lk[48]
  PIN f_lk[49]
    DIRECTION INOUT ;
    USE SIGNAL ;
    PORT
      LAYER M4 ;
        RECT 2599.808 623.760 2600.000 623.784 ;
    END
  END f_lk[49]
  PIN f_lk[50]
    DIRECTION INOUT ;
    USE SIGNAL ;
    PORT
      LAYER M4 ;
        RECT 2599.808 623.952 2600.000 623.976 ;
    END
  END f_lk[50]
  PIN f_lk[51]
    DIRECTION INOUT ;
    USE SIGNAL ;
    PORT
      LAYER M4 ;
        RECT 2599.808 624.144 2600.000 624.168 ;
    END
  END f_lk[51]
  PIN f_lk[52]
    DIRECTION INOUT ;
    USE SIGNAL ;
    PORT
      LAYER M4 ;
        RECT 2599.808 624.336 2600.000 624.360 ;
    END
  END f_lk[52]
  PIN f_lk[53]
    DIRECTION INOUT ;
    USE SIGNAL ;
    PORT
      LAYER M4 ;
        RECT 2599.808 624.528 2600.000 624.552 ;
    END
  END f_lk[53]
  PIN f_lk[54]
    DIRECTION INOUT ;
    USE SIGNAL ;
    PORT
      LAYER M4 ;
        RECT 2599.808 624.720 2600.000 624.744 ;
    END
  END f_lk[54]
  PIN f_lk[55]
    DIRECTION INOUT ;
    USE SIGNAL ;
    PORT
      LAYER M4 ;
        RECT 2599.808 624.912 2600.000 624.936 ;
    END
  END f_lk[55]
  PIN f_lk[56]
    DIRECTION INOUT ;
    USE SIGNAL ;
    PORT
      LAYER M4 ;
        RECT 2599.808 625.104 2600.000 625.128 ;
    END
  END f_lk[56]
  PIN f_lk[57]
    DIRECTION INOUT ;
    USE SIGNAL ;
    PORT
      LAYER M4 ;
        RECT 2599.808 625.296 2600.000 625.320 ;
    END
  END f_lk[57]
  PIN f_lk[58]
    DIRECTION INOUT ;
    USE SIGNAL ;
    PORT
      LAYER M4 ;
        RECT 2599.808 625.488 2600.000 625.512 ;
    END
  END f_lk[58]
  PIN f_lk[59]
    DIRECTION INOUT ;
    USE SIGNAL ;
    PORT
      LAYER M4 ;
        RECT 2599.808 625.680 2600.000 625.704 ;
    END
  END f_lk[59]
  PIN f_lk[60]
    DIRECTION INOUT ;
    USE SIGNAL ;
    PORT
      LAYER M4 ;
        RECT 2599.808 625.872 2600.000 625.896 ;
    END
  END f_lk[60]
  PIN f_lk[61]
    DIRECTION INOUT ;
    USE SIGNAL ;
    PORT
      LAYER M4 ;
        RECT 2599.808 626.064 2600.000 626.088 ;
    END
  END f_lk[61]
  PIN f_lk[62]
    DIRECTION INOUT ;
    USE SIGNAL ;
    PORT
      LAYER M4 ;
        RECT 2599.808 626.256 2600.000 626.280 ;
    END
  END f_lk[62]
  PIN f_lk[63]
    DIRECTION INOUT ;
    USE SIGNAL ;
    PORT
      LAYER M4 ;
        RECT 2599.808 626.448 2600.000 626.472 ;
    END
  END f_lk[63]
  PIN f_lk[64]
    DIRECTION INOUT ;
    USE SIGNAL ;
    PORT
      LAYER M4 ;
        RECT 2599.808 626.640 2600.000 626.664 ;
    END
  END f_lk[64]
  PIN f_lk[65]
    DIRECTION INOUT ;
    USE SIGNAL ;
    PORT
      LAYER M4 ;
        RECT 2599.808 626.832 2600.000 626.856 ;
    END
  END f_lk[65]
  PIN f_lk[66]
    DIRECTION INOUT ;
    USE SIGNAL ;
    PORT
      LAYER M4 ;
        RECT 2599.808 627.024 2600.000 627.048 ;
    END
  END f_lk[66]
  PIN f_lk[67]
    DIRECTION INOUT ;
    USE SIGNAL ;
    PORT
      LAYER M4 ;
        RECT 2599.808 627.216 2600.000 627.240 ;
    END
  END f_lk[67]
  PIN f_lk[68]
    DIRECTION INOUT ;
    USE SIGNAL ;
    PORT
      LAYER M4 ;
        RECT 2599.808 627.408 2600.000 627.432 ;
    END
  END f_lk[68]
  PIN f_lk[69]
    DIRECTION INOUT ;
    USE SIGNAL ;
    PORT
      LAYER M4 ;
        RECT 2599.808 627.600 2600.000 627.624 ;
    END
  END f_lk[69]
  PIN f_lk[70]
    DIRECTION INOUT ;
    USE SIGNAL ;
    PORT
      LAYER M4 ;
        RECT 2599.808 627.792 2600.000 627.816 ;
    END
  END f_lk[70]
  PIN f_lk[71]
    DIRECTION INOUT ;
    USE SIGNAL ;
    PORT
      LAYER M4 ;
        RECT 2599.808 627.984 2600.000 628.008 ;
    END
  END f_lk[71]
  PIN f_lk[72]
    DIRECTION INOUT ;
    USE SIGNAL ;
    PORT
      LAYER M4 ;
        RECT 2599.808 628.176 2600.000 628.200 ;
    END
  END f_lk[72]
  PIN f_lk[73]
    DIRECTION INOUT ;
    USE SIGNAL ;
    PORT
      LAYER M4 ;
        RECT 2599.808 628.368 2600.000 628.392 ;
    END
  END f_lk[73]
  PIN f_lk[74]
    DIRECTION INOUT ;
    USE SIGNAL ;
    PORT
      LAYER M4 ;
        RECT 2599.808 628.560 2600.000 628.584 ;
    END
  END f_lk[74]
  PIN f_lk[75]
    DIRECTION INOUT ;
    USE SIGNAL ;
    PORT
      LAYER M4 ;
        RECT 2599.808 628.752 2600.000 628.776 ;
    END
  END f_lk[75]
  PIN f_lk[76]
    DIRECTION INOUT ;
    USE SIGNAL ;
    PORT
      LAYER M4 ;
        RECT 2599.808 628.944 2600.000 628.968 ;
    END
  END f_lk[76]
  PIN f_lk[77]
    DIRECTION INOUT ;
    USE SIGNAL ;
    PORT
      LAYER M4 ;
        RECT 2599.808 629.136 2600.000 629.160 ;
    END
  END f_lk[77]
  PIN f_lk[78]
    DIRECTION INOUT ;
    USE SIGNAL ;
    PORT
      LAYER M4 ;
        RECT 2599.808 629.328 2600.000 629.352 ;
    END
  END f_lk[78]
  PIN f_lk[79]
    DIRECTION INOUT ;
    USE SIGNAL ;
    PORT
      LAYER M4 ;
        RECT 2599.808 629.520 2600.000 629.544 ;
    END
  END f_lk[79]
  PIN f_lk[80]
    DIRECTION INOUT ;
    USE SIGNAL ;
    PORT
      LAYER M4 ;
        RECT 2599.808 629.712 2600.000 629.736 ;
    END
  END f_lk[80]
  PIN f_lk[81]
    DIRECTION INOUT ;
    USE SIGNAL ;
    PORT
      LAYER M4 ;
        RECT 2599.808 629.904 2600.000 629.928 ;
    END
  END f_lk[81]
  PIN f_lk[82]
    DIRECTION INOUT ;
    USE SIGNAL ;
    PORT
      LAYER M4 ;
        RECT 2599.808 630.096 2600.000 630.120 ;
    END
  END f_lk[82]
  PIN f_lk[83]
    DIRECTION INOUT ;
    USE SIGNAL ;
    PORT
      LAYER M4 ;
        RECT 2599.808 630.288 2600.000 630.312 ;
    END
  END f_lk[83]
  PIN f_lk[84]
    DIRECTION INOUT ;
    USE SIGNAL ;
    PORT
      LAYER M4 ;
        RECT 2599.808 630.480 2600.000 630.504 ;
    END
  END f_lk[84]
  PIN f_lk[85]
    DIRECTION INOUT ;
    USE SIGNAL ;
    PORT
      LAYER M4 ;
        RECT 2599.808 630.672 2600.000 630.696 ;
    END
  END f_lk[85]
  PIN f_lk[86]
    DIRECTION INOUT ;
    USE SIGNAL ;
    PORT
      LAYER M4 ;
        RECT 2599.808 630.864 2600.000 630.888 ;
    END
  END f_lk[86]
  PIN f_lk[87]
    DIRECTION INOUT ;
    USE SIGNAL ;
    PORT
      LAYER M4 ;
        RECT 2599.808 631.056 2600.000 631.080 ;
    END
  END f_lk[87]
  PIN f_lk[88]
    DIRECTION INOUT ;
    USE SIGNAL ;
    PORT
      LAYER M4 ;
        RECT 2599.808 631.248 2600.000 631.272 ;
    END
  END f_lk[88]
  PIN f_lk[89]
    DIRECTION INOUT ;
    USE SIGNAL ;
    PORT
      LAYER M4 ;
        RECT 2599.808 631.440 2600.000 631.464 ;
    END
  END f_lk[89]
  PIN f_lk[90]
    DIRECTION INOUT ;
    USE SIGNAL ;
    PORT
      LAYER M4 ;
        RECT 2599.808 631.632 2600.000 631.656 ;
    END
  END f_lk[90]
  PIN f_lk[91]
    DIRECTION INOUT ;
    USE SIGNAL ;
    PORT
      LAYER M4 ;
        RECT 2599.808 631.824 2600.000 631.848 ;
    END
  END f_lk[91]
  PIN f_lk[92]
    DIRECTION INOUT ;
    USE SIGNAL ;
    PORT
      LAYER M4 ;
        RECT 2599.808 632.016 2600.000 632.040 ;
    END
  END f_lk[92]
  PIN f_lk[93]
    DIRECTION INOUT ;
    USE SIGNAL ;
    PORT
      LAYER M4 ;
        RECT 2599.808 632.208 2600.000 632.232 ;
    END
  END f_lk[93]
  PIN f_lk[94]
    DIRECTION INOUT ;
    USE SIGNAL ;
    PORT
      LAYER M4 ;
        RECT 2599.808 632.400 2600.000 632.424 ;
    END
  END f_lk[94]
  PIN f_lk[95]
    DIRECTION INOUT ;
    USE SIGNAL ;
    PORT
      LAYER M4 ;
        RECT 2599.808 632.592 2600.000 632.616 ;
    END
  END f_lk[95]
  PIN f_lk[96]
    DIRECTION INOUT ;
    USE SIGNAL ;
    PORT
      LAYER M4 ;
        RECT 2599.808 632.784 2600.000 632.808 ;
    END
  END f_lk[96]
  PIN f_lk[97]
    DIRECTION INOUT ;
    USE SIGNAL ;
    PORT
      LAYER M4 ;
        RECT 2599.808 632.976 2600.000 633.000 ;
    END
  END f_lk[97]
  PIN f_lk[98]
    DIRECTION INOUT ;
    USE SIGNAL ;
    PORT
      LAYER M4 ;
        RECT 2599.808 633.168 2600.000 633.192 ;
    END
  END f_lk[98]
  PIN f_lk[99]
    DIRECTION INOUT ;
    USE SIGNAL ;
    PORT
      LAYER M4 ;
        RECT 2599.808 633.360 2600.000 633.384 ;
    END
  END f_lk[99]
  PIN f_lk[100]
    DIRECTION INOUT ;
    USE SIGNAL ;
    PORT
      LAYER M4 ;
        RECT 2599.808 633.552 2600.000 633.576 ;
    END
  END f_lk[100]
  PIN f_lk[101]
    DIRECTION INOUT ;
    USE SIGNAL ;
    PORT
      LAYER M4 ;
        RECT 2599.808 633.744 2600.000 633.768 ;
    END
  END f_lk[101]
  PIN f_lk[102]
    DIRECTION INOUT ;
    USE SIGNAL ;
    PORT
      LAYER M4 ;
        RECT 2599.808 633.936 2600.000 633.960 ;
    END
  END f_lk[102]
  PIN f_lk[103]
    DIRECTION INOUT ;
    USE SIGNAL ;
    PORT
      LAYER M4 ;
        RECT 2599.808 634.128 2600.000 634.152 ;
    END
  END f_lk[103]
  PIN f_lk[104]
    DIRECTION INOUT ;
    USE SIGNAL ;
    PORT
      LAYER M4 ;
        RECT 2599.808 634.320 2600.000 634.344 ;
    END
  END f_lk[104]
  PIN f_lk[105]
    DIRECTION INOUT ;
    USE SIGNAL ;
    PORT
      LAYER M4 ;
        RECT 2599.808 634.512 2600.000 634.536 ;
    END
  END f_lk[105]
  PIN f_lk[106]
    DIRECTION INOUT ;
    USE SIGNAL ;
    PORT
      LAYER M4 ;
        RECT 2599.808 634.704 2600.000 634.728 ;
    END
  END f_lk[106]
  PIN f_lk[107]
    DIRECTION INOUT ;
    USE SIGNAL ;
    PORT
      LAYER M4 ;
        RECT 2599.808 634.896 2600.000 634.920 ;
    END
  END f_lk[107]
  PIN f_lk[108]
    DIRECTION INOUT ;
    USE SIGNAL ;
    PORT
      LAYER M4 ;
        RECT 2599.808 635.088 2600.000 635.112 ;
    END
  END f_lk[108]
  PIN f_lk[109]
    DIRECTION INOUT ;
    USE SIGNAL ;
    PORT
      LAYER M4 ;
        RECT 2599.808 635.280 2600.000 635.304 ;
    END
  END f_lk[109]
  PIN f_lk[110]
    DIRECTION INOUT ;
    USE SIGNAL ;
    PORT
      LAYER M4 ;
        RECT 2599.808 635.472 2600.000 635.496 ;
    END
  END f_lk[110]
  PIN f_lk[111]
    DIRECTION INOUT ;
    USE SIGNAL ;
    PORT
      LAYER M4 ;
        RECT 2599.808 635.664 2600.000 635.688 ;
    END
  END f_lk[111]
  PIN f_lk[112]
    DIRECTION INOUT ;
    USE SIGNAL ;
    PORT
      LAYER M4 ;
        RECT 2599.808 635.856 2600.000 635.880 ;
    END
  END f_lk[112]
  PIN f_lk[113]
    DIRECTION INOUT ;
    USE SIGNAL ;
    PORT
      LAYER M4 ;
        RECT 2599.808 636.048 2600.000 636.072 ;
    END
  END f_lk[113]
  PIN f_lk[114]
    DIRECTION INOUT ;
    USE SIGNAL ;
    PORT
      LAYER M4 ;
        RECT 2599.808 636.240 2600.000 636.264 ;
    END
  END f_lk[114]
  PIN f_lk[115]
    DIRECTION INOUT ;
    USE SIGNAL ;
    PORT
      LAYER M4 ;
        RECT 2599.808 636.432 2600.000 636.456 ;
    END
  END f_lk[115]
  PIN f_lk[116]
    DIRECTION INOUT ;
    USE SIGNAL ;
    PORT
      LAYER M4 ;
        RECT 2599.808 636.624 2600.000 636.648 ;
    END
  END f_lk[116]
  PIN f_lk[117]
    DIRECTION INOUT ;
    USE SIGNAL ;
    PORT
      LAYER M4 ;
        RECT 2599.808 636.816 2600.000 636.840 ;
    END
  END f_lk[117]
  PIN f_lk[118]
    DIRECTION INOUT ;
    USE SIGNAL ;
    PORT
      LAYER M4 ;
        RECT 2599.808 637.008 2600.000 637.032 ;
    END
  END f_lk[118]
  PIN f_lk[119]
    DIRECTION INOUT ;
    USE SIGNAL ;
    PORT
      LAYER M4 ;
        RECT 2599.808 637.200 2600.000 637.224 ;
    END
  END f_lk[119]
  PIN f_lk[120]
    DIRECTION INOUT ;
    USE SIGNAL ;
    PORT
      LAYER M4 ;
        RECT 2599.808 637.392 2600.000 637.416 ;
    END
  END f_lk[120]
  PIN f_lk[121]
    DIRECTION INOUT ;
    USE SIGNAL ;
    PORT
      LAYER M4 ;
        RECT 2599.808 637.584 2600.000 637.608 ;
    END
  END f_lk[121]
  PIN f_lk[122]
    DIRECTION INOUT ;
    USE SIGNAL ;
    PORT
      LAYER M4 ;
        RECT 2599.808 637.776 2600.000 637.800 ;
    END
  END f_lk[122]
  PIN f_lk[123]
    DIRECTION INOUT ;
    USE SIGNAL ;
    PORT
      LAYER M4 ;
        RECT 2599.808 637.968 2600.000 637.992 ;
    END
  END f_lk[123]
  PIN f_lk[124]
    DIRECTION INOUT ;
    USE SIGNAL ;
    PORT
      LAYER M4 ;
        RECT 2599.808 638.160 2600.000 638.184 ;
    END
  END f_lk[124]
  PIN f_lk[125]
    DIRECTION INOUT ;
    USE SIGNAL ;
    PORT
      LAYER M4 ;
        RECT 2599.808 638.352 2600.000 638.376 ;
    END
  END f_lk[125]
  PIN f_lk[126]
    DIRECTION INOUT ;
    USE SIGNAL ;
    PORT
      LAYER M4 ;
        RECT 2599.808 638.544 2600.000 638.568 ;
    END
  END f_lk[126]
  PIN f_lk[127]
    DIRECTION INOUT ;
    USE SIGNAL ;
    PORT
      LAYER M4 ;
        RECT 2599.808 638.736 2600.000 638.760 ;
    END
  END f_lk[127]
  PIN f_lk[128]
    DIRECTION INOUT ;
    USE SIGNAL ;
    PORT
      LAYER M4 ;
        RECT 2599.808 638.928 2600.000 638.952 ;
    END
  END f_lk[128]
  PIN f_lk[129]
    DIRECTION INOUT ;
    USE SIGNAL ;
    PORT
      LAYER M4 ;
        RECT 2599.808 639.120 2600.000 639.144 ;
    END
  END f_lk[129]
  PIN f_lk[130]
    DIRECTION INOUT ;
    USE SIGNAL ;
    PORT
      LAYER M4 ;
        RECT 2599.808 639.312 2600.000 639.336 ;
    END
  END f_lk[130]
  PIN f_lk[131]
    DIRECTION INOUT ;
    USE SIGNAL ;
    PORT
      LAYER M4 ;
        RECT 2599.808 639.504 2600.000 639.528 ;
    END
  END f_lk[131]
  PIN f_lk[132]
    DIRECTION INOUT ;
    USE SIGNAL ;
    PORT
      LAYER M4 ;
        RECT 2599.808 639.696 2600.000 639.720 ;
    END
  END f_lk[132]
  PIN f_lk[133]
    DIRECTION INOUT ;
    USE SIGNAL ;
    PORT
      LAYER M4 ;
        RECT 2599.808 639.888 2600.000 639.912 ;
    END
  END f_lk[133]
  PIN f_lk[134]
    DIRECTION INOUT ;
    USE SIGNAL ;
    PORT
      LAYER M4 ;
        RECT 2599.808 640.080 2600.000 640.104 ;
    END
  END f_lk[134]
  PIN f_lk[135]
    DIRECTION INOUT ;
    USE SIGNAL ;
    PORT
      LAYER M4 ;
        RECT 2599.808 640.272 2600.000 640.296 ;
    END
  END f_lk[135]
  PIN f_lk[136]
    DIRECTION INOUT ;
    USE SIGNAL ;
    PORT
      LAYER M4 ;
        RECT 2599.808 640.464 2600.000 640.488 ;
    END
  END f_lk[136]
  PIN f_lk[137]
    DIRECTION INOUT ;
    USE SIGNAL ;
    PORT
      LAYER M4 ;
        RECT 2599.808 640.656 2600.000 640.680 ;
    END
  END f_lk[137]
  PIN f_lk[138]
    DIRECTION INOUT ;
    USE SIGNAL ;
    PORT
      LAYER M4 ;
        RECT 2599.808 640.848 2600.000 640.872 ;
    END
  END f_lk[138]
  PIN f_lk[139]
    DIRECTION INOUT ;
    USE SIGNAL ;
    PORT
      LAYER M4 ;
        RECT 2599.808 641.040 2600.000 641.064 ;
    END
  END f_lk[139]
  PIN f_lk[140]
    DIRECTION INOUT ;
    USE SIGNAL ;
    PORT
      LAYER M4 ;
        RECT 2599.808 641.232 2600.000 641.256 ;
    END
  END f_lk[140]
  PIN f_lk[141]
    DIRECTION INOUT ;
    USE SIGNAL ;
    PORT
      LAYER M4 ;
        RECT 2599.808 641.424 2600.000 641.448 ;
    END
  END f_lk[141]
  PIN f_lk[142]
    DIRECTION INOUT ;
    USE SIGNAL ;
    PORT
      LAYER M4 ;
        RECT 2599.808 641.616 2600.000 641.640 ;
    END
  END f_lk[142]
  PIN f_lk[143]
    DIRECTION INOUT ;
    USE SIGNAL ;
    PORT
      LAYER M4 ;
        RECT 2599.808 641.808 2600.000 641.832 ;
    END
  END f_lk[143]
  PIN f_lk[144]
    DIRECTION INOUT ;
    USE SIGNAL ;
    PORT
      LAYER M4 ;
        RECT 2599.808 642.000 2600.000 642.024 ;
    END
  END f_lk[144]
  PIN f_lk[145]
    DIRECTION INOUT ;
    USE SIGNAL ;
    PORT
      LAYER M4 ;
        RECT 2599.808 642.192 2600.000 642.216 ;
    END
  END f_lk[145]
  PIN f_lk[146]
    DIRECTION INOUT ;
    USE SIGNAL ;
    PORT
      LAYER M4 ;
        RECT 2599.808 642.384 2600.000 642.408 ;
    END
  END f_lk[146]
  PIN f_lk[147]
    DIRECTION INOUT ;
    USE SIGNAL ;
    PORT
      LAYER M4 ;
        RECT 2599.808 642.576 2600.000 642.600 ;
    END
  END f_lk[147]
  PIN f_lk[148]
    DIRECTION INOUT ;
    USE SIGNAL ;
    PORT
      LAYER M4 ;
        RECT 2599.808 642.768 2600.000 642.792 ;
    END
  END f_lk[148]
  PIN f_lk[149]
    DIRECTION INOUT ;
    USE SIGNAL ;
    PORT
      LAYER M4 ;
        RECT 2599.808 642.960 2600.000 642.984 ;
    END
  END f_lk[149]
  PIN f_lk[150]
    DIRECTION INOUT ;
    USE SIGNAL ;
    PORT
      LAYER M4 ;
        RECT 2599.808 643.152 2600.000 643.176 ;
    END
  END f_lk[150]
  PIN f_lk[151]
    DIRECTION INOUT ;
    USE SIGNAL ;
    PORT
      LAYER M4 ;
        RECT 2599.808 643.344 2600.000 643.368 ;
    END
  END f_lk[151]
  PIN f_lk[152]
    DIRECTION INOUT ;
    USE SIGNAL ;
    PORT
      LAYER M4 ;
        RECT 2599.808 643.536 2600.000 643.560 ;
    END
  END f_lk[152]
  PIN f_lk[153]
    DIRECTION INOUT ;
    USE SIGNAL ;
    PORT
      LAYER M4 ;
        RECT 2599.808 643.728 2600.000 643.752 ;
    END
  END f_lk[153]
  PIN f_lk[154]
    DIRECTION INOUT ;
    USE SIGNAL ;
    PORT
      LAYER M4 ;
        RECT 2599.808 643.920 2600.000 643.944 ;
    END
  END f_lk[154]
  PIN f_lk[155]
    DIRECTION INOUT ;
    USE SIGNAL ;
    PORT
      LAYER M4 ;
        RECT 2599.808 644.112 2600.000 644.136 ;
    END
  END f_lk[155]
  PIN f_lk[156]
    DIRECTION INOUT ;
    USE SIGNAL ;
    PORT
      LAYER M4 ;
        RECT 2599.808 644.304 2600.000 644.328 ;
    END
  END f_lk[156]
  PIN f_lk[157]
    DIRECTION INOUT ;
    USE SIGNAL ;
    PORT
      LAYER M4 ;
        RECT 2599.808 644.496 2600.000 644.520 ;
    END
  END f_lk[157]
  PIN f_lk[158]
    DIRECTION INOUT ;
    USE SIGNAL ;
    PORT
      LAYER M4 ;
        RECT 2599.808 644.688 2600.000 644.712 ;
    END
  END f_lk[158]
  PIN f_lk[159]
    DIRECTION INOUT ;
    USE SIGNAL ;
    PORT
      LAYER M4 ;
        RECT 2599.808 644.880 2600.000 644.904 ;
    END
  END f_lk[159]
  PIN f_lk[160]
    DIRECTION INOUT ;
    USE SIGNAL ;
    PORT
      LAYER M4 ;
        RECT 2599.808 645.072 2600.000 645.096 ;
    END
  END f_lk[160]
  PIN f_lk[161]
    DIRECTION INOUT ;
    USE SIGNAL ;
    PORT
      LAYER M4 ;
        RECT 2599.808 645.264 2600.000 645.288 ;
    END
  END f_lk[161]
  PIN f_lk[162]
    DIRECTION INOUT ;
    USE SIGNAL ;
    PORT
      LAYER M4 ;
        RECT 2599.808 645.456 2600.000 645.480 ;
    END
  END f_lk[162]
  PIN f_lk[163]
    DIRECTION INOUT ;
    USE SIGNAL ;
    PORT
      LAYER M4 ;
        RECT 2599.808 645.648 2600.000 645.672 ;
    END
  END f_lk[163]
  PIN f_lk[164]
    DIRECTION INOUT ;
    USE SIGNAL ;
    PORT
      LAYER M4 ;
        RECT 2599.808 645.840 2600.000 645.864 ;
    END
  END f_lk[164]
  PIN f_lk[165]
    DIRECTION INOUT ;
    USE SIGNAL ;
    PORT
      LAYER M4 ;
        RECT 2599.808 646.032 2600.000 646.056 ;
    END
  END f_lk[165]
  PIN f_lk[166]
    DIRECTION INOUT ;
    USE SIGNAL ;
    PORT
      LAYER M4 ;
        RECT 2599.808 646.224 2600.000 646.248 ;
    END
  END f_lk[166]
  PIN f_lk[167]
    DIRECTION INOUT ;
    USE SIGNAL ;
    PORT
      LAYER M4 ;
        RECT 2599.808 646.416 2600.000 646.440 ;
    END
  END f_lk[167]
  PIN f_lk[168]
    DIRECTION INOUT ;
    USE SIGNAL ;
    PORT
      LAYER M4 ;
        RECT 2599.808 646.608 2600.000 646.632 ;
    END
  END f_lk[168]
  PIN f_lk[169]
    DIRECTION INOUT ;
    USE SIGNAL ;
    PORT
      LAYER M4 ;
        RECT 2599.808 646.800 2600.000 646.824 ;
    END
  END f_lk[169]
  PIN f_lk[170]
    DIRECTION INOUT ;
    USE SIGNAL ;
    PORT
      LAYER M4 ;
        RECT 2599.808 646.992 2600.000 647.016 ;
    END
  END f_lk[170]
  PIN f_lk[171]
    DIRECTION INOUT ;
    USE SIGNAL ;
    PORT
      LAYER M4 ;
        RECT 2599.808 647.184 2600.000 647.208 ;
    END
  END f_lk[171]
  PIN f_lk[172]
    DIRECTION INOUT ;
    USE SIGNAL ;
    PORT
      LAYER M4 ;
        RECT 2599.808 647.376 2600.000 647.400 ;
    END
  END f_lk[172]
  PIN f_lk[173]
    DIRECTION INOUT ;
    USE SIGNAL ;
    PORT
      LAYER M4 ;
        RECT 2599.808 647.568 2600.000 647.592 ;
    END
  END f_lk[173]
  PIN f_lk[174]
    DIRECTION INOUT ;
    USE SIGNAL ;
    PORT
      LAYER M4 ;
        RECT 2599.808 647.760 2600.000 647.784 ;
    END
  END f_lk[174]
  PIN f_lk[175]
    DIRECTION INOUT ;
    USE SIGNAL ;
    PORT
      LAYER M4 ;
        RECT 2599.808 647.952 2600.000 647.976 ;
    END
  END f_lk[175]
  PIN f_lk[176]
    DIRECTION INOUT ;
    USE SIGNAL ;
    PORT
      LAYER M4 ;
        RECT 2599.808 648.144 2600.000 648.168 ;
    END
  END f_lk[176]
  PIN f_lk[177]
    DIRECTION INOUT ;
    USE SIGNAL ;
    PORT
      LAYER M4 ;
        RECT 2599.808 648.336 2600.000 648.360 ;
    END
  END f_lk[177]
  PIN f_lk[178]
    DIRECTION INOUT ;
    USE SIGNAL ;
    PORT
      LAYER M4 ;
        RECT 2599.808 648.528 2600.000 648.552 ;
    END
  END f_lk[178]
  PIN f_lk[179]
    DIRECTION INOUT ;
    USE SIGNAL ;
    PORT
      LAYER M4 ;
        RECT 2599.808 648.720 2600.000 648.744 ;
    END
  END f_lk[179]
  PIN f_lk[180]
    DIRECTION INOUT ;
    USE SIGNAL ;
    PORT
      LAYER M4 ;
        RECT 2599.808 648.912 2600.000 648.936 ;
    END
  END f_lk[180]
  PIN f_lk[181]
    DIRECTION INOUT ;
    USE SIGNAL ;
    PORT
      LAYER M4 ;
        RECT 2599.808 649.104 2600.000 649.128 ;
    END
  END f_lk[181]
  PIN f_lk[182]
    DIRECTION INOUT ;
    USE SIGNAL ;
    PORT
      LAYER M4 ;
        RECT 2599.808 649.296 2600.000 649.320 ;
    END
  END f_lk[182]
  PIN f_lk[183]
    DIRECTION INOUT ;
    USE SIGNAL ;
    PORT
      LAYER M4 ;
        RECT 2599.808 649.488 2600.000 649.512 ;
    END
  END f_lk[183]
  PIN f_lk[184]
    DIRECTION INOUT ;
    USE SIGNAL ;
    PORT
      LAYER M4 ;
        RECT 2599.808 649.680 2600.000 649.704 ;
    END
  END f_lk[184]
  PIN f_lk[185]
    DIRECTION INOUT ;
    USE SIGNAL ;
    PORT
      LAYER M4 ;
        RECT 2599.808 649.872 2600.000 649.896 ;
    END
  END f_lk[185]
  PIN f_lk[186]
    DIRECTION INOUT ;
    USE SIGNAL ;
    PORT
      LAYER M4 ;
        RECT 2599.808 650.064 2600.000 650.088 ;
    END
  END f_lk[186]
  PIN f_lk[187]
    DIRECTION INOUT ;
    USE SIGNAL ;
    PORT
      LAYER M4 ;
        RECT 2599.808 650.256 2600.000 650.280 ;
    END
  END f_lk[187]
  PIN f_lk[188]
    DIRECTION INOUT ;
    USE SIGNAL ;
    PORT
      LAYER M4 ;
        RECT 2599.808 650.448 2600.000 650.472 ;
    END
  END f_lk[188]
  PIN f_lk[189]
    DIRECTION INOUT ;
    USE SIGNAL ;
    PORT
      LAYER M4 ;
        RECT 2599.808 650.640 2600.000 650.664 ;
    END
  END f_lk[189]
  PIN f_lk[190]
    DIRECTION INOUT ;
    USE SIGNAL ;
    PORT
      LAYER M4 ;
        RECT 2599.808 650.832 2600.000 650.856 ;
    END
  END f_lk[190]
  PIN f_lk[191]
    DIRECTION INOUT ;
    USE SIGNAL ;
    PORT
      LAYER M4 ;
        RECT 2599.808 651.024 2600.000 651.048 ;
    END
  END f_lk[191]
  PIN f_lk[192]
    DIRECTION INOUT ;
    USE SIGNAL ;
    PORT
      LAYER M4 ;
        RECT 2599.808 651.216 2600.000 651.240 ;
    END
  END f_lk[192]
  PIN f_lk[193]
    DIRECTION INOUT ;
    USE SIGNAL ;
    PORT
      LAYER M4 ;
        RECT 2599.808 651.408 2600.000 651.432 ;
    END
  END f_lk[193]
  PIN f_lk[194]
    DIRECTION INOUT ;
    USE SIGNAL ;
    PORT
      LAYER M4 ;
        RECT 2599.808 651.600 2600.000 651.624 ;
    END
  END f_lk[194]
  PIN f_lk[195]
    DIRECTION INOUT ;
    USE SIGNAL ;
    PORT
      LAYER M4 ;
        RECT 2599.808 651.792 2600.000 651.816 ;
    END
  END f_lk[195]
  PIN f_lk[196]
    DIRECTION INOUT ;
    USE SIGNAL ;
    PORT
      LAYER M4 ;
        RECT 2599.808 651.984 2600.000 652.008 ;
    END
  END f_lk[196]
  PIN f_lk[197]
    DIRECTION INOUT ;
    USE SIGNAL ;
    PORT
      LAYER M4 ;
        RECT 2599.808 652.176 2600.000 652.200 ;
    END
  END f_lk[197]
  PIN f_lk[198]
    DIRECTION INOUT ;
    USE SIGNAL ;
    PORT
      LAYER M4 ;
        RECT 2599.808 652.368 2600.000 652.392 ;
    END
  END f_lk[198]
  PIN f_lk[199]
    DIRECTION INOUT ;
    USE SIGNAL ;
    PORT
      LAYER M4 ;
        RECT 2599.808 652.560 2600.000 652.584 ;
    END
  END f_lk[199]
  PIN f_lk[200]
    DIRECTION INOUT ;
    USE SIGNAL ;
    PORT
      LAYER M4 ;
        RECT 2599.808 652.752 2600.000 652.776 ;
    END
  END f_lk[200]
  PIN f_lk[201]
    DIRECTION INOUT ;
    USE SIGNAL ;
    PORT
      LAYER M4 ;
        RECT 2599.808 652.944 2600.000 652.968 ;
    END
  END f_lk[201]
  PIN f_lk[202]
    DIRECTION INOUT ;
    USE SIGNAL ;
    PORT
      LAYER M4 ;
        RECT 2599.808 653.136 2600.000 653.160 ;
    END
  END f_lk[202]
  PIN f_lk[203]
    DIRECTION INOUT ;
    USE SIGNAL ;
    PORT
      LAYER M4 ;
        RECT 2599.808 653.328 2600.000 653.352 ;
    END
  END f_lk[203]
  PIN f_lk[204]
    DIRECTION INOUT ;
    USE SIGNAL ;
    PORT
      LAYER M4 ;
        RECT 2599.808 653.520 2600.000 653.544 ;
    END
  END f_lk[204]
  PIN f_lk[205]
    DIRECTION INOUT ;
    USE SIGNAL ;
    PORT
      LAYER M4 ;
        RECT 2599.808 653.712 2600.000 653.736 ;
    END
  END f_lk[205]
  PIN f_lk[206]
    DIRECTION INOUT ;
    USE SIGNAL ;
    PORT
      LAYER M4 ;
        RECT 2599.808 653.904 2600.000 653.928 ;
    END
  END f_lk[206]
  PIN f_lk[207]
    DIRECTION INOUT ;
    USE SIGNAL ;
    PORT
      LAYER M4 ;
        RECT 2599.808 654.096 2600.000 654.120 ;
    END
  END f_lk[207]
  PIN f_lk[208]
    DIRECTION INOUT ;
    USE SIGNAL ;
    PORT
      LAYER M4 ;
        RECT 2599.808 654.288 2600.000 654.312 ;
    END
  END f_lk[208]
  PIN f_lk[209]
    DIRECTION INOUT ;
    USE SIGNAL ;
    PORT
      LAYER M4 ;
        RECT 2599.808 654.480 2600.000 654.504 ;
    END
  END f_lk[209]
  PIN f_lk[210]
    DIRECTION INOUT ;
    USE SIGNAL ;
    PORT
      LAYER M4 ;
        RECT 2599.808 654.672 2600.000 654.696 ;
    END
  END f_lk[210]
  PIN f_lk[211]
    DIRECTION INOUT ;
    USE SIGNAL ;
    PORT
      LAYER M4 ;
        RECT 2599.808 654.864 2600.000 654.888 ;
    END
  END f_lk[211]
  PIN f_lk[212]
    DIRECTION INOUT ;
    USE SIGNAL ;
    PORT
      LAYER M4 ;
        RECT 2599.808 655.056 2600.000 655.080 ;
    END
  END f_lk[212]
  PIN f_lk[213]
    DIRECTION INOUT ;
    USE SIGNAL ;
    PORT
      LAYER M4 ;
        RECT 2599.808 655.248 2600.000 655.272 ;
    END
  END f_lk[213]
  PIN f_lk[214]
    DIRECTION INOUT ;
    USE SIGNAL ;
    PORT
      LAYER M4 ;
        RECT 2599.808 655.440 2600.000 655.464 ;
    END
  END f_lk[214]
  PIN f_lk[215]
    DIRECTION INOUT ;
    USE SIGNAL ;
    PORT
      LAYER M4 ;
        RECT 2599.808 655.632 2600.000 655.656 ;
    END
  END f_lk[215]
  PIN f_lk[216]
    DIRECTION INOUT ;
    USE SIGNAL ;
    PORT
      LAYER M4 ;
        RECT 2599.808 655.824 2600.000 655.848 ;
    END
  END f_lk[216]
  PIN f_lk[217]
    DIRECTION INOUT ;
    USE SIGNAL ;
    PORT
      LAYER M4 ;
        RECT 2599.808 656.016 2600.000 656.040 ;
    END
  END f_lk[217]
  PIN f_lk[218]
    DIRECTION INOUT ;
    USE SIGNAL ;
    PORT
      LAYER M4 ;
        RECT 2599.808 656.208 2600.000 656.232 ;
    END
  END f_lk[218]
  PIN f_lk[219]
    DIRECTION INOUT ;
    USE SIGNAL ;
    PORT
      LAYER M4 ;
        RECT 2599.808 656.400 2600.000 656.424 ;
    END
  END f_lk[219]
  PIN f_lk[220]
    DIRECTION INOUT ;
    USE SIGNAL ;
    PORT
      LAYER M4 ;
        RECT 2599.808 656.592 2600.000 656.616 ;
    END
  END f_lk[220]
  PIN f_lk[221]
    DIRECTION INOUT ;
    USE SIGNAL ;
    PORT
      LAYER M4 ;
        RECT 2599.808 656.784 2600.000 656.808 ;
    END
  END f_lk[221]
  PIN f_lk[222]
    DIRECTION INOUT ;
    USE SIGNAL ;
    PORT
      LAYER M4 ;
        RECT 2599.808 656.976 2600.000 657.000 ;
    END
  END f_lk[222]
  PIN f_lk[223]
    DIRECTION INOUT ;
    USE SIGNAL ;
    PORT
      LAYER M4 ;
        RECT 2599.808 657.168 2600.000 657.192 ;
    END
  END f_lk[223]
  PIN f_lk[224]
    DIRECTION INOUT ;
    USE SIGNAL ;
    PORT
      LAYER M4 ;
        RECT 2599.808 657.360 2600.000 657.384 ;
    END
  END f_lk[224]
  PIN f_lk[225]
    DIRECTION INOUT ;
    USE SIGNAL ;
    PORT
      LAYER M4 ;
        RECT 2599.808 657.552 2600.000 657.576 ;
    END
  END f_lk[225]
  PIN f_lk[226]
    DIRECTION INOUT ;
    USE SIGNAL ;
    PORT
      LAYER M4 ;
        RECT 2599.808 657.744 2600.000 657.768 ;
    END
  END f_lk[226]
  PIN f_lk[227]
    DIRECTION INOUT ;
    USE SIGNAL ;
    PORT
      LAYER M4 ;
        RECT 2599.808 657.936 2600.000 657.960 ;
    END
  END f_lk[227]
  PIN f_lk[228]
    DIRECTION INOUT ;
    USE SIGNAL ;
    PORT
      LAYER M4 ;
        RECT 2599.808 658.128 2600.000 658.152 ;
    END
  END f_lk[228]
  PIN f_lk[229]
    DIRECTION INOUT ;
    USE SIGNAL ;
    PORT
      LAYER M4 ;
        RECT 2599.808 658.320 2600.000 658.344 ;
    END
  END f_lk[229]
  PIN f_lk[230]
    DIRECTION INOUT ;
    USE SIGNAL ;
    PORT
      LAYER M4 ;
        RECT 2599.808 658.512 2600.000 658.536 ;
    END
  END f_lk[230]
  PIN f_lk[231]
    DIRECTION INOUT ;
    USE SIGNAL ;
    PORT
      LAYER M4 ;
        RECT 2599.808 658.704 2600.000 658.728 ;
    END
  END f_lk[231]
  PIN f_lk[232]
    DIRECTION INOUT ;
    USE SIGNAL ;
    PORT
      LAYER M4 ;
        RECT 2599.808 658.896 2600.000 658.920 ;
    END
  END f_lk[232]
  PIN f_lk[233]
    DIRECTION INOUT ;
    USE SIGNAL ;
    PORT
      LAYER M4 ;
        RECT 2599.808 659.088 2600.000 659.112 ;
    END
  END f_lk[233]
  PIN f_lk[234]
    DIRECTION INOUT ;
    USE SIGNAL ;
    PORT
      LAYER M4 ;
        RECT 2599.808 659.280 2600.000 659.304 ;
    END
  END f_lk[234]
  PIN f_lk[235]
    DIRECTION INOUT ;
    USE SIGNAL ;
    PORT
      LAYER M4 ;
        RECT 2599.808 659.472 2600.000 659.496 ;
    END
  END f_lk[235]
  PIN f_lk[236]
    DIRECTION INOUT ;
    USE SIGNAL ;
    PORT
      LAYER M4 ;
        RECT 2599.808 659.664 2600.000 659.688 ;
    END
  END f_lk[236]
  PIN f_lk[237]
    DIRECTION INOUT ;
    USE SIGNAL ;
    PORT
      LAYER M4 ;
        RECT 2599.808 659.856 2600.000 659.880 ;
    END
  END f_lk[237]
  PIN f_lk[238]
    DIRECTION INOUT ;
    USE SIGNAL ;
    PORT
      LAYER M4 ;
        RECT 2599.808 660.048 2600.000 660.072 ;
    END
  END f_lk[238]
  PIN f_lk[239]
    DIRECTION INOUT ;
    USE SIGNAL ;
    PORT
      LAYER M4 ;
        RECT 2599.808 660.240 2600.000 660.264 ;
    END
  END f_lk[239]
  PIN f_lk[240]
    DIRECTION INOUT ;
    USE SIGNAL ;
    PORT
      LAYER M4 ;
        RECT 2599.808 660.432 2600.000 660.456 ;
    END
  END f_lk[240]
  PIN f_lk[241]
    DIRECTION INOUT ;
    USE SIGNAL ;
    PORT
      LAYER M4 ;
        RECT 2599.808 660.624 2600.000 660.648 ;
    END
  END f_lk[241]
  PIN f_lk[242]
    DIRECTION INOUT ;
    USE SIGNAL ;
    PORT
      LAYER M4 ;
        RECT 2599.808 660.816 2600.000 660.840 ;
    END
  END f_lk[242]
  PIN f_lk[243]
    DIRECTION INOUT ;
    USE SIGNAL ;
    PORT
      LAYER M4 ;
        RECT 2599.808 661.008 2600.000 661.032 ;
    END
  END f_lk[243]
  PIN f_lk[244]
    DIRECTION INOUT ;
    USE SIGNAL ;
    PORT
      LAYER M4 ;
        RECT 2599.808 661.200 2600.000 661.224 ;
    END
  END f_lk[244]
  PIN f_lk[245]
    DIRECTION INOUT ;
    USE SIGNAL ;
    PORT
      LAYER M4 ;
        RECT 2599.808 661.392 2600.000 661.416 ;
    END
  END f_lk[245]
  PIN f_lk[246]
    DIRECTION INOUT ;
    USE SIGNAL ;
    PORT
      LAYER M4 ;
        RECT 2599.808 661.584 2600.000 661.608 ;
    END
  END f_lk[246]
  PIN f_lk[247]
    DIRECTION INOUT ;
    USE SIGNAL ;
    PORT
      LAYER M4 ;
        RECT 2599.808 661.776 2600.000 661.800 ;
    END
  END f_lk[247]
  PIN f_lk[248]
    DIRECTION INOUT ;
    USE SIGNAL ;
    PORT
      LAYER M4 ;
        RECT 2599.808 661.968 2600.000 661.992 ;
    END
  END f_lk[248]
  PIN f_lk[249]
    DIRECTION INOUT ;
    USE SIGNAL ;
    PORT
      LAYER M4 ;
        RECT 2599.808 662.160 2600.000 662.184 ;
    END
  END f_lk[249]
  PIN f_lk[250]
    DIRECTION INOUT ;
    USE SIGNAL ;
    PORT
      LAYER M4 ;
        RECT 2599.808 662.352 2600.000 662.376 ;
    END
  END f_lk[250]
  PIN f_lk[251]
    DIRECTION INOUT ;
    USE SIGNAL ;
    PORT
      LAYER M4 ;
        RECT 2599.808 662.544 2600.000 662.568 ;
    END
  END f_lk[251]
  PIN f_lk[252]
    DIRECTION INOUT ;
    USE SIGNAL ;
    PORT
      LAYER M4 ;
        RECT 2599.808 662.736 2600.000 662.760 ;
    END
  END f_lk[252]
  PIN f_lk[253]
    DIRECTION INOUT ;
    USE SIGNAL ;
    PORT
      LAYER M4 ;
        RECT 2599.808 662.928 2600.000 662.952 ;
    END
  END f_lk[253]
  PIN f_lk[254]
    DIRECTION INOUT ;
    USE SIGNAL ;
    PORT
      LAYER M4 ;
        RECT 2599.808 663.120 2600.000 663.144 ;
    END
  END f_lk[254]
  PIN f_lk[255]
    DIRECTION INOUT ;
    USE SIGNAL ;
    PORT
      LAYER M4 ;
        RECT 2599.808 663.312 2600.000 663.336 ;
    END
  END f_lk[255]
  PIN f_lk[256]
    DIRECTION INOUT ;
    USE SIGNAL ;
    PORT
      LAYER M4 ;
        RECT 2599.808 663.504 2600.000 663.528 ;
    END
  END f_lk[256]
  PIN f_lk[257]
    DIRECTION INOUT ;
    USE SIGNAL ;
    PORT
      LAYER M4 ;
        RECT 2599.808 663.696 2600.000 663.720 ;
    END
  END f_lk[257]
  PIN f_lk[258]
    DIRECTION INOUT ;
    USE SIGNAL ;
    PORT
      LAYER M4 ;
        RECT 2599.808 663.888 2600.000 663.912 ;
    END
  END f_lk[258]
  PIN f_lk[259]
    DIRECTION INOUT ;
    USE SIGNAL ;
    PORT
      LAYER M4 ;
        RECT 2599.808 664.080 2600.000 664.104 ;
    END
  END f_lk[259]
  PIN f_lk[260]
    DIRECTION INOUT ;
    USE SIGNAL ;
    PORT
      LAYER M4 ;
        RECT 2599.808 664.272 2600.000 664.296 ;
    END
  END f_lk[260]
  PIN f_lk[261]
    DIRECTION INOUT ;
    USE SIGNAL ;
    PORT
      LAYER M4 ;
        RECT 2599.808 664.464 2600.000 664.488 ;
    END
  END f_lk[261]
  PIN f_lk[262]
    DIRECTION INOUT ;
    USE SIGNAL ;
    PORT
      LAYER M4 ;
        RECT 2599.808 664.656 2600.000 664.680 ;
    END
  END f_lk[262]
  PIN f_lk[263]
    DIRECTION INOUT ;
    USE SIGNAL ;
    PORT
      LAYER M4 ;
        RECT 2599.808 664.848 2600.000 664.872 ;
    END
  END f_lk[263]
  PIN f_lk[264]
    DIRECTION INOUT ;
    USE SIGNAL ;
    PORT
      LAYER M4 ;
        RECT 2599.808 665.040 2600.000 665.064 ;
    END
  END f_lk[264]
  PIN f_lk[265]
    DIRECTION INOUT ;
    USE SIGNAL ;
    PORT
      LAYER M4 ;
        RECT 2599.808 665.232 2600.000 665.256 ;
    END
  END f_lk[265]
  PIN f_lk[266]
    DIRECTION INOUT ;
    USE SIGNAL ;
    PORT
      LAYER M4 ;
        RECT 2599.808 665.424 2600.000 665.448 ;
    END
  END f_lk[266]
  PIN f_lk[267]
    DIRECTION INOUT ;
    USE SIGNAL ;
    PORT
      LAYER M4 ;
        RECT 2599.808 665.616 2600.000 665.640 ;
    END
  END f_lk[267]
  PIN f_lk[268]
    DIRECTION INOUT ;
    USE SIGNAL ;
    PORT
      LAYER M4 ;
        RECT 2599.808 665.808 2600.000 665.832 ;
    END
  END f_lk[268]
  PIN f_lk[269]
    DIRECTION INOUT ;
    USE SIGNAL ;
    PORT
      LAYER M4 ;
        RECT 2599.808 666.000 2600.000 666.024 ;
    END
  END f_lk[269]
  PIN f_lk[270]
    DIRECTION INOUT ;
    USE SIGNAL ;
    PORT
      LAYER M4 ;
        RECT 2599.808 666.192 2600.000 666.216 ;
    END
  END f_lk[270]
  PIN f_lk[271]
    DIRECTION INOUT ;
    USE SIGNAL ;
    PORT
      LAYER M4 ;
        RECT 2599.808 666.384 2600.000 666.408 ;
    END
  END f_lk[271]
  PIN f_lk[272]
    DIRECTION INOUT ;
    USE SIGNAL ;
    PORT
      LAYER M4 ;
        RECT 2599.808 666.576 2600.000 666.600 ;
    END
  END f_lk[272]
  PIN f_lk[273]
    DIRECTION INOUT ;
    USE SIGNAL ;
    PORT
      LAYER M4 ;
        RECT 2599.808 666.768 2600.000 666.792 ;
    END
  END f_lk[273]
  PIN f_lk[274]
    DIRECTION INOUT ;
    USE SIGNAL ;
    PORT
      LAYER M4 ;
        RECT 2599.808 666.960 2600.000 666.984 ;
    END
  END f_lk[274]
  PIN f_lk[275]
    DIRECTION INOUT ;
    USE SIGNAL ;
    PORT
      LAYER M4 ;
        RECT 2599.808 667.152 2600.000 667.176 ;
    END
  END f_lk[275]
  PIN f_lk[276]
    DIRECTION INOUT ;
    USE SIGNAL ;
    PORT
      LAYER M4 ;
        RECT 2599.808 667.344 2600.000 667.368 ;
    END
  END f_lk[276]
  PIN f_lk[277]
    DIRECTION INOUT ;
    USE SIGNAL ;
    PORT
      LAYER M4 ;
        RECT 2599.808 667.536 2600.000 667.560 ;
    END
  END f_lk[277]
  PIN f_lk[278]
    DIRECTION INOUT ;
    USE SIGNAL ;
    PORT
      LAYER M4 ;
        RECT 2599.808 667.728 2600.000 667.752 ;
    END
  END f_lk[278]
  PIN f_lk[279]
    DIRECTION INOUT ;
    USE SIGNAL ;
    PORT
      LAYER M4 ;
        RECT 2599.808 667.920 2600.000 667.944 ;
    END
  END f_lk[279]
  PIN f_lk[280]
    DIRECTION INOUT ;
    USE SIGNAL ;
    PORT
      LAYER M4 ;
        RECT 2599.808 668.112 2600.000 668.136 ;
    END
  END f_lk[280]
  PIN f_lk[281]
    DIRECTION INOUT ;
    USE SIGNAL ;
    PORT
      LAYER M4 ;
        RECT 2599.808 668.304 2600.000 668.328 ;
    END
  END f_lk[281]
  PIN f_lk[282]
    DIRECTION INOUT ;
    USE SIGNAL ;
    PORT
      LAYER M4 ;
        RECT 2599.808 668.496 2600.000 668.520 ;
    END
  END f_lk[282]
  PIN f_lk[283]
    DIRECTION INOUT ;
    USE SIGNAL ;
    PORT
      LAYER M4 ;
        RECT 2599.808 668.688 2600.000 668.712 ;
    END
  END f_lk[283]
  PIN f_lk[284]
    DIRECTION INOUT ;
    USE SIGNAL ;
    PORT
      LAYER M4 ;
        RECT 2599.808 668.880 2600.000 668.904 ;
    END
  END f_lk[284]
  PIN f_lk[285]
    DIRECTION INOUT ;
    USE SIGNAL ;
    PORT
      LAYER M4 ;
        RECT 2599.808 669.072 2600.000 669.096 ;
    END
  END f_lk[285]
  PIN f_lk[286]
    DIRECTION INOUT ;
    USE SIGNAL ;
    PORT
      LAYER M4 ;
        RECT 2599.808 669.264 2600.000 669.288 ;
    END
  END f_lk[286]
  PIN f_lk[287]
    DIRECTION INOUT ;
    USE SIGNAL ;
    PORT
      LAYER M4 ;
        RECT 2599.808 669.456 2600.000 669.480 ;
    END
  END f_lk[287]
  PIN f_lk[288]
    DIRECTION INOUT ;
    USE SIGNAL ;
    PORT
      LAYER M4 ;
        RECT 2599.808 669.648 2600.000 669.672 ;
    END
  END f_lk[288]
  PIN f_lk[289]
    DIRECTION INOUT ;
    USE SIGNAL ;
    PORT
      LAYER M4 ;
        RECT 2599.808 669.840 2600.000 669.864 ;
    END
  END f_lk[289]
  PIN f_lk[290]
    DIRECTION INOUT ;
    USE SIGNAL ;
    PORT
      LAYER M4 ;
        RECT 2599.808 670.032 2600.000 670.056 ;
    END
  END f_lk[290]
  PIN f_lk[291]
    DIRECTION INOUT ;
    USE SIGNAL ;
    PORT
      LAYER M4 ;
        RECT 2599.808 670.224 2600.000 670.248 ;
    END
  END f_lk[291]
  PIN f_lk[292]
    DIRECTION INOUT ;
    USE SIGNAL ;
    PORT
      LAYER M4 ;
        RECT 2599.808 670.416 2600.000 670.440 ;
    END
  END f_lk[292]
  PIN f_lk[293]
    DIRECTION INOUT ;
    USE SIGNAL ;
    PORT
      LAYER M4 ;
        RECT 2599.808 670.608 2600.000 670.632 ;
    END
  END f_lk[293]
  PIN f_lk[294]
    DIRECTION INOUT ;
    USE SIGNAL ;
    PORT
      LAYER M4 ;
        RECT 2599.808 670.800 2600.000 670.824 ;
    END
  END f_lk[294]
  PIN f_lk[295]
    DIRECTION INOUT ;
    USE SIGNAL ;
    PORT
      LAYER M4 ;
        RECT 2599.808 670.992 2600.000 671.016 ;
    END
  END f_lk[295]
  PIN f_lk[296]
    DIRECTION INOUT ;
    USE SIGNAL ;
    PORT
      LAYER M4 ;
        RECT 2599.808 671.184 2600.000 671.208 ;
    END
  END f_lk[296]
  PIN f_lk[297]
    DIRECTION INOUT ;
    USE SIGNAL ;
    PORT
      LAYER M4 ;
        RECT 2599.808 671.376 2600.000 671.400 ;
    END
  END f_lk[297]
  PIN f_lk[298]
    DIRECTION INOUT ;
    USE SIGNAL ;
    PORT
      LAYER M4 ;
        RECT 2599.808 671.568 2600.000 671.592 ;
    END
  END f_lk[298]
  PIN f_lk[299]
    DIRECTION INOUT ;
    USE SIGNAL ;
    PORT
      LAYER M4 ;
        RECT 2599.808 671.760 2600.000 671.784 ;
    END
  END f_lk[299]
  PIN f_lk[300]
    DIRECTION INOUT ;
    USE SIGNAL ;
    PORT
      LAYER M4 ;
        RECT 2599.808 671.952 2600.000 671.976 ;
    END
  END f_lk[300]
  PIN f_lk[301]
    DIRECTION INOUT ;
    USE SIGNAL ;
    PORT
      LAYER M4 ;
        RECT 2599.808 672.144 2600.000 672.168 ;
    END
  END f_lk[301]
  PIN f_lk[302]
    DIRECTION INOUT ;
    USE SIGNAL ;
    PORT
      LAYER M4 ;
        RECT 2599.808 672.336 2600.000 672.360 ;
    END
  END f_lk[302]
  PIN f_lk[303]
    DIRECTION INOUT ;
    USE SIGNAL ;
    PORT
      LAYER M4 ;
        RECT 2599.808 672.528 2600.000 672.552 ;
    END
  END f_lk[303]
  PIN f_lk[304]
    DIRECTION INOUT ;
    USE SIGNAL ;
    PORT
      LAYER M4 ;
        RECT 2599.808 672.720 2600.000 672.744 ;
    END
  END f_lk[304]
  PIN f_lk[305]
    DIRECTION INOUT ;
    USE SIGNAL ;
    PORT
      LAYER M4 ;
        RECT 2599.808 672.912 2600.000 672.936 ;
    END
  END f_lk[305]
  PIN f_lk[306]
    DIRECTION INOUT ;
    USE SIGNAL ;
    PORT
      LAYER M4 ;
        RECT 2599.808 673.104 2600.000 673.128 ;
    END
  END f_lk[306]
  PIN f_lk[307]
    DIRECTION INOUT ;
    USE SIGNAL ;
    PORT
      LAYER M4 ;
        RECT 2599.808 673.296 2600.000 673.320 ;
    END
  END f_lk[307]
  PIN f_lk[308]
    DIRECTION INOUT ;
    USE SIGNAL ;
    PORT
      LAYER M4 ;
        RECT 2599.808 673.488 2600.000 673.512 ;
    END
  END f_lk[308]
  PIN f_lk[309]
    DIRECTION INOUT ;
    USE SIGNAL ;
    PORT
      LAYER M4 ;
        RECT 2599.808 673.680 2600.000 673.704 ;
    END
  END f_lk[309]
  PIN f_lk[310]
    DIRECTION INOUT ;
    USE SIGNAL ;
    PORT
      LAYER M4 ;
        RECT 2599.808 673.872 2600.000 673.896 ;
    END
  END f_lk[310]
  PIN f_lk[311]
    DIRECTION INOUT ;
    USE SIGNAL ;
    PORT
      LAYER M4 ;
        RECT 2599.808 674.064 2600.000 674.088 ;
    END
  END f_lk[311]
  PIN f_lk[312]
    DIRECTION INOUT ;
    USE SIGNAL ;
    PORT
      LAYER M4 ;
        RECT 2599.808 674.256 2600.000 674.280 ;
    END
  END f_lk[312]
  PIN f_lk[313]
    DIRECTION INOUT ;
    USE SIGNAL ;
    PORT
      LAYER M4 ;
        RECT 2599.808 674.448 2600.000 674.472 ;
    END
  END f_lk[313]
  PIN f_lk[314]
    DIRECTION INOUT ;
    USE SIGNAL ;
    PORT
      LAYER M4 ;
        RECT 2599.808 674.640 2600.000 674.664 ;
    END
  END f_lk[314]
  PIN f_lk[315]
    DIRECTION INOUT ;
    USE SIGNAL ;
    PORT
      LAYER M4 ;
        RECT 2599.808 674.832 2600.000 674.856 ;
    END
  END f_lk[315]
  PIN f_lk[316]
    DIRECTION INOUT ;
    USE SIGNAL ;
    PORT
      LAYER M4 ;
        RECT 2599.808 675.024 2600.000 675.048 ;
    END
  END f_lk[316]
  PIN f_lk[317]
    DIRECTION INOUT ;
    USE SIGNAL ;
    PORT
      LAYER M4 ;
        RECT 2599.808 675.216 2600.000 675.240 ;
    END
  END f_lk[317]
  PIN f_lk[318]
    DIRECTION INOUT ;
    USE SIGNAL ;
    PORT
      LAYER M4 ;
        RECT 2599.808 675.408 2600.000 675.432 ;
    END
  END f_lk[318]
  PIN f_lk[319]
    DIRECTION INOUT ;
    USE SIGNAL ;
    PORT
      LAYER M4 ;
        RECT 2599.808 675.600 2600.000 675.624 ;
    END
  END f_lk[319]
  PIN f_lk[320]
    DIRECTION INOUT ;
    USE SIGNAL ;
    PORT
      LAYER M4 ;
        RECT 2599.808 675.792 2600.000 675.816 ;
    END
  END f_lk[320]
  PIN f_lk[321]
    DIRECTION INOUT ;
    USE SIGNAL ;
    PORT
      LAYER M4 ;
        RECT 2599.808 675.984 2600.000 676.008 ;
    END
  END f_lk[321]
  PIN f_lk[322]
    DIRECTION INOUT ;
    USE SIGNAL ;
    PORT
      LAYER M4 ;
        RECT 2599.808 676.176 2600.000 676.200 ;
    END
  END f_lk[322]
  PIN f_lk[323]
    DIRECTION INOUT ;
    USE SIGNAL ;
    PORT
      LAYER M4 ;
        RECT 2599.808 676.368 2600.000 676.392 ;
    END
  END f_lk[323]
  PIN f_lk[324]
    DIRECTION INOUT ;
    USE SIGNAL ;
    PORT
      LAYER M4 ;
        RECT 2599.808 676.560 2600.000 676.584 ;
    END
  END f_lk[324]
  PIN f_lk[325]
    DIRECTION INOUT ;
    USE SIGNAL ;
    PORT
      LAYER M4 ;
        RECT 2599.808 676.752 2600.000 676.776 ;
    END
  END f_lk[325]
  PIN f_lk[326]
    DIRECTION INOUT ;
    USE SIGNAL ;
    PORT
      LAYER M4 ;
        RECT 2599.808 676.944 2600.000 676.968 ;
    END
  END f_lk[326]
  PIN f_lk[327]
    DIRECTION INOUT ;
    USE SIGNAL ;
    PORT
      LAYER M4 ;
        RECT 2599.808 677.136 2600.000 677.160 ;
    END
  END f_lk[327]
  PIN f_lk[328]
    DIRECTION INOUT ;
    USE SIGNAL ;
    PORT
      LAYER M4 ;
        RECT 2599.808 677.328 2600.000 677.352 ;
    END
  END f_lk[328]
  PIN f_lk[329]
    DIRECTION INOUT ;
    USE SIGNAL ;
    PORT
      LAYER M4 ;
        RECT 2599.808 677.520 2600.000 677.544 ;
    END
  END f_lk[329]
  PIN f_lk[330]
    DIRECTION INOUT ;
    USE SIGNAL ;
    PORT
      LAYER M4 ;
        RECT 2599.808 677.712 2600.000 677.736 ;
    END
  END f_lk[330]
  PIN f_lk[331]
    DIRECTION INOUT ;
    USE SIGNAL ;
    PORT
      LAYER M4 ;
        RECT 2599.808 677.904 2600.000 677.928 ;
    END
  END f_lk[331]
  PIN f_lk[332]
    DIRECTION INOUT ;
    USE SIGNAL ;
    PORT
      LAYER M4 ;
        RECT 2599.808 678.096 2600.000 678.120 ;
    END
  END f_lk[332]
  PIN f_lk[333]
    DIRECTION INOUT ;
    USE SIGNAL ;
    PORT
      LAYER M4 ;
        RECT 2599.808 678.288 2600.000 678.312 ;
    END
  END f_lk[333]
  PIN f_lk[334]
    DIRECTION INOUT ;
    USE SIGNAL ;
    PORT
      LAYER M4 ;
        RECT 2599.808 678.480 2600.000 678.504 ;
    END
  END f_lk[334]
  PIN f_lk[335]
    DIRECTION INOUT ;
    USE SIGNAL ;
    PORT
      LAYER M4 ;
        RECT 2599.808 678.672 2600.000 678.696 ;
    END
  END f_lk[335]
  PIN f_lk[336]
    DIRECTION INOUT ;
    USE SIGNAL ;
    PORT
      LAYER M4 ;
        RECT 2599.808 678.864 2600.000 678.888 ;
    END
  END f_lk[336]
  PIN f_lk[337]
    DIRECTION INOUT ;
    USE SIGNAL ;
    PORT
      LAYER M4 ;
        RECT 2599.808 679.056 2600.000 679.080 ;
    END
  END f_lk[337]
  PIN f_lk[338]
    DIRECTION INOUT ;
    USE SIGNAL ;
    PORT
      LAYER M4 ;
        RECT 2599.808 679.248 2600.000 679.272 ;
    END
  END f_lk[338]
  PIN f_lk[339]
    DIRECTION INOUT ;
    USE SIGNAL ;
    PORT
      LAYER M4 ;
        RECT 2599.808 679.440 2600.000 679.464 ;
    END
  END f_lk[339]
  PIN f_lk[340]
    DIRECTION INOUT ;
    USE SIGNAL ;
    PORT
      LAYER M4 ;
        RECT 2599.808 679.632 2600.000 679.656 ;
    END
  END f_lk[340]
  PIN f_lk[341]
    DIRECTION INOUT ;
    USE SIGNAL ;
    PORT
      LAYER M4 ;
        RECT 2599.808 679.824 2600.000 679.848 ;
    END
  END f_lk[341]
  PIN f_lk[342]
    DIRECTION INOUT ;
    USE SIGNAL ;
    PORT
      LAYER M4 ;
        RECT 2599.808 680.016 2600.000 680.040 ;
    END
  END f_lk[342]
  PIN f_lk[343]
    DIRECTION INOUT ;
    USE SIGNAL ;
    PORT
      LAYER M4 ;
        RECT 2599.808 680.208 2600.000 680.232 ;
    END
  END f_lk[343]
  PIN f_lk[344]
    DIRECTION INOUT ;
    USE SIGNAL ;
    PORT
      LAYER M4 ;
        RECT 2599.808 680.400 2600.000 680.424 ;
    END
  END f_lk[344]
  PIN f_lk[345]
    DIRECTION INOUT ;
    USE SIGNAL ;
    PORT
      LAYER M4 ;
        RECT 2599.808 680.592 2600.000 680.616 ;
    END
  END f_lk[345]
  PIN f_lk[346]
    DIRECTION INOUT ;
    USE SIGNAL ;
    PORT
      LAYER M4 ;
        RECT 2599.808 680.784 2600.000 680.808 ;
    END
  END f_lk[346]
  PIN f_lk[347]
    DIRECTION INOUT ;
    USE SIGNAL ;
    PORT
      LAYER M4 ;
        RECT 2599.808 680.976 2600.000 681.000 ;
    END
  END f_lk[347]
  PIN f_lk[348]
    DIRECTION INOUT ;
    USE SIGNAL ;
    PORT
      LAYER M4 ;
        RECT 2599.808 681.168 2600.000 681.192 ;
    END
  END f_lk[348]
  PIN f_lk[349]
    DIRECTION INOUT ;
    USE SIGNAL ;
    PORT
      LAYER M4 ;
        RECT 2599.808 681.360 2600.000 681.384 ;
    END
  END f_lk[349]
  PIN f_lk[350]
    DIRECTION INOUT ;
    USE SIGNAL ;
    PORT
      LAYER M4 ;
        RECT 2599.808 681.552 2600.000 681.576 ;
    END
  END f_lk[350]
  PIN f_lk[351]
    DIRECTION INOUT ;
    USE SIGNAL ;
    PORT
      LAYER M4 ;
        RECT 2599.808 681.744 2600.000 681.768 ;
    END
  END f_lk[351]
  PIN f_lk[352]
    DIRECTION INOUT ;
    USE SIGNAL ;
    PORT
      LAYER M4 ;
        RECT 2599.808 681.936 2600.000 681.960 ;
    END
  END f_lk[352]
  PIN f_lk[353]
    DIRECTION INOUT ;
    USE SIGNAL ;
    PORT
      LAYER M4 ;
        RECT 2599.808 682.128 2600.000 682.152 ;
    END
  END f_lk[353]
  PIN f_lk[354]
    DIRECTION INOUT ;
    USE SIGNAL ;
    PORT
      LAYER M4 ;
        RECT 2599.808 682.320 2600.000 682.344 ;
    END
  END f_lk[354]
  PIN f_lk[355]
    DIRECTION INOUT ;
    USE SIGNAL ;
    PORT
      LAYER M4 ;
        RECT 2599.808 682.512 2600.000 682.536 ;
    END
  END f_lk[355]
  PIN f_lk[356]
    DIRECTION INOUT ;
    USE SIGNAL ;
    PORT
      LAYER M4 ;
        RECT 2599.808 682.704 2600.000 682.728 ;
    END
  END f_lk[356]
  PIN f_lk[357]
    DIRECTION INOUT ;
    USE SIGNAL ;
    PORT
      LAYER M4 ;
        RECT 2599.808 682.896 2600.000 682.920 ;
    END
  END f_lk[357]
  PIN f_lk[358]
    DIRECTION INOUT ;
    USE SIGNAL ;
    PORT
      LAYER M4 ;
        RECT 2599.808 683.088 2600.000 683.112 ;
    END
  END f_lk[358]
  PIN f_lk[359]
    DIRECTION INOUT ;
    USE SIGNAL ;
    PORT
      LAYER M4 ;
        RECT 2599.808 683.280 2600.000 683.304 ;
    END
  END f_lk[359]
  PIN f_lk[360]
    DIRECTION INOUT ;
    USE SIGNAL ;
    PORT
      LAYER M4 ;
        RECT 2599.808 683.472 2600.000 683.496 ;
    END
  END f_lk[360]
  PIN f_lk[361]
    DIRECTION INOUT ;
    USE SIGNAL ;
    PORT
      LAYER M4 ;
        RECT 2599.808 683.664 2600.000 683.688 ;
    END
  END f_lk[361]
  PIN f_lk[362]
    DIRECTION INOUT ;
    USE SIGNAL ;
    PORT
      LAYER M4 ;
        RECT 2599.808 683.856 2600.000 683.880 ;
    END
  END f_lk[362]
  PIN f_lk[363]
    DIRECTION INOUT ;
    USE SIGNAL ;
    PORT
      LAYER M4 ;
        RECT 2599.808 684.048 2600.000 684.072 ;
    END
  END f_lk[363]
  PIN f_lk[364]
    DIRECTION INOUT ;
    USE SIGNAL ;
    PORT
      LAYER M4 ;
        RECT 2599.808 684.240 2600.000 684.264 ;
    END
  END f_lk[364]
  PIN f_lk[365]
    DIRECTION INOUT ;
    USE SIGNAL ;
    PORT
      LAYER M4 ;
        RECT 2599.808 684.432 2600.000 684.456 ;
    END
  END f_lk[365]
  PIN f_lk[366]
    DIRECTION INOUT ;
    USE SIGNAL ;
    PORT
      LAYER M4 ;
        RECT 2599.808 684.624 2600.000 684.648 ;
    END
  END f_lk[366]
  PIN f_lk[367]
    DIRECTION INOUT ;
    USE SIGNAL ;
    PORT
      LAYER M4 ;
        RECT 2599.808 684.816 2600.000 684.840 ;
    END
  END f_lk[367]
  PIN f_lk[368]
    DIRECTION INOUT ;
    USE SIGNAL ;
    PORT
      LAYER M4 ;
        RECT 2599.808 685.008 2600.000 685.032 ;
    END
  END f_lk[368]
  PIN f_lk[369]
    DIRECTION INOUT ;
    USE SIGNAL ;
    PORT
      LAYER M4 ;
        RECT 2599.808 685.200 2600.000 685.224 ;
    END
  END f_lk[369]
  PIN f_lk[370]
    DIRECTION INOUT ;
    USE SIGNAL ;
    PORT
      LAYER M4 ;
        RECT 2599.808 685.392 2600.000 685.416 ;
    END
  END f_lk[370]
  PIN f_lk[371]
    DIRECTION INOUT ;
    USE SIGNAL ;
    PORT
      LAYER M4 ;
        RECT 2599.808 685.584 2600.000 685.608 ;
    END
  END f_lk[371]
  PIN f_lk[372]
    DIRECTION INOUT ;
    USE SIGNAL ;
    PORT
      LAYER M4 ;
        RECT 2599.808 685.776 2600.000 685.800 ;
    END
  END f_lk[372]
  PIN f_lk[373]
    DIRECTION INOUT ;
    USE SIGNAL ;
    PORT
      LAYER M4 ;
        RECT 2599.808 685.968 2600.000 685.992 ;
    END
  END f_lk[373]
  PIN f_lk[374]
    DIRECTION INOUT ;
    USE SIGNAL ;
    PORT
      LAYER M4 ;
        RECT 2599.808 686.160 2600.000 686.184 ;
    END
  END f_lk[374]
  PIN f_lk[375]
    DIRECTION INOUT ;
    USE SIGNAL ;
    PORT
      LAYER M4 ;
        RECT 2599.808 686.352 2600.000 686.376 ;
    END
  END f_lk[375]
  PIN f_lk[376]
    DIRECTION INOUT ;
    USE SIGNAL ;
    PORT
      LAYER M4 ;
        RECT 2599.808 686.544 2600.000 686.568 ;
    END
  END f_lk[376]
  PIN f_lk[377]
    DIRECTION INOUT ;
    USE SIGNAL ;
    PORT
      LAYER M4 ;
        RECT 2599.808 686.736 2600.000 686.760 ;
    END
  END f_lk[377]
  PIN f_lk[378]
    DIRECTION INOUT ;
    USE SIGNAL ;
    PORT
      LAYER M4 ;
        RECT 2599.808 686.928 2600.000 686.952 ;
    END
  END f_lk[378]
  PIN f_lk[379]
    DIRECTION INOUT ;
    USE SIGNAL ;
    PORT
      LAYER M4 ;
        RECT 2599.808 687.120 2600.000 687.144 ;
    END
  END f_lk[379]
  PIN f_lk[380]
    DIRECTION INOUT ;
    USE SIGNAL ;
    PORT
      LAYER M4 ;
        RECT 2599.808 687.312 2600.000 687.336 ;
    END
  END f_lk[380]
  PIN f_lk[381]
    DIRECTION INOUT ;
    USE SIGNAL ;
    PORT
      LAYER M4 ;
        RECT 2599.808 687.504 2600.000 687.528 ;
    END
  END f_lk[381]
  PIN f_lk[382]
    DIRECTION INOUT ;
    USE SIGNAL ;
    PORT
      LAYER M4 ;
        RECT 2599.808 687.696 2600.000 687.720 ;
    END
  END f_lk[382]
  PIN f_lk[383]
    DIRECTION INOUT ;
    USE SIGNAL ;
    PORT
      LAYER M4 ;
        RECT 2599.808 687.888 2600.000 687.912 ;
    END
  END f_lk[383]
  PIN f_lk[384]
    DIRECTION INOUT ;
    USE SIGNAL ;
    PORT
      LAYER M4 ;
        RECT 2599.808 688.080 2600.000 688.104 ;
    END
  END f_lk[384]
  PIN f_lk[385]
    DIRECTION INOUT ;
    USE SIGNAL ;
    PORT
      LAYER M4 ;
        RECT 2599.808 688.272 2600.000 688.296 ;
    END
  END f_lk[385]
  PIN f_lk[386]
    DIRECTION INOUT ;
    USE SIGNAL ;
    PORT
      LAYER M4 ;
        RECT 2599.808 688.464 2600.000 688.488 ;
    END
  END f_lk[386]
  PIN f_lk[387]
    DIRECTION INOUT ;
    USE SIGNAL ;
    PORT
      LAYER M4 ;
        RECT 2599.808 688.656 2600.000 688.680 ;
    END
  END f_lk[387]
  PIN f_lk[388]
    DIRECTION INOUT ;
    USE SIGNAL ;
    PORT
      LAYER M4 ;
        RECT 2599.808 688.848 2600.000 688.872 ;
    END
  END f_lk[388]
  PIN f_lk[389]
    DIRECTION INOUT ;
    USE SIGNAL ;
    PORT
      LAYER M4 ;
        RECT 2599.808 689.040 2600.000 689.064 ;
    END
  END f_lk[389]
  PIN f_lk[390]
    DIRECTION INOUT ;
    USE SIGNAL ;
    PORT
      LAYER M4 ;
        RECT 2599.808 689.232 2600.000 689.256 ;
    END
  END f_lk[390]
  PIN f_lk[391]
    DIRECTION INOUT ;
    USE SIGNAL ;
    PORT
      LAYER M4 ;
        RECT 2599.808 689.424 2600.000 689.448 ;
    END
  END f_lk[391]
  PIN f_lk[392]
    DIRECTION INOUT ;
    USE SIGNAL ;
    PORT
      LAYER M4 ;
        RECT 2599.808 689.616 2600.000 689.640 ;
    END
  END f_lk[392]
  PIN f_lk[393]
    DIRECTION INOUT ;
    USE SIGNAL ;
    PORT
      LAYER M4 ;
        RECT 2599.808 689.808 2600.000 689.832 ;
    END
  END f_lk[393]
  PIN f_lk[394]
    DIRECTION INOUT ;
    USE SIGNAL ;
    PORT
      LAYER M4 ;
        RECT 2599.808 690.000 2600.000 690.024 ;
    END
  END f_lk[394]
  PIN f_lk[395]
    DIRECTION INOUT ;
    USE SIGNAL ;
    PORT
      LAYER M4 ;
        RECT 2599.808 690.192 2600.000 690.216 ;
    END
  END f_lk[395]
  PIN f_lk[396]
    DIRECTION INOUT ;
    USE SIGNAL ;
    PORT
      LAYER M4 ;
        RECT 2599.808 690.384 2600.000 690.408 ;
    END
  END f_lk[396]
  PIN f_lk[397]
    DIRECTION INOUT ;
    USE SIGNAL ;
    PORT
      LAYER M4 ;
        RECT 2599.808 690.576 2600.000 690.600 ;
    END
  END f_lk[397]
  PIN f_lk[398]
    DIRECTION INOUT ;
    USE SIGNAL ;
    PORT
      LAYER M4 ;
        RECT 2599.808 690.768 2600.000 690.792 ;
    END
  END f_lk[398]
  PIN f_lk[399]
    DIRECTION INOUT ;
    USE SIGNAL ;
    PORT
      LAYER M4 ;
        RECT 2599.808 690.960 2600.000 690.984 ;
    END
  END f_lk[399]
  PIN f_lk[400]
    DIRECTION INOUT ;
    USE SIGNAL ;
    PORT
      LAYER M4 ;
        RECT 2599.808 691.152 2600.000 691.176 ;
    END
  END f_lk[400]
  PIN f_lk[401]
    DIRECTION INOUT ;
    USE SIGNAL ;
    PORT
      LAYER M4 ;
        RECT 2599.808 691.344 2600.000 691.368 ;
    END
  END f_lk[401]
  PIN f_lk[402]
    DIRECTION INOUT ;
    USE SIGNAL ;
    PORT
      LAYER M4 ;
        RECT 2599.808 691.536 2600.000 691.560 ;
    END
  END f_lk[402]
  PIN f_lk[403]
    DIRECTION INOUT ;
    USE SIGNAL ;
    PORT
      LAYER M4 ;
        RECT 2599.808 691.728 2600.000 691.752 ;
    END
  END f_lk[403]
  PIN f_lk[404]
    DIRECTION INOUT ;
    USE SIGNAL ;
    PORT
      LAYER M4 ;
        RECT 2599.808 691.920 2600.000 691.944 ;
    END
  END f_lk[404]
  PIN f_lk[405]
    DIRECTION INOUT ;
    USE SIGNAL ;
    PORT
      LAYER M4 ;
        RECT 2599.808 692.112 2600.000 692.136 ;
    END
  END f_lk[405]
  PIN f_lk[406]
    DIRECTION INOUT ;
    USE SIGNAL ;
    PORT
      LAYER M4 ;
        RECT 2599.808 692.304 2600.000 692.328 ;
    END
  END f_lk[406]
  PIN f_lk[407]
    DIRECTION INOUT ;
    USE SIGNAL ;
    PORT
      LAYER M4 ;
        RECT 2599.808 692.496 2600.000 692.520 ;
    END
  END f_lk[407]
  PIN f_lk[408]
    DIRECTION INOUT ;
    USE SIGNAL ;
    PORT
      LAYER M4 ;
        RECT 2599.808 692.688 2600.000 692.712 ;
    END
  END f_lk[408]
  PIN f_lk[409]
    DIRECTION INOUT ;
    USE SIGNAL ;
    PORT
      LAYER M4 ;
        RECT 2599.808 692.880 2600.000 692.904 ;
    END
  END f_lk[409]
  PIN f_lk[410]
    DIRECTION INOUT ;
    USE SIGNAL ;
    PORT
      LAYER M4 ;
        RECT 2599.808 693.072 2600.000 693.096 ;
    END
  END f_lk[410]
  PIN f_lk[411]
    DIRECTION INOUT ;
    USE SIGNAL ;
    PORT
      LAYER M4 ;
        RECT 2599.808 693.264 2600.000 693.288 ;
    END
  END f_lk[411]
  PIN f_lk[412]
    DIRECTION INOUT ;
    USE SIGNAL ;
    PORT
      LAYER M4 ;
        RECT 2599.808 693.456 2600.000 693.480 ;
    END
  END f_lk[412]
  PIN f_lk[413]
    DIRECTION INOUT ;
    USE SIGNAL ;
    PORT
      LAYER M4 ;
        RECT 2599.808 693.648 2600.000 693.672 ;
    END
  END f_lk[413]
  PIN f_lk[414]
    DIRECTION INOUT ;
    USE SIGNAL ;
    PORT
      LAYER M4 ;
        RECT 2599.808 693.840 2600.000 693.864 ;
    END
  END f_lk[414]
  PIN f_lk[415]
    DIRECTION INOUT ;
    USE SIGNAL ;
    PORT
      LAYER M4 ;
        RECT 2599.808 694.032 2600.000 694.056 ;
    END
  END f_lk[415]
  PIN f_lk[416]
    DIRECTION INOUT ;
    USE SIGNAL ;
    PORT
      LAYER M4 ;
        RECT 2599.808 694.224 2600.000 694.248 ;
    END
  END f_lk[416]
  PIN f_lk[417]
    DIRECTION INOUT ;
    USE SIGNAL ;
    PORT
      LAYER M4 ;
        RECT 2599.808 694.416 2600.000 694.440 ;
    END
  END f_lk[417]
  PIN f_lk[418]
    DIRECTION INOUT ;
    USE SIGNAL ;
    PORT
      LAYER M4 ;
        RECT 2599.808 694.608 2600.000 694.632 ;
    END
  END f_lk[418]
  PIN f_lk[419]
    DIRECTION INOUT ;
    USE SIGNAL ;
    PORT
      LAYER M4 ;
        RECT 2599.808 694.800 2600.000 694.824 ;
    END
  END f_lk[419]
  PIN f_lk[420]
    DIRECTION INOUT ;
    USE SIGNAL ;
    PORT
      LAYER M4 ;
        RECT 2599.808 694.992 2600.000 695.016 ;
    END
  END f_lk[420]
  PIN f_lk[421]
    DIRECTION INOUT ;
    USE SIGNAL ;
    PORT
      LAYER M4 ;
        RECT 2599.808 695.184 2600.000 695.208 ;
    END
  END f_lk[421]
  PIN f_lk[422]
    DIRECTION INOUT ;
    USE SIGNAL ;
    PORT
      LAYER M4 ;
        RECT 2599.808 695.376 2600.000 695.400 ;
    END
  END f_lk[422]
  PIN f_lk[423]
    DIRECTION INOUT ;
    USE SIGNAL ;
    PORT
      LAYER M4 ;
        RECT 2599.808 695.568 2600.000 695.592 ;
    END
  END f_lk[423]
  PIN f_lk[424]
    DIRECTION INOUT ;
    USE SIGNAL ;
    PORT
      LAYER M4 ;
        RECT 2599.808 695.760 2600.000 695.784 ;
    END
  END f_lk[424]
  PIN f_lk[425]
    DIRECTION INOUT ;
    USE SIGNAL ;
    PORT
      LAYER M4 ;
        RECT 2599.808 695.952 2600.000 695.976 ;
    END
  END f_lk[425]
  PIN f_lk[426]
    DIRECTION INOUT ;
    USE SIGNAL ;
    PORT
      LAYER M4 ;
        RECT 2599.808 696.144 2600.000 696.168 ;
    END
  END f_lk[426]
  PIN f_lk[427]
    DIRECTION INOUT ;
    USE SIGNAL ;
    PORT
      LAYER M4 ;
        RECT 2599.808 696.336 2600.000 696.360 ;
    END
  END f_lk[427]
  PIN f_lk[428]
    DIRECTION INOUT ;
    USE SIGNAL ;
    PORT
      LAYER M4 ;
        RECT 2599.808 696.528 2600.000 696.552 ;
    END
  END f_lk[428]
  PIN f_lk[429]
    DIRECTION INOUT ;
    USE SIGNAL ;
    PORT
      LAYER M4 ;
        RECT 2599.808 696.720 2600.000 696.744 ;
    END
  END f_lk[429]
  PIN f_lk[430]
    DIRECTION INOUT ;
    USE SIGNAL ;
    PORT
      LAYER M4 ;
        RECT 2599.808 696.912 2600.000 696.936 ;
    END
  END f_lk[430]
  PIN f_lk[431]
    DIRECTION INOUT ;
    USE SIGNAL ;
    PORT
      LAYER M4 ;
        RECT 2599.808 697.104 2600.000 697.128 ;
    END
  END f_lk[431]
  PIN f_lk[432]
    DIRECTION INOUT ;
    USE SIGNAL ;
    PORT
      LAYER M4 ;
        RECT 2599.808 697.296 2600.000 697.320 ;
    END
  END f_lk[432]
  PIN f_lk[433]
    DIRECTION INOUT ;
    USE SIGNAL ;
    PORT
      LAYER M4 ;
        RECT 2599.808 697.488 2600.000 697.512 ;
    END
  END f_lk[433]
  PIN f_lk[434]
    DIRECTION INOUT ;
    USE SIGNAL ;
    PORT
      LAYER M4 ;
        RECT 2599.808 697.680 2600.000 697.704 ;
    END
  END f_lk[434]
  PIN f_lk[435]
    DIRECTION INOUT ;
    USE SIGNAL ;
    PORT
      LAYER M4 ;
        RECT 2599.808 697.872 2600.000 697.896 ;
    END
  END f_lk[435]
  PIN f_lk[436]
    DIRECTION INOUT ;
    USE SIGNAL ;
    PORT
      LAYER M4 ;
        RECT 2599.808 698.064 2600.000 698.088 ;
    END
  END f_lk[436]
  PIN f_lk[437]
    DIRECTION INOUT ;
    USE SIGNAL ;
    PORT
      LAYER M4 ;
        RECT 2599.808 698.256 2600.000 698.280 ;
    END
  END f_lk[437]
  PIN f_lk[438]
    DIRECTION INOUT ;
    USE SIGNAL ;
    PORT
      LAYER M4 ;
        RECT 2599.808 698.448 2600.000 698.472 ;
    END
  END f_lk[438]
  PIN f_lk[439]
    DIRECTION INOUT ;
    USE SIGNAL ;
    PORT
      LAYER M4 ;
        RECT 2599.808 698.640 2600.000 698.664 ;
    END
  END f_lk[439]
  PIN f_lk[440]
    DIRECTION INOUT ;
    USE SIGNAL ;
    PORT
      LAYER M4 ;
        RECT 2599.808 698.832 2600.000 698.856 ;
    END
  END f_lk[440]
  PIN f_lk[441]
    DIRECTION INOUT ;
    USE SIGNAL ;
    PORT
      LAYER M4 ;
        RECT 2599.808 699.024 2600.000 699.048 ;
    END
  END f_lk[441]
  PIN f_lk[442]
    DIRECTION INOUT ;
    USE SIGNAL ;
    PORT
      LAYER M4 ;
        RECT 2599.808 699.216 2600.000 699.240 ;
    END
  END f_lk[442]
  PIN f_lk[443]
    DIRECTION INOUT ;
    USE SIGNAL ;
    PORT
      LAYER M4 ;
        RECT 2599.808 699.408 2600.000 699.432 ;
    END
  END f_lk[443]
  PIN f_lk[444]
    DIRECTION INOUT ;
    USE SIGNAL ;
    PORT
      LAYER M4 ;
        RECT 2599.808 699.600 2600.000 699.624 ;
    END
  END f_lk[444]
  PIN f_lk[445]
    DIRECTION INOUT ;
    USE SIGNAL ;
    PORT
      LAYER M4 ;
        RECT 2599.808 699.792 2600.000 699.816 ;
    END
  END f_lk[445]
  PIN f_lk[446]
    DIRECTION INOUT ;
    USE SIGNAL ;
    PORT
      LAYER M4 ;
        RECT 2599.808 699.984 2600.000 700.008 ;
    END
  END f_lk[446]
  PIN f_lk[447]
    DIRECTION INOUT ;
    USE SIGNAL ;
    PORT
      LAYER M4 ;
        RECT 2599.808 700.176 2600.000 700.200 ;
    END
  END f_lk[447]
  PIN f_lk[448]
    DIRECTION INOUT ;
    USE SIGNAL ;
    PORT
      LAYER M4 ;
        RECT 2599.808 700.368 2600.000 700.392 ;
    END
  END f_lk[448]
  PIN f_lk[449]
    DIRECTION INOUT ;
    USE SIGNAL ;
    PORT
      LAYER M4 ;
        RECT 2599.808 700.560 2600.000 700.584 ;
    END
  END f_lk[449]
  PIN f_lk[450]
    DIRECTION INOUT ;
    USE SIGNAL ;
    PORT
      LAYER M4 ;
        RECT 2599.808 700.752 2600.000 700.776 ;
    END
  END f_lk[450]
  PIN f_lk[451]
    DIRECTION INOUT ;
    USE SIGNAL ;
    PORT
      LAYER M4 ;
        RECT 2599.808 700.944 2600.000 700.968 ;
    END
  END f_lk[451]
  PIN f_lk[452]
    DIRECTION INOUT ;
    USE SIGNAL ;
    PORT
      LAYER M4 ;
        RECT 2599.808 701.136 2600.000 701.160 ;
    END
  END f_lk[452]
  PIN f_lk[453]
    DIRECTION INOUT ;
    USE SIGNAL ;
    PORT
      LAYER M4 ;
        RECT 2599.808 701.328 2600.000 701.352 ;
    END
  END f_lk[453]
  PIN f_lk[454]
    DIRECTION INOUT ;
    USE SIGNAL ;
    PORT
      LAYER M4 ;
        RECT 2599.808 701.520 2600.000 701.544 ;
    END
  END f_lk[454]
  PIN f_lk[455]
    DIRECTION INOUT ;
    USE SIGNAL ;
    PORT
      LAYER M4 ;
        RECT 2599.808 701.712 2600.000 701.736 ;
    END
  END f_lk[455]
  PIN f_lk[456]
    DIRECTION INOUT ;
    USE SIGNAL ;
    PORT
      LAYER M4 ;
        RECT 2599.808 701.904 2600.000 701.928 ;
    END
  END f_lk[456]
  PIN f_lk[457]
    DIRECTION INOUT ;
    USE SIGNAL ;
    PORT
      LAYER M4 ;
        RECT 2599.808 702.096 2600.000 702.120 ;
    END
  END f_lk[457]
  PIN f_lk[458]
    DIRECTION INOUT ;
    USE SIGNAL ;
    PORT
      LAYER M4 ;
        RECT 2599.808 702.288 2600.000 702.312 ;
    END
  END f_lk[458]
  PIN f_lk[459]
    DIRECTION INOUT ;
    USE SIGNAL ;
    PORT
      LAYER M4 ;
        RECT 2599.808 702.480 2600.000 702.504 ;
    END
  END f_lk[459]
  PIN f_lk[460]
    DIRECTION INOUT ;
    USE SIGNAL ;
    PORT
      LAYER M4 ;
        RECT 2599.808 702.672 2600.000 702.696 ;
    END
  END f_lk[460]
  PIN f_lk[461]
    DIRECTION INOUT ;
    USE SIGNAL ;
    PORT
      LAYER M4 ;
        RECT 2599.808 702.864 2600.000 702.888 ;
    END
  END f_lk[461]
  PIN f_lk[462]
    DIRECTION INOUT ;
    USE SIGNAL ;
    PORT
      LAYER M4 ;
        RECT 2599.808 703.056 2600.000 703.080 ;
    END
  END f_lk[462]
  PIN f_lk[463]
    DIRECTION INOUT ;
    USE SIGNAL ;
    PORT
      LAYER M4 ;
        RECT 2599.808 703.248 2600.000 703.272 ;
    END
  END f_lk[463]
  PIN f_lk[464]
    DIRECTION INOUT ;
    USE SIGNAL ;
    PORT
      LAYER M4 ;
        RECT 2599.808 703.440 2600.000 703.464 ;
    END
  END f_lk[464]
  PIN f_lk[465]
    DIRECTION INOUT ;
    USE SIGNAL ;
    PORT
      LAYER M4 ;
        RECT 2599.808 703.632 2600.000 703.656 ;
    END
  END f_lk[465]
  PIN f_lk[466]
    DIRECTION INOUT ;
    USE SIGNAL ;
    PORT
      LAYER M4 ;
        RECT 2599.808 703.824 2600.000 703.848 ;
    END
  END f_lk[466]
  PIN f_lk[467]
    DIRECTION INOUT ;
    USE SIGNAL ;
    PORT
      LAYER M4 ;
        RECT 2599.808 704.016 2600.000 704.040 ;
    END
  END f_lk[467]
  PIN f_lk[468]
    DIRECTION INOUT ;
    USE SIGNAL ;
    PORT
      LAYER M4 ;
        RECT 2599.808 704.208 2600.000 704.232 ;
    END
  END f_lk[468]
  PIN f_lk[469]
    DIRECTION INOUT ;
    USE SIGNAL ;
    PORT
      LAYER M4 ;
        RECT 2599.808 704.400 2600.000 704.424 ;
    END
  END f_lk[469]
  PIN f_lk[470]
    DIRECTION INOUT ;
    USE SIGNAL ;
    PORT
      LAYER M4 ;
        RECT 2599.808 704.592 2600.000 704.616 ;
    END
  END f_lk[470]
  PIN f_lk[471]
    DIRECTION INOUT ;
    USE SIGNAL ;
    PORT
      LAYER M4 ;
        RECT 2599.808 704.784 2600.000 704.808 ;
    END
  END f_lk[471]
  PIN f_lk[472]
    DIRECTION INOUT ;
    USE SIGNAL ;
    PORT
      LAYER M4 ;
        RECT 2599.808 704.976 2600.000 705.000 ;
    END
  END f_lk[472]
  PIN f_lk[473]
    DIRECTION INOUT ;
    USE SIGNAL ;
    PORT
      LAYER M4 ;
        RECT 2599.808 705.168 2600.000 705.192 ;
    END
  END f_lk[473]
  PIN f_lk[474]
    DIRECTION INOUT ;
    USE SIGNAL ;
    PORT
      LAYER M4 ;
        RECT 2599.808 705.360 2600.000 705.384 ;
    END
  END f_lk[474]
  PIN f_lk[475]
    DIRECTION INOUT ;
    USE SIGNAL ;
    PORT
      LAYER M4 ;
        RECT 2599.808 705.552 2600.000 705.576 ;
    END
  END f_lk[475]
  PIN f_lk[476]
    DIRECTION INOUT ;
    USE SIGNAL ;
    PORT
      LAYER M4 ;
        RECT 2599.808 705.744 2600.000 705.768 ;
    END
  END f_lk[476]
  PIN f_lk[477]
    DIRECTION INOUT ;
    USE SIGNAL ;
    PORT
      LAYER M4 ;
        RECT 2599.808 705.936 2600.000 705.960 ;
    END
  END f_lk[477]
  PIN f_lk[478]
    DIRECTION INOUT ;
    USE SIGNAL ;
    PORT
      LAYER M4 ;
        RECT 2599.808 706.128 2600.000 706.152 ;
    END
  END f_lk[478]
  PIN f_lk[479]
    DIRECTION INOUT ;
    USE SIGNAL ;
    PORT
      LAYER M4 ;
        RECT 2599.808 706.320 2600.000 706.344 ;
    END
  END f_lk[479]
  PIN f_lk[480]
    DIRECTION INOUT ;
    USE SIGNAL ;
    PORT
      LAYER M4 ;
        RECT 2599.808 706.512 2600.000 706.536 ;
    END
  END f_lk[480]
  PIN f_lk[481]
    DIRECTION INOUT ;
    USE SIGNAL ;
    PORT
      LAYER M4 ;
        RECT 2599.808 706.704 2600.000 706.728 ;
    END
  END f_lk[481]
  PIN f_lk[482]
    DIRECTION INOUT ;
    USE SIGNAL ;
    PORT
      LAYER M4 ;
        RECT 2599.808 706.896 2600.000 706.920 ;
    END
  END f_lk[482]
  PIN f_lk[483]
    DIRECTION INOUT ;
    USE SIGNAL ;
    PORT
      LAYER M4 ;
        RECT 2599.808 707.088 2600.000 707.112 ;
    END
  END f_lk[483]
  PIN f_lk[484]
    DIRECTION INOUT ;
    USE SIGNAL ;
    PORT
      LAYER M4 ;
        RECT 2599.808 707.280 2600.000 707.304 ;
    END
  END f_lk[484]
  PIN f_lk[485]
    DIRECTION INOUT ;
    USE SIGNAL ;
    PORT
      LAYER M4 ;
        RECT 2599.808 707.472 2600.000 707.496 ;
    END
  END f_lk[485]
  PIN f_lk[486]
    DIRECTION INOUT ;
    USE SIGNAL ;
    PORT
      LAYER M4 ;
        RECT 2599.808 707.664 2600.000 707.688 ;
    END
  END f_lk[486]
  PIN f_lk[487]
    DIRECTION INOUT ;
    USE SIGNAL ;
    PORT
      LAYER M4 ;
        RECT 2599.808 707.856 2600.000 707.880 ;
    END
  END f_lk[487]
  PIN f_lk[488]
    DIRECTION INOUT ;
    USE SIGNAL ;
    PORT
      LAYER M4 ;
        RECT 2599.808 708.048 2600.000 708.072 ;
    END
  END f_lk[488]
  PIN f_lk[489]
    DIRECTION INOUT ;
    USE SIGNAL ;
    PORT
      LAYER M4 ;
        RECT 2599.808 708.240 2600.000 708.264 ;
    END
  END f_lk[489]
  PIN f_lk[490]
    DIRECTION INOUT ;
    USE SIGNAL ;
    PORT
      LAYER M4 ;
        RECT 2599.808 708.432 2600.000 708.456 ;
    END
  END f_lk[490]
  PIN f_lk[491]
    DIRECTION INOUT ;
    USE SIGNAL ;
    PORT
      LAYER M4 ;
        RECT 2599.808 708.624 2600.000 708.648 ;
    END
  END f_lk[491]
  PIN f_lk[492]
    DIRECTION INOUT ;
    USE SIGNAL ;
    PORT
      LAYER M4 ;
        RECT 2599.808 708.816 2600.000 708.840 ;
    END
  END f_lk[492]
  PIN f_lk[493]
    DIRECTION INOUT ;
    USE SIGNAL ;
    PORT
      LAYER M4 ;
        RECT 2599.808 709.008 2600.000 709.032 ;
    END
  END f_lk[493]
  PIN f_lk[494]
    DIRECTION INOUT ;
    USE SIGNAL ;
    PORT
      LAYER M4 ;
        RECT 2599.808 709.200 2600.000 709.224 ;
    END
  END f_lk[494]
  PIN f_lk[495]
    DIRECTION INOUT ;
    USE SIGNAL ;
    PORT
      LAYER M4 ;
        RECT 2599.808 709.392 2600.000 709.416 ;
    END
  END f_lk[495]
  PIN f_lk[496]
    DIRECTION INOUT ;
    USE SIGNAL ;
    PORT
      LAYER M4 ;
        RECT 2599.808 709.584 2600.000 709.608 ;
    END
  END f_lk[496]
  PIN f_lk[497]
    DIRECTION INOUT ;
    USE SIGNAL ;
    PORT
      LAYER M4 ;
        RECT 2599.808 709.776 2600.000 709.800 ;
    END
  END f_lk[497]
  PIN f_lk[498]
    DIRECTION INOUT ;
    USE SIGNAL ;
    PORT
      LAYER M4 ;
        RECT 2599.808 709.968 2600.000 709.992 ;
    END
  END f_lk[498]
  PIN f_lk[499]
    DIRECTION INOUT ;
    USE SIGNAL ;
    PORT
      LAYER M4 ;
        RECT 2599.808 710.160 2600.000 710.184 ;
    END
  END f_lk[499]
  PIN f_lk[500]
    DIRECTION INOUT ;
    USE SIGNAL ;
    PORT
      LAYER M4 ;
        RECT 2599.808 710.352 2600.000 710.376 ;
    END
  END f_lk[500]
  PIN f_lk[501]
    DIRECTION INOUT ;
    USE SIGNAL ;
    PORT
      LAYER M4 ;
        RECT 2599.808 710.544 2600.000 710.568 ;
    END
  END f_lk[501]
  PIN f_lk[502]
    DIRECTION INOUT ;
    USE SIGNAL ;
    PORT
      LAYER M4 ;
        RECT 2599.808 710.736 2600.000 710.760 ;
    END
  END f_lk[502]
  PIN f_lk[503]
    DIRECTION INOUT ;
    USE SIGNAL ;
    PORT
      LAYER M4 ;
        RECT 2599.808 710.928 2600.000 710.952 ;
    END
  END f_lk[503]
  PIN f_lk[504]
    DIRECTION INOUT ;
    USE SIGNAL ;
    PORT
      LAYER M4 ;
        RECT 2599.808 711.120 2600.000 711.144 ;
    END
  END f_lk[504]
  PIN f_lk[505]
    DIRECTION INOUT ;
    USE SIGNAL ;
    PORT
      LAYER M4 ;
        RECT 2599.808 711.312 2600.000 711.336 ;
    END
  END f_lk[505]
  PIN f_lk[506]
    DIRECTION INOUT ;
    USE SIGNAL ;
    PORT
      LAYER M4 ;
        RECT 2599.808 711.504 2600.000 711.528 ;
    END
  END f_lk[506]
  PIN f_lk[507]
    DIRECTION INOUT ;
    USE SIGNAL ;
    PORT
      LAYER M4 ;
        RECT 2599.808 711.696 2600.000 711.720 ;
    END
  END f_lk[507]
  PIN f_lk[508]
    DIRECTION INOUT ;
    USE SIGNAL ;
    PORT
      LAYER M4 ;
        RECT 2599.808 711.888 2600.000 711.912 ;
    END
  END f_lk[508]
  PIN f_lk[509]
    DIRECTION INOUT ;
    USE SIGNAL ;
    PORT
      LAYER M4 ;
        RECT 2599.808 712.080 2600.000 712.104 ;
    END
  END f_lk[509]
  PIN f_lk[510]
    DIRECTION INOUT ;
    USE SIGNAL ;
    PORT
      LAYER M4 ;
        RECT 2599.808 712.272 2600.000 712.296 ;
    END
  END f_lk[510]
  PIN f_lk[511]
    DIRECTION INOUT ;
    USE SIGNAL ;
    PORT
      LAYER M4 ;
        RECT 2599.808 712.464 2600.000 712.488 ;
    END
  END f_lk[511]
  PIN f_lk[512]
    DIRECTION INOUT ;
    USE SIGNAL ;
    PORT
      LAYER M4 ;
        RECT 2599.808 712.656 2600.000 712.680 ;
    END
  END f_lk[512]
  PIN f_lk[513]
    DIRECTION INOUT ;
    USE SIGNAL ;
    PORT
      LAYER M4 ;
        RECT 2599.808 712.848 2600.000 712.872 ;
    END
  END f_lk[513]
  PIN f_lk[514]
    DIRECTION INOUT ;
    USE SIGNAL ;
    PORT
      LAYER M4 ;
        RECT 2599.808 713.040 2600.000 713.064 ;
    END
  END f_lk[514]
  PIN f_lk[515]
    DIRECTION INOUT ;
    USE SIGNAL ;
    PORT
      LAYER M4 ;
        RECT 2599.808 713.232 2600.000 713.256 ;
    END
  END f_lk[515]
  PIN f_lk[516]
    DIRECTION INOUT ;
    USE SIGNAL ;
    PORT
      LAYER M4 ;
        RECT 2599.808 713.424 2600.000 713.448 ;
    END
  END f_lk[516]
  PIN f_lk[517]
    DIRECTION INOUT ;
    USE SIGNAL ;
    PORT
      LAYER M4 ;
        RECT 2599.808 713.616 2600.000 713.640 ;
    END
  END f_lk[517]
  PIN f_lk[518]
    DIRECTION INOUT ;
    USE SIGNAL ;
    PORT
      LAYER M4 ;
        RECT 2599.808 713.808 2600.000 713.832 ;
    END
  END f_lk[518]
  PIN f_lk[519]
    DIRECTION INOUT ;
    USE SIGNAL ;
    PORT
      LAYER M4 ;
        RECT 2599.808 714.000 2600.000 714.024 ;
    END
  END f_lk[519]
  PIN f_lk[520]
    DIRECTION INOUT ;
    USE SIGNAL ;
    PORT
      LAYER M4 ;
        RECT 2599.808 714.192 2600.000 714.216 ;
    END
  END f_lk[520]
  PIN f_lk[521]
    DIRECTION INOUT ;
    USE SIGNAL ;
    PORT
      LAYER M4 ;
        RECT 2599.808 714.384 2600.000 714.408 ;
    END
  END f_lk[521]
  PIN f_lk[522]
    DIRECTION INOUT ;
    USE SIGNAL ;
    PORT
      LAYER M4 ;
        RECT 2599.808 714.576 2600.000 714.600 ;
    END
  END f_lk[522]
  PIN f_lk[523]
    DIRECTION INOUT ;
    USE SIGNAL ;
    PORT
      LAYER M4 ;
        RECT 2599.808 714.768 2600.000 714.792 ;
    END
  END f_lk[523]
  PIN f_lk[524]
    DIRECTION INOUT ;
    USE SIGNAL ;
    PORT
      LAYER M4 ;
        RECT 2599.808 714.960 2600.000 714.984 ;
    END
  END f_lk[524]
  PIN f_lk[525]
    DIRECTION INOUT ;
    USE SIGNAL ;
    PORT
      LAYER M4 ;
        RECT 2599.808 715.152 2600.000 715.176 ;
    END
  END f_lk[525]
  PIN f_lk[526]
    DIRECTION INOUT ;
    USE SIGNAL ;
    PORT
      LAYER M4 ;
        RECT 2599.808 715.344 2600.000 715.368 ;
    END
  END f_lk[526]
  PIN f_lk[527]
    DIRECTION INOUT ;
    USE SIGNAL ;
    PORT
      LAYER M4 ;
        RECT 2599.808 715.536 2600.000 715.560 ;
    END
  END f_lk[527]
  PIN f_lk[528]
    DIRECTION INOUT ;
    USE SIGNAL ;
    PORT
      LAYER M4 ;
        RECT 2599.808 715.728 2600.000 715.752 ;
    END
  END f_lk[528]
  PIN f_lk[529]
    DIRECTION INOUT ;
    USE SIGNAL ;
    PORT
      LAYER M4 ;
        RECT 2599.808 715.920 2600.000 715.944 ;
    END
  END f_lk[529]
  PIN f_lk[530]
    DIRECTION INOUT ;
    USE SIGNAL ;
    PORT
      LAYER M4 ;
        RECT 2599.808 716.112 2600.000 716.136 ;
    END
  END f_lk[530]
  PIN f_lk[531]
    DIRECTION INOUT ;
    USE SIGNAL ;
    PORT
      LAYER M4 ;
        RECT 2599.808 716.304 2600.000 716.328 ;
    END
  END f_lk[531]
  PIN f_lk[532]
    DIRECTION INOUT ;
    USE SIGNAL ;
    PORT
      LAYER M4 ;
        RECT 2599.808 716.496 2600.000 716.520 ;
    END
  END f_lk[532]
  PIN f_lk[533]
    DIRECTION INOUT ;
    USE SIGNAL ;
    PORT
      LAYER M4 ;
        RECT 2599.808 716.688 2600.000 716.712 ;
    END
  END f_lk[533]
  PIN f_lk[534]
    DIRECTION INOUT ;
    USE SIGNAL ;
    PORT
      LAYER M4 ;
        RECT 2599.808 716.880 2600.000 716.904 ;
    END
  END f_lk[534]
  PIN f_lk[535]
    DIRECTION INOUT ;
    USE SIGNAL ;
    PORT
      LAYER M4 ;
        RECT 2599.808 717.072 2600.000 717.096 ;
    END
  END f_lk[535]
  PIN f_lk[536]
    DIRECTION INOUT ;
    USE SIGNAL ;
    PORT
      LAYER M4 ;
        RECT 2599.808 717.264 2600.000 717.288 ;
    END
  END f_lk[536]
  PIN f_lk[537]
    DIRECTION INOUT ;
    USE SIGNAL ;
    PORT
      LAYER M4 ;
        RECT 2599.808 717.456 2600.000 717.480 ;
    END
  END f_lk[537]
  PIN f_lk[538]
    DIRECTION INOUT ;
    USE SIGNAL ;
    PORT
      LAYER M4 ;
        RECT 2599.808 717.648 2600.000 717.672 ;
    END
  END f_lk[538]
  PIN f_lk[539]
    DIRECTION INOUT ;
    USE SIGNAL ;
    PORT
      LAYER M4 ;
        RECT 2599.808 717.840 2600.000 717.864 ;
    END
  END f_lk[539]
  PIN f_lk[540]
    DIRECTION INOUT ;
    USE SIGNAL ;
    PORT
      LAYER M4 ;
        RECT 2599.808 718.032 2600.000 718.056 ;
    END
  END f_lk[540]
  PIN f_lk[541]
    DIRECTION INOUT ;
    USE SIGNAL ;
    PORT
      LAYER M4 ;
        RECT 2599.808 718.224 2600.000 718.248 ;
    END
  END f_lk[541]
  PIN f_lk[542]
    DIRECTION INOUT ;
    USE SIGNAL ;
    PORT
      LAYER M4 ;
        RECT 2599.808 718.416 2600.000 718.440 ;
    END
  END f_lk[542]
  PIN f_lk[543]
    DIRECTION INOUT ;
    USE SIGNAL ;
    PORT
      LAYER M4 ;
        RECT 2599.808 718.608 2600.000 718.632 ;
    END
  END f_lk[543]
  PIN f_lk[544]
    DIRECTION INOUT ;
    USE SIGNAL ;
    PORT
      LAYER M4 ;
        RECT 2599.808 718.800 2600.000 718.824 ;
    END
  END f_lk[544]
  PIN f_lk[545]
    DIRECTION INOUT ;
    USE SIGNAL ;
    PORT
      LAYER M4 ;
        RECT 2599.808 718.992 2600.000 719.016 ;
    END
  END f_lk[545]
  PIN f_lk[546]
    DIRECTION INOUT ;
    USE SIGNAL ;
    PORT
      LAYER M4 ;
        RECT 2599.808 719.184 2600.000 719.208 ;
    END
  END f_lk[546]
  PIN f_lk[547]
    DIRECTION INOUT ;
    USE SIGNAL ;
    PORT
      LAYER M4 ;
        RECT 2599.808 719.376 2600.000 719.400 ;
    END
  END f_lk[547]
  PIN f_lk[548]
    DIRECTION INOUT ;
    USE SIGNAL ;
    PORT
      LAYER M4 ;
        RECT 2599.808 719.568 2600.000 719.592 ;
    END
  END f_lk[548]
  PIN f_lk[549]
    DIRECTION INOUT ;
    USE SIGNAL ;
    PORT
      LAYER M4 ;
        RECT 2599.808 719.760 2600.000 719.784 ;
    END
  END f_lk[549]
  PIN f_lk[550]
    DIRECTION INOUT ;
    USE SIGNAL ;
    PORT
      LAYER M4 ;
        RECT 2599.808 719.952 2600.000 719.976 ;
    END
  END f_lk[550]
  PIN f_lk[551]
    DIRECTION INOUT ;
    USE SIGNAL ;
    PORT
      LAYER M4 ;
        RECT 2599.808 720.144 2600.000 720.168 ;
    END
  END f_lk[551]
  PIN f_lk[552]
    DIRECTION INOUT ;
    USE SIGNAL ;
    PORT
      LAYER M4 ;
        RECT 2599.808 720.336 2600.000 720.360 ;
    END
  END f_lk[552]
  PIN f_lk[553]
    DIRECTION INOUT ;
    USE SIGNAL ;
    PORT
      LAYER M4 ;
        RECT 2599.808 720.528 2600.000 720.552 ;
    END
  END f_lk[553]
  PIN f_lk[554]
    DIRECTION INOUT ;
    USE SIGNAL ;
    PORT
      LAYER M4 ;
        RECT 2599.808 720.720 2600.000 720.744 ;
    END
  END f_lk[554]
  PIN f_lk[555]
    DIRECTION INOUT ;
    USE SIGNAL ;
    PORT
      LAYER M4 ;
        RECT 2599.808 720.912 2600.000 720.936 ;
    END
  END f_lk[555]
  PIN f_lk[556]
    DIRECTION INOUT ;
    USE SIGNAL ;
    PORT
      LAYER M4 ;
        RECT 2599.808 721.104 2600.000 721.128 ;
    END
  END f_lk[556]
  PIN f_lk[557]
    DIRECTION INOUT ;
    USE SIGNAL ;
    PORT
      LAYER M4 ;
        RECT 2599.808 721.296 2600.000 721.320 ;
    END
  END f_lk[557]
  PIN f_lk[558]
    DIRECTION INOUT ;
    USE SIGNAL ;
    PORT
      LAYER M4 ;
        RECT 2599.808 721.488 2600.000 721.512 ;
    END
  END f_lk[558]
  PIN f_lk[559]
    DIRECTION INOUT ;
    USE SIGNAL ;
    PORT
      LAYER M4 ;
        RECT 2599.808 721.680 2600.000 721.704 ;
    END
  END f_lk[559]
  PIN f_lk[560]
    DIRECTION INOUT ;
    USE SIGNAL ;
    PORT
      LAYER M4 ;
        RECT 2599.808 721.872 2600.000 721.896 ;
    END
  END f_lk[560]
  PIN f_lk[561]
    DIRECTION INOUT ;
    USE SIGNAL ;
    PORT
      LAYER M4 ;
        RECT 2599.808 722.064 2600.000 722.088 ;
    END
  END f_lk[561]
  PIN f_lk[562]
    DIRECTION INOUT ;
    USE SIGNAL ;
    PORT
      LAYER M4 ;
        RECT 2599.808 722.256 2600.000 722.280 ;
    END
  END f_lk[562]
  PIN f_lk[563]
    DIRECTION INOUT ;
    USE SIGNAL ;
    PORT
      LAYER M4 ;
        RECT 2599.808 722.448 2600.000 722.472 ;
    END
  END f_lk[563]
  PIN f_lk[564]
    DIRECTION INOUT ;
    USE SIGNAL ;
    PORT
      LAYER M4 ;
        RECT 2599.808 722.640 2600.000 722.664 ;
    END
  END f_lk[564]
  PIN f_lk[565]
    DIRECTION INOUT ;
    USE SIGNAL ;
    PORT
      LAYER M4 ;
        RECT 2599.808 722.832 2600.000 722.856 ;
    END
  END f_lk[565]
  PIN f_lk[566]
    DIRECTION INOUT ;
    USE SIGNAL ;
    PORT
      LAYER M4 ;
        RECT 2599.808 723.024 2600.000 723.048 ;
    END
  END f_lk[566]
  PIN f_lk[567]
    DIRECTION INOUT ;
    USE SIGNAL ;
    PORT
      LAYER M4 ;
        RECT 2599.808 723.216 2600.000 723.240 ;
    END
  END f_lk[567]
  PIN f_lk[568]
    DIRECTION INOUT ;
    USE SIGNAL ;
    PORT
      LAYER M4 ;
        RECT 2599.808 723.408 2600.000 723.432 ;
    END
  END f_lk[568]
  PIN f_lk[569]
    DIRECTION INOUT ;
    USE SIGNAL ;
    PORT
      LAYER M4 ;
        RECT 2599.808 723.600 2600.000 723.624 ;
    END
  END f_lk[569]
  PIN f_lk[570]
    DIRECTION INOUT ;
    USE SIGNAL ;
    PORT
      LAYER M4 ;
        RECT 2599.808 723.792 2600.000 723.816 ;
    END
  END f_lk[570]
  PIN f_lk[571]
    DIRECTION INOUT ;
    USE SIGNAL ;
    PORT
      LAYER M4 ;
        RECT 2599.808 723.984 2600.000 724.008 ;
    END
  END f_lk[571]
  PIN f_lk[572]
    DIRECTION INOUT ;
    USE SIGNAL ;
    PORT
      LAYER M4 ;
        RECT 2599.808 724.176 2600.000 724.200 ;
    END
  END f_lk[572]
  PIN f_lk[573]
    DIRECTION INOUT ;
    USE SIGNAL ;
    PORT
      LAYER M4 ;
        RECT 2599.808 724.368 2600.000 724.392 ;
    END
  END f_lk[573]
  PIN f_lk[574]
    DIRECTION INOUT ;
    USE SIGNAL ;
    PORT
      LAYER M4 ;
        RECT 2599.808 724.560 2600.000 724.584 ;
    END
  END f_lk[574]
  PIN f_lk[575]
    DIRECTION INOUT ;
    USE SIGNAL ;
    PORT
      LAYER M4 ;
        RECT 2599.808 724.752 2600.000 724.776 ;
    END
  END f_lk[575]
  PIN f_lk[576]
    DIRECTION INOUT ;
    USE SIGNAL ;
    PORT
      LAYER M4 ;
        RECT 2599.808 724.944 2600.000 724.968 ;
    END
  END f_lk[576]
  PIN f_lk[577]
    DIRECTION INOUT ;
    USE SIGNAL ;
    PORT
      LAYER M4 ;
        RECT 2599.808 725.136 2600.000 725.160 ;
    END
  END f_lk[577]
  PIN f_lk[578]
    DIRECTION INOUT ;
    USE SIGNAL ;
    PORT
      LAYER M4 ;
        RECT 2599.808 725.328 2600.000 725.352 ;
    END
  END f_lk[578]
  PIN f_lk[579]
    DIRECTION INOUT ;
    USE SIGNAL ;
    PORT
      LAYER M4 ;
        RECT 2599.808 725.520 2600.000 725.544 ;
    END
  END f_lk[579]
  PIN f_lk[580]
    DIRECTION INOUT ;
    USE SIGNAL ;
    PORT
      LAYER M4 ;
        RECT 2599.808 725.712 2600.000 725.736 ;
    END
  END f_lk[580]
  PIN f_lk[581]
    DIRECTION INOUT ;
    USE SIGNAL ;
    PORT
      LAYER M4 ;
        RECT 2599.808 725.904 2600.000 725.928 ;
    END
  END f_lk[581]
  PIN f_lk[582]
    DIRECTION INOUT ;
    USE SIGNAL ;
    PORT
      LAYER M4 ;
        RECT 2599.808 726.096 2600.000 726.120 ;
    END
  END f_lk[582]
  PIN f_lk[583]
    DIRECTION INOUT ;
    USE SIGNAL ;
    PORT
      LAYER M4 ;
        RECT 2599.808 726.288 2600.000 726.312 ;
    END
  END f_lk[583]
  PIN f_lk[584]
    DIRECTION INOUT ;
    USE SIGNAL ;
    PORT
      LAYER M4 ;
        RECT 2599.808 726.480 2600.000 726.504 ;
    END
  END f_lk[584]
  PIN f_lk[585]
    DIRECTION INOUT ;
    USE SIGNAL ;
    PORT
      LAYER M4 ;
        RECT 2599.808 726.672 2600.000 726.696 ;
    END
  END f_lk[585]
  PIN f_lk[586]
    DIRECTION INOUT ;
    USE SIGNAL ;
    PORT
      LAYER M4 ;
        RECT 2599.808 726.864 2600.000 726.888 ;
    END
  END f_lk[586]
  PIN f_lk[587]
    DIRECTION INOUT ;
    USE SIGNAL ;
    PORT
      LAYER M4 ;
        RECT 2599.808 727.056 2600.000 727.080 ;
    END
  END f_lk[587]
  PIN f_lk[588]
    DIRECTION INOUT ;
    USE SIGNAL ;
    PORT
      LAYER M4 ;
        RECT 2599.808 727.248 2600.000 727.272 ;
    END
  END f_lk[588]
  PIN f_lk[589]
    DIRECTION INOUT ;
    USE SIGNAL ;
    PORT
      LAYER M4 ;
        RECT 2599.808 727.440 2600.000 727.464 ;
    END
  END f_lk[589]
  PIN f_lk[590]
    DIRECTION INOUT ;
    USE SIGNAL ;
    PORT
      LAYER M4 ;
        RECT 2599.808 727.632 2600.000 727.656 ;
    END
  END f_lk[590]
  PIN f_lk[591]
    DIRECTION INOUT ;
    USE SIGNAL ;
    PORT
      LAYER M4 ;
        RECT 2599.808 727.824 2600.000 727.848 ;
    END
  END f_lk[591]
  PIN f_lk[592]
    DIRECTION INOUT ;
    USE SIGNAL ;
    PORT
      LAYER M4 ;
        RECT 2599.808 728.016 2600.000 728.040 ;
    END
  END f_lk[592]
  PIN f_lk[593]
    DIRECTION INOUT ;
    USE SIGNAL ;
    PORT
      LAYER M4 ;
        RECT 2599.808 728.208 2600.000 728.232 ;
    END
  END f_lk[593]
  PIN f_lk[594]
    DIRECTION INOUT ;
    USE SIGNAL ;
    PORT
      LAYER M4 ;
        RECT 2599.808 728.400 2600.000 728.424 ;
    END
  END f_lk[594]
  PIN f_lk[595]
    DIRECTION INOUT ;
    USE SIGNAL ;
    PORT
      LAYER M4 ;
        RECT 2599.808 728.592 2600.000 728.616 ;
    END
  END f_lk[595]
  PIN f_lk[596]
    DIRECTION INOUT ;
    USE SIGNAL ;
    PORT
      LAYER M4 ;
        RECT 2599.808 728.784 2600.000 728.808 ;
    END
  END f_lk[596]
  PIN f_lk[597]
    DIRECTION INOUT ;
    USE SIGNAL ;
    PORT
      LAYER M4 ;
        RECT 2599.808 728.976 2600.000 729.000 ;
    END
  END f_lk[597]
  PIN f_lk[598]
    DIRECTION INOUT ;
    USE SIGNAL ;
    PORT
      LAYER M4 ;
        RECT 2599.808 729.168 2600.000 729.192 ;
    END
  END f_lk[598]
  PIN f_lk[599]
    DIRECTION INOUT ;
    USE SIGNAL ;
    PORT
      LAYER M4 ;
        RECT 2599.808 729.360 2600.000 729.384 ;
    END
  END f_lk[599]
  PIN f_lk[600]
    DIRECTION INOUT ;
    USE SIGNAL ;
    PORT
      LAYER M4 ;
        RECT 2599.808 729.552 2600.000 729.576 ;
    END
  END f_lk[600]
  PIN f_lk[601]
    DIRECTION INOUT ;
    USE SIGNAL ;
    PORT
      LAYER M4 ;
        RECT 2599.808 729.744 2600.000 729.768 ;
    END
  END f_lk[601]
  PIN f_lk[602]
    DIRECTION INOUT ;
    USE SIGNAL ;
    PORT
      LAYER M4 ;
        RECT 2599.808 729.936 2600.000 729.960 ;
    END
  END f_lk[602]
  PIN f_lk[603]
    DIRECTION INOUT ;
    USE SIGNAL ;
    PORT
      LAYER M4 ;
        RECT 2599.808 730.128 2600.000 730.152 ;
    END
  END f_lk[603]
  PIN f_lk[604]
    DIRECTION INOUT ;
    USE SIGNAL ;
    PORT
      LAYER M4 ;
        RECT 2599.808 730.320 2600.000 730.344 ;
    END
  END f_lk[604]
  PIN f_lk[605]
    DIRECTION INOUT ;
    USE SIGNAL ;
    PORT
      LAYER M4 ;
        RECT 2599.808 730.512 2600.000 730.536 ;
    END
  END f_lk[605]
  PIN f_lk[606]
    DIRECTION INOUT ;
    USE SIGNAL ;
    PORT
      LAYER M4 ;
        RECT 2599.808 730.704 2600.000 730.728 ;
    END
  END f_lk[606]
  PIN f_lk[607]
    DIRECTION INOUT ;
    USE SIGNAL ;
    PORT
      LAYER M4 ;
        RECT 2599.808 730.896 2600.000 730.920 ;
    END
  END f_lk[607]
  PIN f_lk[608]
    DIRECTION INOUT ;
    USE SIGNAL ;
    PORT
      LAYER M4 ;
        RECT 2599.808 731.088 2600.000 731.112 ;
    END
  END f_lk[608]
  PIN f_lk[609]
    DIRECTION INOUT ;
    USE SIGNAL ;
    PORT
      LAYER M4 ;
        RECT 2599.808 731.280 2600.000 731.304 ;
    END
  END f_lk[609]
  PIN f_lk[610]
    DIRECTION INOUT ;
    USE SIGNAL ;
    PORT
      LAYER M4 ;
        RECT 2599.808 731.472 2600.000 731.496 ;
    END
  END f_lk[610]
  PIN f_lk[611]
    DIRECTION INOUT ;
    USE SIGNAL ;
    PORT
      LAYER M4 ;
        RECT 2599.808 731.664 2600.000 731.688 ;
    END
  END f_lk[611]
  PIN f_lk[612]
    DIRECTION INOUT ;
    USE SIGNAL ;
    PORT
      LAYER M4 ;
        RECT 2599.808 731.856 2600.000 731.880 ;
    END
  END f_lk[612]
  PIN f_lk[613]
    DIRECTION INOUT ;
    USE SIGNAL ;
    PORT
      LAYER M4 ;
        RECT 2599.808 732.048 2600.000 732.072 ;
    END
  END f_lk[613]
  PIN f_lk[614]
    DIRECTION INOUT ;
    USE SIGNAL ;
    PORT
      LAYER M4 ;
        RECT 2599.808 732.240 2600.000 732.264 ;
    END
  END f_lk[614]
  PIN f_lk[615]
    DIRECTION INOUT ;
    USE SIGNAL ;
    PORT
      LAYER M4 ;
        RECT 2599.808 732.432 2600.000 732.456 ;
    END
  END f_lk[615]
  PIN f_lk[616]
    DIRECTION INOUT ;
    USE SIGNAL ;
    PORT
      LAYER M4 ;
        RECT 2599.808 732.624 2600.000 732.648 ;
    END
  END f_lk[616]
  PIN f_lk[617]
    DIRECTION INOUT ;
    USE SIGNAL ;
    PORT
      LAYER M4 ;
        RECT 2599.808 732.816 2600.000 732.840 ;
    END
  END f_lk[617]
  PIN f_lk[618]
    DIRECTION INOUT ;
    USE SIGNAL ;
    PORT
      LAYER M4 ;
        RECT 2599.808 733.008 2600.000 733.032 ;
    END
  END f_lk[618]
  PIN f_lk[619]
    DIRECTION INOUT ;
    USE SIGNAL ;
    PORT
      LAYER M4 ;
        RECT 2599.808 733.200 2600.000 733.224 ;
    END
  END f_lk[619]
  PIN f_lk[620]
    DIRECTION INOUT ;
    USE SIGNAL ;
    PORT
      LAYER M4 ;
        RECT 2599.808 733.392 2600.000 733.416 ;
    END
  END f_lk[620]
  PIN f_lk[621]
    DIRECTION INOUT ;
    USE SIGNAL ;
    PORT
      LAYER M4 ;
        RECT 2599.808 733.584 2600.000 733.608 ;
    END
  END f_lk[621]
  PIN f_lk[622]
    DIRECTION INOUT ;
    USE SIGNAL ;
    PORT
      LAYER M4 ;
        RECT 2599.808 733.776 2600.000 733.800 ;
    END
  END f_lk[622]
  PIN f_lk[623]
    DIRECTION INOUT ;
    USE SIGNAL ;
    PORT
      LAYER M4 ;
        RECT 2599.808 733.968 2600.000 733.992 ;
    END
  END f_lk[623]
  PIN f_lk[624]
    DIRECTION INOUT ;
    USE SIGNAL ;
    PORT
      LAYER M4 ;
        RECT 2599.808 734.160 2600.000 734.184 ;
    END
  END f_lk[624]
  PIN f_lk[625]
    DIRECTION INOUT ;
    USE SIGNAL ;
    PORT
      LAYER M4 ;
        RECT 2599.808 734.352 2600.000 734.376 ;
    END
  END f_lk[625]
  PIN f_lk[626]
    DIRECTION INOUT ;
    USE SIGNAL ;
    PORT
      LAYER M4 ;
        RECT 2599.808 734.544 2600.000 734.568 ;
    END
  END f_lk[626]
  PIN f_lk[627]
    DIRECTION INOUT ;
    USE SIGNAL ;
    PORT
      LAYER M4 ;
        RECT 2599.808 734.736 2600.000 734.760 ;
    END
  END f_lk[627]
  PIN f_lk[628]
    DIRECTION INOUT ;
    USE SIGNAL ;
    PORT
      LAYER M4 ;
        RECT 2599.808 734.928 2600.000 734.952 ;
    END
  END f_lk[628]
  PIN f_lk[629]
    DIRECTION INOUT ;
    USE SIGNAL ;
    PORT
      LAYER M4 ;
        RECT 2599.808 735.120 2600.000 735.144 ;
    END
  END f_lk[629]
  PIN f_lk[630]
    DIRECTION INOUT ;
    USE SIGNAL ;
    PORT
      LAYER M4 ;
        RECT 2599.808 735.312 2600.000 735.336 ;
    END
  END f_lk[630]
  PIN f_lk[631]
    DIRECTION INOUT ;
    USE SIGNAL ;
    PORT
      LAYER M4 ;
        RECT 2599.808 735.504 2600.000 735.528 ;
    END
  END f_lk[631]
  PIN f_lk[632]
    DIRECTION INOUT ;
    USE SIGNAL ;
    PORT
      LAYER M4 ;
        RECT 2599.808 735.696 2600.000 735.720 ;
    END
  END f_lk[632]
  PIN f_lk[633]
    DIRECTION INOUT ;
    USE SIGNAL ;
    PORT
      LAYER M4 ;
        RECT 2599.808 735.888 2600.000 735.912 ;
    END
  END f_lk[633]
  PIN f_lk[634]
    DIRECTION INOUT ;
    USE SIGNAL ;
    PORT
      LAYER M4 ;
        RECT 2599.808 736.080 2600.000 736.104 ;
    END
  END f_lk[634]
  PIN f_lk[635]
    DIRECTION INOUT ;
    USE SIGNAL ;
    PORT
      LAYER M4 ;
        RECT 2599.808 736.272 2600.000 736.296 ;
    END
  END f_lk[635]
  PIN f_lk[636]
    DIRECTION INOUT ;
    USE SIGNAL ;
    PORT
      LAYER M4 ;
        RECT 2599.808 736.464 2600.000 736.488 ;
    END
  END f_lk[636]
  PIN f_lk[637]
    DIRECTION INOUT ;
    USE SIGNAL ;
    PORT
      LAYER M4 ;
        RECT 2599.808 736.656 2600.000 736.680 ;
    END
  END f_lk[637]
  PIN f_lk[638]
    DIRECTION INOUT ;
    USE SIGNAL ;
    PORT
      LAYER M4 ;
        RECT 2599.808 736.848 2600.000 736.872 ;
    END
  END f_lk[638]
  PIN f_lk[639]
    DIRECTION INOUT ;
    USE SIGNAL ;
    PORT
      LAYER M4 ;
        RECT 2599.808 737.040 2600.000 737.064 ;
    END
  END f_lk[639]
  PIN f_lk[640]
    DIRECTION INOUT ;
    USE SIGNAL ;
    PORT
      LAYER M4 ;
        RECT 2599.808 737.232 2600.000 737.256 ;
    END
  END f_lk[640]
  PIN f_lk[641]
    DIRECTION INOUT ;
    USE SIGNAL ;
    PORT
      LAYER M4 ;
        RECT 2599.808 737.424 2600.000 737.448 ;
    END
  END f_lk[641]
  PIN f_lk[642]
    DIRECTION INOUT ;
    USE SIGNAL ;
    PORT
      LAYER M4 ;
        RECT 2599.808 737.616 2600.000 737.640 ;
    END
  END f_lk[642]
  PIN f_lk[643]
    DIRECTION INOUT ;
    USE SIGNAL ;
    PORT
      LAYER M4 ;
        RECT 2599.808 737.808 2600.000 737.832 ;
    END
  END f_lk[643]
  PIN f_lk[644]
    DIRECTION INOUT ;
    USE SIGNAL ;
    PORT
      LAYER M4 ;
        RECT 2599.808 738.000 2600.000 738.024 ;
    END
  END f_lk[644]
  PIN f_lk[645]
    DIRECTION INOUT ;
    USE SIGNAL ;
    PORT
      LAYER M4 ;
        RECT 2599.808 738.192 2600.000 738.216 ;
    END
  END f_lk[645]
  PIN f_lk[646]
    DIRECTION INOUT ;
    USE SIGNAL ;
    PORT
      LAYER M4 ;
        RECT 2599.808 738.384 2600.000 738.408 ;
    END
  END f_lk[646]
  PIN f_lk[647]
    DIRECTION INOUT ;
    USE SIGNAL ;
    PORT
      LAYER M4 ;
        RECT 2599.808 738.576 2600.000 738.600 ;
    END
  END f_lk[647]
  PIN f_lk[648]
    DIRECTION INOUT ;
    USE SIGNAL ;
    PORT
      LAYER M4 ;
        RECT 2599.808 738.768 2600.000 738.792 ;
    END
  END f_lk[648]
  PIN f_lk[649]
    DIRECTION INOUT ;
    USE SIGNAL ;
    PORT
      LAYER M4 ;
        RECT 2599.808 738.960 2600.000 738.984 ;
    END
  END f_lk[649]
  PIN f_lk[650]
    DIRECTION INOUT ;
    USE SIGNAL ;
    PORT
      LAYER M4 ;
        RECT 2599.808 739.152 2600.000 739.176 ;
    END
  END f_lk[650]
  PIN f_lk[651]
    DIRECTION INOUT ;
    USE SIGNAL ;
    PORT
      LAYER M4 ;
        RECT 2599.808 739.344 2600.000 739.368 ;
    END
  END f_lk[651]
  PIN f_lk[652]
    DIRECTION INOUT ;
    USE SIGNAL ;
    PORT
      LAYER M4 ;
        RECT 2599.808 739.536 2600.000 739.560 ;
    END
  END f_lk[652]
  PIN f_lk[653]
    DIRECTION INOUT ;
    USE SIGNAL ;
    PORT
      LAYER M4 ;
        RECT 2599.808 739.728 2600.000 739.752 ;
    END
  END f_lk[653]
  PIN f_lk[654]
    DIRECTION INOUT ;
    USE SIGNAL ;
    PORT
      LAYER M4 ;
        RECT 2599.808 739.920 2600.000 739.944 ;
    END
  END f_lk[654]
  PIN f_lk[655]
    DIRECTION INOUT ;
    USE SIGNAL ;
    PORT
      LAYER M4 ;
        RECT 2599.808 740.112 2600.000 740.136 ;
    END
  END f_lk[655]
  PIN f_lk[656]
    DIRECTION INOUT ;
    USE SIGNAL ;
    PORT
      LAYER M4 ;
        RECT 2599.808 740.304 2600.000 740.328 ;
    END
  END f_lk[656]
  PIN f_lk[657]
    DIRECTION INOUT ;
    USE SIGNAL ;
    PORT
      LAYER M4 ;
        RECT 2599.808 740.496 2600.000 740.520 ;
    END
  END f_lk[657]
  PIN f_lk[658]
    DIRECTION INOUT ;
    USE SIGNAL ;
    PORT
      LAYER M4 ;
        RECT 2599.808 740.688 2600.000 740.712 ;
    END
  END f_lk[658]
  PIN f_lk[659]
    DIRECTION INOUT ;
    USE SIGNAL ;
    PORT
      LAYER M4 ;
        RECT 2599.808 740.880 2600.000 740.904 ;
    END
  END f_lk[659]
  PIN f_lk[660]
    DIRECTION INOUT ;
    USE SIGNAL ;
    PORT
      LAYER M4 ;
        RECT 2599.808 741.072 2600.000 741.096 ;
    END
  END f_lk[660]
  PIN f_lk[661]
    DIRECTION INOUT ;
    USE SIGNAL ;
    PORT
      LAYER M4 ;
        RECT 2599.808 741.264 2600.000 741.288 ;
    END
  END f_lk[661]
  PIN f_lk[662]
    DIRECTION INOUT ;
    USE SIGNAL ;
    PORT
      LAYER M4 ;
        RECT 2599.808 741.456 2600.000 741.480 ;
    END
  END f_lk[662]
  PIN f_lk[663]
    DIRECTION INOUT ;
    USE SIGNAL ;
    PORT
      LAYER M4 ;
        RECT 2599.808 741.648 2600.000 741.672 ;
    END
  END f_lk[663]
  PIN f_lk[664]
    DIRECTION INOUT ;
    USE SIGNAL ;
    PORT
      LAYER M4 ;
        RECT 2599.808 741.840 2600.000 741.864 ;
    END
  END f_lk[664]
  PIN f_lk[665]
    DIRECTION INOUT ;
    USE SIGNAL ;
    PORT
      LAYER M4 ;
        RECT 2599.808 742.032 2600.000 742.056 ;
    END
  END f_lk[665]
  PIN f_lk[666]
    DIRECTION INOUT ;
    USE SIGNAL ;
    PORT
      LAYER M4 ;
        RECT 2599.808 742.224 2600.000 742.248 ;
    END
  END f_lk[666]
  PIN f_lk[667]
    DIRECTION INOUT ;
    USE SIGNAL ;
    PORT
      LAYER M4 ;
        RECT 2599.808 742.416 2600.000 742.440 ;
    END
  END f_lk[667]
  PIN f_lk[668]
    DIRECTION INOUT ;
    USE SIGNAL ;
    PORT
      LAYER M4 ;
        RECT 2599.808 742.608 2600.000 742.632 ;
    END
  END f_lk[668]
  PIN f_lk[669]
    DIRECTION INOUT ;
    USE SIGNAL ;
    PORT
      LAYER M4 ;
        RECT 2599.808 742.800 2600.000 742.824 ;
    END
  END f_lk[669]
  PIN f_lk[670]
    DIRECTION INOUT ;
    USE SIGNAL ;
    PORT
      LAYER M4 ;
        RECT 2599.808 742.992 2600.000 743.016 ;
    END
  END f_lk[670]
  PIN f_lk[671]
    DIRECTION INOUT ;
    USE SIGNAL ;
    PORT
      LAYER M4 ;
        RECT 2599.808 743.184 2600.000 743.208 ;
    END
  END f_lk[671]
  PIN f_lk[672]
    DIRECTION INOUT ;
    USE SIGNAL ;
    PORT
      LAYER M4 ;
        RECT 2599.808 743.376 2600.000 743.400 ;
    END
  END f_lk[672]
  PIN f_lk[673]
    DIRECTION INOUT ;
    USE SIGNAL ;
    PORT
      LAYER M4 ;
        RECT 2599.808 743.568 2600.000 743.592 ;
    END
  END f_lk[673]
  PIN f_lk[674]
    DIRECTION INOUT ;
    USE SIGNAL ;
    PORT
      LAYER M4 ;
        RECT 2599.808 743.760 2600.000 743.784 ;
    END
  END f_lk[674]
  PIN f_lk[675]
    DIRECTION INOUT ;
    USE SIGNAL ;
    PORT
      LAYER M4 ;
        RECT 2599.808 743.952 2600.000 743.976 ;
    END
  END f_lk[675]
  PIN f_lk[676]
    DIRECTION INOUT ;
    USE SIGNAL ;
    PORT
      LAYER M4 ;
        RECT 2599.808 744.144 2600.000 744.168 ;
    END
  END f_lk[676]
  PIN f_lk[677]
    DIRECTION INOUT ;
    USE SIGNAL ;
    PORT
      LAYER M4 ;
        RECT 2599.808 744.336 2600.000 744.360 ;
    END
  END f_lk[677]
  PIN f_lk[678]
    DIRECTION INOUT ;
    USE SIGNAL ;
    PORT
      LAYER M4 ;
        RECT 2599.808 744.528 2600.000 744.552 ;
    END
  END f_lk[678]
  PIN f_lk[679]
    DIRECTION INOUT ;
    USE SIGNAL ;
    PORT
      LAYER M4 ;
        RECT 2599.808 744.720 2600.000 744.744 ;
    END
  END f_lk[679]
  PIN f_lk[680]
    DIRECTION INOUT ;
    USE SIGNAL ;
    PORT
      LAYER M4 ;
        RECT 2599.808 744.912 2600.000 744.936 ;
    END
  END f_lk[680]
  PIN f_lk[681]
    DIRECTION INOUT ;
    USE SIGNAL ;
    PORT
      LAYER M4 ;
        RECT 2599.808 745.104 2600.000 745.128 ;
    END
  END f_lk[681]
  PIN f_lk[682]
    DIRECTION INOUT ;
    USE SIGNAL ;
    PORT
      LAYER M4 ;
        RECT 2599.808 745.296 2600.000 745.320 ;
    END
  END f_lk[682]
  PIN f_lk[683]
    DIRECTION INOUT ;
    USE SIGNAL ;
    PORT
      LAYER M4 ;
        RECT 2599.808 745.488 2600.000 745.512 ;
    END
  END f_lk[683]
  PIN f_lk[684]
    DIRECTION INOUT ;
    USE SIGNAL ;
    PORT
      LAYER M4 ;
        RECT 2599.808 745.680 2600.000 745.704 ;
    END
  END f_lk[684]
  PIN f_lk[685]
    DIRECTION INOUT ;
    USE SIGNAL ;
    PORT
      LAYER M4 ;
        RECT 2599.808 745.872 2600.000 745.896 ;
    END
  END f_lk[685]
  PIN f_lk[686]
    DIRECTION INOUT ;
    USE SIGNAL ;
    PORT
      LAYER M4 ;
        RECT 2599.808 746.064 2600.000 746.088 ;
    END
  END f_lk[686]
  PIN f_lk[687]
    DIRECTION INOUT ;
    USE SIGNAL ;
    PORT
      LAYER M4 ;
        RECT 2599.808 746.256 2600.000 746.280 ;
    END
  END f_lk[687]
  PIN f_lk[688]
    DIRECTION INOUT ;
    USE SIGNAL ;
    PORT
      LAYER M4 ;
        RECT 2599.808 746.448 2600.000 746.472 ;
    END
  END f_lk[688]
  PIN f_lk[689]
    DIRECTION INOUT ;
    USE SIGNAL ;
    PORT
      LAYER M4 ;
        RECT 2599.808 746.640 2600.000 746.664 ;
    END
  END f_lk[689]
  PIN f_lk[690]
    DIRECTION INOUT ;
    USE SIGNAL ;
    PORT
      LAYER M4 ;
        RECT 2599.808 746.832 2600.000 746.856 ;
    END
  END f_lk[690]
  PIN f_lk[691]
    DIRECTION INOUT ;
    USE SIGNAL ;
    PORT
      LAYER M4 ;
        RECT 2599.808 747.024 2600.000 747.048 ;
    END
  END f_lk[691]
  PIN f_lk[692]
    DIRECTION INOUT ;
    USE SIGNAL ;
    PORT
      LAYER M4 ;
        RECT 2599.808 747.216 2600.000 747.240 ;
    END
  END f_lk[692]
  PIN f_lk[693]
    DIRECTION INOUT ;
    USE SIGNAL ;
    PORT
      LAYER M4 ;
        RECT 2599.808 747.408 2600.000 747.432 ;
    END
  END f_lk[693]
  PIN f_lk[694]
    DIRECTION INOUT ;
    USE SIGNAL ;
    PORT
      LAYER M4 ;
        RECT 2599.808 747.600 2600.000 747.624 ;
    END
  END f_lk[694]
  PIN f_lk[695]
    DIRECTION INOUT ;
    USE SIGNAL ;
    PORT
      LAYER M4 ;
        RECT 2599.808 747.792 2600.000 747.816 ;
    END
  END f_lk[695]
  PIN f_lk[696]
    DIRECTION INOUT ;
    USE SIGNAL ;
    PORT
      LAYER M4 ;
        RECT 2599.808 747.984 2600.000 748.008 ;
    END
  END f_lk[696]
  PIN f_lk[697]
    DIRECTION INOUT ;
    USE SIGNAL ;
    PORT
      LAYER M4 ;
        RECT 2599.808 748.176 2600.000 748.200 ;
    END
  END f_lk[697]
  PIN f_lk[698]
    DIRECTION INOUT ;
    USE SIGNAL ;
    PORT
      LAYER M4 ;
        RECT 2599.808 748.368 2600.000 748.392 ;
    END
  END f_lk[698]
  PIN f_lk[699]
    DIRECTION INOUT ;
    USE SIGNAL ;
    PORT
      LAYER M4 ;
        RECT 2599.808 748.560 2600.000 748.584 ;
    END
  END f_lk[699]
  PIN f_lk[700]
    DIRECTION INOUT ;
    USE SIGNAL ;
    PORT
      LAYER M4 ;
        RECT 2599.808 748.752 2600.000 748.776 ;
    END
  END f_lk[700]
  PIN f_lk[701]
    DIRECTION INOUT ;
    USE SIGNAL ;
    PORT
      LAYER M4 ;
        RECT 2599.808 748.944 2600.000 748.968 ;
    END
  END f_lk[701]
  PIN f_lk[702]
    DIRECTION INOUT ;
    USE SIGNAL ;
    PORT
      LAYER M4 ;
        RECT 2599.808 749.136 2600.000 749.160 ;
    END
  END f_lk[702]
  PIN f_lk[703]
    DIRECTION INOUT ;
    USE SIGNAL ;
    PORT
      LAYER M4 ;
        RECT 2599.808 749.328 2600.000 749.352 ;
    END
  END f_lk[703]
  PIN f_lk[704]
    DIRECTION INOUT ;
    USE SIGNAL ;
    PORT
      LAYER M4 ;
        RECT 2599.808 749.520 2600.000 749.544 ;
    END
  END f_lk[704]
  PIN f_lk[705]
    DIRECTION INOUT ;
    USE SIGNAL ;
    PORT
      LAYER M4 ;
        RECT 2599.808 749.712 2600.000 749.736 ;
    END
  END f_lk[705]
  PIN f_lk[706]
    DIRECTION INOUT ;
    USE SIGNAL ;
    PORT
      LAYER M4 ;
        RECT 2599.808 749.904 2600.000 749.928 ;
    END
  END f_lk[706]
  PIN f_lk[707]
    DIRECTION INOUT ;
    USE SIGNAL ;
    PORT
      LAYER M4 ;
        RECT 2599.808 750.096 2600.000 750.120 ;
    END
  END f_lk[707]
  PIN f_lk[708]
    DIRECTION INOUT ;
    USE SIGNAL ;
    PORT
      LAYER M4 ;
        RECT 2599.808 750.288 2600.000 750.312 ;
    END
  END f_lk[708]
  PIN f_lk[709]
    DIRECTION INOUT ;
    USE SIGNAL ;
    PORT
      LAYER M4 ;
        RECT 2599.808 750.480 2600.000 750.504 ;
    END
  END f_lk[709]
  PIN f_lk[710]
    DIRECTION INOUT ;
    USE SIGNAL ;
    PORT
      LAYER M4 ;
        RECT 2599.808 750.672 2600.000 750.696 ;
    END
  END f_lk[710]
  PIN f_lk[711]
    DIRECTION INOUT ;
    USE SIGNAL ;
    PORT
      LAYER M4 ;
        RECT 2599.808 750.864 2600.000 750.888 ;
    END
  END f_lk[711]
  PIN f_lk[712]
    DIRECTION INOUT ;
    USE SIGNAL ;
    PORT
      LAYER M4 ;
        RECT 2599.808 751.056 2600.000 751.080 ;
    END
  END f_lk[712]
  PIN f_lk[713]
    DIRECTION INOUT ;
    USE SIGNAL ;
    PORT
      LAYER M4 ;
        RECT 2599.808 751.248 2600.000 751.272 ;
    END
  END f_lk[713]
  PIN f_lk[714]
    DIRECTION INOUT ;
    USE SIGNAL ;
    PORT
      LAYER M4 ;
        RECT 2599.808 751.440 2600.000 751.464 ;
    END
  END f_lk[714]
  PIN f_lk[715]
    DIRECTION INOUT ;
    USE SIGNAL ;
    PORT
      LAYER M4 ;
        RECT 2599.808 751.632 2600.000 751.656 ;
    END
  END f_lk[715]
  PIN f_lk[716]
    DIRECTION INOUT ;
    USE SIGNAL ;
    PORT
      LAYER M4 ;
        RECT 2599.808 751.824 2600.000 751.848 ;
    END
  END f_lk[716]
  PIN f_lk[717]
    DIRECTION INOUT ;
    USE SIGNAL ;
    PORT
      LAYER M4 ;
        RECT 2599.808 752.016 2600.000 752.040 ;
    END
  END f_lk[717]
  PIN f_lk[718]
    DIRECTION INOUT ;
    USE SIGNAL ;
    PORT
      LAYER M4 ;
        RECT 2599.808 752.208 2600.000 752.232 ;
    END
  END f_lk[718]
  PIN f_lk[719]
    DIRECTION INOUT ;
    USE SIGNAL ;
    PORT
      LAYER M4 ;
        RECT 2599.808 752.400 2600.000 752.424 ;
    END
  END f_lk[719]
  PIN f_lk[720]
    DIRECTION INOUT ;
    USE SIGNAL ;
    PORT
      LAYER M4 ;
        RECT 2599.808 752.592 2600.000 752.616 ;
    END
  END f_lk[720]
  PIN f_lk[721]
    DIRECTION INOUT ;
    USE SIGNAL ;
    PORT
      LAYER M4 ;
        RECT 2599.808 752.784 2600.000 752.808 ;
    END
  END f_lk[721]
  PIN f_lk[722]
    DIRECTION INOUT ;
    USE SIGNAL ;
    PORT
      LAYER M4 ;
        RECT 2599.808 752.976 2600.000 753.000 ;
    END
  END f_lk[722]
  PIN f_lk[723]
    DIRECTION INOUT ;
    USE SIGNAL ;
    PORT
      LAYER M4 ;
        RECT 2599.808 753.168 2600.000 753.192 ;
    END
  END f_lk[723]
  PIN f_lk[724]
    DIRECTION INOUT ;
    USE SIGNAL ;
    PORT
      LAYER M4 ;
        RECT 2599.808 753.360 2600.000 753.384 ;
    END
  END f_lk[724]
  PIN f_lk[725]
    DIRECTION INOUT ;
    USE SIGNAL ;
    PORT
      LAYER M4 ;
        RECT 2599.808 753.552 2600.000 753.576 ;
    END
  END f_lk[725]
  PIN f_lk[726]
    DIRECTION INOUT ;
    USE SIGNAL ;
    PORT
      LAYER M4 ;
        RECT 2599.808 753.744 2600.000 753.768 ;
    END
  END f_lk[726]
  PIN f_lk[727]
    DIRECTION INOUT ;
    USE SIGNAL ;
    PORT
      LAYER M4 ;
        RECT 2599.808 753.936 2600.000 753.960 ;
    END
  END f_lk[727]
  PIN f_lk[728]
    DIRECTION INOUT ;
    USE SIGNAL ;
    PORT
      LAYER M4 ;
        RECT 2599.808 754.128 2600.000 754.152 ;
    END
  END f_lk[728]
  PIN f_lk[729]
    DIRECTION INOUT ;
    USE SIGNAL ;
    PORT
      LAYER M4 ;
        RECT 2599.808 754.320 2600.000 754.344 ;
    END
  END f_lk[729]
  PIN f_lk[730]
    DIRECTION INOUT ;
    USE SIGNAL ;
    PORT
      LAYER M4 ;
        RECT 2599.808 754.512 2600.000 754.536 ;
    END
  END f_lk[730]
  PIN f_lk[731]
    DIRECTION INOUT ;
    USE SIGNAL ;
    PORT
      LAYER M4 ;
        RECT 2599.808 754.704 2600.000 754.728 ;
    END
  END f_lk[731]
  PIN f_lk[732]
    DIRECTION INOUT ;
    USE SIGNAL ;
    PORT
      LAYER M4 ;
        RECT 2599.808 754.896 2600.000 754.920 ;
    END
  END f_lk[732]
  PIN f_lk[733]
    DIRECTION INOUT ;
    USE SIGNAL ;
    PORT
      LAYER M4 ;
        RECT 2599.808 755.088 2600.000 755.112 ;
    END
  END f_lk[733]
  PIN f_lk[734]
    DIRECTION INOUT ;
    USE SIGNAL ;
    PORT
      LAYER M4 ;
        RECT 2599.808 755.280 2600.000 755.304 ;
    END
  END f_lk[734]
  PIN f_lk[735]
    DIRECTION INOUT ;
    USE SIGNAL ;
    PORT
      LAYER M4 ;
        RECT 2599.808 755.472 2600.000 755.496 ;
    END
  END f_lk[735]
  PIN f_lk[736]
    DIRECTION INOUT ;
    USE SIGNAL ;
    PORT
      LAYER M4 ;
        RECT 2599.808 755.664 2600.000 755.688 ;
    END
  END f_lk[736]
  PIN f_lk[737]
    DIRECTION INOUT ;
    USE SIGNAL ;
    PORT
      LAYER M4 ;
        RECT 2599.808 755.856 2600.000 755.880 ;
    END
  END f_lk[737]
  PIN f_lk[738]
    DIRECTION INOUT ;
    USE SIGNAL ;
    PORT
      LAYER M4 ;
        RECT 2599.808 756.048 2600.000 756.072 ;
    END
  END f_lk[738]
  PIN f_lk[739]
    DIRECTION INOUT ;
    USE SIGNAL ;
    PORT
      LAYER M4 ;
        RECT 2599.808 756.240 2600.000 756.264 ;
    END
  END f_lk[739]
  PIN f_lk[740]
    DIRECTION INOUT ;
    USE SIGNAL ;
    PORT
      LAYER M4 ;
        RECT 2599.808 756.432 2600.000 756.456 ;
    END
  END f_lk[740]
  PIN f_lk[741]
    DIRECTION INOUT ;
    USE SIGNAL ;
    PORT
      LAYER M4 ;
        RECT 2599.808 756.624 2600.000 756.648 ;
    END
  END f_lk[741]
  PIN f_lk[742]
    DIRECTION INOUT ;
    USE SIGNAL ;
    PORT
      LAYER M4 ;
        RECT 2599.808 756.816 2600.000 756.840 ;
    END
  END f_lk[742]
  PIN f_lk[743]
    DIRECTION INOUT ;
    USE SIGNAL ;
    PORT
      LAYER M4 ;
        RECT 2599.808 757.008 2600.000 757.032 ;
    END
  END f_lk[743]
  PIN f_lk[744]
    DIRECTION INOUT ;
    USE SIGNAL ;
    PORT
      LAYER M4 ;
        RECT 2599.808 757.200 2600.000 757.224 ;
    END
  END f_lk[744]
  PIN f_lk[745]
    DIRECTION INOUT ;
    USE SIGNAL ;
    PORT
      LAYER M4 ;
        RECT 2599.808 757.392 2600.000 757.416 ;
    END
  END f_lk[745]
  PIN f_lk[746]
    DIRECTION INOUT ;
    USE SIGNAL ;
    PORT
      LAYER M4 ;
        RECT 2599.808 757.584 2600.000 757.608 ;
    END
  END f_lk[746]
  PIN f_lk[747]
    DIRECTION INOUT ;
    USE SIGNAL ;
    PORT
      LAYER M4 ;
        RECT 2599.808 757.776 2600.000 757.800 ;
    END
  END f_lk[747]
  PIN f_lk[748]
    DIRECTION INOUT ;
    USE SIGNAL ;
    PORT
      LAYER M4 ;
        RECT 2599.808 757.968 2600.000 757.992 ;
    END
  END f_lk[748]
  PIN f_lk[749]
    DIRECTION INOUT ;
    USE SIGNAL ;
    PORT
      LAYER M4 ;
        RECT 2599.808 758.160 2600.000 758.184 ;
    END
  END f_lk[749]
  PIN f_lk[750]
    DIRECTION INOUT ;
    USE SIGNAL ;
    PORT
      LAYER M4 ;
        RECT 2599.808 758.352 2600.000 758.376 ;
    END
  END f_lk[750]
  PIN f_lk[751]
    DIRECTION INOUT ;
    USE SIGNAL ;
    PORT
      LAYER M4 ;
        RECT 2599.808 758.544 2600.000 758.568 ;
    END
  END f_lk[751]
  PIN f_lk[752]
    DIRECTION INOUT ;
    USE SIGNAL ;
    PORT
      LAYER M4 ;
        RECT 2599.808 758.736 2600.000 758.760 ;
    END
  END f_lk[752]
  PIN f_lk[753]
    DIRECTION INOUT ;
    USE SIGNAL ;
    PORT
      LAYER M4 ;
        RECT 2599.808 758.928 2600.000 758.952 ;
    END
  END f_lk[753]
  PIN f_lk[754]
    DIRECTION INOUT ;
    USE SIGNAL ;
    PORT
      LAYER M4 ;
        RECT 2599.808 759.120 2600.000 759.144 ;
    END
  END f_lk[754]
  PIN f_lk[755]
    DIRECTION INOUT ;
    USE SIGNAL ;
    PORT
      LAYER M4 ;
        RECT 2599.808 759.312 2600.000 759.336 ;
    END
  END f_lk[755]
  PIN f_lk[756]
    DIRECTION INOUT ;
    USE SIGNAL ;
    PORT
      LAYER M4 ;
        RECT 2599.808 759.504 2600.000 759.528 ;
    END
  END f_lk[756]
  PIN f_lk[757]
    DIRECTION INOUT ;
    USE SIGNAL ;
    PORT
      LAYER M4 ;
        RECT 2599.808 759.696 2600.000 759.720 ;
    END
  END f_lk[757]
  PIN f_lk[758]
    DIRECTION INOUT ;
    USE SIGNAL ;
    PORT
      LAYER M4 ;
        RECT 2599.808 759.888 2600.000 759.912 ;
    END
  END f_lk[758]
  PIN f_lk[759]
    DIRECTION INOUT ;
    USE SIGNAL ;
    PORT
      LAYER M4 ;
        RECT 2599.808 760.080 2600.000 760.104 ;
    END
  END f_lk[759]
  PIN f_lk[760]
    DIRECTION INOUT ;
    USE SIGNAL ;
    PORT
      LAYER M4 ;
        RECT 2599.808 760.272 2600.000 760.296 ;
    END
  END f_lk[760]
  PIN f_lk[761]
    DIRECTION INOUT ;
    USE SIGNAL ;
    PORT
      LAYER M4 ;
        RECT 2599.808 760.464 2600.000 760.488 ;
    END
  END f_lk[761]
  PIN f_lk[762]
    DIRECTION INOUT ;
    USE SIGNAL ;
    PORT
      LAYER M4 ;
        RECT 2599.808 760.656 2600.000 760.680 ;
    END
  END f_lk[762]
  PIN f_lk[763]
    DIRECTION INOUT ;
    USE SIGNAL ;
    PORT
      LAYER M4 ;
        RECT 2599.808 760.848 2600.000 760.872 ;
    END
  END f_lk[763]
  PIN f_lk[764]
    DIRECTION INOUT ;
    USE SIGNAL ;
    PORT
      LAYER M4 ;
        RECT 2599.808 761.040 2600.000 761.064 ;
    END
  END f_lk[764]
  PIN f_lk[765]
    DIRECTION INOUT ;
    USE SIGNAL ;
    PORT
      LAYER M4 ;
        RECT 2599.808 761.232 2600.000 761.256 ;
    END
  END f_lk[765]
  PIN f_lk[766]
    DIRECTION INOUT ;
    USE SIGNAL ;
    PORT
      LAYER M4 ;
        RECT 2599.808 761.424 2600.000 761.448 ;
    END
  END f_lk[766]
  PIN f_lk[767]
    DIRECTION INOUT ;
    USE SIGNAL ;
    PORT
      LAYER M4 ;
        RECT 2599.808 761.616 2600.000 761.640 ;
    END
  END f_lk[767]
  PIN f_lk[768]
    DIRECTION INOUT ;
    USE SIGNAL ;
    PORT
      LAYER M4 ;
        RECT 2599.808 761.808 2600.000 761.832 ;
    END
  END f_lk[768]
  PIN f_lk[769]
    DIRECTION INOUT ;
    USE SIGNAL ;
    PORT
      LAYER M4 ;
        RECT 2599.808 762.000 2600.000 762.024 ;
    END
  END f_lk[769]
  PIN f_lk[770]
    DIRECTION INOUT ;
    USE SIGNAL ;
    PORT
      LAYER M4 ;
        RECT 2599.808 762.192 2600.000 762.216 ;
    END
  END f_lk[770]
  PIN f_lk[771]
    DIRECTION INOUT ;
    USE SIGNAL ;
    PORT
      LAYER M4 ;
        RECT 2599.808 762.384 2600.000 762.408 ;
    END
  END f_lk[771]
  PIN f_lk[772]
    DIRECTION INOUT ;
    USE SIGNAL ;
    PORT
      LAYER M4 ;
        RECT 2599.808 762.576 2600.000 762.600 ;
    END
  END f_lk[772]
  PIN f_lk[773]
    DIRECTION INOUT ;
    USE SIGNAL ;
    PORT
      LAYER M4 ;
        RECT 2599.808 762.768 2600.000 762.792 ;
    END
  END f_lk[773]
  PIN f_lk[774]
    DIRECTION INOUT ;
    USE SIGNAL ;
    PORT
      LAYER M4 ;
        RECT 2599.808 762.960 2600.000 762.984 ;
    END
  END f_lk[774]
  PIN f_lk[775]
    DIRECTION INOUT ;
    USE SIGNAL ;
    PORT
      LAYER M4 ;
        RECT 2599.808 763.152 2600.000 763.176 ;
    END
  END f_lk[775]
  PIN f_lk[776]
    DIRECTION INOUT ;
    USE SIGNAL ;
    PORT
      LAYER M4 ;
        RECT 2599.808 763.344 2600.000 763.368 ;
    END
  END f_lk[776]
  PIN f_lk[777]
    DIRECTION INOUT ;
    USE SIGNAL ;
    PORT
      LAYER M4 ;
        RECT 2599.808 763.536 2600.000 763.560 ;
    END
  END f_lk[777]
  PIN f_lk[778]
    DIRECTION INOUT ;
    USE SIGNAL ;
    PORT
      LAYER M4 ;
        RECT 2599.808 763.728 2600.000 763.752 ;
    END
  END f_lk[778]
  PIN f_lk[779]
    DIRECTION INOUT ;
    USE SIGNAL ;
    PORT
      LAYER M4 ;
        RECT 2599.808 763.920 2600.000 763.944 ;
    END
  END f_lk[779]
  PIN f_lk[780]
    DIRECTION INOUT ;
    USE SIGNAL ;
    PORT
      LAYER M4 ;
        RECT 2599.808 764.112 2600.000 764.136 ;
    END
  END f_lk[780]
  PIN f_lk[781]
    DIRECTION INOUT ;
    USE SIGNAL ;
    PORT
      LAYER M4 ;
        RECT 2599.808 764.304 2600.000 764.328 ;
    END
  END f_lk[781]
  PIN f_lk[782]
    DIRECTION INOUT ;
    USE SIGNAL ;
    PORT
      LAYER M4 ;
        RECT 2599.808 764.496 2600.000 764.520 ;
    END
  END f_lk[782]
  PIN f_lk[783]
    DIRECTION INOUT ;
    USE SIGNAL ;
    PORT
      LAYER M4 ;
        RECT 2599.808 764.688 2600.000 764.712 ;
    END
  END f_lk[783]
  PIN f_lk[784]
    DIRECTION INOUT ;
    USE SIGNAL ;
    PORT
      LAYER M4 ;
        RECT 2599.808 764.880 2600.000 764.904 ;
    END
  END f_lk[784]
  PIN f_lk[785]
    DIRECTION INOUT ;
    USE SIGNAL ;
    PORT
      LAYER M4 ;
        RECT 2599.808 765.072 2600.000 765.096 ;
    END
  END f_lk[785]
  PIN f_lk[786]
    DIRECTION INOUT ;
    USE SIGNAL ;
    PORT
      LAYER M4 ;
        RECT 2599.808 765.264 2600.000 765.288 ;
    END
  END f_lk[786]
  PIN f_lk[787]
    DIRECTION INOUT ;
    USE SIGNAL ;
    PORT
      LAYER M4 ;
        RECT 2599.808 765.456 2600.000 765.480 ;
    END
  END f_lk[787]
  PIN f_lk[788]
    DIRECTION INOUT ;
    USE SIGNAL ;
    PORT
      LAYER M4 ;
        RECT 2599.808 765.648 2600.000 765.672 ;
    END
  END f_lk[788]
  PIN f_lk[789]
    DIRECTION INOUT ;
    USE SIGNAL ;
    PORT
      LAYER M4 ;
        RECT 2599.808 765.840 2600.000 765.864 ;
    END
  END f_lk[789]
  PIN f_lk[790]
    DIRECTION INOUT ;
    USE SIGNAL ;
    PORT
      LAYER M4 ;
        RECT 2599.808 766.032 2600.000 766.056 ;
    END
  END f_lk[790]
  PIN f_lk[791]
    DIRECTION INOUT ;
    USE SIGNAL ;
    PORT
      LAYER M4 ;
        RECT 2599.808 766.224 2600.000 766.248 ;
    END
  END f_lk[791]
  PIN f_lk[792]
    DIRECTION INOUT ;
    USE SIGNAL ;
    PORT
      LAYER M4 ;
        RECT 2599.808 766.416 2600.000 766.440 ;
    END
  END f_lk[792]
  PIN f_lk[793]
    DIRECTION INOUT ;
    USE SIGNAL ;
    PORT
      LAYER M4 ;
        RECT 2599.808 766.608 2600.000 766.632 ;
    END
  END f_lk[793]
  PIN f_lk[794]
    DIRECTION INOUT ;
    USE SIGNAL ;
    PORT
      LAYER M4 ;
        RECT 2599.808 766.800 2600.000 766.824 ;
    END
  END f_lk[794]
  PIN f_lk[795]
    DIRECTION INOUT ;
    USE SIGNAL ;
    PORT
      LAYER M4 ;
        RECT 2599.808 766.992 2600.000 767.016 ;
    END
  END f_lk[795]
  PIN f_lk[796]
    DIRECTION INOUT ;
    USE SIGNAL ;
    PORT
      LAYER M4 ;
        RECT 2599.808 767.184 2600.000 767.208 ;
    END
  END f_lk[796]
  PIN f_lk[797]
    DIRECTION INOUT ;
    USE SIGNAL ;
    PORT
      LAYER M4 ;
        RECT 2599.808 767.376 2600.000 767.400 ;
    END
  END f_lk[797]
  PIN f_lk[798]
    DIRECTION INOUT ;
    USE SIGNAL ;
    PORT
      LAYER M4 ;
        RECT 2599.808 767.568 2600.000 767.592 ;
    END
  END f_lk[798]
  PIN f_lk[799]
    DIRECTION INOUT ;
    USE SIGNAL ;
    PORT
      LAYER M4 ;
        RECT 2599.808 767.760 2600.000 767.784 ;
    END
  END f_lk[799]
  PIN f_lk[800]
    DIRECTION INOUT ;
    USE SIGNAL ;
    PORT
      LAYER M4 ;
        RECT 2599.808 767.952 2600.000 767.976 ;
    END
  END f_lk[800]
  PIN f_lk[801]
    DIRECTION INOUT ;
    USE SIGNAL ;
    PORT
      LAYER M4 ;
        RECT 2599.808 768.144 2600.000 768.168 ;
    END
  END f_lk[801]
  PIN f_lk[802]
    DIRECTION INOUT ;
    USE SIGNAL ;
    PORT
      LAYER M4 ;
        RECT 2599.808 768.336 2600.000 768.360 ;
    END
  END f_lk[802]
  PIN f_lk[803]
    DIRECTION INOUT ;
    USE SIGNAL ;
    PORT
      LAYER M4 ;
        RECT 2599.808 768.528 2600.000 768.552 ;
    END
  END f_lk[803]
  PIN f_lk[804]
    DIRECTION INOUT ;
    USE SIGNAL ;
    PORT
      LAYER M4 ;
        RECT 2599.808 768.720 2600.000 768.744 ;
    END
  END f_lk[804]
  PIN f_lk[805]
    DIRECTION INOUT ;
    USE SIGNAL ;
    PORT
      LAYER M4 ;
        RECT 2599.808 768.912 2600.000 768.936 ;
    END
  END f_lk[805]
  PIN f_lk[806]
    DIRECTION INOUT ;
    USE SIGNAL ;
    PORT
      LAYER M4 ;
        RECT 2599.808 769.104 2600.000 769.128 ;
    END
  END f_lk[806]
  PIN f_lk[807]
    DIRECTION INOUT ;
    USE SIGNAL ;
    PORT
      LAYER M4 ;
        RECT 2599.808 769.296 2600.000 769.320 ;
    END
  END f_lk[807]
  PIN f_lk[808]
    DIRECTION INOUT ;
    USE SIGNAL ;
    PORT
      LAYER M4 ;
        RECT 2599.808 769.488 2600.000 769.512 ;
    END
  END f_lk[808]
  PIN f_lk[809]
    DIRECTION INOUT ;
    USE SIGNAL ;
    PORT
      LAYER M4 ;
        RECT 2599.808 769.680 2600.000 769.704 ;
    END
  END f_lk[809]
  PIN f_lk[810]
    DIRECTION INOUT ;
    USE SIGNAL ;
    PORT
      LAYER M4 ;
        RECT 2599.808 769.872 2600.000 769.896 ;
    END
  END f_lk[810]
  PIN f_lk[811]
    DIRECTION INOUT ;
    USE SIGNAL ;
    PORT
      LAYER M4 ;
        RECT 2599.808 770.064 2600.000 770.088 ;
    END
  END f_lk[811]
  PIN f_lk[812]
    DIRECTION INOUT ;
    USE SIGNAL ;
    PORT
      LAYER M4 ;
        RECT 2599.808 770.256 2600.000 770.280 ;
    END
  END f_lk[812]
  PIN f_lk[813]
    DIRECTION INOUT ;
    USE SIGNAL ;
    PORT
      LAYER M4 ;
        RECT 2599.808 770.448 2600.000 770.472 ;
    END
  END f_lk[813]
  PIN f_lk[814]
    DIRECTION INOUT ;
    USE SIGNAL ;
    PORT
      LAYER M4 ;
        RECT 2599.808 770.640 2600.000 770.664 ;
    END
  END f_lk[814]
  PIN f_lk[815]
    DIRECTION INOUT ;
    USE SIGNAL ;
    PORT
      LAYER M4 ;
        RECT 2599.808 770.832 2600.000 770.856 ;
    END
  END f_lk[815]
  PIN f_lk[816]
    DIRECTION INOUT ;
    USE SIGNAL ;
    PORT
      LAYER M4 ;
        RECT 2599.808 771.024 2600.000 771.048 ;
    END
  END f_lk[816]
  PIN f_lk[817]
    DIRECTION INOUT ;
    USE SIGNAL ;
    PORT
      LAYER M4 ;
        RECT 2599.808 771.216 2600.000 771.240 ;
    END
  END f_lk[817]
  PIN f_lk[818]
    DIRECTION INOUT ;
    USE SIGNAL ;
    PORT
      LAYER M4 ;
        RECT 2599.808 771.408 2600.000 771.432 ;
    END
  END f_lk[818]
  PIN f_lk[819]
    DIRECTION INOUT ;
    USE SIGNAL ;
    PORT
      LAYER M4 ;
        RECT 2599.808 771.600 2600.000 771.624 ;
    END
  END f_lk[819]
  PIN f_lk[820]
    DIRECTION INOUT ;
    USE SIGNAL ;
    PORT
      LAYER M4 ;
        RECT 2599.808 771.792 2600.000 771.816 ;
    END
  END f_lk[820]
  PIN f_lk[821]
    DIRECTION INOUT ;
    USE SIGNAL ;
    PORT
      LAYER M4 ;
        RECT 2599.808 771.984 2600.000 772.008 ;
    END
  END f_lk[821]
  PIN f_lk[822]
    DIRECTION INOUT ;
    USE SIGNAL ;
    PORT
      LAYER M4 ;
        RECT 2599.808 772.176 2600.000 772.200 ;
    END
  END f_lk[822]
  PIN f_lk[823]
    DIRECTION INOUT ;
    USE SIGNAL ;
    PORT
      LAYER M4 ;
        RECT 2599.808 772.368 2600.000 772.392 ;
    END
  END f_lk[823]
  PIN f_lk[824]
    DIRECTION INOUT ;
    USE SIGNAL ;
    PORT
      LAYER M4 ;
        RECT 2599.808 772.560 2600.000 772.584 ;
    END
  END f_lk[824]
  PIN f_lk[825]
    DIRECTION INOUT ;
    USE SIGNAL ;
    PORT
      LAYER M4 ;
        RECT 2599.808 772.752 2600.000 772.776 ;
    END
  END f_lk[825]
  PIN f_lk[826]
    DIRECTION INOUT ;
    USE SIGNAL ;
    PORT
      LAYER M4 ;
        RECT 2599.808 772.944 2600.000 772.968 ;
    END
  END f_lk[826]
  PIN f_lk[827]
    DIRECTION INOUT ;
    USE SIGNAL ;
    PORT
      LAYER M4 ;
        RECT 2599.808 773.136 2600.000 773.160 ;
    END
  END f_lk[827]
  PIN f_lk[828]
    DIRECTION INOUT ;
    USE SIGNAL ;
    PORT
      LAYER M4 ;
        RECT 2599.808 773.328 2600.000 773.352 ;
    END
  END f_lk[828]
  PIN f_lk[829]
    DIRECTION INOUT ;
    USE SIGNAL ;
    PORT
      LAYER M4 ;
        RECT 2599.808 773.520 2600.000 773.544 ;
    END
  END f_lk[829]
  PIN f_lk[830]
    DIRECTION INOUT ;
    USE SIGNAL ;
    PORT
      LAYER M4 ;
        RECT 2599.808 773.712 2600.000 773.736 ;
    END
  END f_lk[830]
  PIN f_lk[831]
    DIRECTION INOUT ;
    USE SIGNAL ;
    PORT
      LAYER M4 ;
        RECT 2599.808 773.904 2600.000 773.928 ;
    END
  END f_lk[831]
  PIN f_lk[832]
    DIRECTION INOUT ;
    USE SIGNAL ;
    PORT
      LAYER M4 ;
        RECT 2599.808 774.096 2600.000 774.120 ;
    END
  END f_lk[832]
  PIN f_lk[833]
    DIRECTION INOUT ;
    USE SIGNAL ;
    PORT
      LAYER M4 ;
        RECT 2599.808 774.288 2600.000 774.312 ;
    END
  END f_lk[833]
  PIN f_lk[834]
    DIRECTION INOUT ;
    USE SIGNAL ;
    PORT
      LAYER M4 ;
        RECT 2599.808 774.480 2600.000 774.504 ;
    END
  END f_lk[834]
  PIN f_lk[835]
    DIRECTION INOUT ;
    USE SIGNAL ;
    PORT
      LAYER M4 ;
        RECT 2599.808 774.672 2600.000 774.696 ;
    END
  END f_lk[835]
  PIN f_lk[836]
    DIRECTION INOUT ;
    USE SIGNAL ;
    PORT
      LAYER M4 ;
        RECT 2599.808 774.864 2600.000 774.888 ;
    END
  END f_lk[836]
  PIN f_lk[837]
    DIRECTION INOUT ;
    USE SIGNAL ;
    PORT
      LAYER M4 ;
        RECT 2599.808 775.056 2600.000 775.080 ;
    END
  END f_lk[837]
  PIN f_lk[838]
    DIRECTION INOUT ;
    USE SIGNAL ;
    PORT
      LAYER M4 ;
        RECT 2599.808 775.248 2600.000 775.272 ;
    END
  END f_lk[838]
  PIN f_lk[839]
    DIRECTION INOUT ;
    USE SIGNAL ;
    PORT
      LAYER M4 ;
        RECT 2599.808 775.440 2600.000 775.464 ;
    END
  END f_lk[839]
  PIN f_lk[840]
    DIRECTION INOUT ;
    USE SIGNAL ;
    PORT
      LAYER M4 ;
        RECT 2599.808 775.632 2600.000 775.656 ;
    END
  END f_lk[840]
  PIN f_lk[841]
    DIRECTION INOUT ;
    USE SIGNAL ;
    PORT
      LAYER M4 ;
        RECT 2599.808 775.824 2600.000 775.848 ;
    END
  END f_lk[841]
  PIN f_lk[842]
    DIRECTION INOUT ;
    USE SIGNAL ;
    PORT
      LAYER M4 ;
        RECT 2599.808 776.016 2600.000 776.040 ;
    END
  END f_lk[842]
  PIN f_lk[843]
    DIRECTION INOUT ;
    USE SIGNAL ;
    PORT
      LAYER M4 ;
        RECT 2599.808 776.208 2600.000 776.232 ;
    END
  END f_lk[843]
  PIN f_lk[844]
    DIRECTION INOUT ;
    USE SIGNAL ;
    PORT
      LAYER M4 ;
        RECT 2599.808 776.400 2600.000 776.424 ;
    END
  END f_lk[844]
  PIN f_lk[845]
    DIRECTION INOUT ;
    USE SIGNAL ;
    PORT
      LAYER M4 ;
        RECT 2599.808 776.592 2600.000 776.616 ;
    END
  END f_lk[845]
  PIN f_lk[846]
    DIRECTION INOUT ;
    USE SIGNAL ;
    PORT
      LAYER M4 ;
        RECT 2599.808 776.784 2600.000 776.808 ;
    END
  END f_lk[846]
  PIN f_lk[847]
    DIRECTION INOUT ;
    USE SIGNAL ;
    PORT
      LAYER M4 ;
        RECT 2599.808 776.976 2600.000 777.000 ;
    END
  END f_lk[847]
  PIN f_lk[848]
    DIRECTION INOUT ;
    USE SIGNAL ;
    PORT
      LAYER M4 ;
        RECT 2599.808 777.168 2600.000 777.192 ;
    END
  END f_lk[848]
  PIN f_lk[849]
    DIRECTION INOUT ;
    USE SIGNAL ;
    PORT
      LAYER M4 ;
        RECT 2599.808 777.360 2600.000 777.384 ;
    END
  END f_lk[849]
  PIN f_lk[850]
    DIRECTION INOUT ;
    USE SIGNAL ;
    PORT
      LAYER M4 ;
        RECT 2599.808 777.552 2600.000 777.576 ;
    END
  END f_lk[850]
  PIN f_lk[851]
    DIRECTION INOUT ;
    USE SIGNAL ;
    PORT
      LAYER M4 ;
        RECT 2599.808 777.744 2600.000 777.768 ;
    END
  END f_lk[851]
  PIN f_lk[852]
    DIRECTION INOUT ;
    USE SIGNAL ;
    PORT
      LAYER M4 ;
        RECT 2599.808 777.936 2600.000 777.960 ;
    END
  END f_lk[852]
  PIN f_lk[853]
    DIRECTION INOUT ;
    USE SIGNAL ;
    PORT
      LAYER M4 ;
        RECT 2599.808 778.128 2600.000 778.152 ;
    END
  END f_lk[853]
  PIN f_lk[854]
    DIRECTION INOUT ;
    USE SIGNAL ;
    PORT
      LAYER M4 ;
        RECT 2599.808 778.320 2600.000 778.344 ;
    END
  END f_lk[854]
  PIN f_lk[855]
    DIRECTION INOUT ;
    USE SIGNAL ;
    PORT
      LAYER M4 ;
        RECT 2599.808 778.512 2600.000 778.536 ;
    END
  END f_lk[855]
  PIN f_lk[856]
    DIRECTION INOUT ;
    USE SIGNAL ;
    PORT
      LAYER M4 ;
        RECT 2599.808 778.704 2600.000 778.728 ;
    END
  END f_lk[856]
  PIN f_lk[857]
    DIRECTION INOUT ;
    USE SIGNAL ;
    PORT
      LAYER M4 ;
        RECT 2599.808 778.896 2600.000 778.920 ;
    END
  END f_lk[857]
  PIN f_lk[858]
    DIRECTION INOUT ;
    USE SIGNAL ;
    PORT
      LAYER M4 ;
        RECT 2599.808 779.088 2600.000 779.112 ;
    END
  END f_lk[858]
  PIN f_lk[859]
    DIRECTION INOUT ;
    USE SIGNAL ;
    PORT
      LAYER M4 ;
        RECT 2599.808 779.280 2600.000 779.304 ;
    END
  END f_lk[859]
  PIN f_lk[860]
    DIRECTION INOUT ;
    USE SIGNAL ;
    PORT
      LAYER M4 ;
        RECT 2599.808 779.472 2600.000 779.496 ;
    END
  END f_lk[860]
  PIN f_lk[861]
    DIRECTION INOUT ;
    USE SIGNAL ;
    PORT
      LAYER M4 ;
        RECT 2599.808 779.664 2600.000 779.688 ;
    END
  END f_lk[861]
  PIN f_lk[862]
    DIRECTION INOUT ;
    USE SIGNAL ;
    PORT
      LAYER M4 ;
        RECT 2599.808 779.856 2600.000 779.880 ;
    END
  END f_lk[862]
  PIN f_lk[863]
    DIRECTION INOUT ;
    USE SIGNAL ;
    PORT
      LAYER M4 ;
        RECT 2599.808 780.048 2600.000 780.072 ;
    END
  END f_lk[863]
  PIN f_lk[864]
    DIRECTION INOUT ;
    USE SIGNAL ;
    PORT
      LAYER M4 ;
        RECT 2599.808 780.240 2600.000 780.264 ;
    END
  END f_lk[864]
  PIN f_lk[865]
    DIRECTION INOUT ;
    USE SIGNAL ;
    PORT
      LAYER M4 ;
        RECT 2599.808 780.432 2600.000 780.456 ;
    END
  END f_lk[865]
  PIN f_lk[866]
    DIRECTION INOUT ;
    USE SIGNAL ;
    PORT
      LAYER M4 ;
        RECT 2599.808 780.624 2600.000 780.648 ;
    END
  END f_lk[866]
  PIN f_lk[867]
    DIRECTION INOUT ;
    USE SIGNAL ;
    PORT
      LAYER M4 ;
        RECT 2599.808 780.816 2600.000 780.840 ;
    END
  END f_lk[867]
  PIN f_lk[868]
    DIRECTION INOUT ;
    USE SIGNAL ;
    PORT
      LAYER M4 ;
        RECT 2599.808 781.008 2600.000 781.032 ;
    END
  END f_lk[868]
  PIN f_lk[869]
    DIRECTION INOUT ;
    USE SIGNAL ;
    PORT
      LAYER M4 ;
        RECT 2599.808 781.200 2600.000 781.224 ;
    END
  END f_lk[869]
  PIN f_lk[870]
    DIRECTION INOUT ;
    USE SIGNAL ;
    PORT
      LAYER M4 ;
        RECT 2599.808 781.392 2600.000 781.416 ;
    END
  END f_lk[870]
  PIN f_lk[871]
    DIRECTION INOUT ;
    USE SIGNAL ;
    PORT
      LAYER M4 ;
        RECT 2599.808 781.584 2600.000 781.608 ;
    END
  END f_lk[871]
  PIN f_lk[872]
    DIRECTION INOUT ;
    USE SIGNAL ;
    PORT
      LAYER M4 ;
        RECT 2599.808 781.776 2600.000 781.800 ;
    END
  END f_lk[872]
  PIN f_lk[873]
    DIRECTION INOUT ;
    USE SIGNAL ;
    PORT
      LAYER M4 ;
        RECT 2599.808 781.968 2600.000 781.992 ;
    END
  END f_lk[873]
  PIN f_lk[874]
    DIRECTION INOUT ;
    USE SIGNAL ;
    PORT
      LAYER M4 ;
        RECT 2599.808 782.160 2600.000 782.184 ;
    END
  END f_lk[874]
  PIN f_lk[875]
    DIRECTION INOUT ;
    USE SIGNAL ;
    PORT
      LAYER M4 ;
        RECT 2599.808 782.352 2600.000 782.376 ;
    END
  END f_lk[875]
  PIN f_lk[876]
    DIRECTION INOUT ;
    USE SIGNAL ;
    PORT
      LAYER M4 ;
        RECT 2599.808 782.544 2600.000 782.568 ;
    END
  END f_lk[876]
  PIN f_lk[877]
    DIRECTION INOUT ;
    USE SIGNAL ;
    PORT
      LAYER M4 ;
        RECT 2599.808 782.736 2600.000 782.760 ;
    END
  END f_lk[877]
  PIN f_lk[878]
    DIRECTION INOUT ;
    USE SIGNAL ;
    PORT
      LAYER M4 ;
        RECT 2599.808 782.928 2600.000 782.952 ;
    END
  END f_lk[878]
  PIN f_lk[879]
    DIRECTION INOUT ;
    USE SIGNAL ;
    PORT
      LAYER M4 ;
        RECT 2599.808 783.120 2600.000 783.144 ;
    END
  END f_lk[879]
  PIN f_lk[880]
    DIRECTION INOUT ;
    USE SIGNAL ;
    PORT
      LAYER M4 ;
        RECT 2599.808 783.312 2600.000 783.336 ;
    END
  END f_lk[880]
  PIN f_lk[881]
    DIRECTION INOUT ;
    USE SIGNAL ;
    PORT
      LAYER M4 ;
        RECT 2599.808 783.504 2600.000 783.528 ;
    END
  END f_lk[881]
  PIN f_lk[882]
    DIRECTION INOUT ;
    USE SIGNAL ;
    PORT
      LAYER M4 ;
        RECT 2599.808 783.696 2600.000 783.720 ;
    END
  END f_lk[882]
  PIN f_lk[883]
    DIRECTION INOUT ;
    USE SIGNAL ;
    PORT
      LAYER M4 ;
        RECT 2599.808 783.888 2600.000 783.912 ;
    END
  END f_lk[883]
  PIN f_lk[884]
    DIRECTION INOUT ;
    USE SIGNAL ;
    PORT
      LAYER M4 ;
        RECT 2599.808 784.080 2600.000 784.104 ;
    END
  END f_lk[884]
  PIN f_lk[885]
    DIRECTION INOUT ;
    USE SIGNAL ;
    PORT
      LAYER M4 ;
        RECT 2599.808 784.272 2600.000 784.296 ;
    END
  END f_lk[885]
  PIN f_lk[886]
    DIRECTION INOUT ;
    USE SIGNAL ;
    PORT
      LAYER M4 ;
        RECT 2599.808 784.464 2600.000 784.488 ;
    END
  END f_lk[886]
  PIN f_lk[887]
    DIRECTION INOUT ;
    USE SIGNAL ;
    PORT
      LAYER M4 ;
        RECT 2599.808 784.656 2600.000 784.680 ;
    END
  END f_lk[887]
  PIN f_lk[888]
    DIRECTION INOUT ;
    USE SIGNAL ;
    PORT
      LAYER M4 ;
        RECT 2599.808 784.848 2600.000 784.872 ;
    END
  END f_lk[888]
  PIN f_lk[889]
    DIRECTION INOUT ;
    USE SIGNAL ;
    PORT
      LAYER M4 ;
        RECT 2599.808 785.040 2600.000 785.064 ;
    END
  END f_lk[889]
  PIN f_lk[890]
    DIRECTION INOUT ;
    USE SIGNAL ;
    PORT
      LAYER M4 ;
        RECT 2599.808 785.232 2600.000 785.256 ;
    END
  END f_lk[890]
  PIN f_lk[891]
    DIRECTION INOUT ;
    USE SIGNAL ;
    PORT
      LAYER M4 ;
        RECT 2599.808 785.424 2600.000 785.448 ;
    END
  END f_lk[891]
  PIN f_lk[892]
    DIRECTION INOUT ;
    USE SIGNAL ;
    PORT
      LAYER M4 ;
        RECT 2599.808 785.616 2600.000 785.640 ;
    END
  END f_lk[892]
  PIN f_lk[893]
    DIRECTION INOUT ;
    USE SIGNAL ;
    PORT
      LAYER M4 ;
        RECT 2599.808 785.808 2600.000 785.832 ;
    END
  END f_lk[893]
  PIN f_lk[894]
    DIRECTION INOUT ;
    USE SIGNAL ;
    PORT
      LAYER M4 ;
        RECT 2599.808 786.000 2600.000 786.024 ;
    END
  END f_lk[894]
  PIN f_lk[895]
    DIRECTION INOUT ;
    USE SIGNAL ;
    PORT
      LAYER M4 ;
        RECT 2599.808 786.192 2600.000 786.216 ;
    END
  END f_lk[895]
  PIN f_lk[896]
    DIRECTION INOUT ;
    USE SIGNAL ;
    PORT
      LAYER M4 ;
        RECT 2599.808 786.384 2600.000 786.408 ;
    END
  END f_lk[896]
  PIN f_lk[897]
    DIRECTION INOUT ;
    USE SIGNAL ;
    PORT
      LAYER M4 ;
        RECT 2599.808 786.576 2600.000 786.600 ;
    END
  END f_lk[897]
  PIN f_lk[898]
    DIRECTION INOUT ;
    USE SIGNAL ;
    PORT
      LAYER M4 ;
        RECT 2599.808 786.768 2600.000 786.792 ;
    END
  END f_lk[898]
  PIN f_lk[899]
    DIRECTION INOUT ;
    USE SIGNAL ;
    PORT
      LAYER M4 ;
        RECT 2599.808 786.960 2600.000 786.984 ;
    END
  END f_lk[899]
  PIN f_lk[900]
    DIRECTION INOUT ;
    USE SIGNAL ;
    PORT
      LAYER M4 ;
        RECT 2599.808 787.152 2600.000 787.176 ;
    END
  END f_lk[900]
  PIN f_lk[901]
    DIRECTION INOUT ;
    USE SIGNAL ;
    PORT
      LAYER M4 ;
        RECT 2599.808 787.344 2600.000 787.368 ;
    END
  END f_lk[901]
  PIN f_lk[902]
    DIRECTION INOUT ;
    USE SIGNAL ;
    PORT
      LAYER M4 ;
        RECT 2599.808 787.536 2600.000 787.560 ;
    END
  END f_lk[902]
  PIN f_lk[903]
    DIRECTION INOUT ;
    USE SIGNAL ;
    PORT
      LAYER M4 ;
        RECT 2599.808 787.728 2600.000 787.752 ;
    END
  END f_lk[903]
  PIN f_lk[904]
    DIRECTION INOUT ;
    USE SIGNAL ;
    PORT
      LAYER M4 ;
        RECT 2599.808 787.920 2600.000 787.944 ;
    END
  END f_lk[904]
  PIN f_lk[905]
    DIRECTION INOUT ;
    USE SIGNAL ;
    PORT
      LAYER M4 ;
        RECT 2599.808 788.112 2600.000 788.136 ;
    END
  END f_lk[905]
  PIN f_lk[906]
    DIRECTION INOUT ;
    USE SIGNAL ;
    PORT
      LAYER M4 ;
        RECT 2599.808 788.304 2600.000 788.328 ;
    END
  END f_lk[906]
  PIN f_lk[907]
    DIRECTION INOUT ;
    USE SIGNAL ;
    PORT
      LAYER M4 ;
        RECT 2599.808 788.496 2600.000 788.520 ;
    END
  END f_lk[907]
  PIN f_lk[908]
    DIRECTION INOUT ;
    USE SIGNAL ;
    PORT
      LAYER M4 ;
        RECT 2599.808 788.688 2600.000 788.712 ;
    END
  END f_lk[908]
  PIN f_lk[909]
    DIRECTION INOUT ;
    USE SIGNAL ;
    PORT
      LAYER M4 ;
        RECT 2599.808 788.880 2600.000 788.904 ;
    END
  END f_lk[909]
  PIN f_lk[910]
    DIRECTION INOUT ;
    USE SIGNAL ;
    PORT
      LAYER M4 ;
        RECT 2599.808 789.072 2600.000 789.096 ;
    END
  END f_lk[910]
  PIN f_lk[911]
    DIRECTION INOUT ;
    USE SIGNAL ;
    PORT
      LAYER M4 ;
        RECT 2599.808 789.264 2600.000 789.288 ;
    END
  END f_lk[911]
  PIN f_lk[912]
    DIRECTION INOUT ;
    USE SIGNAL ;
    PORT
      LAYER M4 ;
        RECT 2599.808 789.456 2600.000 789.480 ;
    END
  END f_lk[912]
  PIN f_lk[913]
    DIRECTION INOUT ;
    USE SIGNAL ;
    PORT
      LAYER M4 ;
        RECT 2599.808 789.648 2600.000 789.672 ;
    END
  END f_lk[913]
  PIN f_lk[914]
    DIRECTION INOUT ;
    USE SIGNAL ;
    PORT
      LAYER M4 ;
        RECT 2599.808 789.840 2600.000 789.864 ;
    END
  END f_lk[914]
  PIN f_lk[915]
    DIRECTION INOUT ;
    USE SIGNAL ;
    PORT
      LAYER M4 ;
        RECT 2599.808 790.032 2600.000 790.056 ;
    END
  END f_lk[915]
  PIN f_lk[916]
    DIRECTION INOUT ;
    USE SIGNAL ;
    PORT
      LAYER M4 ;
        RECT 2599.808 790.224 2600.000 790.248 ;
    END
  END f_lk[916]
  PIN f_lk[917]
    DIRECTION INOUT ;
    USE SIGNAL ;
    PORT
      LAYER M4 ;
        RECT 2599.808 790.416 2600.000 790.440 ;
    END
  END f_lk[917]
  PIN f_lk[918]
    DIRECTION INOUT ;
    USE SIGNAL ;
    PORT
      LAYER M4 ;
        RECT 2599.808 790.608 2600.000 790.632 ;
    END
  END f_lk[918]
  PIN f_lk[919]
    DIRECTION INOUT ;
    USE SIGNAL ;
    PORT
      LAYER M4 ;
        RECT 2599.808 790.800 2600.000 790.824 ;
    END
  END f_lk[919]
  PIN f_lk[920]
    DIRECTION INOUT ;
    USE SIGNAL ;
    PORT
      LAYER M4 ;
        RECT 2599.808 790.992 2600.000 791.016 ;
    END
  END f_lk[920]
  PIN f_lk[921]
    DIRECTION INOUT ;
    USE SIGNAL ;
    PORT
      LAYER M4 ;
        RECT 2599.808 791.184 2600.000 791.208 ;
    END
  END f_lk[921]
  PIN f_lk[922]
    DIRECTION INOUT ;
    USE SIGNAL ;
    PORT
      LAYER M4 ;
        RECT 2599.808 791.376 2600.000 791.400 ;
    END
  END f_lk[922]
  PIN f_lk[923]
    DIRECTION INOUT ;
    USE SIGNAL ;
    PORT
      LAYER M4 ;
        RECT 2599.808 791.568 2600.000 791.592 ;
    END
  END f_lk[923]
  PIN f_lk[924]
    DIRECTION INOUT ;
    USE SIGNAL ;
    PORT
      LAYER M4 ;
        RECT 2599.808 791.760 2600.000 791.784 ;
    END
  END f_lk[924]
  PIN f_lk[925]
    DIRECTION INOUT ;
    USE SIGNAL ;
    PORT
      LAYER M4 ;
        RECT 2599.808 791.952 2600.000 791.976 ;
    END
  END f_lk[925]
  PIN f_lk[926]
    DIRECTION INOUT ;
    USE SIGNAL ;
    PORT
      LAYER M4 ;
        RECT 2599.808 792.144 2600.000 792.168 ;
    END
  END f_lk[926]
  PIN f_lk[927]
    DIRECTION INOUT ;
    USE SIGNAL ;
    PORT
      LAYER M4 ;
        RECT 2599.808 792.336 2600.000 792.360 ;
    END
  END f_lk[927]
  PIN f_lk[928]
    DIRECTION INOUT ;
    USE SIGNAL ;
    PORT
      LAYER M4 ;
        RECT 2599.808 792.528 2600.000 792.552 ;
    END
  END f_lk[928]
  PIN f_lk[929]
    DIRECTION INOUT ;
    USE SIGNAL ;
    PORT
      LAYER M4 ;
        RECT 2599.808 792.720 2600.000 792.744 ;
    END
  END f_lk[929]
  PIN f_lk[930]
    DIRECTION INOUT ;
    USE SIGNAL ;
    PORT
      LAYER M4 ;
        RECT 2599.808 792.912 2600.000 792.936 ;
    END
  END f_lk[930]
  PIN f_lk[931]
    DIRECTION INOUT ;
    USE SIGNAL ;
    PORT
      LAYER M4 ;
        RECT 2599.808 793.104 2600.000 793.128 ;
    END
  END f_lk[931]
  PIN f_lk[932]
    DIRECTION INOUT ;
    USE SIGNAL ;
    PORT
      LAYER M4 ;
        RECT 2599.808 793.296 2600.000 793.320 ;
    END
  END f_lk[932]
  PIN f_lk[933]
    DIRECTION INOUT ;
    USE SIGNAL ;
    PORT
      LAYER M4 ;
        RECT 2599.808 793.488 2600.000 793.512 ;
    END
  END f_lk[933]
  PIN f_lk[934]
    DIRECTION INOUT ;
    USE SIGNAL ;
    PORT
      LAYER M4 ;
        RECT 2599.808 793.680 2600.000 793.704 ;
    END
  END f_lk[934]
  PIN f_lk[935]
    DIRECTION INOUT ;
    USE SIGNAL ;
    PORT
      LAYER M4 ;
        RECT 2599.808 793.872 2600.000 793.896 ;
    END
  END f_lk[935]
  PIN f_lk[936]
    DIRECTION INOUT ;
    USE SIGNAL ;
    PORT
      LAYER M4 ;
        RECT 2599.808 794.064 2600.000 794.088 ;
    END
  END f_lk[936]
  PIN f_lk[937]
    DIRECTION INOUT ;
    USE SIGNAL ;
    PORT
      LAYER M4 ;
        RECT 2599.808 794.256 2600.000 794.280 ;
    END
  END f_lk[937]
  PIN f_lk[938]
    DIRECTION INOUT ;
    USE SIGNAL ;
    PORT
      LAYER M4 ;
        RECT 2599.808 794.448 2600.000 794.472 ;
    END
  END f_lk[938]
  PIN f_lk[939]
    DIRECTION INOUT ;
    USE SIGNAL ;
    PORT
      LAYER M4 ;
        RECT 2599.808 794.640 2600.000 794.664 ;
    END
  END f_lk[939]
  PIN f_lk[940]
    DIRECTION INOUT ;
    USE SIGNAL ;
    PORT
      LAYER M4 ;
        RECT 2599.808 794.832 2600.000 794.856 ;
    END
  END f_lk[940]
  PIN f_lk[941]
    DIRECTION INOUT ;
    USE SIGNAL ;
    PORT
      LAYER M4 ;
        RECT 2599.808 795.024 2600.000 795.048 ;
    END
  END f_lk[941]
  PIN f_lk[942]
    DIRECTION INOUT ;
    USE SIGNAL ;
    PORT
      LAYER M4 ;
        RECT 2599.808 795.216 2600.000 795.240 ;
    END
  END f_lk[942]
  PIN f_lk[943]
    DIRECTION INOUT ;
    USE SIGNAL ;
    PORT
      LAYER M4 ;
        RECT 2599.808 795.408 2600.000 795.432 ;
    END
  END f_lk[943]
  PIN f_lk[944]
    DIRECTION INOUT ;
    USE SIGNAL ;
    PORT
      LAYER M4 ;
        RECT 2599.808 795.600 2600.000 795.624 ;
    END
  END f_lk[944]
  PIN f_lk[945]
    DIRECTION INOUT ;
    USE SIGNAL ;
    PORT
      LAYER M4 ;
        RECT 2599.808 795.792 2600.000 795.816 ;
    END
  END f_lk[945]
  PIN f_lk[946]
    DIRECTION INOUT ;
    USE SIGNAL ;
    PORT
      LAYER M4 ;
        RECT 2599.808 795.984 2600.000 796.008 ;
    END
  END f_lk[946]
  PIN f_lk[947]
    DIRECTION INOUT ;
    USE SIGNAL ;
    PORT
      LAYER M4 ;
        RECT 2599.808 796.176 2600.000 796.200 ;
    END
  END f_lk[947]
  PIN f_lk[948]
    DIRECTION INOUT ;
    USE SIGNAL ;
    PORT
      LAYER M4 ;
        RECT 2599.808 796.368 2600.000 796.392 ;
    END
  END f_lk[948]
  PIN f_lk[949]
    DIRECTION INOUT ;
    USE SIGNAL ;
    PORT
      LAYER M4 ;
        RECT 2599.808 796.560 2600.000 796.584 ;
    END
  END f_lk[949]
  PIN f_lk[950]
    DIRECTION INOUT ;
    USE SIGNAL ;
    PORT
      LAYER M4 ;
        RECT 2599.808 796.752 2600.000 796.776 ;
    END
  END f_lk[950]
  PIN f_lk[951]
    DIRECTION INOUT ;
    USE SIGNAL ;
    PORT
      LAYER M4 ;
        RECT 2599.808 796.944 2600.000 796.968 ;
    END
  END f_lk[951]
  PIN f_lk[952]
    DIRECTION INOUT ;
    USE SIGNAL ;
    PORT
      LAYER M4 ;
        RECT 2599.808 797.136 2600.000 797.160 ;
    END
  END f_lk[952]
  PIN f_lk[953]
    DIRECTION INOUT ;
    USE SIGNAL ;
    PORT
      LAYER M4 ;
        RECT 2599.808 797.328 2600.000 797.352 ;
    END
  END f_lk[953]
  PIN f_lk[954]
    DIRECTION INOUT ;
    USE SIGNAL ;
    PORT
      LAYER M4 ;
        RECT 2599.808 797.520 2600.000 797.544 ;
    END
  END f_lk[954]
  PIN f_lk[955]
    DIRECTION INOUT ;
    USE SIGNAL ;
    PORT
      LAYER M4 ;
        RECT 2599.808 797.712 2600.000 797.736 ;
    END
  END f_lk[955]
  PIN f_lk[956]
    DIRECTION INOUT ;
    USE SIGNAL ;
    PORT
      LAYER M4 ;
        RECT 2599.808 797.904 2600.000 797.928 ;
    END
  END f_lk[956]
  PIN f_lk[957]
    DIRECTION INOUT ;
    USE SIGNAL ;
    PORT
      LAYER M4 ;
        RECT 2599.808 798.096 2600.000 798.120 ;
    END
  END f_lk[957]
  PIN f_lk[958]
    DIRECTION INOUT ;
    USE SIGNAL ;
    PORT
      LAYER M4 ;
        RECT 2599.808 798.288 2600.000 798.312 ;
    END
  END f_lk[958]
  PIN f_lk[959]
    DIRECTION INOUT ;
    USE SIGNAL ;
    PORT
      LAYER M4 ;
        RECT 2599.808 798.480 2600.000 798.504 ;
    END
  END f_lk[959]
  PIN f_lk[960]
    DIRECTION INOUT ;
    USE SIGNAL ;
    PORT
      LAYER M4 ;
        RECT 2599.808 798.672 2600.000 798.696 ;
    END
  END f_lk[960]
  PIN f_lk[961]
    DIRECTION INOUT ;
    USE SIGNAL ;
    PORT
      LAYER M4 ;
        RECT 2599.808 798.864 2600.000 798.888 ;
    END
  END f_lk[961]
  PIN f_lk[962]
    DIRECTION INOUT ;
    USE SIGNAL ;
    PORT
      LAYER M4 ;
        RECT 2599.808 799.056 2600.000 799.080 ;
    END
  END f_lk[962]
  PIN f_lk[963]
    DIRECTION INOUT ;
    USE SIGNAL ;
    PORT
      LAYER M4 ;
        RECT 2599.808 799.248 2600.000 799.272 ;
    END
  END f_lk[963]
  PIN f_lk[964]
    DIRECTION INOUT ;
    USE SIGNAL ;
    PORT
      LAYER M4 ;
        RECT 2599.808 799.440 2600.000 799.464 ;
    END
  END f_lk[964]
  PIN f_lk[965]
    DIRECTION INOUT ;
    USE SIGNAL ;
    PORT
      LAYER M4 ;
        RECT 2599.808 799.632 2600.000 799.656 ;
    END
  END f_lk[965]
  PIN f_lk[966]
    DIRECTION INOUT ;
    USE SIGNAL ;
    PORT
      LAYER M4 ;
        RECT 2599.808 799.824 2600.000 799.848 ;
    END
  END f_lk[966]
  PIN f_lk[967]
    DIRECTION INOUT ;
    USE SIGNAL ;
    PORT
      LAYER M4 ;
        RECT 2599.808 800.016 2600.000 800.040 ;
    END
  END f_lk[967]
  PIN f_lk[968]
    DIRECTION INOUT ;
    USE SIGNAL ;
    PORT
      LAYER M4 ;
        RECT 2599.808 800.208 2600.000 800.232 ;
    END
  END f_lk[968]
  PIN f_lk[969]
    DIRECTION INOUT ;
    USE SIGNAL ;
    PORT
      LAYER M4 ;
        RECT 2599.808 800.400 2600.000 800.424 ;
    END
  END f_lk[969]
  PIN f_lk[970]
    DIRECTION INOUT ;
    USE SIGNAL ;
    PORT
      LAYER M4 ;
        RECT 2599.808 800.592 2600.000 800.616 ;
    END
  END f_lk[970]
  PIN f_lk[971]
    DIRECTION INOUT ;
    USE SIGNAL ;
    PORT
      LAYER M4 ;
        RECT 2599.808 800.784 2600.000 800.808 ;
    END
  END f_lk[971]
  PIN f_lk[972]
    DIRECTION INOUT ;
    USE SIGNAL ;
    PORT
      LAYER M4 ;
        RECT 2599.808 800.976 2600.000 801.000 ;
    END
  END f_lk[972]
  PIN f_lk[973]
    DIRECTION INOUT ;
    USE SIGNAL ;
    PORT
      LAYER M4 ;
        RECT 2599.808 801.168 2600.000 801.192 ;
    END
  END f_lk[973]
  PIN f_lk[974]
    DIRECTION INOUT ;
    USE SIGNAL ;
    PORT
      LAYER M4 ;
        RECT 2599.808 801.360 2600.000 801.384 ;
    END
  END f_lk[974]
  PIN f_lk[975]
    DIRECTION INOUT ;
    USE SIGNAL ;
    PORT
      LAYER M4 ;
        RECT 2599.808 801.552 2600.000 801.576 ;
    END
  END f_lk[975]
  PIN f_lk[976]
    DIRECTION INOUT ;
    USE SIGNAL ;
    PORT
      LAYER M4 ;
        RECT 2599.808 801.744 2600.000 801.768 ;
    END
  END f_lk[976]
  PIN f_lk[977]
    DIRECTION INOUT ;
    USE SIGNAL ;
    PORT
      LAYER M4 ;
        RECT 2599.808 801.936 2600.000 801.960 ;
    END
  END f_lk[977]
  PIN f_lk[978]
    DIRECTION INOUT ;
    USE SIGNAL ;
    PORT
      LAYER M4 ;
        RECT 2599.808 802.128 2600.000 802.152 ;
    END
  END f_lk[978]
  PIN f_lk[979]
    DIRECTION INOUT ;
    USE SIGNAL ;
    PORT
      LAYER M4 ;
        RECT 2599.808 802.320 2600.000 802.344 ;
    END
  END f_lk[979]
  PIN f_lk[980]
    DIRECTION INOUT ;
    USE SIGNAL ;
    PORT
      LAYER M4 ;
        RECT 2599.808 802.512 2600.000 802.536 ;
    END
  END f_lk[980]
  PIN f_lk[981]
    DIRECTION INOUT ;
    USE SIGNAL ;
    PORT
      LAYER M4 ;
        RECT 2599.808 802.704 2600.000 802.728 ;
    END
  END f_lk[981]
  PIN f_lk[982]
    DIRECTION INOUT ;
    USE SIGNAL ;
    PORT
      LAYER M4 ;
        RECT 2599.808 802.896 2600.000 802.920 ;
    END
  END f_lk[982]
  PIN f_lk[983]
    DIRECTION INOUT ;
    USE SIGNAL ;
    PORT
      LAYER M4 ;
        RECT 2599.808 803.088 2600.000 803.112 ;
    END
  END f_lk[983]
  PIN f_lk[984]
    DIRECTION INOUT ;
    USE SIGNAL ;
    PORT
      LAYER M4 ;
        RECT 2599.808 803.280 2600.000 803.304 ;
    END
  END f_lk[984]
  PIN f_lk[985]
    DIRECTION INOUT ;
    USE SIGNAL ;
    PORT
      LAYER M4 ;
        RECT 2599.808 803.472 2600.000 803.496 ;
    END
  END f_lk[985]
  PIN f_lk[986]
    DIRECTION INOUT ;
    USE SIGNAL ;
    PORT
      LAYER M4 ;
        RECT 2599.808 803.664 2600.000 803.688 ;
    END
  END f_lk[986]
  PIN f_lk[987]
    DIRECTION INOUT ;
    USE SIGNAL ;
    PORT
      LAYER M4 ;
        RECT 2599.808 803.856 2600.000 803.880 ;
    END
  END f_lk[987]
  PIN f_lk[988]
    DIRECTION INOUT ;
    USE SIGNAL ;
    PORT
      LAYER M4 ;
        RECT 2599.808 804.048 2600.000 804.072 ;
    END
  END f_lk[988]
  PIN f_lk[989]
    DIRECTION INOUT ;
    USE SIGNAL ;
    PORT
      LAYER M4 ;
        RECT 2599.808 804.240 2600.000 804.264 ;
    END
  END f_lk[989]
  PIN f_lk[990]
    DIRECTION INOUT ;
    USE SIGNAL ;
    PORT
      LAYER M4 ;
        RECT 2599.808 804.432 2600.000 804.456 ;
    END
  END f_lk[990]
  PIN f_lk[991]
    DIRECTION INOUT ;
    USE SIGNAL ;
    PORT
      LAYER M4 ;
        RECT 2599.808 804.624 2600.000 804.648 ;
    END
  END f_lk[991]
  PIN f_lk[992]
    DIRECTION INOUT ;
    USE SIGNAL ;
    PORT
      LAYER M4 ;
        RECT 2599.808 804.816 2600.000 804.840 ;
    END
  END f_lk[992]
  PIN f_lk[993]
    DIRECTION INOUT ;
    USE SIGNAL ;
    PORT
      LAYER M4 ;
        RECT 2599.808 805.008 2600.000 805.032 ;
    END
  END f_lk[993]
  PIN f_lk[994]
    DIRECTION INOUT ;
    USE SIGNAL ;
    PORT
      LAYER M4 ;
        RECT 2599.808 805.200 2600.000 805.224 ;
    END
  END f_lk[994]
  PIN f_lk[995]
    DIRECTION INOUT ;
    USE SIGNAL ;
    PORT
      LAYER M4 ;
        RECT 2599.808 805.392 2600.000 805.416 ;
    END
  END f_lk[995]
  PIN f_lk[996]
    DIRECTION INOUT ;
    USE SIGNAL ;
    PORT
      LAYER M4 ;
        RECT 2599.808 805.584 2600.000 805.608 ;
    END
  END f_lk[996]
  PIN f_lk[997]
    DIRECTION INOUT ;
    USE SIGNAL ;
    PORT
      LAYER M4 ;
        RECT 2599.808 805.776 2600.000 805.800 ;
    END
  END f_lk[997]
  PIN f_lk[998]
    DIRECTION INOUT ;
    USE SIGNAL ;
    PORT
      LAYER M4 ;
        RECT 2599.808 805.968 2600.000 805.992 ;
    END
  END f_lk[998]
  PIN f_lk[999]
    DIRECTION INOUT ;
    USE SIGNAL ;
    PORT
      LAYER M4 ;
        RECT 2599.808 806.160 2600.000 806.184 ;
    END
  END f_lk[999]
  PIN f_lk[1000]
    DIRECTION INOUT ;
    USE SIGNAL ;
    PORT
      LAYER M4 ;
        RECT 2599.808 806.352 2600.000 806.376 ;
    END
  END f_lk[1000]
  PIN f_lk[1001]
    DIRECTION INOUT ;
    USE SIGNAL ;
    PORT
      LAYER M4 ;
        RECT 2599.808 806.544 2600.000 806.568 ;
    END
  END f_lk[1001]
  PIN f_lk[1002]
    DIRECTION INOUT ;
    USE SIGNAL ;
    PORT
      LAYER M4 ;
        RECT 2599.808 806.736 2600.000 806.760 ;
    END
  END f_lk[1002]
  PIN f_lk[1003]
    DIRECTION INOUT ;
    USE SIGNAL ;
    PORT
      LAYER M4 ;
        RECT 2599.808 806.928 2600.000 806.952 ;
    END
  END f_lk[1003]
  PIN f_lk[1004]
    DIRECTION INOUT ;
    USE SIGNAL ;
    PORT
      LAYER M4 ;
        RECT 2599.808 807.120 2600.000 807.144 ;
    END
  END f_lk[1004]
  PIN f_lk[1005]
    DIRECTION INOUT ;
    USE SIGNAL ;
    PORT
      LAYER M4 ;
        RECT 2599.808 807.312 2600.000 807.336 ;
    END
  END f_lk[1005]
  PIN f_lk[1006]
    DIRECTION INOUT ;
    USE SIGNAL ;
    PORT
      LAYER M4 ;
        RECT 2599.808 807.504 2600.000 807.528 ;
    END
  END f_lk[1006]
  PIN f_lk[1007]
    DIRECTION INOUT ;
    USE SIGNAL ;
    PORT
      LAYER M4 ;
        RECT 2599.808 807.696 2600.000 807.720 ;
    END
  END f_lk[1007]
  PIN f_lk[1008]
    DIRECTION INOUT ;
    USE SIGNAL ;
    PORT
      LAYER M4 ;
        RECT 2599.808 807.888 2600.000 807.912 ;
    END
  END f_lk[1008]
  PIN f_lk[1009]
    DIRECTION INOUT ;
    USE SIGNAL ;
    PORT
      LAYER M4 ;
        RECT 2599.808 808.080 2600.000 808.104 ;
    END
  END f_lk[1009]
  PIN f_lk[1010]
    DIRECTION INOUT ;
    USE SIGNAL ;
    PORT
      LAYER M4 ;
        RECT 2599.808 808.272 2600.000 808.296 ;
    END
  END f_lk[1010]
  PIN f_lk[1011]
    DIRECTION INOUT ;
    USE SIGNAL ;
    PORT
      LAYER M4 ;
        RECT 2599.808 808.464 2600.000 808.488 ;
    END
  END f_lk[1011]
  PIN f_lk[1012]
    DIRECTION INOUT ;
    USE SIGNAL ;
    PORT
      LAYER M4 ;
        RECT 2599.808 808.656 2600.000 808.680 ;
    END
  END f_lk[1012]
  PIN f_lk[1013]
    DIRECTION INOUT ;
    USE SIGNAL ;
    PORT
      LAYER M4 ;
        RECT 2599.808 808.848 2600.000 808.872 ;
    END
  END f_lk[1013]
  PIN f_lk[1014]
    DIRECTION INOUT ;
    USE SIGNAL ;
    PORT
      LAYER M4 ;
        RECT 2599.808 809.040 2600.000 809.064 ;
    END
  END f_lk[1014]
  PIN f_lk[1015]
    DIRECTION INOUT ;
    USE SIGNAL ;
    PORT
      LAYER M4 ;
        RECT 2599.808 809.232 2600.000 809.256 ;
    END
  END f_lk[1015]
  PIN f_lk[1016]
    DIRECTION INOUT ;
    USE SIGNAL ;
    PORT
      LAYER M4 ;
        RECT 2599.808 809.424 2600.000 809.448 ;
    END
  END f_lk[1016]
  PIN f_lk[1017]
    DIRECTION INOUT ;
    USE SIGNAL ;
    PORT
      LAYER M4 ;
        RECT 2599.808 809.616 2600.000 809.640 ;
    END
  END f_lk[1017]
  PIN f_lk[1018]
    DIRECTION INOUT ;
    USE SIGNAL ;
    PORT
      LAYER M4 ;
        RECT 2599.808 809.808 2600.000 809.832 ;
    END
  END f_lk[1018]
  PIN f_lk[1019]
    DIRECTION INOUT ;
    USE SIGNAL ;
    PORT
      LAYER M4 ;
        RECT 2599.808 810.000 2600.000 810.024 ;
    END
  END f_lk[1019]
  PIN f_lk[1020]
    DIRECTION INOUT ;
    USE SIGNAL ;
    PORT
      LAYER M4 ;
        RECT 2599.808 810.192 2600.000 810.216 ;
    END
  END f_lk[1020]
  PIN f_lk[1021]
    DIRECTION INOUT ;
    USE SIGNAL ;
    PORT
      LAYER M4 ;
        RECT 2599.808 810.384 2600.000 810.408 ;
    END
  END f_lk[1021]
  PIN f_lk[1022]
    DIRECTION INOUT ;
    USE SIGNAL ;
    PORT
      LAYER M4 ;
        RECT 2599.808 810.576 2600.000 810.600 ;
    END
  END f_lk[1022]
  PIN f_lk[1023]
    DIRECTION INOUT ;
    USE SIGNAL ;
    PORT
      LAYER M4 ;
        RECT 2599.808 810.768 2600.000 810.792 ;
    END
  END f_lk[1023]
  PIN f_lk[1024]
    DIRECTION INOUT ;
    USE SIGNAL ;
    PORT
      LAYER M4 ;
        RECT 2599.808 810.960 2600.000 810.984 ;
    END
  END f_lk[1024]
  PIN f_lk[1025]
    DIRECTION INOUT ;
    USE SIGNAL ;
    PORT
      LAYER M4 ;
        RECT 2599.808 811.152 2600.000 811.176 ;
    END
  END f_lk[1025]
  PIN f_lk[1026]
    DIRECTION INOUT ;
    USE SIGNAL ;
    PORT
      LAYER M4 ;
        RECT 2599.808 811.344 2600.000 811.368 ;
    END
  END f_lk[1026]
  PIN f_lk[1027]
    DIRECTION INOUT ;
    USE SIGNAL ;
    PORT
      LAYER M4 ;
        RECT 2599.808 811.536 2600.000 811.560 ;
    END
  END f_lk[1027]
  PIN f_lk[1028]
    DIRECTION INOUT ;
    USE SIGNAL ;
    PORT
      LAYER M4 ;
        RECT 2599.808 811.728 2600.000 811.752 ;
    END
  END f_lk[1028]
  PIN f_lk[1029]
    DIRECTION INOUT ;
    USE SIGNAL ;
    PORT
      LAYER M4 ;
        RECT 2599.808 811.920 2600.000 811.944 ;
    END
  END f_lk[1029]
  PIN f_lk[1030]
    DIRECTION INOUT ;
    USE SIGNAL ;
    PORT
      LAYER M4 ;
        RECT 2599.808 812.112 2600.000 812.136 ;
    END
  END f_lk[1030]
  PIN f_lk[1031]
    DIRECTION INOUT ;
    USE SIGNAL ;
    PORT
      LAYER M4 ;
        RECT 2599.808 812.304 2600.000 812.328 ;
    END
  END f_lk[1031]
  PIN f_lk[1032]
    DIRECTION INOUT ;
    USE SIGNAL ;
    PORT
      LAYER M4 ;
        RECT 2599.808 812.496 2600.000 812.520 ;
    END
  END f_lk[1032]
  PIN f_lk[1033]
    DIRECTION INOUT ;
    USE SIGNAL ;
    PORT
      LAYER M4 ;
        RECT 2599.808 812.688 2600.000 812.712 ;
    END
  END f_lk[1033]
  PIN f_lk[1034]
    DIRECTION INOUT ;
    USE SIGNAL ;
    PORT
      LAYER M4 ;
        RECT 2599.808 812.880 2600.000 812.904 ;
    END
  END f_lk[1034]
  PIN f_lk[1035]
    DIRECTION INOUT ;
    USE SIGNAL ;
    PORT
      LAYER M4 ;
        RECT 2599.808 813.072 2600.000 813.096 ;
    END
  END f_lk[1035]
  PIN f_lk[1036]
    DIRECTION INOUT ;
    USE SIGNAL ;
    PORT
      LAYER M4 ;
        RECT 2599.808 813.264 2600.000 813.288 ;
    END
  END f_lk[1036]
  PIN f_lk[1037]
    DIRECTION INOUT ;
    USE SIGNAL ;
    PORT
      LAYER M4 ;
        RECT 2599.808 813.456 2600.000 813.480 ;
    END
  END f_lk[1037]
  PIN f_lk[1038]
    DIRECTION INOUT ;
    USE SIGNAL ;
    PORT
      LAYER M4 ;
        RECT 2599.808 813.648 2600.000 813.672 ;
    END
  END f_lk[1038]
  PIN f_lk[1039]
    DIRECTION INOUT ;
    USE SIGNAL ;
    PORT
      LAYER M4 ;
        RECT 2599.808 813.840 2600.000 813.864 ;
    END
  END f_lk[1039]
  PIN f_lk[1040]
    DIRECTION INOUT ;
    USE SIGNAL ;
    PORT
      LAYER M4 ;
        RECT 2599.808 814.032 2600.000 814.056 ;
    END
  END f_lk[1040]
  PIN f_lk[1041]
    DIRECTION INOUT ;
    USE SIGNAL ;
    PORT
      LAYER M4 ;
        RECT 2599.808 814.224 2600.000 814.248 ;
    END
  END f_lk[1041]
  PIN f_lk[1042]
    DIRECTION INOUT ;
    USE SIGNAL ;
    PORT
      LAYER M4 ;
        RECT 2599.808 814.416 2600.000 814.440 ;
    END
  END f_lk[1042]
  PIN f_lk[1043]
    DIRECTION INOUT ;
    USE SIGNAL ;
    PORT
      LAYER M4 ;
        RECT 2599.808 814.608 2600.000 814.632 ;
    END
  END f_lk[1043]
  PIN f_lk[1044]
    DIRECTION INOUT ;
    USE SIGNAL ;
    PORT
      LAYER M4 ;
        RECT 2599.808 814.800 2600.000 814.824 ;
    END
  END f_lk[1044]
  PIN f_lk[1045]
    DIRECTION INOUT ;
    USE SIGNAL ;
    PORT
      LAYER M4 ;
        RECT 2599.808 814.992 2600.000 815.016 ;
    END
  END f_lk[1045]
  PIN f_lk[1046]
    DIRECTION INOUT ;
    USE SIGNAL ;
    PORT
      LAYER M4 ;
        RECT 2599.808 815.184 2600.000 815.208 ;
    END
  END f_lk[1046]
  PIN f_lk[1047]
    DIRECTION INOUT ;
    USE SIGNAL ;
    PORT
      LAYER M4 ;
        RECT 2599.808 815.376 2600.000 815.400 ;
    END
  END f_lk[1047]
  PIN f_lk[1048]
    DIRECTION INOUT ;
    USE SIGNAL ;
    PORT
      LAYER M4 ;
        RECT 2599.808 815.568 2600.000 815.592 ;
    END
  END f_lk[1048]
  PIN f_lk[1049]
    DIRECTION INOUT ;
    USE SIGNAL ;
    PORT
      LAYER M4 ;
        RECT 2599.808 815.760 2600.000 815.784 ;
    END
  END f_lk[1049]
  PIN f_lk[1050]
    DIRECTION INOUT ;
    USE SIGNAL ;
    PORT
      LAYER M4 ;
        RECT 2599.808 815.952 2600.000 815.976 ;
    END
  END f_lk[1050]
  PIN f_lk[1051]
    DIRECTION INOUT ;
    USE SIGNAL ;
    PORT
      LAYER M4 ;
        RECT 2599.808 816.144 2600.000 816.168 ;
    END
  END f_lk[1051]
  PIN f_lk[1052]
    DIRECTION INOUT ;
    USE SIGNAL ;
    PORT
      LAYER M4 ;
        RECT 2599.808 816.336 2600.000 816.360 ;
    END
  END f_lk[1052]
  PIN f_lk[1053]
    DIRECTION INOUT ;
    USE SIGNAL ;
    PORT
      LAYER M4 ;
        RECT 2599.808 816.528 2600.000 816.552 ;
    END
  END f_lk[1053]
  PIN f_lk[1054]
    DIRECTION INOUT ;
    USE SIGNAL ;
    PORT
      LAYER M4 ;
        RECT 2599.808 816.720 2600.000 816.744 ;
    END
  END f_lk[1054]
  PIN f_lk[1055]
    DIRECTION INOUT ;
    USE SIGNAL ;
    PORT
      LAYER M4 ;
        RECT 2599.808 816.912 2600.000 816.936 ;
    END
  END f_lk[1055]
  PIN f_lk[1056]
    DIRECTION INOUT ;
    USE SIGNAL ;
    PORT
      LAYER M4 ;
        RECT 2599.808 817.104 2600.000 817.128 ;
    END
  END f_lk[1056]
  PIN f_lk[1057]
    DIRECTION INOUT ;
    USE SIGNAL ;
    PORT
      LAYER M4 ;
        RECT 2599.808 817.296 2600.000 817.320 ;
    END
  END f_lk[1057]
  PIN f_lk[1058]
    DIRECTION INOUT ;
    USE SIGNAL ;
    PORT
      LAYER M4 ;
        RECT 2599.808 817.488 2600.000 817.512 ;
    END
  END f_lk[1058]
  PIN f_lk[1059]
    DIRECTION INOUT ;
    USE SIGNAL ;
    PORT
      LAYER M4 ;
        RECT 2599.808 817.680 2600.000 817.704 ;
    END
  END f_lk[1059]
  PIN f_lk[1060]
    DIRECTION INOUT ;
    USE SIGNAL ;
    PORT
      LAYER M4 ;
        RECT 2599.808 817.872 2600.000 817.896 ;
    END
  END f_lk[1060]
  PIN f_lk[1061]
    DIRECTION INOUT ;
    USE SIGNAL ;
    PORT
      LAYER M4 ;
        RECT 2599.808 818.064 2600.000 818.088 ;
    END
  END f_lk[1061]
  PIN f_lk[1062]
    DIRECTION INOUT ;
    USE SIGNAL ;
    PORT
      LAYER M4 ;
        RECT 2599.808 818.256 2600.000 818.280 ;
    END
  END f_lk[1062]
  PIN f_lk[1063]
    DIRECTION INOUT ;
    USE SIGNAL ;
    PORT
      LAYER M4 ;
        RECT 2599.808 818.448 2600.000 818.472 ;
    END
  END f_lk[1063]
  PIN f_lk[1064]
    DIRECTION INOUT ;
    USE SIGNAL ;
    PORT
      LAYER M4 ;
        RECT 2599.808 818.640 2600.000 818.664 ;
    END
  END f_lk[1064]
  PIN f_lk[1065]
    DIRECTION INOUT ;
    USE SIGNAL ;
    PORT
      LAYER M4 ;
        RECT 2599.808 818.832 2600.000 818.856 ;
    END
  END f_lk[1065]
  PIN f_lk[1066]
    DIRECTION INOUT ;
    USE SIGNAL ;
    PORT
      LAYER M4 ;
        RECT 2599.808 819.024 2600.000 819.048 ;
    END
  END f_lk[1066]
  PIN f_lk[1067]
    DIRECTION INOUT ;
    USE SIGNAL ;
    PORT
      LAYER M4 ;
        RECT 2599.808 819.216 2600.000 819.240 ;
    END
  END f_lk[1067]
  PIN f_lk[1068]
    DIRECTION INOUT ;
    USE SIGNAL ;
    PORT
      LAYER M4 ;
        RECT 2599.808 819.408 2600.000 819.432 ;
    END
  END f_lk[1068]
  PIN f_lk[1069]
    DIRECTION INOUT ;
    USE SIGNAL ;
    PORT
      LAYER M4 ;
        RECT 2599.808 819.600 2600.000 819.624 ;
    END
  END f_lk[1069]
  PIN f_lk[1070]
    DIRECTION INOUT ;
    USE SIGNAL ;
    PORT
      LAYER M4 ;
        RECT 2599.808 819.792 2600.000 819.816 ;
    END
  END f_lk[1070]
  PIN f_lk[1071]
    DIRECTION INOUT ;
    USE SIGNAL ;
    PORT
      LAYER M4 ;
        RECT 2599.808 819.984 2600.000 820.008 ;
    END
  END f_lk[1071]
  PIN f_lk[1072]
    DIRECTION INOUT ;
    USE SIGNAL ;
    PORT
      LAYER M4 ;
        RECT 2599.808 820.176 2600.000 820.200 ;
    END
  END f_lk[1072]
  PIN f_lk[1073]
    DIRECTION INOUT ;
    USE SIGNAL ;
    PORT
      LAYER M4 ;
        RECT 2599.808 820.368 2600.000 820.392 ;
    END
  END f_lk[1073]
  PIN f_lk[1074]
    DIRECTION INOUT ;
    USE SIGNAL ;
    PORT
      LAYER M4 ;
        RECT 2599.808 820.560 2600.000 820.584 ;
    END
  END f_lk[1074]
  PIN f_lk[1075]
    DIRECTION INOUT ;
    USE SIGNAL ;
    PORT
      LAYER M4 ;
        RECT 2599.808 820.752 2600.000 820.776 ;
    END
  END f_lk[1075]
  PIN f_lk[1076]
    DIRECTION INOUT ;
    USE SIGNAL ;
    PORT
      LAYER M4 ;
        RECT 2599.808 820.944 2600.000 820.968 ;
    END
  END f_lk[1076]
  PIN f_lk[1077]
    DIRECTION INOUT ;
    USE SIGNAL ;
    PORT
      LAYER M4 ;
        RECT 2599.808 821.136 2600.000 821.160 ;
    END
  END f_lk[1077]
  PIN f_lk[1078]
    DIRECTION INOUT ;
    USE SIGNAL ;
    PORT
      LAYER M4 ;
        RECT 2599.808 821.328 2600.000 821.352 ;
    END
  END f_lk[1078]
  PIN f_lk[1079]
    DIRECTION INOUT ;
    USE SIGNAL ;
    PORT
      LAYER M4 ;
        RECT 2599.808 821.520 2600.000 821.544 ;
    END
  END f_lk[1079]
  PIN f_lk[1080]
    DIRECTION INOUT ;
    USE SIGNAL ;
    PORT
      LAYER M4 ;
        RECT 2599.808 821.712 2600.000 821.736 ;
    END
  END f_lk[1080]
  PIN f_lk[1081]
    DIRECTION INOUT ;
    USE SIGNAL ;
    PORT
      LAYER M4 ;
        RECT 2599.808 821.904 2600.000 821.928 ;
    END
  END f_lk[1081]
  PIN f_lk[1082]
    DIRECTION INOUT ;
    USE SIGNAL ;
    PORT
      LAYER M4 ;
        RECT 2599.808 822.096 2600.000 822.120 ;
    END
  END f_lk[1082]
  PIN f_lk[1083]
    DIRECTION INOUT ;
    USE SIGNAL ;
    PORT
      LAYER M4 ;
        RECT 2599.808 822.288 2600.000 822.312 ;
    END
  END f_lk[1083]
  PIN f_lk[1084]
    DIRECTION INOUT ;
    USE SIGNAL ;
    PORT
      LAYER M4 ;
        RECT 2599.808 822.480 2600.000 822.504 ;
    END
  END f_lk[1084]
  PIN f_lk[1085]
    DIRECTION INOUT ;
    USE SIGNAL ;
    PORT
      LAYER M4 ;
        RECT 2599.808 822.672 2600.000 822.696 ;
    END
  END f_lk[1085]
  PIN f_lk[1086]
    DIRECTION INOUT ;
    USE SIGNAL ;
    PORT
      LAYER M4 ;
        RECT 2599.808 822.864 2600.000 822.888 ;
    END
  END f_lk[1086]
  PIN f_lk[1087]
    DIRECTION INOUT ;
    USE SIGNAL ;
    PORT
      LAYER M4 ;
        RECT 2599.808 823.056 2600.000 823.080 ;
    END
  END f_lk[1087]
  PIN f_lk[1088]
    DIRECTION INOUT ;
    USE SIGNAL ;
    PORT
      LAYER M4 ;
        RECT 2599.808 823.248 2600.000 823.272 ;
    END
  END f_lk[1088]
  PIN f_lk[1089]
    DIRECTION INOUT ;
    USE SIGNAL ;
    PORT
      LAYER M4 ;
        RECT 2599.808 823.440 2600.000 823.464 ;
    END
  END f_lk[1089]
  PIN f_lk[1090]
    DIRECTION INOUT ;
    USE SIGNAL ;
    PORT
      LAYER M4 ;
        RECT 2599.808 823.632 2600.000 823.656 ;
    END
  END f_lk[1090]
  PIN f_lk[1091]
    DIRECTION INOUT ;
    USE SIGNAL ;
    PORT
      LAYER M4 ;
        RECT 2599.808 823.824 2600.000 823.848 ;
    END
  END f_lk[1091]
  PIN f_lk[1092]
    DIRECTION INOUT ;
    USE SIGNAL ;
    PORT
      LAYER M4 ;
        RECT 2599.808 824.016 2600.000 824.040 ;
    END
  END f_lk[1092]
  PIN f_lk[1093]
    DIRECTION INOUT ;
    USE SIGNAL ;
    PORT
      LAYER M4 ;
        RECT 2599.808 824.208 2600.000 824.232 ;
    END
  END f_lk[1093]
  PIN f_lk[1094]
    DIRECTION INOUT ;
    USE SIGNAL ;
    PORT
      LAYER M4 ;
        RECT 2599.808 824.400 2600.000 824.424 ;
    END
  END f_lk[1094]
  PIN f_lk[1095]
    DIRECTION INOUT ;
    USE SIGNAL ;
    PORT
      LAYER M4 ;
        RECT 2599.808 824.592 2600.000 824.616 ;
    END
  END f_lk[1095]
  PIN f_lk[1096]
    DIRECTION INOUT ;
    USE SIGNAL ;
    PORT
      LAYER M4 ;
        RECT 2599.808 824.784 2600.000 824.808 ;
    END
  END f_lk[1096]
  PIN f_lk[1097]
    DIRECTION INOUT ;
    USE SIGNAL ;
    PORT
      LAYER M4 ;
        RECT 2599.808 824.976 2600.000 825.000 ;
    END
  END f_lk[1097]
  PIN f_lk[1098]
    DIRECTION INOUT ;
    USE SIGNAL ;
    PORT
      LAYER M4 ;
        RECT 2599.808 825.168 2600.000 825.192 ;
    END
  END f_lk[1098]
  PIN f_lk[1099]
    DIRECTION INOUT ;
    USE SIGNAL ;
    PORT
      LAYER M4 ;
        RECT 2599.808 825.360 2600.000 825.384 ;
    END
  END f_lk[1099]
  PIN f_lk[1100]
    DIRECTION INOUT ;
    USE SIGNAL ;
    PORT
      LAYER M4 ;
        RECT 2599.808 825.552 2600.000 825.576 ;
    END
  END f_lk[1100]
  PIN f_lk[1101]
    DIRECTION INOUT ;
    USE SIGNAL ;
    PORT
      LAYER M4 ;
        RECT 2599.808 825.744 2600.000 825.768 ;
    END
  END f_lk[1101]
  PIN f_lk[1102]
    DIRECTION INOUT ;
    USE SIGNAL ;
    PORT
      LAYER M4 ;
        RECT 2599.808 825.936 2600.000 825.960 ;
    END
  END f_lk[1102]
  PIN f_lk[1103]
    DIRECTION INOUT ;
    USE SIGNAL ;
    PORT
      LAYER M4 ;
        RECT 2599.808 826.128 2600.000 826.152 ;
    END
  END f_lk[1103]
  PIN f_lk[1104]
    DIRECTION INOUT ;
    USE SIGNAL ;
    PORT
      LAYER M4 ;
        RECT 2599.808 826.320 2600.000 826.344 ;
    END
  END f_lk[1104]
  PIN f_lk[1105]
    DIRECTION INOUT ;
    USE SIGNAL ;
    PORT
      LAYER M4 ;
        RECT 2599.808 826.512 2600.000 826.536 ;
    END
  END f_lk[1105]
  PIN f_lk[1106]
    DIRECTION INOUT ;
    USE SIGNAL ;
    PORT
      LAYER M4 ;
        RECT 2599.808 826.704 2600.000 826.728 ;
    END
  END f_lk[1106]
  PIN f_lk[1107]
    DIRECTION INOUT ;
    USE SIGNAL ;
    PORT
      LAYER M4 ;
        RECT 2599.808 826.896 2600.000 826.920 ;
    END
  END f_lk[1107]
  PIN f_lk[1108]
    DIRECTION INOUT ;
    USE SIGNAL ;
    PORT
      LAYER M4 ;
        RECT 2599.808 827.088 2600.000 827.112 ;
    END
  END f_lk[1108]
  PIN f_lk[1109]
    DIRECTION INOUT ;
    USE SIGNAL ;
    PORT
      LAYER M4 ;
        RECT 2599.808 827.280 2600.000 827.304 ;
    END
  END f_lk[1109]
  PIN f_lk[1110]
    DIRECTION INOUT ;
    USE SIGNAL ;
    PORT
      LAYER M4 ;
        RECT 2599.808 827.472 2600.000 827.496 ;
    END
  END f_lk[1110]
  PIN f_lk[1111]
    DIRECTION INOUT ;
    USE SIGNAL ;
    PORT
      LAYER M4 ;
        RECT 2599.808 827.664 2600.000 827.688 ;
    END
  END f_lk[1111]
  PIN f_lk[1112]
    DIRECTION INOUT ;
    USE SIGNAL ;
    PORT
      LAYER M4 ;
        RECT 2599.808 827.856 2600.000 827.880 ;
    END
  END f_lk[1112]
  PIN f_lk[1113]
    DIRECTION INOUT ;
    USE SIGNAL ;
    PORT
      LAYER M4 ;
        RECT 2599.808 828.048 2600.000 828.072 ;
    END
  END f_lk[1113]
  PIN f_lk[1114]
    DIRECTION INOUT ;
    USE SIGNAL ;
    PORT
      LAYER M4 ;
        RECT 2599.808 828.240 2600.000 828.264 ;
    END
  END f_lk[1114]
  PIN f_lk[1115]
    DIRECTION INOUT ;
    USE SIGNAL ;
    PORT
      LAYER M4 ;
        RECT 2599.808 828.432 2600.000 828.456 ;
    END
  END f_lk[1115]
  PIN f_lk[1116]
    DIRECTION INOUT ;
    USE SIGNAL ;
    PORT
      LAYER M4 ;
        RECT 2599.808 828.624 2600.000 828.648 ;
    END
  END f_lk[1116]
  PIN f_lk[1117]
    DIRECTION INOUT ;
    USE SIGNAL ;
    PORT
      LAYER M4 ;
        RECT 2599.808 828.816 2600.000 828.840 ;
    END
  END f_lk[1117]
  PIN f_lk[1118]
    DIRECTION INOUT ;
    USE SIGNAL ;
    PORT
      LAYER M4 ;
        RECT 2599.808 829.008 2600.000 829.032 ;
    END
  END f_lk[1118]
  PIN f_lk[1119]
    DIRECTION INOUT ;
    USE SIGNAL ;
    PORT
      LAYER M4 ;
        RECT 2599.808 829.200 2600.000 829.224 ;
    END
  END f_lk[1119]
  PIN clk[0]
    DIRECTION INOUT ;
    USE SIGNAL ;
    PORT
      LAYER M5 ;
        RECT 2598.816 829.808 2598.840 830.000 ;
    END
  END clk[0]
  PIN rst_n[0]
    DIRECTION INOUT ;
    USE SIGNAL ;
    PORT
      LAYER M5 ;
        RECT 2599.200 829.808 2599.224 830.000 ;
    END
  END rst_n[0]
  OBS
    LAYER M1 ;
      RECT 0 0 2600.000 830.000 ;
    LAYER M2 ;
      RECT 0 0 2600.000 830.000 ;
    LAYER M3 ;
      RECT 0 0 2600.000 830.000 ;
    LAYER M4 ;
      RECT 0 0 2600.000 830.000 ;
    LAYER M5 ;
      RECT 0 0 2600.000 830.000 ;
    LAYER M6 ;
      RECT 0 0 2600.000 830.000 ;
    LAYER M7 ;
      RECT 0 0 2600.000 830.000 ;
  END
END hfd_lk_ep
